VERSION 5.8 ;
BUSBITCHARS "[]" ;
DIVIDERCHAR "/" ;
UNITS
    DATABASE MICRONS 1000 ;
END UNITS

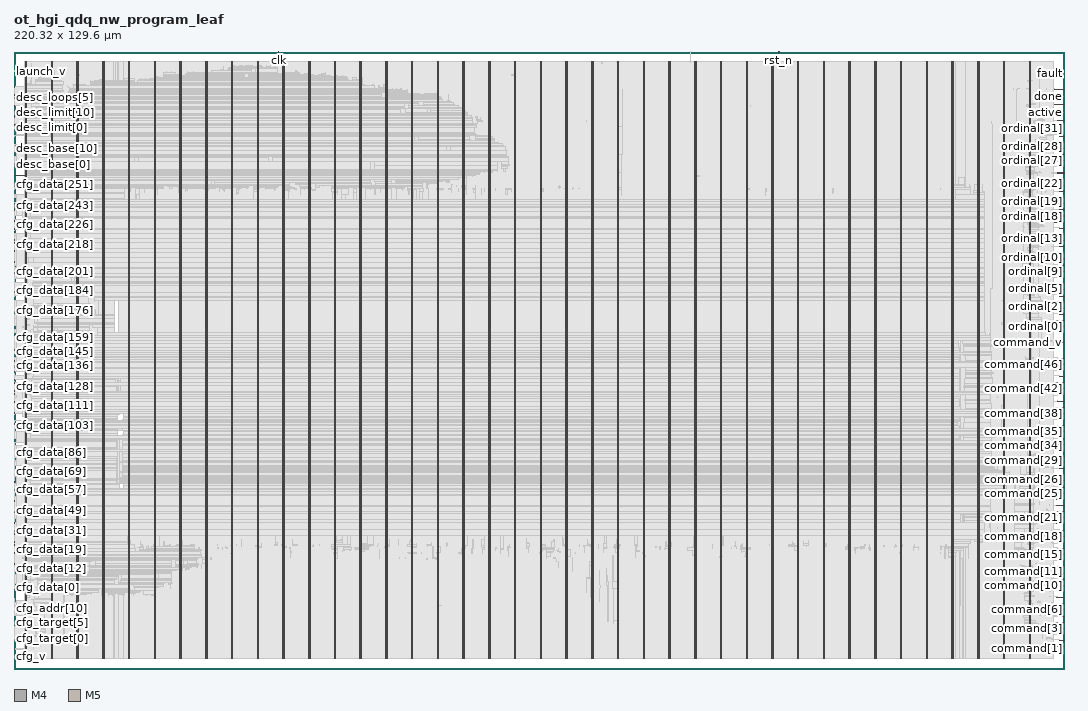
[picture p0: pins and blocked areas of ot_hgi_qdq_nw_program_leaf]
MACRO ot_hgi_qdq_nw_program_leaf
  FOREIGN ot_hgi_qdq_nw_program_leaf 0 0 ;
  CLASS BLOCK ;
  SIZE 220.32 BY 129.6 ;
  PIN active
    DIRECTION OUTPUT ;
    USE SIGNAL ;
    PORT
      LAYER M4 ;
        RECT  220.236 115.056 220.32 115.08 ;
    END
    PORT
      LAYER M4 ;
        RECT  218.869 115.056 220.284 115.08 ;
    END
  END active
  PIN cfg_addr[0]
    DIRECTION INPUT ;
    USE SIGNAL ;
    PORT
      LAYER M4 ;
        RECT  0 11.136 0.084 11.16 ;
    END
  END cfg_addr[0]
  PIN cfg_addr[10]
    DIRECTION INPUT ;
    USE SIGNAL ;
    PORT
      LAYER M4 ;
        RECT  0 14.4 0.084 14.424 ;
    END
  END cfg_addr[10]
  PIN cfg_addr[11]
    DIRECTION INPUT ;
    USE SIGNAL ;
    PORT
      LAYER M4 ;
        RECT  0 14.736 0.084 14.76 ;
    END
  END cfg_addr[11]
  PIN cfg_addr[1]
    DIRECTION INPUT ;
    USE SIGNAL ;
    PORT
      LAYER M4 ;
        RECT  0 11.472 0.084 11.496 ;
    END
  END cfg_addr[1]
  PIN cfg_addr[2]
    DIRECTION INPUT ;
    USE SIGNAL ;
    PORT
      LAYER M4 ;
        RECT  0 11.76 0.084 11.784 ;
    END
  END cfg_addr[2]
  PIN cfg_addr[3]
    DIRECTION INPUT ;
    USE SIGNAL ;
    PORT
      LAYER M4 ;
        RECT  0 12.096 0.084 12.12 ;
    END
  END cfg_addr[3]
  PIN cfg_addr[4]
    DIRECTION INPUT ;
    USE SIGNAL ;
    PORT
      LAYER M4 ;
        RECT  0 12.432 0.084 12.456 ;
    END
  END cfg_addr[4]
  PIN cfg_addr[5]
    DIRECTION INPUT ;
    USE SIGNAL ;
    PORT
      LAYER M4 ;
        RECT  0 12.768 0.084 12.792 ;
    END
  END cfg_addr[5]
  PIN cfg_addr[6]
    DIRECTION INPUT ;
    USE SIGNAL ;
    PORT
      LAYER M4 ;
        RECT  0 13.104 0.084 13.128 ;
    END
  END cfg_addr[6]
  PIN cfg_addr[7]
    DIRECTION INPUT ;
    USE SIGNAL ;
    PORT
      LAYER M4 ;
        RECT  0 13.44 0.084 13.464 ;
    END
  END cfg_addr[7]
  PIN cfg_addr[8]
    DIRECTION INPUT ;
    USE SIGNAL ;
    PORT
      LAYER M4 ;
        RECT  0 13.776 0.084 13.8 ;
    END
  END cfg_addr[8]
  PIN cfg_addr[9]
    DIRECTION INPUT ;
    USE SIGNAL ;
    PORT
      LAYER M4 ;
        RECT  0 14.112 0.084 14.136 ;
    END
  END cfg_addr[9]
  PIN cfg_data[0]
    DIRECTION INPUT ;
    USE SIGNAL ;
    PORT
      LAYER M4 ;
        RECT  0 17.088 0.084 17.112 ;
    END
  END cfg_data[0]
  PIN cfg_data[100]
    DIRECTION INPUT ;
    USE SIGNAL ;
    PORT
      LAYER M4 ;
        RECT  0 50.064 0.084 50.088 ;
    END
  END cfg_data[100]
  PIN cfg_data[101]
    DIRECTION INPUT ;
    USE SIGNAL ;
    PORT
      LAYER M4 ;
        RECT  0 50.4 0.084 50.424 ;
    END
  END cfg_data[101]
  PIN cfg_data[102]
    DIRECTION INPUT ;
    USE SIGNAL ;
    PORT
      LAYER M4 ;
        RECT  0 50.736 0.084 50.76 ;
    END
  END cfg_data[102]
  PIN cfg_data[103]
    DIRECTION INPUT ;
    USE SIGNAL ;
    PORT
      LAYER M4 ;
        RECT  0 51.072 0.084 51.096 ;
    END
  END cfg_data[103]
  PIN cfg_data[104]
    DIRECTION INPUT ;
    USE SIGNAL ;
    PORT
      LAYER M4 ;
        RECT  0 51.408 0.084 51.432 ;
    END
  END cfg_data[104]
  PIN cfg_data[105]
    DIRECTION INPUT ;
    USE SIGNAL ;
    PORT
      LAYER M4 ;
        RECT  0 51.744 0.084 51.768 ;
    END
  END cfg_data[105]
  PIN cfg_data[106]
    DIRECTION INPUT ;
    USE SIGNAL ;
    PORT
      LAYER M4 ;
        RECT  0 52.08 0.084 52.104 ;
    END
  END cfg_data[106]
  PIN cfg_data[107]
    DIRECTION INPUT ;
    USE SIGNAL ;
    PORT
      LAYER M4 ;
        RECT  0 52.416 0.084 52.44 ;
    END
  END cfg_data[107]
  PIN cfg_data[108]
    DIRECTION INPUT ;
    USE SIGNAL ;
    PORT
      LAYER M4 ;
        RECT  0 52.704 0.084 52.728 ;
    END
  END cfg_data[108]
  PIN cfg_data[109]
    DIRECTION INPUT ;
    USE SIGNAL ;
    PORT
      LAYER M4 ;
        RECT  0 53.04 0.084 53.064 ;
    END
  END cfg_data[109]
  PIN cfg_data[10]
    DIRECTION INPUT ;
    USE SIGNAL ;
    PORT
      LAYER M4 ;
        RECT  0 20.4 0.084 20.424 ;
    END
  END cfg_data[10]
  PIN cfg_data[110]
    DIRECTION INPUT ;
    USE SIGNAL ;
    PORT
      LAYER M4 ;
        RECT  0 53.376 0.084 53.4 ;
    END
  END cfg_data[110]
  PIN cfg_data[111]
    DIRECTION INPUT ;
    USE SIGNAL ;
    PORT
      LAYER M4 ;
        RECT  0 53.712 0.084 53.736 ;
    END
  END cfg_data[111]
  PIN cfg_data[112]
    DIRECTION INPUT ;
    USE SIGNAL ;
    PORT
      LAYER M4 ;
        RECT  0 54.048 0.084 54.072 ;
    END
  END cfg_data[112]
  PIN cfg_data[113]
    DIRECTION INPUT ;
    USE SIGNAL ;
    PORT
      LAYER M4 ;
        RECT  0 54.384 0.084 54.408 ;
    END
  END cfg_data[113]
  PIN cfg_data[114]
    DIRECTION INPUT ;
    USE SIGNAL ;
    PORT
      LAYER M4 ;
        RECT  0 54.72 0.084 54.744 ;
    END
  END cfg_data[114]
  PIN cfg_data[115]
    DIRECTION INPUT ;
    USE SIGNAL ;
    PORT
      LAYER M4 ;
        RECT  0 55.056 0.084 55.08 ;
    END
  END cfg_data[115]
  PIN cfg_data[116]
    DIRECTION INPUT ;
    USE SIGNAL ;
    PORT
      LAYER M4 ;
        RECT  0 55.344 0.084 55.368 ;
    END
  END cfg_data[116]
  PIN cfg_data[117]
    DIRECTION INPUT ;
    USE SIGNAL ;
    PORT
      LAYER M4 ;
        RECT  0 55.68 0.084 55.704 ;
    END
  END cfg_data[117]
  PIN cfg_data[118]
    DIRECTION INPUT ;
    USE SIGNAL ;
    PORT
      LAYER M4 ;
        RECT  0 56.016 0.084 56.04 ;
    END
  END cfg_data[118]
  PIN cfg_data[119]
    DIRECTION INPUT ;
    USE SIGNAL ;
    PORT
      LAYER M4 ;
        RECT  0 56.352 0.084 56.376 ;
    END
  END cfg_data[119]
  PIN cfg_data[11]
    DIRECTION INPUT ;
    USE SIGNAL ;
    PORT
      LAYER M4 ;
        RECT  0 20.736 0.084 20.76 ;
    END
  END cfg_data[11]
  PIN cfg_data[120]
    DIRECTION INPUT ;
    USE SIGNAL ;
    PORT
      LAYER M4 ;
        RECT  0 56.688 0.084 56.712 ;
    END
  END cfg_data[120]
  PIN cfg_data[121]
    DIRECTION INPUT ;
    USE SIGNAL ;
    PORT
      LAYER M4 ;
        RECT  0 57.024 0.084 57.048 ;
    END
  END cfg_data[121]
  PIN cfg_data[122]
    DIRECTION INPUT ;
    USE SIGNAL ;
    PORT
      LAYER M4 ;
        RECT  0 57.36 0.084 57.384 ;
    END
  END cfg_data[122]
  PIN cfg_data[123]
    DIRECTION INPUT ;
    USE SIGNAL ;
    PORT
      LAYER M4 ;
        RECT  0 57.696 0.084 57.72 ;
    END
  END cfg_data[123]
  PIN cfg_data[124]
    DIRECTION INPUT ;
    USE SIGNAL ;
    PORT
      LAYER M4 ;
        RECT  0 57.984 0.084 58.008 ;
    END
  END cfg_data[124]
  PIN cfg_data[125]
    DIRECTION INPUT ;
    USE SIGNAL ;
    PORT
      LAYER M4 ;
        RECT  0 58.32 0.084 58.344 ;
    END
  END cfg_data[125]
  PIN cfg_data[126]
    DIRECTION INPUT ;
    USE SIGNAL ;
    PORT
      LAYER M4 ;
        RECT  0 58.656 0.084 58.68 ;
    END
  END cfg_data[126]
  PIN cfg_data[127]
    DIRECTION INPUT ;
    USE SIGNAL ;
    PORT
      LAYER M4 ;
        RECT  0 58.992 0.084 59.016 ;
    END
  END cfg_data[127]
  PIN cfg_data[128]
    DIRECTION INPUT ;
    USE SIGNAL ;
    PORT
      LAYER M4 ;
        RECT  0 59.328 0.084 59.352 ;
    END
  END cfg_data[128]
  PIN cfg_data[129]
    DIRECTION INPUT ;
    USE SIGNAL ;
    PORT
      LAYER M4 ;
        RECT  0 59.664 0.084 59.688 ;
    END
  END cfg_data[129]
  PIN cfg_data[12]
    DIRECTION INPUT ;
    USE SIGNAL ;
    PORT
      LAYER M4 ;
        RECT  0 21.024 0.084 21.048 ;
    END
  END cfg_data[12]
  PIN cfg_data[130]
    DIRECTION INPUT ;
    USE SIGNAL ;
    PORT
      LAYER M4 ;
        RECT  0 60 0.084 60.024 ;
    END
  END cfg_data[130]
  PIN cfg_data[131]
    DIRECTION INPUT ;
    USE SIGNAL ;
    PORT
      LAYER M4 ;
        RECT  0 60.336 0.084 60.36 ;
    END
  END cfg_data[131]
  PIN cfg_data[132]
    DIRECTION INPUT ;
    USE SIGNAL ;
    PORT
      LAYER M4 ;
        RECT  0 60.624 0.084 60.648 ;
    END
  END cfg_data[132]
  PIN cfg_data[133]
    DIRECTION INPUT ;
    USE SIGNAL ;
    PORT
      LAYER M4 ;
        RECT  0 60.96 0.084 60.984 ;
    END
  END cfg_data[133]
  PIN cfg_data[134]
    DIRECTION INPUT ;
    USE SIGNAL ;
    PORT
      LAYER M4 ;
        RECT  0 61.296 0.084 61.32 ;
    END
  END cfg_data[134]
  PIN cfg_data[135]
    DIRECTION INPUT ;
    USE SIGNAL ;
    PORT
      LAYER M4 ;
        RECT  0 61.632 0.084 61.656 ;
    END
  END cfg_data[135]
  PIN cfg_data[136]
    DIRECTION INPUT ;
    USE SIGNAL ;
    PORT
      LAYER M4 ;
        RECT  0 61.968 0.084 61.992 ;
    END
  END cfg_data[136]
  PIN cfg_data[137]
    DIRECTION INPUT ;
    USE SIGNAL ;
    PORT
      LAYER M4 ;
        RECT  0 62.304 0.084 62.328 ;
    END
  END cfg_data[137]
  PIN cfg_data[138]
    DIRECTION INPUT ;
    USE SIGNAL ;
    PORT
      LAYER M4 ;
        RECT  0 62.64 0.084 62.664 ;
    END
  END cfg_data[138]
  PIN cfg_data[139]
    DIRECTION INPUT ;
    USE SIGNAL ;
    PORT
      LAYER M4 ;
        RECT  0 62.976 0.084 63 ;
    END
  END cfg_data[139]
  PIN cfg_data[13]
    DIRECTION INPUT ;
    USE SIGNAL ;
    PORT
      LAYER M4 ;
        RECT  0 21.36 0.084 21.384 ;
    END
  END cfg_data[13]
  PIN cfg_data[140]
    DIRECTION INPUT ;
    USE SIGNAL ;
    PORT
      LAYER M4 ;
        RECT  0 63.264 0.084 63.288 ;
    END
  END cfg_data[140]
  PIN cfg_data[141]
    DIRECTION INPUT ;
    USE SIGNAL ;
    PORT
      LAYER M4 ;
        RECT  0 63.6 0.084 63.624 ;
    END
  END cfg_data[141]
  PIN cfg_data[142]
    DIRECTION INPUT ;
    USE SIGNAL ;
    PORT
      LAYER M4 ;
        RECT  0 63.936 0.084 63.96 ;
    END
  END cfg_data[142]
  PIN cfg_data[143]
    DIRECTION INPUT ;
    USE SIGNAL ;
    PORT
      LAYER M4 ;
        RECT  0 64.272 0.084 64.296 ;
    END
  END cfg_data[143]
  PIN cfg_data[144]
    DIRECTION INPUT ;
    USE SIGNAL ;
    PORT
      LAYER M4 ;
        RECT  0 64.608 0.084 64.632 ;
    END
  END cfg_data[144]
  PIN cfg_data[145]
    DIRECTION INPUT ;
    USE SIGNAL ;
    PORT
      LAYER M4 ;
        RECT  0 64.944 0.084 64.968 ;
    END
  END cfg_data[145]
  PIN cfg_data[146]
    DIRECTION INPUT ;
    USE SIGNAL ;
    PORT
      LAYER M4 ;
        RECT  0 65.28 0.084 65.304 ;
    END
  END cfg_data[146]
  PIN cfg_data[147]
    DIRECTION INPUT ;
    USE SIGNAL ;
    PORT
      LAYER M4 ;
        RECT  0 65.616 0.084 65.64 ;
    END
  END cfg_data[147]
  PIN cfg_data[148]
    DIRECTION INPUT ;
    USE SIGNAL ;
    PORT
      LAYER M4 ;
        RECT  0 65.904 0.084 65.928 ;
    END
  END cfg_data[148]
  PIN cfg_data[149]
    DIRECTION INPUT ;
    USE SIGNAL ;
    PORT
      LAYER M4 ;
        RECT  0 66.24 0.084 66.264 ;
    END
  END cfg_data[149]
  PIN cfg_data[14]
    DIRECTION INPUT ;
    USE SIGNAL ;
    PORT
      LAYER M4 ;
        RECT  0 21.696 0.084 21.72 ;
    END
  END cfg_data[14]
  PIN cfg_data[150]
    DIRECTION INPUT ;
    USE SIGNAL ;
    PORT
      LAYER M4 ;
        RECT  0 66.576 0.084 66.6 ;
    END
  END cfg_data[150]
  PIN cfg_data[151]
    DIRECTION INPUT ;
    USE SIGNAL ;
    PORT
      LAYER M4 ;
        RECT  0 66.912 0.084 66.936 ;
    END
  END cfg_data[151]
  PIN cfg_data[152]
    DIRECTION INPUT ;
    USE SIGNAL ;
    PORT
      LAYER M4 ;
        RECT  0 67.248 0.084 67.272 ;
    END
  END cfg_data[152]
  PIN cfg_data[153]
    DIRECTION INPUT ;
    USE SIGNAL ;
    PORT
      LAYER M4 ;
        RECT  0 67.584 0.084 67.608 ;
    END
  END cfg_data[153]
  PIN cfg_data[154]
    DIRECTION INPUT ;
    USE SIGNAL ;
    PORT
      LAYER M4 ;
        RECT  0 67.92 0.084 67.944 ;
    END
  END cfg_data[154]
  PIN cfg_data[155]
    DIRECTION INPUT ;
    USE SIGNAL ;
    PORT
      LAYER M4 ;
        RECT  0 68.256 0.084 68.28 ;
    END
  END cfg_data[155]
  PIN cfg_data[156]
    DIRECTION INPUT ;
    USE SIGNAL ;
    PORT
      LAYER M4 ;
        RECT  0 68.544 0.084 68.568 ;
    END
  END cfg_data[156]
  PIN cfg_data[157]
    DIRECTION INPUT ;
    USE SIGNAL ;
    PORT
      LAYER M4 ;
        RECT  0 68.88 0.084 68.904 ;
    END
  END cfg_data[157]
  PIN cfg_data[158]
    DIRECTION INPUT ;
    USE SIGNAL ;
    PORT
      LAYER M4 ;
        RECT  0 69.216 0.084 69.24 ;
    END
  END cfg_data[158]
  PIN cfg_data[159]
    DIRECTION INPUT ;
    USE SIGNAL ;
    PORT
      LAYER M4 ;
        RECT  0 69.552 0.084 69.576 ;
    END
  END cfg_data[159]
  PIN cfg_data[15]
    DIRECTION INPUT ;
    USE SIGNAL ;
    PORT
      LAYER M4 ;
        RECT  0 22.032 0.084 22.056 ;
    END
  END cfg_data[15]
  PIN cfg_data[160]
    DIRECTION INPUT ;
    USE SIGNAL ;
    PORT
      LAYER M4 ;
        RECT  0 69.888 0.084 69.912 ;
    END
  END cfg_data[160]
  PIN cfg_data[161]
    DIRECTION INPUT ;
    USE SIGNAL ;
    PORT
      LAYER M4 ;
        RECT  0 70.224 0.084 70.248 ;
    END
  END cfg_data[161]
  PIN cfg_data[162]
    DIRECTION INPUT ;
    USE SIGNAL ;
    PORT
      LAYER M4 ;
        RECT  0 70.56 0.084 70.584 ;
    END
  END cfg_data[162]
  PIN cfg_data[163]
    DIRECTION INPUT ;
    USE SIGNAL ;
    PORT
      LAYER M4 ;
        RECT  0 70.896 0.084 70.92 ;
    END
  END cfg_data[163]
  PIN cfg_data[164]
    DIRECTION INPUT ;
    USE SIGNAL ;
    PORT
      LAYER M4 ;
        RECT  0 71.184 0.084 71.208 ;
    END
  END cfg_data[164]
  PIN cfg_data[165]
    DIRECTION INPUT ;
    USE SIGNAL ;
    PORT
      LAYER M4 ;
        RECT  0 71.52 0.084 71.544 ;
    END
  END cfg_data[165]
  PIN cfg_data[166]
    DIRECTION INPUT ;
    USE SIGNAL ;
    PORT
      LAYER M4 ;
        RECT  0 71.856 0.084 71.88 ;
    END
  END cfg_data[166]
  PIN cfg_data[167]
    DIRECTION INPUT ;
    USE SIGNAL ;
    PORT
      LAYER M4 ;
        RECT  0 72.192 0.084 72.216 ;
    END
  END cfg_data[167]
  PIN cfg_data[168]
    DIRECTION INPUT ;
    USE SIGNAL ;
    PORT
      LAYER M4 ;
        RECT  0 72.528 0.084 72.552 ;
    END
  END cfg_data[168]
  PIN cfg_data[169]
    DIRECTION INPUT ;
    USE SIGNAL ;
    PORT
      LAYER M4 ;
        RECT  0 72.864 0.084 72.888 ;
    END
  END cfg_data[169]
  PIN cfg_data[16]
    DIRECTION INPUT ;
    USE SIGNAL ;
    PORT
      LAYER M4 ;
        RECT  0 22.368 0.084 22.392 ;
    END
  END cfg_data[16]
  PIN cfg_data[170]
    DIRECTION INPUT ;
    USE SIGNAL ;
    PORT
      LAYER M4 ;
        RECT  0 73.2 0.084 73.224 ;
    END
  END cfg_data[170]
  PIN cfg_data[171]
    DIRECTION INPUT ;
    USE SIGNAL ;
    PORT
      LAYER M4 ;
        RECT  0 73.536 0.084 73.56 ;
    END
  END cfg_data[171]
  PIN cfg_data[172]
    DIRECTION INPUT ;
    USE SIGNAL ;
    PORT
      LAYER M4 ;
        RECT  0 73.824 0.084 73.848 ;
    END
  END cfg_data[172]
  PIN cfg_data[173]
    DIRECTION INPUT ;
    USE SIGNAL ;
    PORT
      LAYER M4 ;
        RECT  0 74.16 0.084 74.184 ;
    END
  END cfg_data[173]
  PIN cfg_data[174]
    DIRECTION INPUT ;
    USE SIGNAL ;
    PORT
      LAYER M4 ;
        RECT  0 74.496 0.084 74.52 ;
    END
  END cfg_data[174]
  PIN cfg_data[175]
    DIRECTION INPUT ;
    USE SIGNAL ;
    PORT
      LAYER M4 ;
        RECT  0 74.832 0.084 74.856 ;
    END
  END cfg_data[175]
  PIN cfg_data[176]
    DIRECTION INPUT ;
    USE SIGNAL ;
    PORT
      LAYER M4 ;
        RECT  0 75.168 0.084 75.192 ;
    END
  END cfg_data[176]
  PIN cfg_data[177]
    DIRECTION INPUT ;
    USE SIGNAL ;
    PORT
      LAYER M4 ;
        RECT  0 75.504 0.084 75.528 ;
    END
  END cfg_data[177]
  PIN cfg_data[178]
    DIRECTION INPUT ;
    USE SIGNAL ;
    PORT
      LAYER M4 ;
        RECT  0 75.84 0.084 75.864 ;
    END
  END cfg_data[178]
  PIN cfg_data[179]
    DIRECTION INPUT ;
    USE SIGNAL ;
    PORT
      LAYER M4 ;
        RECT  0 76.176 0.084 76.2 ;
    END
  END cfg_data[179]
  PIN cfg_data[17]
    DIRECTION INPUT ;
    USE SIGNAL ;
    PORT
      LAYER M4 ;
        RECT  0 22.704 0.084 22.728 ;
    END
  END cfg_data[17]
  PIN cfg_data[180]
    DIRECTION INPUT ;
    USE SIGNAL ;
    PORT
      LAYER M4 ;
        RECT  0 76.464 0.084 76.488 ;
    END
  END cfg_data[180]
  PIN cfg_data[181]
    DIRECTION INPUT ;
    USE SIGNAL ;
    PORT
      LAYER M4 ;
        RECT  0 76.8 0.084 76.824 ;
    END
  END cfg_data[181]
  PIN cfg_data[182]
    DIRECTION INPUT ;
    USE SIGNAL ;
    PORT
      LAYER M4 ;
        RECT  0 77.136 0.084 77.16 ;
    END
  END cfg_data[182]
  PIN cfg_data[183]
    DIRECTION INPUT ;
    USE SIGNAL ;
    PORT
      LAYER M4 ;
        RECT  0 77.472 0.084 77.496 ;
    END
  END cfg_data[183]
  PIN cfg_data[184]
    DIRECTION INPUT ;
    USE SIGNAL ;
    PORT
      LAYER M4 ;
        RECT  0 77.808 0.084 77.832 ;
    END
  END cfg_data[184]
  PIN cfg_data[185]
    DIRECTION INPUT ;
    USE SIGNAL ;
    PORT
      LAYER M4 ;
        RECT  0 78.144 0.084 78.168 ;
    END
  END cfg_data[185]
  PIN cfg_data[186]
    DIRECTION INPUT ;
    USE SIGNAL ;
    PORT
      LAYER M4 ;
        RECT  0 78.48 0.084 78.504 ;
    END
  END cfg_data[186]
  PIN cfg_data[187]
    DIRECTION INPUT ;
    USE SIGNAL ;
    PORT
      LAYER M4 ;
        RECT  0 78.816 0.084 78.84 ;
    END
  END cfg_data[187]
  PIN cfg_data[188]
    DIRECTION INPUT ;
    USE SIGNAL ;
    PORT
      LAYER M4 ;
        RECT  0 79.104 0.084 79.128 ;
    END
  END cfg_data[188]
  PIN cfg_data[189]
    DIRECTION INPUT ;
    USE SIGNAL ;
    PORT
      LAYER M4 ;
        RECT  0 79.44 0.084 79.464 ;
    END
  END cfg_data[189]
  PIN cfg_data[18]
    DIRECTION INPUT ;
    USE SIGNAL ;
    PORT
      LAYER M4 ;
        RECT  0 23.04 0.084 23.064 ;
    END
  END cfg_data[18]
  PIN cfg_data[190]
    DIRECTION INPUT ;
    USE SIGNAL ;
    PORT
      LAYER M4 ;
        RECT  0 79.776 0.084 79.8 ;
    END
  END cfg_data[190]
  PIN cfg_data[191]
    DIRECTION INPUT ;
    USE SIGNAL ;
    PORT
      LAYER M4 ;
        RECT  0 80.112 0.084 80.136 ;
    END
  END cfg_data[191]
  PIN cfg_data[192]
    DIRECTION INPUT ;
    USE SIGNAL ;
    PORT
      LAYER M4 ;
        RECT  0 80.448 0.084 80.472 ;
    END
  END cfg_data[192]
  PIN cfg_data[193]
    DIRECTION INPUT ;
    USE SIGNAL ;
    PORT
      LAYER M4 ;
        RECT  0 80.784 0.084 80.808 ;
    END
  END cfg_data[193]
  PIN cfg_data[194]
    DIRECTION INPUT ;
    USE SIGNAL ;
    PORT
      LAYER M4 ;
        RECT  0 81.12 0.084 81.144 ;
    END
  END cfg_data[194]
  PIN cfg_data[195]
    DIRECTION INPUT ;
    USE SIGNAL ;
    PORT
      LAYER M4 ;
        RECT  0 81.456 0.084 81.48 ;
    END
  END cfg_data[195]
  PIN cfg_data[196]
    DIRECTION INPUT ;
    USE SIGNAL ;
    PORT
      LAYER M4 ;
        RECT  0 81.744 0.084 81.768 ;
    END
  END cfg_data[196]
  PIN cfg_data[197]
    DIRECTION INPUT ;
    USE SIGNAL ;
    PORT
      LAYER M4 ;
        RECT  0 82.08 0.084 82.104 ;
    END
  END cfg_data[197]
  PIN cfg_data[198]
    DIRECTION INPUT ;
    USE SIGNAL ;
    PORT
      LAYER M4 ;
        RECT  0 82.416 0.084 82.44 ;
    END
  END cfg_data[198]
  PIN cfg_data[199]
    DIRECTION INPUT ;
    USE SIGNAL ;
    PORT
      LAYER M4 ;
        RECT  0 82.752 0.084 82.776 ;
    END
  END cfg_data[199]
  PIN cfg_data[19]
    DIRECTION INPUT ;
    USE SIGNAL ;
    PORT
      LAYER M4 ;
        RECT  0 23.376 0.084 23.4 ;
    END
  END cfg_data[19]
  PIN cfg_data[1]
    DIRECTION INPUT ;
    USE SIGNAL ;
    PORT
      LAYER M4 ;
        RECT  0 17.424 0.084 17.448 ;
    END
  END cfg_data[1]
  PIN cfg_data[200]
    DIRECTION INPUT ;
    USE SIGNAL ;
    PORT
      LAYER M4 ;
        RECT  0 83.088 0.084 83.112 ;
    END
  END cfg_data[200]
  PIN cfg_data[201]
    DIRECTION INPUT ;
    USE SIGNAL ;
    PORT
      LAYER M4 ;
        RECT  0 83.424 0.084 83.448 ;
    END
  END cfg_data[201]
  PIN cfg_data[202]
    DIRECTION INPUT ;
    USE SIGNAL ;
    PORT
      LAYER M4 ;
        RECT  0 83.76 0.084 83.784 ;
    END
  END cfg_data[202]
  PIN cfg_data[203]
    DIRECTION INPUT ;
    USE SIGNAL ;
    PORT
      LAYER M4 ;
        RECT  0 84.096 0.084 84.12 ;
    END
  END cfg_data[203]
  PIN cfg_data[204]
    DIRECTION INPUT ;
    USE SIGNAL ;
    PORT
      LAYER M4 ;
        RECT  0 84.384 0.084 84.408 ;
    END
  END cfg_data[204]
  PIN cfg_data[205]
    DIRECTION INPUT ;
    USE SIGNAL ;
    PORT
      LAYER M4 ;
        RECT  0 84.72 0.084 84.744 ;
    END
  END cfg_data[205]
  PIN cfg_data[206]
    DIRECTION INPUT ;
    USE SIGNAL ;
    PORT
      LAYER M4 ;
        RECT  0 85.056 0.084 85.08 ;
    END
  END cfg_data[206]
  PIN cfg_data[207]
    DIRECTION INPUT ;
    USE SIGNAL ;
    PORT
      LAYER M4 ;
        RECT  0 85.392 0.084 85.416 ;
    END
  END cfg_data[207]
  PIN cfg_data[208]
    DIRECTION INPUT ;
    USE SIGNAL ;
    PORT
      LAYER M4 ;
        RECT  0 85.728 0.084 85.752 ;
    END
  END cfg_data[208]
  PIN cfg_data[209]
    DIRECTION INPUT ;
    USE SIGNAL ;
    PORT
      LAYER M4 ;
        RECT  0 86.064 0.084 86.088 ;
    END
  END cfg_data[209]
  PIN cfg_data[20]
    DIRECTION INPUT ;
    USE SIGNAL ;
    PORT
      LAYER M4 ;
        RECT  0 23.664 0.084 23.688 ;
    END
  END cfg_data[20]
  PIN cfg_data[210]
    DIRECTION INPUT ;
    USE SIGNAL ;
    PORT
      LAYER M4 ;
        RECT  0 86.4 0.084 86.424 ;
    END
  END cfg_data[210]
  PIN cfg_data[211]
    DIRECTION INPUT ;
    USE SIGNAL ;
    PORT
      LAYER M4 ;
        RECT  0 86.736 0.084 86.76 ;
    END
  END cfg_data[211]
  PIN cfg_data[212]
    DIRECTION INPUT ;
    USE SIGNAL ;
    PORT
      LAYER M4 ;
        RECT  0 87.024 0.084 87.048 ;
    END
  END cfg_data[212]
  PIN cfg_data[213]
    DIRECTION INPUT ;
    USE SIGNAL ;
    PORT
      LAYER M4 ;
        RECT  0 87.36 0.084 87.384 ;
    END
  END cfg_data[213]
  PIN cfg_data[214]
    DIRECTION INPUT ;
    USE SIGNAL ;
    PORT
      LAYER M4 ;
        RECT  0 87.696 0.084 87.72 ;
    END
  END cfg_data[214]
  PIN cfg_data[215]
    DIRECTION INPUT ;
    USE SIGNAL ;
    PORT
      LAYER M4 ;
        RECT  0 88.032 0.084 88.056 ;
    END
  END cfg_data[215]
  PIN cfg_data[216]
    DIRECTION INPUT ;
    USE SIGNAL ;
    PORT
      LAYER M4 ;
        RECT  0 88.368 0.084 88.392 ;
    END
  END cfg_data[216]
  PIN cfg_data[217]
    DIRECTION INPUT ;
    USE SIGNAL ;
    PORT
      LAYER M4 ;
        RECT  0 88.704 0.084 88.728 ;
    END
  END cfg_data[217]
  PIN cfg_data[218]
    DIRECTION INPUT ;
    USE SIGNAL ;
    PORT
      LAYER M4 ;
        RECT  0 89.04 0.084 89.064 ;
    END
  END cfg_data[218]
  PIN cfg_data[219]
    DIRECTION INPUT ;
    USE SIGNAL ;
    PORT
      LAYER M4 ;
        RECT  0 89.376 0.084 89.4 ;
    END
  END cfg_data[219]
  PIN cfg_data[21]
    DIRECTION INPUT ;
    USE SIGNAL ;
    PORT
      LAYER M4 ;
        RECT  0 24 0.084 24.024 ;
    END
  END cfg_data[21]
  PIN cfg_data[220]
    DIRECTION INPUT ;
    USE SIGNAL ;
    PORT
      LAYER M4 ;
        RECT  0 89.664 0.084 89.688 ;
    END
  END cfg_data[220]
  PIN cfg_data[221]
    DIRECTION INPUT ;
    USE SIGNAL ;
    PORT
      LAYER M4 ;
        RECT  0 90 0.084 90.024 ;
    END
  END cfg_data[221]
  PIN cfg_data[222]
    DIRECTION INPUT ;
    USE SIGNAL ;
    PORT
      LAYER M4 ;
        RECT  0 90.336 0.084 90.36 ;
    END
  END cfg_data[222]
  PIN cfg_data[223]
    DIRECTION INPUT ;
    USE SIGNAL ;
    PORT
      LAYER M4 ;
        RECT  0 90.672 0.084 90.696 ;
    END
  END cfg_data[223]
  PIN cfg_data[224]
    DIRECTION INPUT ;
    USE SIGNAL ;
    PORT
      LAYER M4 ;
        RECT  0 91.008 0.084 91.032 ;
    END
  END cfg_data[224]
  PIN cfg_data[225]
    DIRECTION INPUT ;
    USE SIGNAL ;
    PORT
      LAYER M4 ;
        RECT  0 91.344 0.084 91.368 ;
    END
  END cfg_data[225]
  PIN cfg_data[226]
    DIRECTION INPUT ;
    USE SIGNAL ;
    PORT
      LAYER M4 ;
        RECT  0 91.68 0.084 91.704 ;
    END
  END cfg_data[226]
  PIN cfg_data[227]
    DIRECTION INPUT ;
    USE SIGNAL ;
    PORT
      LAYER M4 ;
        RECT  0 92.016 0.084 92.04 ;
    END
  END cfg_data[227]
  PIN cfg_data[228]
    DIRECTION INPUT ;
    USE SIGNAL ;
    PORT
      LAYER M4 ;
        RECT  0 92.304 0.084 92.328 ;
    END
  END cfg_data[228]
  PIN cfg_data[229]
    DIRECTION INPUT ;
    USE SIGNAL ;
    PORT
      LAYER M4 ;
        RECT  0 92.64 0.084 92.664 ;
    END
  END cfg_data[229]
  PIN cfg_data[22]
    DIRECTION INPUT ;
    USE SIGNAL ;
    PORT
      LAYER M4 ;
        RECT  0 24.336 0.084 24.36 ;
    END
  END cfg_data[22]
  PIN cfg_data[230]
    DIRECTION INPUT ;
    USE SIGNAL ;
    PORT
      LAYER M4 ;
        RECT  0 92.976 0.084 93 ;
    END
  END cfg_data[230]
  PIN cfg_data[231]
    DIRECTION INPUT ;
    USE SIGNAL ;
    PORT
      LAYER M4 ;
        RECT  0 93.312 0.084 93.336 ;
    END
  END cfg_data[231]
  PIN cfg_data[232]
    DIRECTION INPUT ;
    USE SIGNAL ;
    PORT
      LAYER M4 ;
        RECT  0 93.648 0.084 93.672 ;
    END
  END cfg_data[232]
  PIN cfg_data[233]
    DIRECTION INPUT ;
    USE SIGNAL ;
    PORT
      LAYER M4 ;
        RECT  0 93.984 0.084 94.008 ;
    END
  END cfg_data[233]
  PIN cfg_data[234]
    DIRECTION INPUT ;
    USE SIGNAL ;
    PORT
      LAYER M4 ;
        RECT  0 94.32 0.084 94.344 ;
    END
  END cfg_data[234]
  PIN cfg_data[235]
    DIRECTION INPUT ;
    USE SIGNAL ;
    PORT
      LAYER M4 ;
        RECT  0 94.656 0.084 94.68 ;
    END
  END cfg_data[235]
  PIN cfg_data[236]
    DIRECTION INPUT ;
    USE SIGNAL ;
    PORT
      LAYER M4 ;
        RECT  0 94.944 0.084 94.968 ;
    END
  END cfg_data[236]
  PIN cfg_data[237]
    DIRECTION INPUT ;
    USE SIGNAL ;
    PORT
      LAYER M4 ;
        RECT  0 95.28 0.084 95.304 ;
    END
  END cfg_data[237]
  PIN cfg_data[238]
    DIRECTION INPUT ;
    USE SIGNAL ;
    PORT
      LAYER M4 ;
        RECT  0 95.616 0.084 95.64 ;
    END
  END cfg_data[238]
  PIN cfg_data[239]
    DIRECTION INPUT ;
    USE SIGNAL ;
    PORT
      LAYER M4 ;
        RECT  0 95.952 0.084 95.976 ;
    END
  END cfg_data[239]
  PIN cfg_data[23]
    DIRECTION INPUT ;
    USE SIGNAL ;
    PORT
      LAYER M4 ;
        RECT  0 24.672 0.084 24.696 ;
    END
  END cfg_data[23]
  PIN cfg_data[240]
    DIRECTION INPUT ;
    USE SIGNAL ;
    PORT
      LAYER M4 ;
        RECT  0 96.288 0.084 96.312 ;
    END
  END cfg_data[240]
  PIN cfg_data[241]
    DIRECTION INPUT ;
    USE SIGNAL ;
    PORT
      LAYER M4 ;
        RECT  0 96.624 0.084 96.648 ;
    END
  END cfg_data[241]
  PIN cfg_data[242]
    DIRECTION INPUT ;
    USE SIGNAL ;
    PORT
      LAYER M4 ;
        RECT  0 96.96 0.084 96.984 ;
    END
  END cfg_data[242]
  PIN cfg_data[243]
    DIRECTION INPUT ;
    USE SIGNAL ;
    PORT
      LAYER M4 ;
        RECT  0 97.296 0.084 97.32 ;
    END
  END cfg_data[243]
  PIN cfg_data[244]
    DIRECTION INPUT ;
    USE SIGNAL ;
    PORT
      LAYER M4 ;
        RECT  0 97.584 0.084 97.608 ;
    END
  END cfg_data[244]
  PIN cfg_data[245]
    DIRECTION INPUT ;
    USE SIGNAL ;
    PORT
      LAYER M4 ;
        RECT  0 97.92 0.084 97.944 ;
    END
  END cfg_data[245]
  PIN cfg_data[246]
    DIRECTION INPUT ;
    USE SIGNAL ;
    PORT
      LAYER M4 ;
        RECT  0 98.256 0.084 98.28 ;
    END
  END cfg_data[246]
  PIN cfg_data[247]
    DIRECTION INPUT ;
    USE SIGNAL ;
    PORT
      LAYER M4 ;
        RECT  0 98.592 0.084 98.616 ;
    END
  END cfg_data[247]
  PIN cfg_data[248]
    DIRECTION INPUT ;
    USE SIGNAL ;
    PORT
      LAYER M4 ;
        RECT  0 98.928 0.084 98.952 ;
    END
  END cfg_data[248]
  PIN cfg_data[249]
    DIRECTION INPUT ;
    USE SIGNAL ;
    PORT
      LAYER M4 ;
        RECT  0 99.264 0.084 99.288 ;
    END
  END cfg_data[249]
  PIN cfg_data[24]
    DIRECTION INPUT ;
    USE SIGNAL ;
    PORT
      LAYER M4 ;
        RECT  0 25.008 0.084 25.032 ;
    END
  END cfg_data[24]
  PIN cfg_data[250]
    DIRECTION INPUT ;
    USE SIGNAL ;
    PORT
      LAYER M4 ;
        RECT  0 99.6 0.084 99.624 ;
    END
  END cfg_data[250]
  PIN cfg_data[251]
    DIRECTION INPUT ;
    USE SIGNAL ;
    PORT
      LAYER M4 ;
        RECT  0 99.936 0.084 99.96 ;
    END
  END cfg_data[251]
  PIN cfg_data[252]
    DIRECTION INPUT ;
    USE SIGNAL ;
    PORT
      LAYER M4 ;
        RECT  0 100.224 0.084 100.248 ;
    END
  END cfg_data[252]
  PIN cfg_data[253]
    DIRECTION INPUT ;
    USE SIGNAL ;
    PORT
      LAYER M4 ;
        RECT  0 100.56 0.084 100.584 ;
    END
  END cfg_data[253]
  PIN cfg_data[254]
    DIRECTION INPUT ;
    USE SIGNAL ;
    PORT
      LAYER M4 ;
        RECT  0 100.896 0.084 100.92 ;
    END
  END cfg_data[254]
  PIN cfg_data[255]
    DIRECTION INPUT ;
    USE SIGNAL ;
    PORT
      LAYER M4 ;
        RECT  0 101.232 0.084 101.256 ;
    END
  END cfg_data[255]
  PIN cfg_data[25]
    DIRECTION INPUT ;
    USE SIGNAL ;
    PORT
      LAYER M4 ;
        RECT  0 25.344 0.084 25.368 ;
    END
  END cfg_data[25]
  PIN cfg_data[26]
    DIRECTION INPUT ;
    USE SIGNAL ;
    PORT
      LAYER M4 ;
        RECT  0 25.68 0.084 25.704 ;
    END
  END cfg_data[26]
  PIN cfg_data[27]
    DIRECTION INPUT ;
    USE SIGNAL ;
    PORT
      LAYER M4 ;
        RECT  0 26.016 0.084 26.04 ;
    END
  END cfg_data[27]
  PIN cfg_data[28]
    DIRECTION INPUT ;
    USE SIGNAL ;
    PORT
      LAYER M4 ;
        RECT  0 26.304 0.084 26.328 ;
    END
  END cfg_data[28]
  PIN cfg_data[29]
    DIRECTION INPUT ;
    USE SIGNAL ;
    PORT
      LAYER M4 ;
        RECT  0 26.64 0.084 26.664 ;
    END
  END cfg_data[29]
  PIN cfg_data[2]
    DIRECTION INPUT ;
    USE SIGNAL ;
    PORT
      LAYER M4 ;
        RECT  0 17.76 0.084 17.784 ;
    END
  END cfg_data[2]
  PIN cfg_data[30]
    DIRECTION INPUT ;
    USE SIGNAL ;
    PORT
      LAYER M4 ;
        RECT  0 26.976 0.084 27 ;
    END
  END cfg_data[30]
  PIN cfg_data[31]
    DIRECTION INPUT ;
    USE SIGNAL ;
    PORT
      LAYER M4 ;
        RECT  0 27.312 0.084 27.336 ;
    END
  END cfg_data[31]
  PIN cfg_data[32]
    DIRECTION INPUT ;
    USE SIGNAL ;
    PORT
      LAYER M4 ;
        RECT  0 27.648 0.084 27.672 ;
    END
  END cfg_data[32]
  PIN cfg_data[33]
    DIRECTION INPUT ;
    USE SIGNAL ;
    PORT
      LAYER M4 ;
        RECT  0 27.984 0.084 28.008 ;
    END
  END cfg_data[33]
  PIN cfg_data[34]
    DIRECTION INPUT ;
    USE SIGNAL ;
    PORT
      LAYER M4 ;
        RECT  0 28.32 0.084 28.344 ;
    END
  END cfg_data[34]
  PIN cfg_data[35]
    DIRECTION INPUT ;
    USE SIGNAL ;
    PORT
      LAYER M4 ;
        RECT  0 28.656 0.084 28.68 ;
    END
  END cfg_data[35]
  PIN cfg_data[36]
    DIRECTION INPUT ;
    USE SIGNAL ;
    PORT
      LAYER M4 ;
        RECT  0 28.944 0.084 28.968 ;
    END
  END cfg_data[36]
  PIN cfg_data[37]
    DIRECTION INPUT ;
    USE SIGNAL ;
    PORT
      LAYER M4 ;
        RECT  0 29.28 0.084 29.304 ;
    END
  END cfg_data[37]
  PIN cfg_data[38]
    DIRECTION INPUT ;
    USE SIGNAL ;
    PORT
      LAYER M4 ;
        RECT  0 29.616 0.084 29.64 ;
    END
  END cfg_data[38]
  PIN cfg_data[39]
    DIRECTION INPUT ;
    USE SIGNAL ;
    PORT
      LAYER M4 ;
        RECT  0 29.952 0.084 29.976 ;
    END
  END cfg_data[39]
  PIN cfg_data[3]
    DIRECTION INPUT ;
    USE SIGNAL ;
    PORT
      LAYER M4 ;
        RECT  0 18.096 0.084 18.12 ;
    END
  END cfg_data[3]
  PIN cfg_data[40]
    DIRECTION INPUT ;
    USE SIGNAL ;
    PORT
      LAYER M4 ;
        RECT  0 30.288 0.084 30.312 ;
    END
  END cfg_data[40]
  PIN cfg_data[41]
    DIRECTION INPUT ;
    USE SIGNAL ;
    PORT
      LAYER M4 ;
        RECT  0 30.624 0.084 30.648 ;
    END
  END cfg_data[41]
  PIN cfg_data[42]
    DIRECTION INPUT ;
    USE SIGNAL ;
    PORT
      LAYER M4 ;
        RECT  0 30.96 0.084 30.984 ;
    END
  END cfg_data[42]
  PIN cfg_data[43]
    DIRECTION INPUT ;
    USE SIGNAL ;
    PORT
      LAYER M4 ;
        RECT  0 31.296 0.084 31.32 ;
    END
  END cfg_data[43]
  PIN cfg_data[44]
    DIRECTION INPUT ;
    USE SIGNAL ;
    PORT
      LAYER M4 ;
        RECT  0 31.584 0.084 31.608 ;
    END
  END cfg_data[44]
  PIN cfg_data[45]
    DIRECTION INPUT ;
    USE SIGNAL ;
    PORT
      LAYER M4 ;
        RECT  0 31.92 0.084 31.944 ;
    END
  END cfg_data[45]
  PIN cfg_data[46]
    DIRECTION INPUT ;
    USE SIGNAL ;
    PORT
      LAYER M4 ;
        RECT  0 32.256 0.084 32.28 ;
    END
  END cfg_data[46]
  PIN cfg_data[47]
    DIRECTION INPUT ;
    USE SIGNAL ;
    PORT
      LAYER M4 ;
        RECT  0 32.592 0.084 32.616 ;
    END
  END cfg_data[47]
  PIN cfg_data[48]
    DIRECTION INPUT ;
    USE SIGNAL ;
    PORT
      LAYER M4 ;
        RECT  0 32.928 0.084 32.952 ;
    END
  END cfg_data[48]
  PIN cfg_data[49]
    DIRECTION INPUT ;
    USE SIGNAL ;
    PORT
      LAYER M4 ;
        RECT  0 33.264 0.084 33.288 ;
    END
  END cfg_data[49]
  PIN cfg_data[4]
    DIRECTION INPUT ;
    USE SIGNAL ;
    PORT
      LAYER M4 ;
        RECT  0 18.384 0.084 18.408 ;
    END
  END cfg_data[4]
  PIN cfg_data[50]
    DIRECTION INPUT ;
    USE SIGNAL ;
    PORT
      LAYER M4 ;
        RECT  0 33.6 0.084 33.624 ;
    END
  END cfg_data[50]
  PIN cfg_data[51]
    DIRECTION INPUT ;
    USE SIGNAL ;
    PORT
      LAYER M4 ;
        RECT  0 33.936 0.084 33.96 ;
    END
  END cfg_data[51]
  PIN cfg_data[52]
    DIRECTION INPUT ;
    USE SIGNAL ;
    PORT
      LAYER M4 ;
        RECT  0 34.224 0.084 34.248 ;
    END
  END cfg_data[52]
  PIN cfg_data[53]
    DIRECTION INPUT ;
    USE SIGNAL ;
    PORT
      LAYER M4 ;
        RECT  0 34.56 0.084 34.584 ;
    END
  END cfg_data[53]
  PIN cfg_data[54]
    DIRECTION INPUT ;
    USE SIGNAL ;
    PORT
      LAYER M4 ;
        RECT  0 34.896 0.084 34.92 ;
    END
  END cfg_data[54]
  PIN cfg_data[55]
    DIRECTION INPUT ;
    USE SIGNAL ;
    PORT
      LAYER M4 ;
        RECT  0 35.232 0.084 35.256 ;
    END
  END cfg_data[55]
  PIN cfg_data[56]
    DIRECTION INPUT ;
    USE SIGNAL ;
    PORT
      LAYER M4 ;
        RECT  0 35.568 0.084 35.592 ;
    END
  END cfg_data[56]
  PIN cfg_data[57]
    DIRECTION INPUT ;
    USE SIGNAL ;
    PORT
      LAYER M4 ;
        RECT  0 35.904 0.084 35.928 ;
    END
  END cfg_data[57]
  PIN cfg_data[58]
    DIRECTION INPUT ;
    USE SIGNAL ;
    PORT
      LAYER M4 ;
        RECT  0 36.24 0.084 36.264 ;
    END
  END cfg_data[58]
  PIN cfg_data[59]
    DIRECTION INPUT ;
    USE SIGNAL ;
    PORT
      LAYER M4 ;
        RECT  0 36.576 0.084 36.6 ;
    END
  END cfg_data[59]
  PIN cfg_data[5]
    DIRECTION INPUT ;
    USE SIGNAL ;
    PORT
      LAYER M4 ;
        RECT  0 18.72 0.084 18.744 ;
    END
  END cfg_data[5]
  PIN cfg_data[60]
    DIRECTION INPUT ;
    USE SIGNAL ;
    PORT
      LAYER M4 ;
        RECT  0 36.864 0.084 36.888 ;
    END
  END cfg_data[60]
  PIN cfg_data[61]
    DIRECTION INPUT ;
    USE SIGNAL ;
    PORT
      LAYER M4 ;
        RECT  0 37.2 0.084 37.224 ;
    END
  END cfg_data[61]
  PIN cfg_data[62]
    DIRECTION INPUT ;
    USE SIGNAL ;
    PORT
      LAYER M4 ;
        RECT  0 37.536 0.084 37.56 ;
    END
  END cfg_data[62]
  PIN cfg_data[63]
    DIRECTION INPUT ;
    USE SIGNAL ;
    PORT
      LAYER M4 ;
        RECT  0 37.872 0.084 37.896 ;
    END
  END cfg_data[63]
  PIN cfg_data[64]
    DIRECTION INPUT ;
    USE SIGNAL ;
    PORT
      LAYER M4 ;
        RECT  0 38.208 0.084 38.232 ;
    END
  END cfg_data[64]
  PIN cfg_data[65]
    DIRECTION INPUT ;
    USE SIGNAL ;
    PORT
      LAYER M4 ;
        RECT  0 38.544 0.084 38.568 ;
    END
  END cfg_data[65]
  PIN cfg_data[66]
    DIRECTION INPUT ;
    USE SIGNAL ;
    PORT
      LAYER M4 ;
        RECT  0 38.88 0.084 38.904 ;
    END
  END cfg_data[66]
  PIN cfg_data[67]
    DIRECTION INPUT ;
    USE SIGNAL ;
    PORT
      LAYER M4 ;
        RECT  0 39.216 0.084 39.24 ;
    END
  END cfg_data[67]
  PIN cfg_data[68]
    DIRECTION INPUT ;
    USE SIGNAL ;
    PORT
      LAYER M4 ;
        RECT  0 39.504 0.084 39.528 ;
    END
  END cfg_data[68]
  PIN cfg_data[69]
    DIRECTION INPUT ;
    USE SIGNAL ;
    PORT
      LAYER M4 ;
        RECT  0 39.84 0.084 39.864 ;
    END
  END cfg_data[69]
  PIN cfg_data[6]
    DIRECTION INPUT ;
    USE SIGNAL ;
    PORT
      LAYER M4 ;
        RECT  0 19.056 0.084 19.08 ;
    END
  END cfg_data[6]
  PIN cfg_data[70]
    DIRECTION INPUT ;
    USE SIGNAL ;
    PORT
      LAYER M4 ;
        RECT  0 40.176 0.084 40.2 ;
    END
  END cfg_data[70]
  PIN cfg_data[71]
    DIRECTION INPUT ;
    USE SIGNAL ;
    PORT
      LAYER M4 ;
        RECT  0 40.512 0.084 40.536 ;
    END
  END cfg_data[71]
  PIN cfg_data[72]
    DIRECTION INPUT ;
    USE SIGNAL ;
    PORT
      LAYER M4 ;
        RECT  0 40.848 0.084 40.872 ;
    END
  END cfg_data[72]
  PIN cfg_data[73]
    DIRECTION INPUT ;
    USE SIGNAL ;
    PORT
      LAYER M4 ;
        RECT  0 41.184 0.084 41.208 ;
    END
  END cfg_data[73]
  PIN cfg_data[74]
    DIRECTION INPUT ;
    USE SIGNAL ;
    PORT
      LAYER M4 ;
        RECT  0 41.52 0.084 41.544 ;
    END
  END cfg_data[74]
  PIN cfg_data[75]
    DIRECTION INPUT ;
    USE SIGNAL ;
    PORT
      LAYER M4 ;
        RECT  0 41.856 0.084 41.88 ;
    END
  END cfg_data[75]
  PIN cfg_data[76]
    DIRECTION INPUT ;
    USE SIGNAL ;
    PORT
      LAYER M4 ;
        RECT  0 42.144 0.084 42.168 ;
    END
  END cfg_data[76]
  PIN cfg_data[77]
    DIRECTION INPUT ;
    USE SIGNAL ;
    PORT
      LAYER M4 ;
        RECT  0 42.48 0.084 42.504 ;
    END
  END cfg_data[77]
  PIN cfg_data[78]
    DIRECTION INPUT ;
    USE SIGNAL ;
    PORT
      LAYER M4 ;
        RECT  0 42.816 0.084 42.84 ;
    END
  END cfg_data[78]
  PIN cfg_data[79]
    DIRECTION INPUT ;
    USE SIGNAL ;
    PORT
      LAYER M4 ;
        RECT  0 43.152 0.084 43.176 ;
    END
  END cfg_data[79]
  PIN cfg_data[7]
    DIRECTION INPUT ;
    USE SIGNAL ;
    PORT
      LAYER M4 ;
        RECT  0 19.392 0.084 19.416 ;
    END
  END cfg_data[7]
  PIN cfg_data[80]
    DIRECTION INPUT ;
    USE SIGNAL ;
    PORT
      LAYER M4 ;
        RECT  0 43.488 0.084 43.512 ;
    END
  END cfg_data[80]
  PIN cfg_data[81]
    DIRECTION INPUT ;
    USE SIGNAL ;
    PORT
      LAYER M4 ;
        RECT  0 43.824 0.084 43.848 ;
    END
  END cfg_data[81]
  PIN cfg_data[82]
    DIRECTION INPUT ;
    USE SIGNAL ;
    PORT
      LAYER M4 ;
        RECT  0 44.16 0.084 44.184 ;
    END
  END cfg_data[82]
  PIN cfg_data[83]
    DIRECTION INPUT ;
    USE SIGNAL ;
    PORT
      LAYER M4 ;
        RECT  0 44.496 0.084 44.52 ;
    END
  END cfg_data[83]
  PIN cfg_data[84]
    DIRECTION INPUT ;
    USE SIGNAL ;
    PORT
      LAYER M4 ;
        RECT  0 44.784 0.084 44.808 ;
    END
  END cfg_data[84]
  PIN cfg_data[85]
    DIRECTION INPUT ;
    USE SIGNAL ;
    PORT
      LAYER M4 ;
        RECT  0 45.12 0.084 45.144 ;
    END
  END cfg_data[85]
  PIN cfg_data[86]
    DIRECTION INPUT ;
    USE SIGNAL ;
    PORT
      LAYER M4 ;
        RECT  0 45.456 0.084 45.48 ;
    END
  END cfg_data[86]
  PIN cfg_data[87]
    DIRECTION INPUT ;
    USE SIGNAL ;
    PORT
      LAYER M4 ;
        RECT  0 45.792 0.084 45.816 ;
    END
  END cfg_data[87]
  PIN cfg_data[88]
    DIRECTION INPUT ;
    USE SIGNAL ;
    PORT
      LAYER M4 ;
        RECT  0 46.128 0.084 46.152 ;
    END
  END cfg_data[88]
  PIN cfg_data[89]
    DIRECTION INPUT ;
    USE SIGNAL ;
    PORT
      LAYER M4 ;
        RECT  0 46.464 0.084 46.488 ;
    END
  END cfg_data[89]
  PIN cfg_data[8]
    DIRECTION INPUT ;
    USE SIGNAL ;
    PORT
      LAYER M4 ;
        RECT  0 19.728 0.084 19.752 ;
    END
  END cfg_data[8]
  PIN cfg_data[90]
    DIRECTION INPUT ;
    USE SIGNAL ;
    PORT
      LAYER M4 ;
        RECT  0 46.8 0.084 46.824 ;
    END
  END cfg_data[90]
  PIN cfg_data[91]
    DIRECTION INPUT ;
    USE SIGNAL ;
    PORT
      LAYER M4 ;
        RECT  0 47.136 0.084 47.16 ;
    END
  END cfg_data[91]
  PIN cfg_data[92]
    DIRECTION INPUT ;
    USE SIGNAL ;
    PORT
      LAYER M4 ;
        RECT  0 47.424 0.084 47.448 ;
    END
  END cfg_data[92]
  PIN cfg_data[93]
    DIRECTION INPUT ;
    USE SIGNAL ;
    PORT
      LAYER M4 ;
        RECT  0 47.76 0.084 47.784 ;
    END
  END cfg_data[93]
  PIN cfg_data[94]
    DIRECTION INPUT ;
    USE SIGNAL ;
    PORT
      LAYER M4 ;
        RECT  0 48.096 0.084 48.12 ;
    END
  END cfg_data[94]
  PIN cfg_data[95]
    DIRECTION INPUT ;
    USE SIGNAL ;
    PORT
      LAYER M4 ;
        RECT  0 48.432 0.084 48.456 ;
    END
  END cfg_data[95]
  PIN cfg_data[96]
    DIRECTION INPUT ;
    USE SIGNAL ;
    PORT
      LAYER M4 ;
        RECT  0 48.768 0.084 48.792 ;
    END
  END cfg_data[96]
  PIN cfg_data[97]
    DIRECTION INPUT ;
    USE SIGNAL ;
    PORT
      LAYER M4 ;
        RECT  0 49.104 0.084 49.128 ;
    END
  END cfg_data[97]
  PIN cfg_data[98]
    DIRECTION INPUT ;
    USE SIGNAL ;
    PORT
      LAYER M4 ;
        RECT  0 49.44 0.084 49.464 ;
    END
  END cfg_data[98]
  PIN cfg_data[99]
    DIRECTION INPUT ;
    USE SIGNAL ;
    PORT
      LAYER M4 ;
        RECT  0 49.776 0.084 49.8 ;
    END
  END cfg_data[99]
  PIN cfg_data[9]
    DIRECTION INPUT ;
    USE SIGNAL ;
    PORT
      LAYER M4 ;
        RECT  0 20.064 0.084 20.088 ;
    END
  END cfg_data[9]
  PIN cfg_target[0]
    DIRECTION INPUT ;
    USE SIGNAL ;
    PORT
      LAYER M4 ;
        RECT  0 6.48 0.084 6.504 ;
    END
  END cfg_target[0]
  PIN cfg_target[1]
    DIRECTION INPUT ;
    USE SIGNAL ;
    PORT
      LAYER M4 ;
        RECT  0 6.816 0.084 6.84 ;
    END
  END cfg_target[1]
  PIN cfg_target[2]
    DIRECTION INPUT ;
    USE SIGNAL ;
    PORT
      LAYER M4 ;
        RECT  0 7.152 0.084 7.176 ;
    END
  END cfg_target[2]
  PIN cfg_target[3]
    DIRECTION INPUT ;
    USE SIGNAL ;
    PORT
      LAYER M4 ;
        RECT  0 7.488 0.084 7.512 ;
    END
  END cfg_target[3]
  PIN cfg_target[4]
    DIRECTION INPUT ;
    USE SIGNAL ;
    PORT
      LAYER M4 ;
        RECT  0 7.824 0.084 7.848 ;
    END
  END cfg_target[4]
  PIN cfg_target[5]
    DIRECTION INPUT ;
    USE SIGNAL ;
    PORT
      LAYER M4 ;
        RECT  0 8.112 0.084 8.136 ;
    END
  END cfg_target[5]
  PIN cfg_target[6]
    DIRECTION INPUT ;
    USE SIGNAL ;
    PORT
      LAYER M4 ;
        RECT  0 8.448 0.084 8.472 ;
    END
  END cfg_target[6]
  PIN cfg_target[7]
    DIRECTION INPUT ;
    USE SIGNAL ;
    PORT
      LAYER M4 ;
        RECT  0 8.784 0.084 8.808 ;
    END
  END cfg_target[7]
  PIN cfg_v
    DIRECTION INPUT ;
    USE SIGNAL ;
    PORT
      LAYER M4 ;
        RECT  0 4.176 0.084 4.2 ;
    END
    PORT
      LAYER M4 ;
        RECT  0.06 4.176 0.137 4.2 ;
    END
  END cfg_v
  PIN clk
    DIRECTION INPUT ;
    USE SIGNAL ;
    PORT
      LAYER M5 ;
        RECT  55.488 129.516 55.512 129.6 ;
    END
    PORT
      LAYER M5 ;
        RECT  55.488 127.463 55.512 129.552 ;
    END
  END clk
  PIN command[0]
    DIRECTION OUTPUT ;
    USE SIGNAL ;
    PORT
      LAYER M4 ;
        RECT  220.236 4.656 220.32 4.68 ;
    END
    PORT
      LAYER M4 ;
        RECT  218.869 4.656 220.284 4.68 ;
    END
  END command[0]
  PIN command[10]
    DIRECTION OUTPUT ;
    USE SIGNAL ;
    PORT
      LAYER M4 ;
        RECT  220.236 17.52 220.32 17.544 ;
    END
    PORT
      LAYER M4 ;
        RECT  219.409 17.52 220.284 17.544 ;
    END
  END command[10]
  PIN command[11]
    DIRECTION OUTPUT ;
    USE SIGNAL ;
    PORT
      LAYER M4 ;
        RECT  220.236 18.816 220.32 18.84 ;
    END
    PORT
      LAYER M4 ;
        RECT  219.409 18.816 220.284 18.84 ;
    END
  END command[11]
  PIN command[12]
    DIRECTION OUTPUT ;
    USE SIGNAL ;
    PORT
      LAYER M4 ;
        RECT  220.236 20.112 220.32 20.136 ;
    END
    PORT
      LAYER M4 ;
        RECT  218.833 20.112 220.284 20.136 ;
    END
  END command[12]
  PIN command[13]
    DIRECTION OUTPUT ;
    USE SIGNAL ;
    PORT
      LAYER M4 ;
        RECT  220.236 21.408 220.32 21.432 ;
    END
    PORT
      LAYER M4 ;
        RECT  218.869 21.408 220.284 21.432 ;
    END
  END command[13]
  PIN command[14]
    DIRECTION OUTPUT ;
    USE SIGNAL ;
    PORT
      LAYER M4 ;
        RECT  220.236 22.704 220.32 22.728 ;
    END
    PORT
      LAYER M4 ;
        RECT  219.409 22.704 220.284 22.728 ;
    END
  END command[14]
  PIN command[15]
    DIRECTION OUTPUT ;
    USE SIGNAL ;
    PORT
      LAYER M4 ;
        RECT  220.236 23.952 220.32 23.976 ;
    END
    PORT
      LAYER M4 ;
        RECT  219.409 23.952 220.284 23.976 ;
    END
  END command[15]
  PIN command[16]
    DIRECTION OUTPUT ;
    USE SIGNAL ;
    PORT
      LAYER M4 ;
        RECT  220.236 25.248 220.32 25.272 ;
    END
    PORT
      LAYER M4 ;
        RECT  218.833 25.248 220.284 25.272 ;
    END
  END command[16]
  PIN command[17]
    DIRECTION OUTPUT ;
    USE SIGNAL ;
    PORT
      LAYER M4 ;
        RECT  220.236 26.544 220.32 26.568 ;
    END
    PORT
      LAYER M4 ;
        RECT  218.869 26.544 220.284 26.568 ;
    END
  END command[17]
  PIN command[18]
    DIRECTION OUTPUT ;
    USE SIGNAL ;
    PORT
      LAYER M4 ;
        RECT  220.236 27.84 220.32 27.864 ;
    END
    PORT
      LAYER M4 ;
        RECT  219.409 27.84 220.284 27.864 ;
    END
  END command[18]
  PIN command[19]
    DIRECTION OUTPUT ;
    USE SIGNAL ;
    PORT
      LAYER M4 ;
        RECT  220.236 29.136 220.32 29.16 ;
    END
    PORT
      LAYER M4 ;
        RECT  219.409 29.136 220.284 29.16 ;
    END
  END command[19]
  PIN command[1]
    DIRECTION OUTPUT ;
    USE SIGNAL ;
    PORT
      LAYER M4 ;
        RECT  220.236 5.904 220.32 5.928 ;
    END
    PORT
      LAYER M4 ;
        RECT  219.409 5.904 220.284 5.928 ;
    END
  END command[1]
  PIN command[20]
    DIRECTION OUTPUT ;
    USE SIGNAL ;
    PORT
      LAYER M4 ;
        RECT  220.236 30.432 220.32 30.456 ;
    END
    PORT
      LAYER M4 ;
        RECT  218.833 30.432 220.284 30.456 ;
    END
  END command[20]
  PIN command[21]
    DIRECTION OUTPUT ;
    USE SIGNAL ;
    PORT
      LAYER M4 ;
        RECT  220.236 31.728 220.32 31.752 ;
    END
    PORT
      LAYER M4 ;
        RECT  219.409 31.728 220.284 31.752 ;
    END
  END command[21]
  PIN command[22]
    DIRECTION OUTPUT ;
    USE SIGNAL ;
    PORT
      LAYER M4 ;
        RECT  220.236 33.024 220.32 33.048 ;
    END
    PORT
      LAYER M4 ;
        RECT  218.869 33.024 220.284 33.048 ;
    END
  END command[22]
  PIN command[23]
    DIRECTION OUTPUT ;
    USE SIGNAL ;
    PORT
      LAYER M4 ;
        RECT  220.236 34.272 220.32 34.296 ;
    END
    PORT
      LAYER M4 ;
        RECT  218.833 34.272 220.284 34.296 ;
    END
  END command[23]
  PIN command[24]
    DIRECTION OUTPUT ;
    USE SIGNAL ;
    PORT
      LAYER M4 ;
        RECT  220.236 35.568 220.32 35.592 ;
    END
    PORT
      LAYER M4 ;
        RECT  218.833 35.568 220.284 35.592 ;
    END
  END command[24]
  PIN command[25]
    DIRECTION OUTPUT ;
    USE SIGNAL ;
    PORT
      LAYER M4 ;
        RECT  220.236 36.864 220.32 36.888 ;
    END
    PORT
      LAYER M4 ;
        RECT  219.409 36.864 220.284 36.888 ;
    END
  END command[25]
  PIN command[26]
    DIRECTION OUTPUT ;
    USE SIGNAL ;
    PORT
      LAYER M4 ;
        RECT  220.236 38.16 220.32 38.184 ;
    END
    PORT
      LAYER M4 ;
        RECT  219.409 38.16 220.284 38.184 ;
    END
  END command[26]
  PIN command[27]
    DIRECTION OUTPUT ;
    USE SIGNAL ;
    PORT
      LAYER M4 ;
        RECT  220.236 39.456 220.32 39.48 ;
    END
    PORT
      LAYER M4 ;
        RECT  218.869 39.456 220.284 39.48 ;
    END
  END command[27]
  PIN command[28]
    DIRECTION OUTPUT ;
    USE SIGNAL ;
    PORT
      LAYER M4 ;
        RECT  220.236 40.752 220.32 40.776 ;
    END
    PORT
      LAYER M4 ;
        RECT  218.833 40.752 220.284 40.776 ;
    END
  END command[28]
  PIN command[29]
    DIRECTION OUTPUT ;
    USE SIGNAL ;
    PORT
      LAYER M4 ;
        RECT  220.236 42.048 220.32 42.072 ;
    END
    PORT
      LAYER M4 ;
        RECT  219.409 42.048 220.284 42.072 ;
    END
  END command[29]
  PIN command[2]
    DIRECTION OUTPUT ;
    USE SIGNAL ;
    PORT
      LAYER M4 ;
        RECT  220.236 7.2 220.32 7.224 ;
    END
    PORT
      LAYER M4 ;
        RECT  219.409 7.2 220.284 7.224 ;
    END
  END command[2]
  PIN command[30]
    DIRECTION OUTPUT ;
    USE SIGNAL ;
    PORT
      LAYER M4 ;
        RECT  220.236 43.296 220.32 43.32 ;
    END
    PORT
      LAYER M4 ;
        RECT  219.409 43.296 220.284 43.32 ;
    END
  END command[30]
  PIN command[31]
    DIRECTION OUTPUT ;
    USE SIGNAL ;
    PORT
      LAYER M4 ;
        RECT  220.236 44.592 220.32 44.616 ;
    END
    PORT
      LAYER M4 ;
        RECT  218.869 44.592 220.284 44.616 ;
    END
  END command[31]
  PIN command[32]
    DIRECTION OUTPUT ;
    USE SIGNAL ;
    PORT
      LAYER M4 ;
        RECT  220.236 45.888 220.32 45.912 ;
    END
    PORT
      LAYER M4 ;
        RECT  219.409 45.888 220.284 45.912 ;
    END
  END command[32]
  PIN command[33]
    DIRECTION OUTPUT ;
    USE SIGNAL ;
    PORT
      LAYER M4 ;
        RECT  220.236 47.184 220.32 47.208 ;
    END
    PORT
      LAYER M4 ;
        RECT  218.869 47.184 220.284 47.208 ;
    END
  END command[33]
  PIN command[34]
    DIRECTION OUTPUT ;
    USE SIGNAL ;
    PORT
      LAYER M4 ;
        RECT  220.236 48.48 220.32 48.504 ;
    END
    PORT
      LAYER M4 ;
        RECT  218.869 48.48 220.284 48.504 ;
    END
  END command[34]
  PIN command[35]
    DIRECTION OUTPUT ;
    USE SIGNAL ;
    PORT
      LAYER M4 ;
        RECT  220.236 49.776 220.32 49.8 ;
    END
    PORT
      LAYER M4 ;
        RECT  219.445 49.776 220.284 49.8 ;
    END
  END command[35]
  PIN command[36]
    DIRECTION OUTPUT ;
    USE SIGNAL ;
    PORT
      LAYER M4 ;
        RECT  220.236 51.072 220.32 51.096 ;
    END
    PORT
      LAYER M4 ;
        RECT  219.409 51.072 220.284 51.096 ;
    END
  END command[36]
  PIN command[37]
    DIRECTION OUTPUT ;
    USE SIGNAL ;
    PORT
      LAYER M4 ;
        RECT  220.236 52.32 220.32 52.344 ;
    END
    PORT
      LAYER M4 ;
        RECT  219.409 52.32 220.284 52.344 ;
    END
  END command[37]
  PIN command[38]
    DIRECTION OUTPUT ;
    USE SIGNAL ;
    PORT
      LAYER M4 ;
        RECT  220.236 53.616 220.32 53.64 ;
    END
    PORT
      LAYER M4 ;
        RECT  219.445 53.616 220.284 53.64 ;
    END
  END command[38]
  PIN command[39]
    DIRECTION OUTPUT ;
    USE SIGNAL ;
    PORT
      LAYER M4 ;
        RECT  220.236 54.912 220.32 54.936 ;
    END
    PORT
      LAYER M4 ;
        RECT  219.409 54.912 220.284 54.936 ;
    END
  END command[39]
  PIN command[3]
    DIRECTION OUTPUT ;
    USE SIGNAL ;
    PORT
      LAYER M4 ;
        RECT  220.236 8.496 220.32 8.52 ;
    END
    PORT
      LAYER M4 ;
        RECT  219.409 8.496 220.284 8.52 ;
    END
  END command[3]
  PIN command[40]
    DIRECTION OUTPUT ;
    USE SIGNAL ;
    PORT
      LAYER M4 ;
        RECT  220.236 56.208 220.32 56.232 ;
    END
    PORT
      LAYER M4 ;
        RECT  218.869 56.208 220.284 56.232 ;
    END
  END command[40]
  PIN command[41]
    DIRECTION OUTPUT ;
    USE SIGNAL ;
    PORT
      LAYER M4 ;
        RECT  220.236 57.504 220.32 57.528 ;
    END
    PORT
      LAYER M4 ;
        RECT  218.869 57.504 220.284 57.528 ;
    END
  END command[41]
  PIN command[42]
    DIRECTION OUTPUT ;
    USE SIGNAL ;
    PORT
      LAYER M4 ;
        RECT  220.236 58.8 220.32 58.824 ;
    END
    PORT
      LAYER M4 ;
        RECT  219.445 58.8 220.284 58.824 ;
    END
  END command[42]
  PIN command[43]
    DIRECTION OUTPUT ;
    USE SIGNAL ;
    PORT
      LAYER M4 ;
        RECT  220.236 60.096 220.32 60.12 ;
    END
    PORT
      LAYER M4 ;
        RECT  218.293 60.096 220.284 60.12 ;
    END
  END command[43]
  PIN command[44]
    DIRECTION OUTPUT ;
    USE SIGNAL ;
    PORT
      LAYER M4 ;
        RECT  220.236 61.344 220.32 61.368 ;
    END
    PORT
      LAYER M4 ;
        RECT  219.409 61.344 220.284 61.368 ;
    END
  END command[44]
  PIN command[45]
    DIRECTION OUTPUT ;
    USE SIGNAL ;
    PORT
      LAYER M4 ;
        RECT  220.236 62.64 220.32 62.664 ;
    END
    PORT
      LAYER M4 ;
        RECT  219.409 62.64 220.284 62.664 ;
    END
  END command[45]
  PIN command[46]
    DIRECTION OUTPUT ;
    USE SIGNAL ;
    PORT
      LAYER M4 ;
        RECT  220.236 63.936 220.32 63.96 ;
    END
    PORT
      LAYER M4 ;
        RECT  219.445 63.936 220.284 63.96 ;
    END
  END command[46]
  PIN command[47]
    DIRECTION OUTPUT ;
    USE SIGNAL ;
    PORT
      LAYER M4 ;
        RECT  220.236 65.232 220.32 65.256 ;
    END
    PORT
      LAYER M4 ;
        RECT  218.833 65.232 220.284 65.256 ;
    END
  END command[47]
  PIN command[4]
    DIRECTION OUTPUT ;
    USE SIGNAL ;
    PORT
      LAYER M4 ;
        RECT  220.236 9.792 220.32 9.816 ;
    END
    PORT
      LAYER M4 ;
        RECT  218.293 9.792 220.284 9.816 ;
    END
  END command[4]
  PIN command[5]
    DIRECTION OUTPUT ;
    USE SIGNAL ;
    PORT
      LAYER M4 ;
        RECT  220.236 11.088 220.32 11.112 ;
    END
    PORT
      LAYER M4 ;
        RECT  219.409 11.088 220.284 11.112 ;
    END
  END command[5]
  PIN command[6]
    DIRECTION OUTPUT ;
    USE SIGNAL ;
    PORT
      LAYER M4 ;
        RECT  220.236 12.384 220.32 12.408 ;
    END
    PORT
      LAYER M4 ;
        RECT  219.409 12.384 220.284 12.408 ;
    END
  END command[6]
  PIN command[7]
    DIRECTION OUTPUT ;
    USE SIGNAL ;
    PORT
      LAYER M4 ;
        RECT  220.236 13.68 220.32 13.704 ;
    END
    PORT
      LAYER M4 ;
        RECT  219.409 13.68 220.284 13.704 ;
    END
  END command[7]
  PIN command[8]
    DIRECTION OUTPUT ;
    USE SIGNAL ;
    PORT
      LAYER M4 ;
        RECT  220.236 14.928 220.32 14.952 ;
    END
    PORT
      LAYER M4 ;
        RECT  218.833 14.928 220.284 14.952 ;
    END
  END command[8]
  PIN command[9]
    DIRECTION OUTPUT ;
    USE SIGNAL ;
    PORT
      LAYER M4 ;
        RECT  220.236 16.224 220.32 16.248 ;
    END
    PORT
      LAYER M4 ;
        RECT  219.409 16.224 220.284 16.248 ;
    END
  END command[9]
  PIN command_v
    DIRECTION OUTPUT ;
    USE SIGNAL ;
    PORT
      LAYER M4 ;
        RECT  220.236 68.544 220.32 68.568 ;
    END
    PORT
      LAYER M4 ;
        RECT  219.409 68.544 220.284 68.568 ;
    END
  END command_v
  PIN configured
    DIRECTION OUTPUT ;
    USE SIGNAL ;
    PORT
      LAYER M4 ;
        RECT  220.236 121.632 220.32 121.656 ;
    END
    PORT
      LAYER M4 ;
        RECT  218.257 121.632 220.284 121.656 ;
    END
  END configured
  PIN desc_base[0]
    DIRECTION INPUT ;
    USE SIGNAL ;
    PORT
      LAYER M4 ;
        RECT  0 105.888 0.084 105.912 ;
    END
  END desc_base[0]
  PIN desc_base[10]
    DIRECTION INPUT ;
    USE SIGNAL ;
    PORT
      LAYER M4 ;
        RECT  0 109.2 0.084 109.224 ;
    END
  END desc_base[10]
  PIN desc_base[11]
    DIRECTION INPUT ;
    USE SIGNAL ;
    PORT
      LAYER M4 ;
        RECT  0 109.536 0.084 109.56 ;
    END
  END desc_base[11]
  PIN desc_base[1]
    DIRECTION INPUT ;
    USE SIGNAL ;
    PORT
      LAYER M4 ;
        RECT  0 106.224 0.084 106.248 ;
    END
  END desc_base[1]
  PIN desc_base[2]
    DIRECTION INPUT ;
    USE SIGNAL ;
    PORT
      LAYER M4 ;
        RECT  0 106.56 0.084 106.584 ;
    END
  END desc_base[2]
  PIN desc_base[3]
    DIRECTION INPUT ;
    USE SIGNAL ;
    PORT
      LAYER M4 ;
        RECT  0 106.896 0.084 106.92 ;
    END
  END desc_base[3]
  PIN desc_base[4]
    DIRECTION INPUT ;
    USE SIGNAL ;
    PORT
      LAYER M4 ;
        RECT  0 107.232 0.084 107.256 ;
    END
  END desc_base[4]
  PIN desc_base[5]
    DIRECTION INPUT ;
    USE SIGNAL ;
    PORT
      LAYER M4 ;
        RECT  0 107.52 0.084 107.544 ;
    END
  END desc_base[5]
  PIN desc_base[6]
    DIRECTION INPUT ;
    USE SIGNAL ;
    PORT
      LAYER M4 ;
        RECT  0 107.856 0.084 107.88 ;
    END
  END desc_base[6]
  PIN desc_base[7]
    DIRECTION INPUT ;
    USE SIGNAL ;
    PORT
      LAYER M4 ;
        RECT  0 108.192 0.084 108.216 ;
    END
  END desc_base[7]
  PIN desc_base[8]
    DIRECTION INPUT ;
    USE SIGNAL ;
    PORT
      LAYER M4 ;
        RECT  0 108.528 0.084 108.552 ;
    END
  END desc_base[8]
  PIN desc_base[9]
    DIRECTION INPUT ;
    USE SIGNAL ;
    PORT
      LAYER M4 ;
        RECT  0 108.864 0.084 108.888 ;
    END
  END desc_base[9]
  PIN desc_limit[0]
    DIRECTION INPUT ;
    USE SIGNAL ;
    PORT
      LAYER M4 ;
        RECT  0 111.84 0.084 111.864 ;
    END
  END desc_limit[0]
  PIN desc_limit[10]
    DIRECTION INPUT ;
    USE SIGNAL ;
    PORT
      LAYER M4 ;
        RECT  0 115.152 0.084 115.176 ;
    END
  END desc_limit[10]
  PIN desc_limit[11]
    DIRECTION INPUT ;
    USE SIGNAL ;
    PORT
      LAYER M4 ;
        RECT  0 115.488 0.084 115.512 ;
    END
  END desc_limit[11]
  PIN desc_limit[12]
    DIRECTION INPUT ;
    USE SIGNAL ;
    PORT
      LAYER M4 ;
        RECT  0 115.824 0.084 115.848 ;
    END
  END desc_limit[12]
  PIN desc_limit[1]
    DIRECTION INPUT ;
    USE SIGNAL ;
    PORT
      LAYER M4 ;
        RECT  0 112.176 0.084 112.2 ;
    END
  END desc_limit[1]
  PIN desc_limit[2]
    DIRECTION INPUT ;
    USE SIGNAL ;
    PORT
      LAYER M4 ;
        RECT  0 112.512 0.084 112.536 ;
    END
  END desc_limit[2]
  PIN desc_limit[3]
    DIRECTION INPUT ;
    USE SIGNAL ;
    PORT
      LAYER M4 ;
        RECT  0 112.848 0.084 112.872 ;
    END
  END desc_limit[3]
  PIN desc_limit[4]
    DIRECTION INPUT ;
    USE SIGNAL ;
    PORT
      LAYER M4 ;
        RECT  0 113.184 0.084 113.208 ;
    END
  END desc_limit[4]
  PIN desc_limit[5]
    DIRECTION INPUT ;
    USE SIGNAL ;
    PORT
      LAYER M4 ;
        RECT  0 113.52 0.084 113.544 ;
    END
  END desc_limit[5]
  PIN desc_limit[6]
    DIRECTION INPUT ;
    USE SIGNAL ;
    PORT
      LAYER M4 ;
        RECT  0 113.856 0.084 113.88 ;
    END
  END desc_limit[6]
  PIN desc_limit[7]
    DIRECTION INPUT ;
    USE SIGNAL ;
    PORT
      LAYER M4 ;
        RECT  0 114.144 0.084 114.168 ;
    END
  END desc_limit[7]
  PIN desc_limit[8]
    DIRECTION INPUT ;
    USE SIGNAL ;
    PORT
      LAYER M4 ;
        RECT  0 114.48 0.084 114.504 ;
    END
  END desc_limit[8]
  PIN desc_limit[9]
    DIRECTION INPUT ;
    USE SIGNAL ;
    PORT
      LAYER M4 ;
        RECT  0 114.816 0.084 114.84 ;
    END
  END desc_limit[9]
  PIN desc_loops[0]
    DIRECTION INPUT ;
    USE SIGNAL ;
    PORT
      LAYER M4 ;
        RECT  0 118.128 0.084 118.152 ;
    END
  END desc_loops[0]
  PIN desc_loops[10]
    DIRECTION INPUT ;
    USE SIGNAL ;
    PORT
      LAYER M4 ;
        RECT  0 121.44 0.084 121.464 ;
    END
  END desc_loops[10]
  PIN desc_loops[11]
    DIRECTION INPUT ;
    USE SIGNAL ;
    PORT
      LAYER M4 ;
        RECT  0 121.776 0.084 121.8 ;
    END
  END desc_loops[11]
  PIN desc_loops[12]
    DIRECTION INPUT ;
    USE SIGNAL ;
    PORT
      LAYER M4 ;
        RECT  0 122.112 0.084 122.136 ;
    END
  END desc_loops[12]
  PIN desc_loops[13]
    DIRECTION INPUT ;
    USE SIGNAL ;
    PORT
      LAYER M4 ;
        RECT  0 122.448 0.084 122.472 ;
    END
  END desc_loops[13]
  PIN desc_loops[14]
    DIRECTION INPUT ;
    USE SIGNAL ;
    PORT
      LAYER M4 ;
        RECT  0 122.784 0.084 122.808 ;
    END
  END desc_loops[14]
  PIN desc_loops[15]
    DIRECTION INPUT ;
    USE SIGNAL ;
    PORT
      LAYER M4 ;
        RECT  0 123.072 0.084 123.096 ;
    END
  END desc_loops[15]
  PIN desc_loops[1]
    DIRECTION INPUT ;
    USE SIGNAL ;
    PORT
      LAYER M4 ;
        RECT  0 118.464 0.084 118.488 ;
    END
  END desc_loops[1]
  PIN desc_loops[2]
    DIRECTION INPUT ;
    USE SIGNAL ;
    PORT
      LAYER M4 ;
        RECT  0 118.8 0.084 118.824 ;
    END
  END desc_loops[2]
  PIN desc_loops[3]
    DIRECTION INPUT ;
    USE SIGNAL ;
    PORT
      LAYER M4 ;
        RECT  0 119.136 0.084 119.16 ;
    END
  END desc_loops[3]
  PIN desc_loops[4]
    DIRECTION INPUT ;
    USE SIGNAL ;
    PORT
      LAYER M4 ;
        RECT  0 119.472 0.084 119.496 ;
    END
  END desc_loops[4]
  PIN desc_loops[5]
    DIRECTION INPUT ;
    USE SIGNAL ;
    PORT
      LAYER M4 ;
        RECT  0 119.808 0.084 119.832 ;
    END
  END desc_loops[5]
  PIN desc_loops[6]
    DIRECTION INPUT ;
    USE SIGNAL ;
    PORT
      LAYER M4 ;
        RECT  0 120.144 0.084 120.168 ;
    END
  END desc_loops[6]
  PIN desc_loops[7]
    DIRECTION INPUT ;
    USE SIGNAL ;
    PORT
      LAYER M4 ;
        RECT  0 120.432 0.084 120.456 ;
    END
  END desc_loops[7]
  PIN desc_loops[8]
    DIRECTION INPUT ;
    USE SIGNAL ;
    PORT
      LAYER M4 ;
        RECT  0 120.768 0.084 120.792 ;
    END
  END desc_loops[8]
  PIN desc_loops[9]
    DIRECTION INPUT ;
    USE SIGNAL ;
    PORT
      LAYER M4 ;
        RECT  0 121.104 0.084 121.128 ;
    END
  END desc_loops[9]
  PIN desc_v
    DIRECTION INPUT ;
    USE SIGNAL ;
    PORT
      LAYER M4 ;
        RECT  0 103.584 0.084 103.608 ;
    END
    PORT
      LAYER M4 ;
        RECT  0.06 103.584 2.408 103.608 ;
    END
  END desc_v
  PIN done
    DIRECTION OUTPUT ;
    USE SIGNAL ;
    PORT
      LAYER M4 ;
        RECT  220.236 118.368 220.32 118.392 ;
    END
    PORT
      LAYER M4 ;
        RECT  218.293 118.368 220.284 118.392 ;
    END
  END done
  PIN fault
    DIRECTION OUTPUT ;
    USE SIGNAL ;
    PORT
      LAYER M4 ;
        RECT  220.236 124.944 220.32 124.968 ;
    END
    PORT
      LAYER M4 ;
        RECT  219.409 124.944 220.284 124.968 ;
    END
  END fault
  PIN launch_v
    DIRECTION INPUT ;
    USE SIGNAL ;
    PORT
      LAYER M4 ;
        RECT  0 125.424 0.084 125.448 ;
    END
    PORT
      LAYER M4 ;
        RECT  0.06 125.424 0.137 125.448 ;
    END
  END launch_v
  PIN ordinal[0]
    DIRECTION OUTPUT ;
    USE SIGNAL ;
    PORT
      LAYER M4 ;
        RECT  220.236 71.808 220.32 71.832 ;
    END
    PORT
      LAYER M4 ;
        RECT  219.409 71.808 220.284 71.832 ;
    END
  END ordinal[0]
  PIN ordinal[10]
    DIRECTION OUTPUT ;
    USE SIGNAL ;
    PORT
      LAYER M4 ;
        RECT  220.236 84.72 220.32 84.744 ;
    END
    PORT
      LAYER M4 ;
        RECT  219.409 84.72 220.284 84.744 ;
    END
  END ordinal[10]
  PIN ordinal[11]
    DIRECTION OUTPUT ;
    USE SIGNAL ;
    PORT
      LAYER M4 ;
        RECT  220.236 86.016 220.32 86.04 ;
    END
    PORT
      LAYER M4 ;
        RECT  219.409 86.016 220.284 86.04 ;
    END
  END ordinal[11]
  PIN ordinal[12]
    DIRECTION OUTPUT ;
    USE SIGNAL ;
    PORT
      LAYER M4 ;
        RECT  220.236 87.264 220.32 87.288 ;
    END
    PORT
      LAYER M4 ;
        RECT  219.409 87.264 220.284 87.288 ;
    END
  END ordinal[12]
  PIN ordinal[13]
    DIRECTION OUTPUT ;
    USE SIGNAL ;
    PORT
      LAYER M4 ;
        RECT  220.236 88.56 220.32 88.584 ;
    END
    PORT
      LAYER M4 ;
        RECT  219.409 88.56 220.284 88.584 ;
    END
  END ordinal[13]
  PIN ordinal[14]
    DIRECTION OUTPUT ;
    USE SIGNAL ;
    PORT
      LAYER M4 ;
        RECT  220.236 89.856 220.32 89.88 ;
    END
    PORT
      LAYER M4 ;
        RECT  219.409 89.856 220.284 89.88 ;
    END
  END ordinal[14]
  PIN ordinal[15]
    DIRECTION OUTPUT ;
    USE SIGNAL ;
    PORT
      LAYER M4 ;
        RECT  220.236 91.152 220.32 91.176 ;
    END
    PORT
      LAYER M4 ;
        RECT  219.409 91.152 220.284 91.176 ;
    END
  END ordinal[15]
  PIN ordinal[16]
    DIRECTION OUTPUT ;
    USE SIGNAL ;
    PORT
      LAYER M4 ;
        RECT  220.236 92.448 220.32 92.472 ;
    END
    PORT
      LAYER M4 ;
        RECT  219.409 92.448 220.284 92.472 ;
    END
  END ordinal[16]
  PIN ordinal[17]
    DIRECTION OUTPUT ;
    USE SIGNAL ;
    PORT
      LAYER M4 ;
        RECT  220.236 93.744 220.32 93.768 ;
    END
    PORT
      LAYER M4 ;
        RECT  218.293 93.744 220.284 93.768 ;
    END
  END ordinal[17]
  PIN ordinal[18]
    DIRECTION OUTPUT ;
    USE SIGNAL ;
    PORT
      LAYER M4 ;
        RECT  220.236 95.04 220.32 95.064 ;
    END
    PORT
      LAYER M4 ;
        RECT  219.409 95.04 220.284 95.064 ;
    END
  END ordinal[18]
  PIN ordinal[19]
    DIRECTION OUTPUT ;
    USE SIGNAL ;
    PORT
      LAYER M4 ;
        RECT  220.236 96.336 220.32 96.36 ;
    END
    PORT
      LAYER M4 ;
        RECT  219.409 96.336 220.284 96.36 ;
    END
  END ordinal[19]
  PIN ordinal[1]
    DIRECTION OUTPUT ;
    USE SIGNAL ;
    PORT
      LAYER M4 ;
        RECT  220.236 73.104 220.32 73.128 ;
    END
    PORT
      LAYER M4 ;
        RECT  218.833 73.104 220.284 73.128 ;
    END
  END ordinal[1]
  PIN ordinal[20]
    DIRECTION OUTPUT ;
    USE SIGNAL ;
    PORT
      LAYER M4 ;
        RECT  220.236 97.584 220.32 97.608 ;
    END
    PORT
      LAYER M4 ;
        RECT  218.869 97.584 220.284 97.608 ;
    END
  END ordinal[20]
  PIN ordinal[21]
    DIRECTION OUTPUT ;
    USE SIGNAL ;
    PORT
      LAYER M4 ;
        RECT  220.236 98.88 220.32 98.904 ;
    END
    PORT
      LAYER M4 ;
        RECT  218.293 98.88 220.284 98.904 ;
    END
  END ordinal[21]
  PIN ordinal[22]
    DIRECTION OUTPUT ;
    USE SIGNAL ;
    PORT
      LAYER M4 ;
        RECT  220.236 100.176 220.32 100.2 ;
    END
    PORT
      LAYER M4 ;
        RECT  219.409 100.176 220.284 100.2 ;
    END
  END ordinal[22]
  PIN ordinal[23]
    DIRECTION OUTPUT ;
    USE SIGNAL ;
    PORT
      LAYER M4 ;
        RECT  220.236 101.472 220.32 101.496 ;
    END
    PORT
      LAYER M4 ;
        RECT  219.409 101.472 220.284 101.496 ;
    END
  END ordinal[23]
  PIN ordinal[24]
    DIRECTION OUTPUT ;
    USE SIGNAL ;
    PORT
      LAYER M4 ;
        RECT  220.236 102.768 220.32 102.792 ;
    END
    PORT
      LAYER M4 ;
        RECT  219.409 102.768 220.284 102.792 ;
    END
  END ordinal[24]
  PIN ordinal[25]
    DIRECTION OUTPUT ;
    USE SIGNAL ;
    PORT
      LAYER M4 ;
        RECT  220.236 104.064 220.32 104.088 ;
    END
    PORT
      LAYER M4 ;
        RECT  218.869 104.064 220.284 104.088 ;
    END
  END ordinal[25]
  PIN ordinal[26]
    DIRECTION OUTPUT ;
    USE SIGNAL ;
    PORT
      LAYER M4 ;
        RECT  220.236 105.36 220.32 105.384 ;
    END
    PORT
      LAYER M4 ;
        RECT  219.409 105.36 220.284 105.384 ;
    END
  END ordinal[26]
  PIN ordinal[27]
    DIRECTION OUTPUT ;
    USE SIGNAL ;
    PORT
      LAYER M4 ;
        RECT  220.236 106.608 220.32 106.632 ;
    END
    PORT
      LAYER M4 ;
        RECT  219.445 106.608 220.284 106.632 ;
    END
  END ordinal[27]
  PIN ordinal[28]
    DIRECTION OUTPUT ;
    USE SIGNAL ;
    PORT
      LAYER M4 ;
        RECT  220.236 107.904 220.32 107.928 ;
    END
    PORT
      LAYER M4 ;
        RECT  219.409 107.904 220.284 107.928 ;
    END
  END ordinal[28]
  PIN ordinal[29]
    DIRECTION OUTPUT ;
    USE SIGNAL ;
    PORT
      LAYER M4 ;
        RECT  220.236 109.2 220.32 109.224 ;
    END
    PORT
      LAYER M4 ;
        RECT  218.293 109.2 220.284 109.224 ;
    END
  END ordinal[29]
  PIN ordinal[2]
    DIRECTION OUTPUT ;
    USE SIGNAL ;
    PORT
      LAYER M4 ;
        RECT  220.236 74.4 220.32 74.424 ;
    END
    PORT
      LAYER M4 ;
        RECT  219.409 74.4 220.284 74.424 ;
    END
  END ordinal[2]
  PIN ordinal[30]
    DIRECTION OUTPUT ;
    USE SIGNAL ;
    PORT
      LAYER M4 ;
        RECT  220.236 110.496 220.32 110.52 ;
    END
    PORT
      LAYER M4 ;
        RECT  219.409 110.496 220.284 110.52 ;
    END
  END ordinal[30]
  PIN ordinal[31]
    DIRECTION OUTPUT ;
    USE SIGNAL ;
    PORT
      LAYER M4 ;
        RECT  220.236 111.792 220.32 111.816 ;
    END
    PORT
      LAYER M4 ;
        RECT  219.409 111.792 220.284 111.816 ;
    END
  END ordinal[31]
  PIN ordinal[3]
    DIRECTION OUTPUT ;
    USE SIGNAL ;
    PORT
      LAYER M4 ;
        RECT  220.236 75.696 220.32 75.72 ;
    END
    PORT
      LAYER M4 ;
        RECT  219.409 75.696 220.284 75.72 ;
    END
  END ordinal[3]
  PIN ordinal[4]
    DIRECTION OUTPUT ;
    USE SIGNAL ;
    PORT
      LAYER M4 ;
        RECT  220.236 76.992 220.32 77.016 ;
    END
    PORT
      LAYER M4 ;
        RECT  218.869 76.992 220.284 77.016 ;
    END
  END ordinal[4]
  PIN ordinal[5]
    DIRECTION OUTPUT ;
    USE SIGNAL ;
    PORT
      LAYER M4 ;
        RECT  220.236 78.24 220.32 78.264 ;
    END
    PORT
      LAYER M4 ;
        RECT  219.409 78.24 220.284 78.264 ;
    END
  END ordinal[5]
  PIN ordinal[6]
    DIRECTION OUTPUT ;
    USE SIGNAL ;
    PORT
      LAYER M4 ;
        RECT  220.236 79.536 220.32 79.56 ;
    END
    PORT
      LAYER M4 ;
        RECT  219.409 79.536 220.284 79.56 ;
    END
  END ordinal[6]
  PIN ordinal[7]
    DIRECTION OUTPUT ;
    USE SIGNAL ;
    PORT
      LAYER M4 ;
        RECT  220.236 80.832 220.32 80.856 ;
    END
    PORT
      LAYER M4 ;
        RECT  219.409 80.832 220.284 80.856 ;
    END
  END ordinal[7]
  PIN ordinal[8]
    DIRECTION OUTPUT ;
    USE SIGNAL ;
    PORT
      LAYER M4 ;
        RECT  220.236 82.128 220.32 82.152 ;
    END
    PORT
      LAYER M4 ;
        RECT  218.869 82.128 220.284 82.152 ;
    END
  END ordinal[8]
  PIN ordinal[9]
    DIRECTION OUTPUT ;
    USE SIGNAL ;
    PORT
      LAYER M4 ;
        RECT  220.236 83.424 220.32 83.448 ;
    END
    PORT
      LAYER M4 ;
        RECT  219.409 83.424 220.284 83.448 ;
    END
  END ordinal[9]
  PIN rst_n
    DIRECTION INPUT ;
    USE SIGNAL ;
    PORT
      LAYER M5 ;
        RECT  160.512 129.516 160.536 129.6 ;
    END
    PORT
      LAYER M5 ;
        RECT  160.416 129.445 160.536 129.552 ;
    END
  END rst_n
  PIN VDD
    DIRECTION INOUT ;
    USE POWER ;
    PORT
      LAYER M5 ;
        RECT  213.192 2.151 213.312 127.449 ;
        RECT  207.792 2.151 207.912 127.449 ;
        RECT  202.392 2.151 202.512 127.449 ;
        RECT  196.992 2.151 197.112 127.449 ;
        RECT  191.592 2.151 191.712 127.449 ;
        RECT  186.192 2.151 186.312 127.449 ;
        RECT  180.792 2.151 180.912 127.449 ;
        RECT  175.392 2.151 175.512 127.449 ;
        RECT  169.992 2.151 170.112 127.449 ;
        RECT  164.592 2.151 164.712 127.449 ;
        RECT  159.192 2.151 159.312 127.449 ;
        RECT  153.792 2.151 153.912 127.449 ;
        RECT  148.392 2.151 148.512 127.449 ;
        RECT  142.992 2.151 143.112 127.449 ;
        RECT  137.592 2.151 137.712 127.449 ;
        RECT  132.192 2.151 132.312 127.449 ;
        RECT  126.792 2.151 126.912 127.449 ;
        RECT  121.392 2.151 121.512 127.449 ;
        RECT  115.992 2.151 116.112 127.449 ;
        RECT  110.592 2.151 110.712 127.449 ;
        RECT  105.192 2.151 105.312 127.449 ;
        RECT  99.792 2.151 99.912 127.449 ;
        RECT  94.392 2.151 94.512 127.449 ;
        RECT  88.992 2.151 89.112 127.449 ;
        RECT  83.592 2.151 83.712 127.449 ;
        RECT  78.192 2.151 78.312 127.449 ;
        RECT  72.792 2.151 72.912 127.449 ;
        RECT  67.392 2.151 67.512 127.449 ;
        RECT  61.992 2.151 62.112 127.449 ;
        RECT  56.592 2.151 56.712 127.449 ;
        RECT  51.192 2.151 51.312 127.449 ;
        RECT  45.792 2.151 45.912 127.449 ;
        RECT  40.392 2.151 40.512 127.449 ;
        RECT  34.992 2.151 35.112 127.449 ;
        RECT  29.592 2.151 29.712 127.449 ;
        RECT  24.192 2.151 24.312 127.449 ;
        RECT  18.792 2.151 18.912 127.449 ;
        RECT  13.392 2.151 13.512 127.449 ;
        RECT  7.992 2.151 8.112 127.449 ;
        RECT  2.592 2.151 2.712 127.449 ;
    END
  END VDD
  PIN VSS
    DIRECTION INOUT ;
    USE GROUND ;
    PORT
      LAYER M5 ;
        RECT  213 2.137 213.12 127.463 ;
        RECT  207.6 2.137 207.72 127.463 ;
        RECT  202.2 2.137 202.32 127.463 ;
        RECT  196.8 2.137 196.92 127.463 ;
        RECT  191.4 2.137 191.52 127.463 ;
        RECT  186 2.137 186.12 127.463 ;
        RECT  180.6 2.137 180.72 127.463 ;
        RECT  175.2 2.137 175.32 127.463 ;
        RECT  169.8 2.137 169.92 127.463 ;
        RECT  164.4 2.137 164.52 127.463 ;
        RECT  159 2.137 159.12 127.463 ;
        RECT  153.6 2.137 153.72 127.463 ;
        RECT  148.2 2.137 148.32 127.463 ;
        RECT  142.8 2.137 142.92 127.463 ;
        RECT  137.4 2.137 137.52 127.463 ;
        RECT  132 2.137 132.12 127.463 ;
        RECT  126.6 2.137 126.72 127.463 ;
        RECT  121.2 2.137 121.32 127.463 ;
        RECT  115.8 2.137 115.92 127.463 ;
        RECT  110.4 2.137 110.52 127.463 ;
        RECT  105 2.137 105.12 127.463 ;
        RECT  99.6 2.137 99.72 127.463 ;
        RECT  94.2 2.137 94.32 127.463 ;
        RECT  88.8 2.137 88.92 127.463 ;
        RECT  83.4 2.137 83.52 127.463 ;
        RECT  78 2.137 78.12 127.463 ;
        RECT  72.6 2.137 72.72 127.463 ;
        RECT  67.2 2.137 67.32 127.463 ;
        RECT  61.8 2.137 61.92 127.463 ;
        RECT  56.4 2.137 56.52 127.463 ;
        RECT  51 2.137 51.12 127.463 ;
        RECT  45.6 2.137 45.72 127.463 ;
        RECT  40.2 2.137 40.32 127.463 ;
        RECT  34.8 2.137 34.92 127.463 ;
        RECT  29.4 2.137 29.52 127.463 ;
        RECT  24 2.137 24.12 127.463 ;
        RECT  18.6 2.137 18.72 127.463 ;
        RECT  13.2 2.137 13.32 127.463 ;
        RECT  7.8 2.137 7.92 127.463 ;
        RECT  2.4 2.137 2.52 127.463 ;
    END
  END VSS
  # OT_OBS_CLOSED layer=M5 d_um=1.536 added=412
  OBS
    LAYER RVTN ;
     RECT  2.16 2.16 218.16 2.295 ;
     RECT  2.16 2.565 218.16 2.835 ;
     RECT  2.16 3.105 218.16 3.375 ;
     RECT  2.16 3.645 218.16 3.915 ;
     RECT  2.16 4.185 218.16 4.455 ;
     RECT  2.16 4.725 218.16 4.995 ;
     RECT  2.16 5.265 218.16 5.535 ;
     RECT  2.16 5.805 218.16 6.075 ;
     RECT  2.16 6.345 218.16 6.615 ;
     RECT  2.16 6.885 218.16 7.155 ;
     RECT  2.16 7.425 218.16 7.695 ;
     RECT  2.16 7.965 218.16 8.235 ;
     RECT  2.16 8.505 218.16 8.775 ;
     RECT  2.16 9.045 218.16 9.315 ;
     RECT  2.16 9.585 218.16 9.855 ;
     RECT  2.16 10.125 218.16 10.395 ;
     RECT  2.16 10.665 218.16 10.935 ;
     RECT  2.16 11.205 218.16 11.475 ;
     RECT  2.16 11.745 218.16 12.015 ;
     RECT  2.16 12.285 218.16 12.555 ;
     RECT  2.16 12.825 218.16 13.095 ;
     RECT  2.16 13.365 218.16 13.635 ;
     RECT  2.16 13.905 218.16 14.175 ;
     RECT  2.16 14.445 218.16 14.715 ;
     RECT  2.16 14.985 218.16 15.255 ;
     RECT  2.16 15.525 218.16 15.795 ;
     RECT  2.16 16.065 218.16 16.335 ;
     RECT  2.16 16.605 218.16 16.875 ;
     RECT  2.16 17.145 218.16 17.415 ;
     RECT  2.16 17.685 218.16 17.955 ;
     RECT  2.16 18.225 218.16 18.495 ;
     RECT  2.16 18.765 218.16 19.035 ;
     RECT  2.16 19.305 218.16 19.575 ;
     RECT  2.16 19.845 218.16 20.115 ;
     RECT  2.16 20.385 218.16 20.655 ;
     RECT  2.16 20.925 218.16 21.195 ;
     RECT  2.16 21.465 218.16 21.735 ;
     RECT  2.16 22.005 218.16 22.275 ;
     RECT  2.16 22.545 218.16 22.815 ;
     RECT  2.16 23.085 218.16 23.355 ;
     RECT  2.16 23.625 218.16 23.895 ;
     RECT  2.16 24.165 218.16 24.435 ;
     RECT  2.16 24.705 218.16 24.975 ;
     RECT  2.16 25.245 218.16 25.515 ;
     RECT  2.16 25.785 218.16 25.92 ;
     RECT  2.16 25.92 20.844 26.055 ;
     RECT  199.692 25.92 218.16 26.055 ;
     RECT  2.16 26.325 20.844 26.595 ;
     RECT  199.692 26.325 218.16 26.595 ;
     RECT  2.16 26.865 20.844 27.135 ;
     RECT  199.692 26.865 218.16 27.135 ;
     RECT  2.16 27.405 20.844 27.675 ;
     RECT  199.692 27.405 218.16 27.675 ;
     RECT  2.16 27.945 20.844 28.215 ;
     RECT  199.692 27.945 218.16 28.215 ;
     RECT  2.16 28.485 20.844 28.755 ;
     RECT  199.692 28.485 218.16 28.755 ;
     RECT  2.16 29.025 20.844 29.295 ;
     RECT  199.692 29.025 218.16 29.295 ;
     RECT  2.16 29.565 20.844 29.835 ;
     RECT  199.692 29.565 218.16 29.835 ;
     RECT  2.16 30.105 20.844 30.375 ;
     RECT  199.692 30.105 218.16 30.375 ;
     RECT  2.16 30.645 20.844 30.915 ;
     RECT  199.692 30.645 218.16 30.915 ;
     RECT  2.16 31.185 20.844 31.455 ;
     RECT  199.692 31.185 218.16 31.455 ;
     RECT  2.16 31.725 20.844 31.995 ;
     RECT  199.692 31.725 218.16 31.995 ;
     RECT  2.16 32.265 20.844 32.535 ;
     RECT  199.692 32.265 218.16 32.535 ;
     RECT  2.16 32.805 20.844 33.075 ;
     RECT  199.692 32.805 218.16 33.075 ;
     RECT  2.16 33.345 20.844 33.615 ;
     RECT  199.692 33.345 218.16 33.615 ;
     RECT  2.16 33.885 20.844 34.155 ;
     RECT  199.692 33.885 218.16 34.155 ;
     RECT  2.16 34.425 20.844 34.695 ;
     RECT  199.692 34.425 218.16 34.695 ;
     RECT  2.16 34.965 20.844 35.235 ;
     RECT  199.692 34.965 218.16 35.235 ;
     RECT  2.16 35.505 20.844 35.775 ;
     RECT  199.692 35.505 218.16 35.775 ;
     RECT  2.16 36.045 20.844 36.315 ;
     RECT  199.692 36.045 218.16 36.315 ;
     RECT  2.16 36.585 20.844 36.855 ;
     RECT  199.692 36.585 218.16 36.855 ;
     RECT  2.16 37.125 20.844 37.395 ;
     RECT  199.692 37.125 218.16 37.395 ;
     RECT  2.16 37.665 20.844 37.935 ;
     RECT  199.692 37.665 218.16 37.935 ;
     RECT  2.16 38.205 20.844 38.475 ;
     RECT  199.692 38.205 218.16 38.475 ;
     RECT  2.16 38.745 20.844 39.015 ;
     RECT  199.692 38.745 218.16 39.015 ;
     RECT  2.16 39.285 20.844 39.555 ;
     RECT  199.692 39.285 218.16 39.555 ;
     RECT  2.16 39.825 20.844 40.095 ;
     RECT  199.692 39.825 218.16 40.095 ;
     RECT  2.16 40.365 20.844 40.635 ;
     RECT  199.692 40.365 218.16 40.635 ;
     RECT  2.16 40.905 20.844 41.175 ;
     RECT  199.692 40.905 218.16 41.175 ;
     RECT  2.16 41.445 20.844 41.715 ;
     RECT  199.692 41.445 218.16 41.715 ;
     RECT  2.16 41.985 20.844 42.255 ;
     RECT  199.692 41.985 218.16 42.255 ;
     RECT  2.16 42.525 20.844 42.795 ;
     RECT  199.692 42.525 218.16 42.795 ;
     RECT  2.16 43.065 20.844 43.335 ;
     RECT  199.692 43.065 218.16 43.335 ;
     RECT  2.16 43.605 20.844 43.875 ;
     RECT  199.692 43.605 218.16 43.875 ;
     RECT  2.16 44.145 20.844 44.415 ;
     RECT  199.692 44.145 218.16 44.415 ;
     RECT  2.16 44.685 20.844 44.955 ;
     RECT  199.692 44.685 218.16 44.955 ;
     RECT  2.16 45.225 20.844 45.495 ;
     RECT  199.692 45.225 218.16 45.495 ;
     RECT  2.16 45.765 20.844 46.035 ;
     RECT  199.692 45.765 218.16 46.035 ;
     RECT  2.16 46.305 20.844 46.575 ;
     RECT  199.692 46.305 218.16 46.575 ;
     RECT  2.16 46.845 20.844 47.115 ;
     RECT  199.692 46.845 218.16 47.115 ;
     RECT  2.16 47.385 20.844 47.655 ;
     RECT  199.692 47.385 218.16 47.655 ;
     RECT  2.16 47.925 20.844 48.195 ;
     RECT  199.692 47.925 218.16 48.195 ;
     RECT  2.16 48.465 20.844 48.735 ;
     RECT  199.692 48.465 218.16 48.735 ;
     RECT  2.16 49.005 20.844 49.275 ;
     RECT  199.692 49.005 218.16 49.275 ;
     RECT  2.16 49.545 20.844 49.815 ;
     RECT  199.692 49.545 218.16 49.815 ;
     RECT  2.16 50.085 20.844 50.355 ;
     RECT  199.692 50.085 218.16 50.355 ;
     RECT  2.16 50.625 20.844 50.895 ;
     RECT  199.692 50.625 218.16 50.895 ;
     RECT  2.16 51.165 20.844 51.435 ;
     RECT  199.692 51.165 218.16 51.435 ;
     RECT  2.16 51.705 20.844 51.975 ;
     RECT  199.692 51.705 218.16 51.975 ;
     RECT  2.16 52.245 20.844 52.515 ;
     RECT  199.692 52.245 218.16 52.515 ;
     RECT  2.16 52.785 20.844 53.055 ;
     RECT  199.692 52.785 218.16 53.055 ;
     RECT  2.16 53.325 20.844 53.595 ;
     RECT  199.692 53.325 218.16 53.595 ;
     RECT  2.16 53.865 20.844 54.135 ;
     RECT  199.692 53.865 218.16 54.135 ;
     RECT  2.16 54.405 20.844 54.675 ;
     RECT  199.692 54.405 218.16 54.675 ;
     RECT  2.16 54.945 20.844 55.215 ;
     RECT  199.692 54.945 218.16 55.215 ;
     RECT  2.16 55.485 20.844 55.755 ;
     RECT  199.692 55.485 218.16 55.755 ;
     RECT  2.16 56.025 20.844 56.295 ;
     RECT  199.692 56.025 218.16 56.295 ;
     RECT  2.16 56.565 20.844 56.835 ;
     RECT  199.692 56.565 218.16 56.835 ;
     RECT  2.16 57.105 20.844 57.375 ;
     RECT  199.692 57.105 218.16 57.375 ;
     RECT  2.16 57.645 20.844 57.915 ;
     RECT  199.692 57.645 218.16 57.915 ;
     RECT  2.16 58.185 20.844 58.455 ;
     RECT  199.692 58.185 218.16 58.455 ;
     RECT  2.16 58.725 20.844 58.995 ;
     RECT  199.692 58.725 218.16 58.995 ;
     RECT  2.16 59.265 20.844 59.535 ;
     RECT  199.692 59.265 218.16 59.535 ;
     RECT  2.16 59.805 20.844 60.075 ;
     RECT  199.692 59.805 218.16 60.075 ;
     RECT  2.16 60.345 20.844 60.615 ;
     RECT  199.692 60.345 218.16 60.615 ;
     RECT  2.16 60.885 20.844 61.155 ;
     RECT  199.692 60.885 218.16 61.155 ;
     RECT  2.16 61.425 20.844 61.695 ;
     RECT  199.692 61.425 218.16 61.695 ;
     RECT  2.16 61.965 20.844 62.235 ;
     RECT  199.692 61.965 218.16 62.235 ;
     RECT  2.16 62.505 20.844 62.775 ;
     RECT  199.692 62.505 218.16 62.775 ;
     RECT  2.16 63.045 20.844 63.315 ;
     RECT  199.692 63.045 218.16 63.315 ;
     RECT  2.16 63.585 20.844 63.855 ;
     RECT  199.692 63.585 218.16 63.855 ;
     RECT  2.16 64.125 20.844 64.395 ;
     RECT  199.692 64.125 218.16 64.395 ;
     RECT  2.16 64.665 20.844 64.935 ;
     RECT  199.692 64.665 218.16 64.935 ;
     RECT  2.16 65.205 20.844 65.475 ;
     RECT  199.692 65.205 218.16 65.475 ;
     RECT  2.16 65.745 20.844 66.015 ;
     RECT  199.692 65.745 218.16 66.015 ;
     RECT  2.16 66.285 20.844 66.555 ;
     RECT  199.692 66.285 218.16 66.555 ;
     RECT  2.16 66.825 20.844 67.095 ;
     RECT  199.692 66.825 218.16 67.095 ;
     RECT  2.16 67.365 20.844 67.635 ;
     RECT  199.692 67.365 218.16 67.635 ;
     RECT  2.16 67.905 20.844 68.175 ;
     RECT  199.692 67.905 218.16 68.175 ;
     RECT  2.16 68.445 20.844 68.715 ;
     RECT  199.692 68.445 218.16 68.715 ;
     RECT  2.16 68.985 20.844 69.255 ;
     RECT  199.692 68.985 218.16 69.255 ;
     RECT  2.16 69.525 20.844 69.795 ;
     RECT  199.692 69.525 218.16 69.795 ;
     RECT  2.16 70.065 20.844 70.335 ;
     RECT  199.692 70.065 218.16 70.335 ;
     RECT  2.16 70.605 20.844 70.875 ;
     RECT  199.692 70.605 218.16 70.875 ;
     RECT  2.16 71.145 20.844 71.415 ;
     RECT  199.692 71.145 218.16 71.415 ;
     RECT  2.16 71.685 20.844 71.955 ;
     RECT  199.692 71.685 218.16 71.955 ;
     RECT  2.16 72.225 20.844 72.495 ;
     RECT  199.692 72.225 218.16 72.495 ;
     RECT  2.16 72.765 20.844 73.035 ;
     RECT  199.692 72.765 218.16 73.035 ;
     RECT  2.16 73.305 20.844 73.575 ;
     RECT  199.692 73.305 218.16 73.575 ;
     RECT  2.16 73.845 20.844 74.115 ;
     RECT  199.692 73.845 218.16 74.115 ;
     RECT  2.16 74.385 20.844 74.655 ;
     RECT  199.692 74.385 218.16 74.655 ;
     RECT  2.16 74.925 20.844 75.195 ;
     RECT  199.692 74.925 218.16 75.195 ;
     RECT  2.16 75.465 20.844 75.735 ;
     RECT  199.692 75.465 218.16 75.735 ;
     RECT  2.16 76.005 20.844 76.275 ;
     RECT  199.692 76.005 218.16 76.275 ;
     RECT  2.16 76.545 20.844 76.815 ;
     RECT  199.692 76.545 218.16 76.815 ;
     RECT  2.16 77.085 20.844 77.355 ;
     RECT  199.692 77.085 218.16 77.355 ;
     RECT  2.16 77.625 20.844 77.895 ;
     RECT  199.692 77.625 218.16 77.895 ;
     RECT  2.16 78.165 20.844 78.435 ;
     RECT  199.692 78.165 218.16 78.435 ;
     RECT  2.16 78.705 20.844 78.975 ;
     RECT  199.692 78.705 218.16 78.975 ;
     RECT  2.16 79.245 20.844 79.515 ;
     RECT  199.692 79.245 218.16 79.515 ;
     RECT  2.16 79.785 20.844 80.055 ;
     RECT  199.692 79.785 218.16 80.055 ;
     RECT  2.16 80.325 20.844 80.595 ;
     RECT  199.692 80.325 218.16 80.595 ;
     RECT  2.16 80.865 20.844 81.135 ;
     RECT  199.692 80.865 218.16 81.135 ;
     RECT  2.16 81.405 20.844 81.675 ;
     RECT  199.692 81.405 218.16 81.675 ;
     RECT  2.16 81.945 20.844 82.215 ;
     RECT  199.692 81.945 218.16 82.215 ;
     RECT  2.16 82.485 20.844 82.755 ;
     RECT  199.692 82.485 218.16 82.755 ;
     RECT  2.16 83.025 20.844 83.295 ;
     RECT  199.692 83.025 218.16 83.295 ;
     RECT  2.16 83.565 20.844 83.835 ;
     RECT  199.692 83.565 218.16 83.835 ;
     RECT  2.16 84.105 20.844 84.375 ;
     RECT  199.692 84.105 218.16 84.375 ;
     RECT  2.16 84.645 20.844 84.915 ;
     RECT  199.692 84.645 218.16 84.915 ;
     RECT  2.16 85.185 20.844 85.455 ;
     RECT  199.692 85.185 218.16 85.455 ;
     RECT  2.16 85.725 20.844 85.995 ;
     RECT  199.692 85.725 218.16 85.995 ;
     RECT  2.16 86.265 20.844 86.535 ;
     RECT  199.692 86.265 218.16 86.535 ;
     RECT  2.16 86.805 20.844 87.075 ;
     RECT  199.692 86.805 218.16 87.075 ;
     RECT  2.16 87.345 20.844 87.615 ;
     RECT  199.692 87.345 218.16 87.615 ;
     RECT  2.16 87.885 20.844 88.155 ;
     RECT  199.692 87.885 218.16 88.155 ;
     RECT  2.16 88.425 20.844 88.695 ;
     RECT  199.692 88.425 218.16 88.695 ;
     RECT  2.16 88.965 20.844 89.235 ;
     RECT  199.692 88.965 218.16 89.235 ;
     RECT  2.16 89.505 20.844 89.775 ;
     RECT  199.692 89.505 218.16 89.775 ;
     RECT  2.16 90.045 20.844 90.315 ;
     RECT  199.692 90.045 218.16 90.315 ;
     RECT  2.16 90.585 20.844 90.855 ;
     RECT  199.692 90.585 218.16 90.855 ;
     RECT  2.16 91.125 20.844 91.395 ;
     RECT  199.692 91.125 218.16 91.395 ;
     RECT  2.16 91.665 20.844 91.935 ;
     RECT  199.692 91.665 218.16 91.935 ;
     RECT  2.16 92.205 20.844 92.475 ;
     RECT  199.692 92.205 218.16 92.475 ;
     RECT  2.16 92.745 20.844 93.015 ;
     RECT  199.692 92.745 218.16 93.015 ;
     RECT  2.16 93.285 20.844 93.555 ;
     RECT  199.692 93.285 218.16 93.555 ;
     RECT  2.16 93.825 20.844 94.095 ;
     RECT  199.692 93.825 218.16 94.095 ;
     RECT  2.16 94.365 20.844 94.635 ;
     RECT  199.692 94.365 218.16 94.635 ;
     RECT  2.16 94.905 20.844 95.175 ;
     RECT  199.692 94.905 218.16 95.175 ;
     RECT  2.16 95.445 20.844 95.715 ;
     RECT  199.692 95.445 218.16 95.715 ;
     RECT  2.16 95.985 20.844 96.255 ;
     RECT  199.692 95.985 218.16 96.255 ;
     RECT  2.16 96.525 20.844 96.795 ;
     RECT  199.692 96.525 218.16 96.795 ;
     RECT  2.16 97.065 20.844 97.335 ;
     RECT  199.692 97.065 218.16 97.335 ;
     RECT  2.16 97.605 20.844 97.875 ;
     RECT  199.692 97.605 218.16 97.875 ;
     RECT  2.16 98.145 20.844 98.415 ;
     RECT  199.692 98.145 218.16 98.415 ;
     RECT  2.16 98.685 20.844 98.955 ;
     RECT  199.692 98.685 218.16 98.955 ;
     RECT  2.16 99.225 20.844 99.495 ;
     RECT  199.692 99.225 218.16 99.495 ;
     RECT  2.16 99.765 20.844 100.035 ;
     RECT  199.692 99.765 218.16 100.035 ;
     RECT  2.16 100.305 20.844 100.575 ;
     RECT  199.692 100.305 218.16 100.575 ;
     RECT  2.16 100.845 218.16 101.115 ;
     RECT  2.16 101.385 218.16 101.655 ;
     RECT  2.16 101.925 218.16 102.195 ;
     RECT  2.16 102.465 218.16 102.735 ;
     RECT  2.16 103.005 218.16 103.275 ;
     RECT  2.16 103.545 218.16 103.815 ;
     RECT  2.16 104.085 218.16 104.355 ;
     RECT  2.16 104.625 218.16 104.895 ;
     RECT  2.16 105.165 218.16 105.435 ;
     RECT  2.16 105.705 218.16 105.975 ;
     RECT  2.16 106.245 218.16 106.515 ;
     RECT  2.16 106.785 218.16 107.055 ;
     RECT  2.16 107.325 218.16 107.595 ;
     RECT  2.16 107.865 218.16 108.135 ;
     RECT  2.16 108.405 218.16 108.675 ;
     RECT  2.16 108.945 218.16 109.215 ;
     RECT  2.16 109.485 218.16 109.755 ;
     RECT  2.16 110.025 218.16 110.295 ;
     RECT  2.16 110.565 218.16 110.835 ;
     RECT  2.16 111.105 218.16 111.375 ;
     RECT  2.16 111.645 218.16 111.915 ;
     RECT  2.16 112.185 218.16 112.455 ;
     RECT  2.16 112.725 218.16 112.995 ;
     RECT  2.16 113.265 218.16 113.535 ;
     RECT  2.16 113.805 218.16 114.075 ;
     RECT  2.16 114.345 218.16 114.615 ;
     RECT  2.16 114.885 218.16 115.155 ;
     RECT  2.16 115.425 218.16 115.695 ;
     RECT  2.16 115.965 218.16 116.235 ;
     RECT  2.16 116.505 218.16 116.775 ;
     RECT  2.16 117.045 218.16 117.315 ;
     RECT  2.16 117.585 218.16 117.855 ;
     RECT  2.16 118.125 218.16 118.395 ;
     RECT  2.16 118.665 218.16 118.935 ;
     RECT  2.16 119.205 218.16 119.475 ;
     RECT  2.16 119.745 218.16 120.015 ;
     RECT  2.16 120.285 218.16 120.555 ;
     RECT  2.16 120.825 218.16 121.095 ;
     RECT  2.16 121.365 218.16 121.635 ;
     RECT  2.16 121.905 218.16 122.175 ;
     RECT  2.16 122.445 218.16 122.715 ;
     RECT  2.16 122.985 218.16 123.255 ;
     RECT  2.16 123.525 218.16 123.795 ;
     RECT  2.16 124.065 218.16 124.335 ;
     RECT  2.16 124.605 218.16 124.875 ;
     RECT  2.16 125.145 218.16 125.415 ;
     RECT  2.16 125.685 218.16 125.955 ;
     RECT  2.16 126.225 218.16 126.495 ;
     RECT  2.16 126.765 218.16 127.035 ;
     RECT  2.16 127.305 218.16 127.44 ;
    LAYER RVTP ;
     RECT  2.16 2.295 218.16 2.565 ;
     RECT  2.16 2.835 218.16 3.105 ;
     RECT  2.16 3.375 218.16 3.645 ;
     RECT  2.16 3.915 218.16 4.185 ;
     RECT  2.16 4.455 218.16 4.725 ;
     RECT  2.16 4.995 218.16 5.265 ;
     RECT  2.16 5.535 218.16 5.805 ;
     RECT  2.16 6.075 218.16 6.345 ;
     RECT  2.16 6.615 218.16 6.885 ;
     RECT  2.16 7.155 218.16 7.425 ;
     RECT  2.16 7.695 218.16 7.965 ;
     RECT  2.16 8.235 218.16 8.505 ;
     RECT  2.16 8.775 218.16 9.045 ;
     RECT  2.16 9.315 218.16 9.585 ;
     RECT  2.16 9.855 218.16 10.125 ;
     RECT  2.16 10.395 218.16 10.665 ;
     RECT  2.16 10.935 218.16 11.205 ;
     RECT  2.16 11.475 218.16 11.745 ;
     RECT  2.16 12.015 218.16 12.285 ;
     RECT  2.16 12.555 218.16 12.825 ;
     RECT  2.16 13.095 218.16 13.365 ;
     RECT  2.16 13.635 218.16 13.905 ;
     RECT  2.16 14.175 218.16 14.445 ;
     RECT  2.16 14.715 218.16 14.985 ;
     RECT  2.16 15.255 218.16 15.525 ;
     RECT  2.16 15.795 218.16 16.065 ;
     RECT  2.16 16.335 218.16 16.605 ;
     RECT  2.16 16.875 218.16 17.145 ;
     RECT  2.16 17.415 218.16 17.685 ;
     RECT  2.16 17.955 218.16 18.225 ;
     RECT  2.16 18.495 218.16 18.765 ;
     RECT  2.16 19.035 218.16 19.305 ;
     RECT  2.16 19.575 218.16 19.845 ;
     RECT  2.16 20.115 218.16 20.385 ;
     RECT  2.16 20.655 218.16 20.925 ;
     RECT  2.16 21.195 218.16 21.465 ;
     RECT  2.16 21.735 218.16 22.005 ;
     RECT  2.16 22.275 218.16 22.545 ;
     RECT  2.16 22.815 218.16 23.085 ;
     RECT  2.16 23.355 218.16 23.625 ;
     RECT  2.16 23.895 218.16 24.165 ;
     RECT  2.16 24.435 218.16 24.705 ;
     RECT  2.16 24.975 218.16 25.245 ;
     RECT  2.16 25.515 218.16 25.785 ;
     RECT  2.16 26.055 20.844 26.325 ;
     RECT  199.692 26.055 218.16 26.325 ;
     RECT  2.16 26.595 20.844 26.865 ;
     RECT  199.692 26.595 218.16 26.865 ;
     RECT  2.16 27.135 20.844 27.405 ;
     RECT  199.692 27.135 218.16 27.405 ;
     RECT  2.16 27.675 20.844 27.945 ;
     RECT  199.692 27.675 218.16 27.945 ;
     RECT  2.16 28.215 20.844 28.485 ;
     RECT  199.692 28.215 218.16 28.485 ;
     RECT  2.16 28.755 20.844 29.025 ;
     RECT  199.692 28.755 218.16 29.025 ;
     RECT  2.16 29.295 20.844 29.565 ;
     RECT  199.692 29.295 218.16 29.565 ;
     RECT  2.16 29.835 20.844 30.105 ;
     RECT  199.692 29.835 218.16 30.105 ;
     RECT  2.16 30.375 20.844 30.645 ;
     RECT  199.692 30.375 218.16 30.645 ;
     RECT  2.16 30.915 20.844 31.185 ;
     RECT  199.692 30.915 218.16 31.185 ;
     RECT  2.16 31.455 20.844 31.725 ;
     RECT  199.692 31.455 218.16 31.725 ;
     RECT  2.16 31.995 20.844 32.265 ;
     RECT  199.692 31.995 218.16 32.265 ;
     RECT  2.16 32.535 20.844 32.805 ;
     RECT  199.692 32.535 218.16 32.805 ;
     RECT  2.16 33.075 20.844 33.345 ;
     RECT  199.692 33.075 218.16 33.345 ;
     RECT  2.16 33.615 20.844 33.885 ;
     RECT  199.692 33.615 218.16 33.885 ;
     RECT  2.16 34.155 20.844 34.425 ;
     RECT  199.692 34.155 218.16 34.425 ;
     RECT  2.16 34.695 20.844 34.965 ;
     RECT  199.692 34.695 218.16 34.965 ;
     RECT  2.16 35.235 20.844 35.505 ;
     RECT  199.692 35.235 218.16 35.505 ;
     RECT  2.16 35.775 20.844 36.045 ;
     RECT  199.692 35.775 218.16 36.045 ;
     RECT  2.16 36.315 20.844 36.585 ;
     RECT  199.692 36.315 218.16 36.585 ;
     RECT  2.16 36.855 20.844 37.125 ;
     RECT  199.692 36.855 218.16 37.125 ;
     RECT  2.16 37.395 20.844 37.665 ;
     RECT  199.692 37.395 218.16 37.665 ;
     RECT  2.16 37.935 20.844 38.205 ;
     RECT  199.692 37.935 218.16 38.205 ;
     RECT  2.16 38.475 20.844 38.745 ;
     RECT  199.692 38.475 218.16 38.745 ;
     RECT  2.16 39.015 20.844 39.285 ;
     RECT  199.692 39.015 218.16 39.285 ;
     RECT  2.16 39.555 20.844 39.825 ;
     RECT  199.692 39.555 218.16 39.825 ;
     RECT  2.16 40.095 20.844 40.365 ;
     RECT  199.692 40.095 218.16 40.365 ;
     RECT  2.16 40.635 20.844 40.905 ;
     RECT  199.692 40.635 218.16 40.905 ;
     RECT  2.16 41.175 20.844 41.445 ;
     RECT  199.692 41.175 218.16 41.445 ;
     RECT  2.16 41.715 20.844 41.985 ;
     RECT  199.692 41.715 218.16 41.985 ;
     RECT  2.16 42.255 20.844 42.525 ;
     RECT  199.692 42.255 218.16 42.525 ;
     RECT  2.16 42.795 20.844 43.065 ;
     RECT  199.692 42.795 218.16 43.065 ;
     RECT  2.16 43.335 20.844 43.605 ;
     RECT  199.692 43.335 218.16 43.605 ;
     RECT  2.16 43.875 20.844 44.145 ;
     RECT  199.692 43.875 218.16 44.145 ;
     RECT  2.16 44.415 20.844 44.685 ;
     RECT  199.692 44.415 218.16 44.685 ;
     RECT  2.16 44.955 20.844 45.225 ;
     RECT  199.692 44.955 218.16 45.225 ;
     RECT  2.16 45.495 20.844 45.765 ;
     RECT  199.692 45.495 218.16 45.765 ;
     RECT  2.16 46.035 20.844 46.305 ;
     RECT  199.692 46.035 218.16 46.305 ;
     RECT  2.16 46.575 20.844 46.845 ;
     RECT  199.692 46.575 218.16 46.845 ;
     RECT  2.16 47.115 20.844 47.385 ;
     RECT  199.692 47.115 218.16 47.385 ;
     RECT  2.16 47.655 20.844 47.925 ;
     RECT  199.692 47.655 218.16 47.925 ;
     RECT  2.16 48.195 20.844 48.465 ;
     RECT  199.692 48.195 218.16 48.465 ;
     RECT  2.16 48.735 20.844 49.005 ;
     RECT  199.692 48.735 218.16 49.005 ;
     RECT  2.16 49.275 20.844 49.545 ;
     RECT  199.692 49.275 218.16 49.545 ;
     RECT  2.16 49.815 20.844 50.085 ;
     RECT  199.692 49.815 218.16 50.085 ;
     RECT  2.16 50.355 20.844 50.625 ;
     RECT  199.692 50.355 218.16 50.625 ;
     RECT  2.16 50.895 20.844 51.165 ;
     RECT  199.692 50.895 218.16 51.165 ;
     RECT  2.16 51.435 20.844 51.705 ;
     RECT  199.692 51.435 218.16 51.705 ;
     RECT  2.16 51.975 20.844 52.245 ;
     RECT  199.692 51.975 218.16 52.245 ;
     RECT  2.16 52.515 20.844 52.785 ;
     RECT  199.692 52.515 218.16 52.785 ;
     RECT  2.16 53.055 20.844 53.325 ;
     RECT  199.692 53.055 218.16 53.325 ;
     RECT  2.16 53.595 20.844 53.865 ;
     RECT  199.692 53.595 218.16 53.865 ;
     RECT  2.16 54.135 20.844 54.405 ;
     RECT  199.692 54.135 218.16 54.405 ;
     RECT  2.16 54.675 20.844 54.945 ;
     RECT  199.692 54.675 218.16 54.945 ;
     RECT  2.16 55.215 20.844 55.485 ;
     RECT  199.692 55.215 218.16 55.485 ;
     RECT  2.16 55.755 20.844 56.025 ;
     RECT  199.692 55.755 218.16 56.025 ;
     RECT  2.16 56.295 20.844 56.565 ;
     RECT  199.692 56.295 218.16 56.565 ;
     RECT  2.16 56.835 20.844 57.105 ;
     RECT  199.692 56.835 218.16 57.105 ;
     RECT  2.16 57.375 20.844 57.645 ;
     RECT  199.692 57.375 218.16 57.645 ;
     RECT  2.16 57.915 20.844 58.185 ;
     RECT  199.692 57.915 218.16 58.185 ;
     RECT  2.16 58.455 20.844 58.725 ;
     RECT  199.692 58.455 218.16 58.725 ;
     RECT  2.16 58.995 20.844 59.265 ;
     RECT  199.692 58.995 218.16 59.265 ;
     RECT  2.16 59.535 20.844 59.805 ;
     RECT  199.692 59.535 218.16 59.805 ;
     RECT  2.16 60.075 20.844 60.345 ;
     RECT  199.692 60.075 218.16 60.345 ;
     RECT  2.16 60.615 20.844 60.885 ;
     RECT  199.692 60.615 218.16 60.885 ;
     RECT  2.16 61.155 20.844 61.425 ;
     RECT  199.692 61.155 218.16 61.425 ;
     RECT  2.16 61.695 20.844 61.965 ;
     RECT  199.692 61.695 218.16 61.965 ;
     RECT  2.16 62.235 20.844 62.505 ;
     RECT  199.692 62.235 218.16 62.505 ;
     RECT  2.16 62.775 20.844 63.045 ;
     RECT  199.692 62.775 218.16 63.045 ;
     RECT  2.16 63.315 20.844 63.585 ;
     RECT  199.692 63.315 218.16 63.585 ;
     RECT  2.16 63.855 20.844 64.125 ;
     RECT  199.692 63.855 218.16 64.125 ;
     RECT  2.16 64.395 20.844 64.665 ;
     RECT  199.692 64.395 218.16 64.665 ;
     RECT  2.16 64.935 20.844 65.205 ;
     RECT  199.692 64.935 218.16 65.205 ;
     RECT  2.16 65.475 20.844 65.745 ;
     RECT  199.692 65.475 218.16 65.745 ;
     RECT  2.16 66.015 20.844 66.285 ;
     RECT  199.692 66.015 218.16 66.285 ;
     RECT  2.16 66.555 20.844 66.825 ;
     RECT  199.692 66.555 218.16 66.825 ;
     RECT  2.16 67.095 20.844 67.365 ;
     RECT  199.692 67.095 218.16 67.365 ;
     RECT  2.16 67.635 20.844 67.905 ;
     RECT  199.692 67.635 218.16 67.905 ;
     RECT  2.16 68.175 20.844 68.445 ;
     RECT  199.692 68.175 218.16 68.445 ;
     RECT  2.16 68.715 20.844 68.985 ;
     RECT  199.692 68.715 218.16 68.985 ;
     RECT  2.16 69.255 20.844 69.525 ;
     RECT  199.692 69.255 218.16 69.525 ;
     RECT  2.16 69.795 20.844 70.065 ;
     RECT  199.692 69.795 218.16 70.065 ;
     RECT  2.16 70.335 20.844 70.605 ;
     RECT  199.692 70.335 218.16 70.605 ;
     RECT  2.16 70.875 20.844 71.145 ;
     RECT  199.692 70.875 218.16 71.145 ;
     RECT  2.16 71.415 20.844 71.685 ;
     RECT  199.692 71.415 218.16 71.685 ;
     RECT  2.16 71.955 20.844 72.225 ;
     RECT  199.692 71.955 218.16 72.225 ;
     RECT  2.16 72.495 20.844 72.765 ;
     RECT  199.692 72.495 218.16 72.765 ;
     RECT  2.16 73.035 20.844 73.305 ;
     RECT  199.692 73.035 218.16 73.305 ;
     RECT  2.16 73.575 20.844 73.845 ;
     RECT  199.692 73.575 218.16 73.845 ;
     RECT  2.16 74.115 20.844 74.385 ;
     RECT  199.692 74.115 218.16 74.385 ;
     RECT  2.16 74.655 20.844 74.925 ;
     RECT  199.692 74.655 218.16 74.925 ;
     RECT  2.16 75.195 20.844 75.465 ;
     RECT  199.692 75.195 218.16 75.465 ;
     RECT  2.16 75.735 20.844 76.005 ;
     RECT  199.692 75.735 218.16 76.005 ;
     RECT  2.16 76.275 20.844 76.545 ;
     RECT  199.692 76.275 218.16 76.545 ;
     RECT  2.16 76.815 20.844 77.085 ;
     RECT  199.692 76.815 218.16 77.085 ;
     RECT  2.16 77.355 20.844 77.625 ;
     RECT  199.692 77.355 218.16 77.625 ;
     RECT  2.16 77.895 20.844 78.165 ;
     RECT  199.692 77.895 218.16 78.165 ;
     RECT  2.16 78.435 20.844 78.705 ;
     RECT  199.692 78.435 218.16 78.705 ;
     RECT  2.16 78.975 20.844 79.245 ;
     RECT  199.692 78.975 218.16 79.245 ;
     RECT  2.16 79.515 20.844 79.785 ;
     RECT  199.692 79.515 218.16 79.785 ;
     RECT  2.16 80.055 20.844 80.325 ;
     RECT  199.692 80.055 218.16 80.325 ;
     RECT  2.16 80.595 20.844 80.865 ;
     RECT  199.692 80.595 218.16 80.865 ;
     RECT  2.16 81.135 20.844 81.405 ;
     RECT  199.692 81.135 218.16 81.405 ;
     RECT  2.16 81.675 20.844 81.945 ;
     RECT  199.692 81.675 218.16 81.945 ;
     RECT  2.16 82.215 20.844 82.485 ;
     RECT  199.692 82.215 218.16 82.485 ;
     RECT  2.16 82.755 20.844 83.025 ;
     RECT  199.692 82.755 218.16 83.025 ;
     RECT  2.16 83.295 20.844 83.565 ;
     RECT  199.692 83.295 218.16 83.565 ;
     RECT  2.16 83.835 20.844 84.105 ;
     RECT  199.692 83.835 218.16 84.105 ;
     RECT  2.16 84.375 20.844 84.645 ;
     RECT  199.692 84.375 218.16 84.645 ;
     RECT  2.16 84.915 20.844 85.185 ;
     RECT  199.692 84.915 218.16 85.185 ;
     RECT  2.16 85.455 20.844 85.725 ;
     RECT  199.692 85.455 218.16 85.725 ;
     RECT  2.16 85.995 20.844 86.265 ;
     RECT  199.692 85.995 218.16 86.265 ;
     RECT  2.16 86.535 20.844 86.805 ;
     RECT  199.692 86.535 218.16 86.805 ;
     RECT  2.16 87.075 20.844 87.345 ;
     RECT  199.692 87.075 218.16 87.345 ;
     RECT  2.16 87.615 20.844 87.885 ;
     RECT  199.692 87.615 218.16 87.885 ;
     RECT  2.16 88.155 20.844 88.425 ;
     RECT  199.692 88.155 218.16 88.425 ;
     RECT  2.16 88.695 20.844 88.965 ;
     RECT  199.692 88.695 218.16 88.965 ;
     RECT  2.16 89.235 20.844 89.505 ;
     RECT  199.692 89.235 218.16 89.505 ;
     RECT  2.16 89.775 20.844 90.045 ;
     RECT  199.692 89.775 218.16 90.045 ;
     RECT  2.16 90.315 20.844 90.585 ;
     RECT  199.692 90.315 218.16 90.585 ;
     RECT  2.16 90.855 20.844 91.125 ;
     RECT  199.692 90.855 218.16 91.125 ;
     RECT  2.16 91.395 20.844 91.665 ;
     RECT  199.692 91.395 218.16 91.665 ;
     RECT  2.16 91.935 20.844 92.205 ;
     RECT  199.692 91.935 218.16 92.205 ;
     RECT  2.16 92.475 20.844 92.745 ;
     RECT  199.692 92.475 218.16 92.745 ;
     RECT  2.16 93.015 20.844 93.285 ;
     RECT  199.692 93.015 218.16 93.285 ;
     RECT  2.16 93.555 20.844 93.825 ;
     RECT  199.692 93.555 218.16 93.825 ;
     RECT  2.16 94.095 20.844 94.365 ;
     RECT  199.692 94.095 218.16 94.365 ;
     RECT  2.16 94.635 20.844 94.905 ;
     RECT  199.692 94.635 218.16 94.905 ;
     RECT  2.16 95.175 20.844 95.445 ;
     RECT  199.692 95.175 218.16 95.445 ;
     RECT  2.16 95.715 20.844 95.985 ;
     RECT  199.692 95.715 218.16 95.985 ;
     RECT  2.16 96.255 20.844 96.525 ;
     RECT  199.692 96.255 218.16 96.525 ;
     RECT  2.16 96.795 20.844 97.065 ;
     RECT  199.692 96.795 218.16 97.065 ;
     RECT  2.16 97.335 20.844 97.605 ;
     RECT  199.692 97.335 218.16 97.605 ;
     RECT  2.16 97.875 20.844 98.145 ;
     RECT  199.692 97.875 218.16 98.145 ;
     RECT  2.16 98.415 20.844 98.685 ;
     RECT  199.692 98.415 218.16 98.685 ;
     RECT  2.16 98.955 20.844 99.225 ;
     RECT  199.692 98.955 218.16 99.225 ;
     RECT  2.16 99.495 20.844 99.765 ;
     RECT  199.692 99.495 218.16 99.765 ;
     RECT  2.16 100.035 20.844 100.305 ;
     RECT  199.692 100.035 218.16 100.305 ;
     RECT  2.16 100.575 20.844 100.71 ;
     RECT  199.692 100.575 218.16 100.71 ;
     RECT  2.16 100.71 218.16 100.845 ;
     RECT  2.16 101.115 218.16 101.385 ;
     RECT  2.16 101.655 218.16 101.925 ;
     RECT  2.16 102.195 218.16 102.465 ;
     RECT  2.16 102.735 218.16 103.005 ;
     RECT  2.16 103.275 218.16 103.545 ;
     RECT  2.16 103.815 218.16 104.085 ;
     RECT  2.16 104.355 218.16 104.625 ;
     RECT  2.16 104.895 218.16 105.165 ;
     RECT  2.16 105.435 218.16 105.705 ;
     RECT  2.16 105.975 218.16 106.245 ;
     RECT  2.16 106.515 218.16 106.785 ;
     RECT  2.16 107.055 218.16 107.325 ;
     RECT  2.16 107.595 218.16 107.865 ;
     RECT  2.16 108.135 218.16 108.405 ;
     RECT  2.16 108.675 218.16 108.945 ;
     RECT  2.16 109.215 218.16 109.485 ;
     RECT  2.16 109.755 218.16 110.025 ;
     RECT  2.16 110.295 218.16 110.565 ;
     RECT  2.16 110.835 218.16 111.105 ;
     RECT  2.16 111.375 218.16 111.645 ;
     RECT  2.16 111.915 218.16 112.185 ;
     RECT  2.16 112.455 218.16 112.725 ;
     RECT  2.16 112.995 218.16 113.265 ;
     RECT  2.16 113.535 218.16 113.805 ;
     RECT  2.16 114.075 218.16 114.345 ;
     RECT  2.16 114.615 218.16 114.885 ;
     RECT  2.16 115.155 218.16 115.425 ;
     RECT  2.16 115.695 218.16 115.965 ;
     RECT  2.16 116.235 218.16 116.505 ;
     RECT  2.16 116.775 218.16 117.045 ;
     RECT  2.16 117.315 218.16 117.585 ;
     RECT  2.16 117.855 218.16 118.125 ;
     RECT  2.16 118.395 218.16 118.665 ;
     RECT  2.16 118.935 218.16 119.205 ;
     RECT  2.16 119.475 218.16 119.745 ;
     RECT  2.16 120.015 218.16 120.285 ;
     RECT  2.16 120.555 218.16 120.825 ;
     RECT  2.16 121.095 218.16 121.365 ;
     RECT  2.16 121.635 218.16 121.905 ;
     RECT  2.16 122.175 218.16 122.445 ;
     RECT  2.16 122.715 218.16 122.985 ;
     RECT  2.16 123.255 218.16 123.525 ;
     RECT  2.16 123.795 218.16 124.065 ;
     RECT  2.16 124.335 218.16 124.605 ;
     RECT  2.16 124.875 218.16 125.145 ;
     RECT  2.16 125.415 218.16 125.685 ;
     RECT  2.16 125.955 218.16 126.225 ;
     RECT  2.16 126.495 218.16 126.765 ;
     RECT  2.16 127.035 218.16 127.305 ;
    LAYER M1 ;
     RECT  2.16 2.151 218.16 25.929 ;
     RECT  22.896 28.08 197.64 98.55 ;
     RECT  2.16 25.929 20.844 100.701 ;
     RECT  199.692 25.929 218.16 100.701 ;
     RECT  2.16 100.701 218.16 127.449 ;
    LAYER M2 ;
     RECT  0.103 11.142 0.139 11.16 ;
     RECT  0.103 11.952 0.139 12.51 ;
     RECT  0.103 29.502 0.139 30.6 ;
     RECT  0.103 114.552 0.139 115.92 ;
     RECT  0.103 118.134 0.139 119.16 ;
     RECT  0.103 120.222 0.139 122.13 ;
     RECT  0.139 11.142 0.535 12.51 ;
     RECT  0.103 13.41 0.535 13.86 ;
     RECT  0.103 17.892 0.535 19.8 ;
     RECT  0.139 29.502 0.535 30.672 ;
     RECT  0.103 31.662 0.535 36.27 ;
     RECT  0.103 37.332 0.535 38.97 ;
     RECT  0.103 40.302 0.535 41.778 ;
     RECT  0.103 42.732 0.535 43.56 ;
     RECT  0.103 44.352 0.535 46.836 ;
     RECT  0.103 47.592 0.535 47.61 ;
     RECT  0.103 48.402 0.535 49.806 ;
     RECT  0.103 62.442 0.535 63.144 ;
     RECT  0.103 64.062 0.535 65.268 ;
     RECT  0.103 66.258 0.535 66.276 ;
     RECT  0.103 67.032 0.535 69.75 ;
     RECT  0.103 70.542 0.535 71.208 ;
     RECT  0.103 72.162 0.535 74.34 ;
     RECT  0.103 75.132 0.535 77.31 ;
     RECT  0.103 81.882 0.535 83.79 ;
     RECT  0.103 84.654 0.535 88.38 ;
     RECT  0.103 89.172 0.535 91.35 ;
     RECT  0.103 95.112 0.535 96.318 ;
     RECT  0.103 97.92 0.535 97.938 ;
     RECT  0.103 98.892 0.535 99.45 ;
     RECT  0.103 106.218 0.535 107.55 ;
     RECT  0.103 108.612 0.535 109.17 ;
     RECT  0.103 111.852 0.535 111.87 ;
     RECT  0.103 113.472 0.535 113.49 ;
     RECT  0.535 17.424 1.723 20.07 ;
     RECT  0.103 53.532 1.723 60.03 ;
     RECT  0.103 92.142 1.723 94.32 ;
     RECT  0.535 95.112 1.723 96.822 ;
     RECT  0.103 4.194 2.16 4.212 ;
     RECT  0.103 6.552 2.16 9 ;
     RECT  0.535 11.142 2.16 14.4 ;
     RECT  1.723 17.082 2.16 20.07 ;
     RECT  0.103 20.862 2.16 28.71 ;
     RECT  0.535 29.502 2.16 41.778 ;
     RECT  0.535 42.732 2.16 46.836 ;
     RECT  0.535 47.592 2.16 49.806 ;
     RECT  0.103 50.562 2.16 51.426 ;
     RECT  0.103 52.182 2.16 52.2 ;
     RECT  1.723 52.992 2.16 60.03 ;
     RECT  0.103 60.822 2.16 61.65 ;
     RECT  0.535 62.442 2.16 66.276 ;
     RECT  0.535 67.032 2.16 77.31 ;
     RECT  0.103 78.372 2.16 81.09 ;
     RECT  0.535 81.882 2.16 91.35 ;
     RECT  1.723 92.142 2.16 96.858 ;
     RECT  0.535 97.65 2.16 99.522 ;
     RECT  0.103 100.782 2.16 101.07 ;
     RECT  0.535 105.714 2.16 109.17 ;
     RECT  0.103 109.962 2.16 109.98 ;
     RECT  0.535 111.852 2.16 112.248 ;
     RECT  0.535 113.04 2.16 113.49 ;
     RECT  0.139 114.39 2.16 115.92 ;
     RECT  0.139 118.134 2.16 122.13 ;
     RECT  0.103 125.622 2.16 125.64 ;
     RECT  2.16 2.151 20.844 127.449 ;
     RECT  20.844 31.77 20.867 34.344 ;
     RECT  20.844 92.646 20.867 95.904 ;
     RECT  20.844 85.428 20.903 86.454 ;
     RECT  20.867 92.826 20.939 95.904 ;
     RECT  20.844 2.151 21.083 30.906 ;
     RECT  20.939 93.33 21.119 95.904 ;
     RECT  20.844 96.696 21.299 127.449 ;
     RECT  20.844 79.326 21.371 79.344 ;
     RECT  20.844 70.578 21.407 70.596 ;
     RECT  20.844 77.4 21.407 78.228 ;
     RECT  21.407 77.868 21.443 78.228 ;
     RECT  20.844 83.196 21.479 83.394 ;
     RECT  20.844 80.64 21.515 81.234 ;
     RECT  21.119 93.33 21.551 95.508 ;
     RECT  20.867 31.77 21.623 34.146 ;
     RECT  21.299 97.614 21.623 127.449 ;
     RECT  21.083 30.006 21.659 30.906 ;
     RECT  21.623 31.77 21.659 31.788 ;
     RECT  20.844 35.55 21.659 68.814 ;
     RECT  20.844 84.348 21.659 84.366 ;
     RECT  21.659 50.058 21.695 52.848 ;
     RECT  20.844 89.856 21.803 90.072 ;
     RECT  21.623 97.848 21.911 127.449 ;
     RECT  21.083 2.151 21.919 28.944 ;
     RECT  21.659 30.888 21.947 30.906 ;
     RECT  21.659 53.766 21.947 66.24 ;
     RECT  21.443 78.21 21.983 78.228 ;
     RECT  21.623 32.616 21.991 34.146 ;
     RECT  21.479 83.196 22.019 83.214 ;
     RECT  20.844 88.236 22.091 88.254 ;
     RECT  21.299 96.696 22.099 96.714 ;
     RECT  21.991 32.616 22.135 34.794 ;
     RECT  21.659 35.55 22.135 49.032 ;
     RECT  22.135 32.616 22.163 49.032 ;
     RECT  20.903 85.428 22.163 85.986 ;
     RECT  21.919 2.151 22.896 29.052 ;
     RECT  22.711 30.69 22.896 30.708 ;
     RECT  22.163 32.616 22.896 37.764 ;
     RECT  22.163 38.952 22.896 49.032 ;
     RECT  21.695 50.058 22.896 52.164 ;
     RECT  21.947 53.766 22.896 60.57 ;
     RECT  21.947 61.398 22.896 66.24 ;
     RECT  21.659 67.176 22.896 68.814 ;
     RECT  21.515 81.216 22.896 81.234 ;
     RECT  22.163 85.428 22.896 85.446 ;
     RECT  20.844 89.01 22.896 89.028 ;
     RECT  21.803 90.054 22.896 90.072 ;
     RECT  20.844 91.746 22.896 91.764 ;
     RECT  21.551 93.636 22.896 95.508 ;
     RECT  22.099 96.606 22.896 96.714 ;
     RECT  21.911 98.046 22.896 127.449 ;
     RECT  22.896 2.151 197.64 127.449 ;
     RECT  197.64 35.046 197.807 68.364 ;
     RECT  197.64 75.366 198.383 75.528 ;
     RECT  197.64 2.151 198.391 29.286 ;
     RECT  197.64 33.66 198.391 33.714 ;
     RECT  198.391 33.66 198.427 34.074 ;
     RECT  197.807 35.046 198.427 38.574 ;
     RECT  198.427 33.66 198.607 38.574 ;
     RECT  197.807 39.636 198.607 68.364 ;
     RECT  198.607 39.636 198.643 68.976 ;
     RECT  198.787 94.608 198.823 94.626 ;
     RECT  197.64 95.49 198.823 96.624 ;
     RECT  198.391 2.151 198.931 29.556 ;
     RECT  197.64 30.42 198.931 32.364 ;
     RECT  197.64 71.352 199.219 71.37 ;
     RECT  198.715 72.936 199.255 72.954 ;
     RECT  198.679 73.818 199.255 73.836 ;
     RECT  198.931 2.151 199.291 32.364 ;
     RECT  198.751 77.436 199.291 77.454 ;
     RECT  198.607 33.516 199.615 38.574 ;
     RECT  198.643 39.636 199.615 69.354 ;
     RECT  199.291 2.151 199.651 32.724 ;
     RECT  199.615 33.516 199.651 69.354 ;
     RECT  199.651 2.151 199.692 69.354 ;
     RECT  199.219 70.956 199.692 71.37 ;
     RECT  199.255 72.936 199.692 73.836 ;
     RECT  198.383 75.51 199.692 75.528 ;
     RECT  199.291 76.896 199.692 77.454 ;
     RECT  197.64 79.416 199.692 79.434 ;
     RECT  199.327 83.502 199.692 83.52 ;
     RECT  197.64 89.748 199.692 89.766 ;
     RECT  198.823 94.608 199.692 96.624 ;
     RECT  197.64 97.776 199.692 127.449 ;
     RECT  199.692 2.151 218.16 127.449 ;
     RECT  218.16 121.806 218.291 121.824 ;
     RECT  218.16 9.756 218.327 9.774 ;
     RECT  218.16 60.084 218.327 60.102 ;
     RECT  218.16 93.726 218.327 93.744 ;
     RECT  218.16 98.856 218.327 98.874 ;
     RECT  218.16 109.188 218.327 109.206 ;
     RECT  218.16 118.368 218.327 118.386 ;
     RECT  218.16 15.156 218.867 15.174 ;
     RECT  218.16 20.286 218.867 20.304 ;
     RECT  218.16 25.416 218.867 25.434 ;
     RECT  218.16 30.546 218.867 30.564 ;
     RECT  218.16 34.326 218.867 34.344 ;
     RECT  218.16 35.676 218.867 35.694 ;
     RECT  218.16 40.806 218.867 40.824 ;
     RECT  218.16 65.376 218.867 65.394 ;
     RECT  218.16 73.206 218.867 73.224 ;
     RECT  218.16 4.626 218.903 4.644 ;
     RECT  218.16 21.402 218.903 21.42 ;
     RECT  218.16 26.406 218.903 26.424 ;
     RECT  218.16 33.012 218.903 33.03 ;
     RECT  218.16 39.456 218.903 39.474 ;
     RECT  218.16 44.586 218.903 44.604 ;
     RECT  218.16 47.16 218.903 47.178 ;
     RECT  218.16 48.438 218.903 48.456 ;
     RECT  218.16 56.106 218.903 56.124 ;
     RECT  218.16 57.42 218.903 57.438 ;
     RECT  218.16 76.986 218.903 77.004 ;
     RECT  218.16 82.116 218.903 82.134 ;
     RECT  218.16 97.578 218.903 97.596 ;
     RECT  218.16 104.058 218.903 104.076 ;
     RECT  218.16 115.056 218.903 115.074 ;
     RECT  218.16 6.246 219.443 6.264 ;
     RECT  218.16 7.326 219.443 7.344 ;
     RECT  218.16 8.676 219.443 8.694 ;
     RECT  218.16 11.106 219.443 11.124 ;
     RECT  218.16 12.456 219.443 12.474 ;
     RECT  218.16 13.806 219.443 13.824 ;
     RECT  218.16 16.506 219.443 16.524 ;
     RECT  218.16 17.586 219.443 17.604 ;
     RECT  218.16 18.936 219.443 18.954 ;
     RECT  218.16 22.716 219.443 22.734 ;
     RECT  218.16 24.066 219.443 24.084 ;
     RECT  218.16 27.882 219.443 27.9 ;
     RECT  218.16 29.196 219.443 29.214 ;
     RECT  218.16 32.166 219.443 32.184 ;
     RECT  218.16 37.026 219.443 37.044 ;
     RECT  218.16 38.178 219.443 38.196 ;
     RECT  218.16 42.156 219.443 42.174 ;
     RECT  218.16 43.308 219.443 43.326 ;
     RECT  218.16 46.242 219.443 46.26 ;
     RECT  218.16 51.102 219.443 51.12 ;
     RECT  218.16 52.326 219.443 52.344 ;
     RECT  218.16 54.918 219.443 54.936 ;
     RECT  218.16 61.596 219.443 61.614 ;
     RECT  218.16 62.676 219.443 62.694 ;
     RECT  218.16 68.886 219.443 68.904 ;
     RECT  218.16 71.856 219.443 71.874 ;
     RECT  218.16 74.556 219.443 74.574 ;
     RECT  218.16 75.708 219.443 75.726 ;
     RECT  218.16 78.606 219.443 78.624 ;
     RECT  218.16 79.686 219.443 79.704 ;
     RECT  218.16 80.838 219.443 80.856 ;
     RECT  218.16 83.466 219.443 83.484 ;
     RECT  218.16 84.816 219.443 84.834 ;
     RECT  218.16 86.166 219.443 86.184 ;
     RECT  218.16 87.282 219.443 87.3 ;
     RECT  218.16 88.596 219.443 88.614 ;
     RECT  218.16 89.946 219.443 89.964 ;
     RECT  218.16 91.296 219.443 91.314 ;
     RECT  218.16 92.646 219.443 92.664 ;
     RECT  218.16 95.076 219.443 95.094 ;
     RECT  218.16 96.426 219.443 96.444 ;
     RECT  218.16 100.206 219.443 100.224 ;
     RECT  218.16 101.826 219.443 101.844 ;
     RECT  218.16 102.906 219.443 102.924 ;
     RECT  218.16 105.372 219.443 105.39 ;
     RECT  218.16 108.036 219.443 108.054 ;
     RECT  218.16 110.502 219.443 110.52 ;
     RECT  218.16 112.086 219.443 112.104 ;
     RECT  218.16 125.046 219.443 125.064 ;
     RECT  218.16 49.482 219.479 49.5 ;
     RECT  218.16 53.496 219.479 53.514 ;
     RECT  218.16 58.662 219.479 58.68 ;
     RECT  218.16 63.756 219.479 63.774 ;
     RECT  218.16 106.416 219.479 106.434 ;
    LAYER M3 ;
     RECT  2.415 2.143 2.505 2.413 ;
     RECT  7.815 2.143 7.905 2.413 ;
     RECT  13.215 2.143 13.305 2.413 ;
     RECT  18.615 2.143 18.705 2.413 ;
     RECT  24.015 2.143 24.105 2.413 ;
     RECT  29.415 2.143 29.505 2.413 ;
     RECT  34.815 2.143 34.905 2.413 ;
     RECT  40.215 2.143 40.305 2.413 ;
     RECT  45.615 2.143 45.705 2.413 ;
     RECT  51.015 2.143 51.105 2.413 ;
     RECT  56.415 2.143 56.505 2.413 ;
     RECT  61.815 2.143 61.905 2.413 ;
     RECT  67.215 2.143 67.305 2.413 ;
     RECT  72.615 2.143 72.705 2.413 ;
     RECT  78.015 2.143 78.105 2.413 ;
     RECT  83.415 2.143 83.505 2.413 ;
     RECT  88.815 2.143 88.905 2.413 ;
     RECT  94.215 2.143 94.305 2.413 ;
     RECT  99.615 2.143 99.705 2.413 ;
     RECT  105.015 2.143 105.105 2.413 ;
     RECT  110.415 2.143 110.505 2.413 ;
     RECT  115.815 2.143 115.905 2.413 ;
     RECT  121.215 2.143 121.305 2.413 ;
     RECT  126.615 2.143 126.705 2.413 ;
     RECT  132.015 2.143 132.105 2.413 ;
     RECT  137.415 2.143 137.505 2.413 ;
     RECT  142.815 2.143 142.905 2.413 ;
     RECT  148.215 2.143 148.305 2.413 ;
     RECT  153.615 2.143 153.705 2.413 ;
     RECT  159.015 2.143 159.105 2.413 ;
     RECT  164.415 2.143 164.505 2.413 ;
     RECT  169.815 2.143 169.905 2.413 ;
     RECT  175.215 2.143 175.305 2.413 ;
     RECT  180.615 2.143 180.705 2.413 ;
     RECT  186.015 2.143 186.105 2.413 ;
     RECT  191.415 2.143 191.505 2.413 ;
     RECT  196.815 2.143 196.905 2.413 ;
     RECT  202.215 2.143 202.305 2.413 ;
     RECT  207.615 2.143 207.705 2.413 ;
     RECT  213.015 2.143 213.105 2.413 ;
     RECT  0.108 4.171 0.126 4.217 ;
     RECT  4.176 4.261 4.194 4.657 ;
     RECT  218.88 4.621 218.898 4.685 ;
     RECT  4.176 4.657 4.986 4.693 ;
     RECT  4.176 4.693 5.13 4.801 ;
     RECT  4.176 4.801 5.526 4.955 ;
     RECT  4.248 4.955 4.266 5.117 ;
     RECT  5.112 4.955 5.526 5.117 ;
     RECT  5.112 5.117 5.13 5.459 ;
     RECT  219.42 5.899 219.438 6.269 ;
     RECT  215.568 6.235 215.586 6.275 ;
     RECT  217.8 6.241 217.818 6.341 ;
     RECT  216.72 6.241 216.738 6.421 ;
     RECT  217.548 6.385 217.566 6.421 ;
     RECT  216.72 6.421 217.566 6.539 ;
     RECT  216.72 6.539 216.738 6.575 ;
     RECT  217.476 6.539 217.494 6.575 ;
     RECT  4.536 6.691 4.554 6.781 ;
     RECT  4.536 6.781 4.77 6.817 ;
     RECT  4.14 6.817 4.77 6.961 ;
     RECT  5.58 6.691 5.598 6.961 ;
     RECT  4.14 6.961 5.598 7.051 ;
     RECT  4.14 7.051 5.742 7.115 ;
     RECT  4.536 7.115 5.742 7.123 ;
     RECT  219.42 7.195 219.438 7.349 ;
     RECT  4.536 7.123 6.03 7.385 ;
     RECT  215.712 6.421 215.73 7.465 ;
     RECT  215.712 7.465 216.198 7.619 ;
     RECT  5.472 7.385 6.03 7.663 ;
     RECT  5.472 7.663 6.57 7.771 ;
     RECT  215.712 7.619 215.73 7.771 ;
     RECT  214.092 7.735 214.11 7.805 ;
     RECT  4.536 7.385 4.662 7.897 ;
     RECT  5.472 7.771 6.678 7.925 ;
     RECT  215.028 7.771 215.73 7.925 ;
     RECT  5.472 7.925 6.57 7.961 ;
     RECT  4.5 7.897 4.662 8.311 ;
     RECT  5.472 7.961 6.534 8.311 ;
     RECT  4.392 8.311 6.534 8.429 ;
     RECT  4.392 8.429 6.426 8.465 ;
     RECT  4.428 8.465 6.426 8.537 ;
     RECT  4.428 8.537 5.634 8.699 ;
     RECT  219.42 8.491 219.438 8.699 ;
     RECT  217.8 8.671 217.818 8.771 ;
     RECT  213.015 2.413 213.297 8.815 ;
     RECT  215.388 7.925 215.73 8.815 ;
     RECT  215.064 8.815 215.73 8.851 ;
     RECT  4.428 8.699 5.202 8.909 ;
     RECT  4.536 8.909 5.202 8.969 ;
     RECT  0.108 6.475 0.126 9.005 ;
     RECT  214.776 8.851 215.73 9.005 ;
     RECT  212.184 7.771 212.202 9.067 ;
     RECT  4.536 8.969 4.554 9.113 ;
     RECT  211.5 9.067 212.202 9.113 ;
     RECT  211.968 9.113 212.202 9.121 ;
     RECT  213.015 8.815 213.822 9.121 ;
     RECT  211.968 9.121 213.822 9.211 ;
     RECT  214.776 9.005 214.902 9.211 ;
     RECT  215.712 9.005 215.73 9.239 ;
     RECT  211.968 9.211 214.902 9.545 ;
     RECT  211.968 9.545 214.398 9.581 ;
     RECT  212.04 9.581 214.398 9.653 ;
     RECT  218.304 9.751 218.322 9.821 ;
     RECT  212.076 9.653 214.398 9.851 ;
     RECT  125.712 9.481 125.73 10.093 ;
     RECT  126.615 2.413 126.897 10.093 ;
     RECT  210.348 10.093 210.366 10.193 ;
     RECT  212.076 9.851 214.254 10.193 ;
     RECT  212.076 10.193 213.534 10.319 ;
     RECT  212.076 10.319 213.354 10.355 ;
     RECT  212.076 10.355 213.297 10.471 ;
     RECT  211.968 10.471 213.297 10.831 ;
     RECT  211.788 10.831 213.297 10.877 ;
     RECT  219.42 11.083 219.438 11.129 ;
     RECT  121.215 2.413 121.497 11.137 ;
     RECT  211.896 10.877 213.297 11.273 ;
     RECT  4.5 11.245 4.518 11.281 ;
     RECT  212.832 11.273 213.297 11.281 ;
     RECT  217.26 11.245 217.278 11.281 ;
     RECT  211.896 11.273 212.058 11.399 ;
     RECT  212.832 11.281 213.39 11.399 ;
     RECT  216.396 11.281 217.278 11.399 ;
     RECT  211.896 11.399 211.914 11.405 ;
     RECT  215.28 11.245 215.298 11.405 ;
     RECT  4.248 11.281 4.698 11.435 ;
     RECT  216.396 11.399 217.134 11.435 ;
     RECT  0.108 11.128 0.126 11.467 ;
     RECT  0.108 11.467 0.162 11.543 ;
     RECT  2.415 2.413 2.697 11.551 ;
     RECT  5.58 11.281 5.598 11.551 ;
     RECT  6.408 8.537 6.426 11.551 ;
     RECT  216.612 11.435 216.774 11.669 ;
     RECT  216.612 11.669 216.63 11.705 ;
     RECT  212.832 11.399 213.354 11.813 ;
     RECT  5.58 11.551 6.426 11.821 ;
     RECT  4.752 11.821 6.426 11.939 ;
     RECT  212.832 11.813 213.297 11.975 ;
     RECT  2.415 11.551 3.114 12.091 ;
     RECT  3.96 11.821 3.978 12.091 ;
     RECT  2.415 12.091 3.978 12.361 ;
     RECT  5.472 11.939 6.426 12.361 ;
     RECT  219.42 12.379 219.438 12.479 ;
     RECT  0.108 11.543 0.126 12.515 ;
     RECT  217.8 12.451 217.818 12.551 ;
     RECT  5.472 12.361 6.966 12.557 ;
     RECT  216.036 12.487 216.054 12.559 ;
     RECT  214.668 12.517 214.686 12.631 ;
     RECT  215.856 12.559 216.054 12.631 ;
     RECT  215.604 12.631 216.054 12.749 ;
     RECT  213.015 11.975 213.297 12.757 ;
     RECT  215.604 12.749 215.874 12.785 ;
     RECT  214.668 12.631 214.866 12.793 ;
     RECT  0.54 12.757 0.558 12.797 ;
     RECT  212.904 12.757 213.297 12.829 ;
     RECT  212.904 12.829 213.75 12.901 ;
     RECT  214.632 12.793 214.866 12.901 ;
     RECT  212.904 12.901 214.866 12.929 ;
     RECT  2.415 12.361 4.698 13.019 ;
     RECT  212.904 12.929 214.65 13.019 ;
     RECT  215.712 12.785 215.838 13.019 ;
     RECT  2.415 13.019 2.898 13.027 ;
     RECT  3.744 13.019 4.698 13.051 ;
     RECT  215.712 13.019 215.73 13.055 ;
     RECT  3.744 13.051 4.734 13.091 ;
     RECT  1.728 13.027 2.898 13.133 ;
     RECT  124.632 10.021 124.65 13.297 ;
     RECT  214.524 13.019 214.65 13.325 ;
     RECT  88.815 2.413 89.097 13.333 ;
     RECT  88.815 13.333 89.73 13.373 ;
     RECT  2.415 13.133 2.898 13.559 ;
     RECT  3.744 13.091 4.302 13.631 ;
     RECT  5.58 12.557 6.966 13.711 ;
     RECT  7.815 2.413 8.097 13.711 ;
     RECT  212.904 13.019 213.75 13.829 ;
     RECT  219.42 13.675 219.438 13.829 ;
     RECT  0.108 13.405 0.126 13.865 ;
     RECT  217.8 13.801 217.818 13.901 ;
     RECT  4.14 13.631 4.302 13.981 ;
     RECT  5.58 13.711 8.097 13.981 ;
     RECT  212.904 13.829 213.498 13.981 ;
     RECT  214.668 13.945 215.298 14.099 ;
     RECT  214.668 14.099 214.938 14.135 ;
     RECT  212.832 13.981 213.498 14.203 ;
     RECT  214.884 14.135 214.938 14.369 ;
     RECT  212.688 14.203 213.498 14.405 ;
     RECT  0.54 14.101 0.558 14.429 ;
     RECT  214.92 14.369 214.938 14.441 ;
     RECT  212.688 14.405 213.297 14.449 ;
     RECT  4.14 13.981 8.097 14.521 ;
     RECT  3.744 14.521 8.097 14.639 ;
     RECT  2.415 13.559 2.697 14.731 ;
     RECT  4.212 14.639 8.097 14.813 ;
     RECT  2.304 14.731 2.697 14.945 ;
     RECT  121.215 11.137 121.698 14.953 ;
     RECT  2.415 14.945 2.697 15.025 ;
     RECT  218.844 14.923 218.862 15.179 ;
     RECT  217.368 15.151 217.386 15.251 ;
     RECT  13.215 2.413 13.497 15.259 ;
     RECT  212.04 14.449 213.297 15.259 ;
     RECT  212.04 15.259 213.93 15.295 ;
     RECT  13.068 15.259 13.497 15.331 ;
     RECT  2.415 15.025 3.294 15.389 ;
     RECT  4.212 14.813 4.266 15.389 ;
     RECT  212.04 15.295 214.146 15.449 ;
     RECT  29.415 2.413 29.697 15.457 ;
     RECT  212.04 15.449 213.93 15.485 ;
     RECT  12.024 15.457 12.042 15.493 ;
     RECT  13.068 15.331 13.59 15.493 ;
     RECT  18.615 2.413 18.897 15.493 ;
     RECT  20.7 15.457 20.718 15.493 ;
     RECT  22.716 15.457 22.734 15.493 ;
     RECT  27.828 15.493 27.846 15.529 ;
     RECT  11.268 15.457 11.286 15.601 ;
     RECT  12.024 15.493 12.222 15.601 ;
     RECT  13.068 15.493 13.734 15.601 ;
     RECT  14.94 15.565 14.958 15.601 ;
     RECT  19.908 15.457 19.926 15.601 ;
     RECT  20.7 15.493 20.862 15.601 ;
     RECT  21.96 15.457 21.978 15.601 ;
     RECT  22.716 15.493 22.914 15.601 ;
     RECT  27.828 15.529 27.954 15.601 ;
     RECT  28.764 15.457 29.697 15.601 ;
     RECT  11.268 15.601 13.914 15.691 ;
     RECT  14.94 15.601 15.138 15.691 ;
     RECT  27.828 15.601 29.697 15.727 ;
     RECT  10.476 5.431 10.494 15.763 ;
     RECT  11.268 15.691 15.138 15.763 ;
     RECT  10.476 15.763 15.138 15.835 ;
     RECT  16.272 15.601 16.29 15.835 ;
     RECT  25.056 15.493 25.074 15.835 ;
     RECT  19.908 15.601 21.186 15.871 ;
     RECT  21.96 15.601 23.238 15.871 ;
     RECT  24.015 2.413 24.297 15.871 ;
     RECT  25.02 15.835 25.074 15.871 ;
     RECT  212.04 15.485 213.57 15.871 ;
     RECT  211.896 15.871 213.57 15.917 ;
     RECT  5.076 14.813 8.097 15.961 ;
     RECT  10.476 15.835 16.29 15.961 ;
     RECT  19.908 15.871 23.238 15.961 ;
     RECT  24.015 15.871 25.47 15.961 ;
     RECT  4.248 15.389 4.266 15.989 ;
     RECT  10.368 15.961 16.29 15.997 ;
     RECT  17.676 15.961 17.694 15.997 ;
     RECT  18.432 15.493 18.954 15.997 ;
     RECT  19.908 15.961 25.47 15.997 ;
     RECT  18.432 15.997 19.17 16.027 ;
     RECT  19.908 15.997 26.01 16.027 ;
     RECT  18.432 16.027 26.01 16.105 ;
     RECT  10.008 15.997 17.694 16.133 ;
     RECT  212.112 15.917 213.57 16.133 ;
     RECT  9.216 15.997 9.234 16.141 ;
     RECT  10.008 16.133 17.658 16.141 ;
     RECT  212.76 16.133 213.57 16.231 ;
     RECT  212.76 16.231 213.822 16.259 ;
     RECT  18.432 16.105 26.262 16.303 ;
     RECT  18.432 16.303 26.298 16.339 ;
     RECT  217.368 16.231 217.386 16.375 ;
     RECT  9.216 16.141 17.658 16.411 ;
     RECT  18.432 16.339 26.442 16.411 ;
     RECT  216 16.405 216.018 16.411 ;
     RECT  217.368 16.375 217.71 16.411 ;
     RECT  216 16.411 216.162 16.445 ;
     RECT  18.432 16.411 26.514 16.501 ;
     RECT  27.252 15.727 29.697 16.501 ;
     RECT  8.892 16.411 17.658 16.529 ;
     RECT  18.432 16.501 29.697 16.529 ;
     RECT  212.976 16.259 213.822 16.529 ;
     RECT  216.144 16.445 216.162 16.529 ;
     RECT  219.42 16.219 219.438 16.529 ;
     RECT  18.432 16.529 24.462 16.541 ;
     RECT  216.936 16.411 217.818 16.565 ;
     RECT  9.072 16.529 17.658 16.673 ;
     RECT  18.432 16.541 24.39 16.709 ;
     RECT  212.976 16.529 213.642 16.799 ;
     RECT  216.936 16.565 217.098 16.799 ;
     RECT  122.796 14.215 122.814 16.835 ;
     RECT  212.976 16.799 213.498 16.835 ;
     RECT  216.936 16.799 216.954 16.835 ;
     RECT  11.916 16.673 17.658 16.879 ;
     RECT  18.432 16.709 24.297 16.879 ;
     RECT  125.712 10.093 126.897 16.915 ;
     RECT  5.004 15.961 8.097 17.035 ;
     RECT  25.308 16.529 29.697 17.041 ;
     RECT  120.96 14.953 121.698 17.069 ;
     RECT  212.976 16.835 213.462 17.069 ;
     RECT  2.415 15.389 2.697 17.077 ;
     RECT  1.728 17.077 2.697 17.117 ;
     RECT  4.572 17.035 8.097 17.165 ;
     RECT  25.308 17.041 30.294 17.311 ;
     RECT  25.308 17.311 31.014 17.323 ;
     RECT  25.128 17.323 31.014 17.371 ;
     RECT  25.056 17.371 31.014 17.383 ;
     RECT  0.54 17.413 0.558 17.453 ;
     RECT  124.488 13.297 124.65 17.455 ;
     RECT  4.896 17.165 8.097 17.491 ;
     RECT  9.072 16.673 11.034 17.491 ;
     RECT  123.084 17.077 123.102 17.609 ;
     RECT  214.596 17.563 214.614 17.609 ;
     RECT  219.42 17.515 219.438 17.609 ;
     RECT  11.916 16.879 24.297 17.645 ;
     RECT  11.916 17.645 21.438 17.681 ;
     RECT  11.916 17.681 21.294 17.717 ;
     RECT  25.056 17.383 31.302 17.725 ;
     RECT  216.828 17.653 216.846 17.725 ;
     RECT  4.896 17.491 11.034 17.741 ;
     RECT  32.796 16.807 32.814 17.761 ;
     RECT  213.015 17.069 213.462 17.761 ;
     RECT  22.212 17.645 24.297 17.803 ;
     RECT  25.056 17.725 31.446 17.803 ;
     RECT  32.4 17.761 32.814 17.851 ;
     RECT  216.828 17.725 217.278 17.879 ;
     RECT  215.856 17.761 215.874 17.915 ;
     RECT  217.116 17.879 217.134 17.915 ;
     RECT  32.4 17.851 33.282 17.951 ;
     RECT  213.015 17.761 213.786 17.959 ;
     RECT  5.004 17.741 11.034 17.995 ;
     RECT  11.916 17.717 21.114 17.995 ;
     RECT  22.212 17.803 31.446 17.995 ;
     RECT  2.415 17.117 2.697 18.121 ;
     RECT  22.212 17.995 31.482 18.221 ;
     RECT  22.248 18.221 31.482 18.229 ;
     RECT  32.4 17.951 33.102 18.229 ;
     RECT  124.236 17.455 124.65 18.419 ;
     RECT  125.568 16.915 126.897 18.419 ;
     RECT  213.015 17.959 214.182 18.455 ;
     RECT  22.248 18.229 33.102 18.527 ;
     RECT  2.415 18.121 3.51 18.535 ;
     RECT  5.004 17.995 21.114 18.571 ;
     RECT  22.392 18.527 33.102 18.725 ;
     RECT  22.392 18.725 32.958 18.761 ;
     RECT  2.415 18.535 4.05 18.769 ;
     RECT  4.968 18.571 21.114 18.769 ;
     RECT  2.415 18.769 21.474 18.797 ;
     RECT  219.42 18.811 219.438 18.959 ;
     RECT  4.608 18.797 21.474 18.995 ;
     RECT  22.464 18.761 32.958 18.995 ;
     RECT  217.8 18.931 217.818 19.031 ;
     RECT  120.096 15.997 120.114 19.075 ;
     RECT  120.96 17.069 121.554 19.075 ;
     RECT  213.015 18.455 213.462 19.111 ;
     RECT  215.172 19.075 215.19 19.111 ;
     RECT  120.096 19.075 121.554 19.229 ;
     RECT  214.344 19.111 215.19 19.229 ;
     RECT  214.344 19.229 214.686 19.265 ;
     RECT  212.976 19.111 213.462 19.387 ;
     RECT  4.968 18.995 21.474 19.483 ;
     RECT  214.452 19.265 214.614 19.499 ;
     RECT  214.452 19.499 214.47 19.535 ;
     RECT  4.968 19.483 21.654 19.543 ;
     RECT  0.108 17.755 0.126 19.615 ;
     RECT  2.415 18.797 3.51 19.651 ;
     RECT  2.415 19.651 3.798 19.661 ;
     RECT  124.236 18.419 124.506 19.679 ;
     RECT  0.108 19.615 0.162 19.805 ;
     RECT  4.968 19.543 21.726 19.813 ;
     RECT  22.464 18.995 29.697 19.813 ;
     RECT  212.544 19.387 213.462 19.921 ;
     RECT  4.968 19.813 29.697 19.949 ;
     RECT  15.408 19.949 29.697 20.083 ;
     RECT  30.42 18.995 32.958 20.083 ;
     RECT  0.54 20.047 0.558 20.093 ;
     RECT  212.544 19.921 213.57 20.119 ;
     RECT  4.968 19.949 14.67 20.149 ;
     RECT  3.42 19.661 3.798 20.155 ;
     RECT  4.716 20.149 14.67 20.155 ;
     RECT  212.436 20.119 213.57 20.155 ;
     RECT  212.436 20.155 214.11 20.191 ;
     RECT  15.408 20.083 32.958 20.219 ;
     RECT  210.348 20.119 210.366 20.309 ;
     RECT  211.896 20.191 214.11 20.309 ;
     RECT  218.844 20.107 218.862 20.309 ;
     RECT  217.26 20.011 217.278 20.345 ;
     RECT  15.48 20.219 32.958 20.381 ;
     RECT  15.552 20.381 32.958 20.417 ;
     RECT  3.42 20.155 14.67 20.429 ;
     RECT  15.588 20.417 32.958 20.489 ;
     RECT  34.056 20.623 34.074 20.695 ;
     RECT  15.804 20.489 32.958 20.731 ;
     RECT  33.84 20.695 34.074 20.731 ;
     RECT  34.815 2.413 35.097 20.731 ;
     RECT  211.896 20.309 214.074 20.731 ;
     RECT  122.868 17.653 122.886 20.759 ;
     RECT  15.804 20.731 34.074 20.821 ;
     RECT  34.815 20.731 35.298 20.821 ;
     RECT  36.036 20.587 36.054 20.965 ;
     RECT  36.036 20.965 36.702 21.001 ;
     RECT  3.456 20.429 14.67 21.091 ;
     RECT  124.236 19.679 124.254 21.119 ;
     RECT  211.716 20.731 214.074 21.119 ;
     RECT  2.415 19.661 2.697 21.235 ;
     RECT  3.456 21.091 14.814 21.235 ;
     RECT  15.804 20.821 35.298 21.271 ;
     RECT  36.036 21.001 36.846 21.271 ;
     RECT  38.268 21.235 38.286 21.271 ;
     RECT  15.804 21.271 37.098 21.299 ;
     RECT  2.415 21.235 14.814 21.361 ;
     RECT  33.876 21.299 37.098 21.361 ;
     RECT  214.884 21.355 214.902 21.425 ;
     RECT  38.268 21.271 38.43 21.433 ;
     RECT  218.88 21.397 218.898 21.437 ;
     RECT  39.276 21.091 39.294 21.461 ;
     RECT  217.8 21.361 217.818 21.461 ;
     RECT  33.876 21.361 37.206 21.469 ;
     RECT  38.232 21.433 38.43 21.469 ;
     RECT  211.716 21.119 213.786 21.469 ;
     RECT  211.428 21.469 213.786 21.497 ;
     RECT  217.548 21.505 217.566 21.541 ;
     RECT  2.415 21.361 14.85 21.595 ;
     RECT  15.804 21.299 33.138 21.595 ;
     RECT  216.252 21.541 216.27 21.631 ;
     RECT  2.415 21.595 33.138 21.659 ;
     RECT  120.816 19.229 121.554 21.659 ;
     RECT  217.368 21.541 217.566 21.659 ;
     RECT  17.064 21.659 33.03 21.677 ;
     RECT  213.015 21.497 213.786 21.677 ;
     RECT  33.876 21.469 38.43 21.695 ;
     RECT  211.428 21.497 212.13 21.695 ;
     RECT  216.252 21.631 216.63 21.695 ;
     RECT  217.476 21.659 217.494 21.695 ;
     RECT  33.912 21.695 38.43 21.703 ;
     RECT  216.612 21.695 216.63 21.731 ;
     RECT  211.428 21.695 211.446 21.811 ;
     RECT  211.212 21.811 211.446 21.821 ;
     RECT  33.912 21.703 38.61 21.839 ;
     RECT  33.984 21.839 38.61 21.929 ;
     RECT  39.384 21.631 39.402 21.929 ;
     RECT  211.212 21.821 211.23 21.929 ;
     RECT  17.1 21.677 33.03 22.073 ;
     RECT  40.215 2.413 40.497 22.081 ;
     RECT  214.56 21.643 214.578 22.165 ;
     RECT  119.088 22.045 119.106 22.199 ;
     RECT  214.236 22.165 214.578 22.205 ;
     RECT  214.56 22.205 214.578 22.208 ;
     RECT  36.36 21.929 38.61 22.235 ;
     RECT  114.156 21.397 114.174 22.469 ;
     RECT  2.415 21.659 15.858 22.477 ;
     RECT  2.415 22.477 15.93 22.507 ;
     RECT  120.816 21.659 121.497 22.649 ;
     RECT  33.984 21.929 35.622 22.711 ;
     RECT  36.36 22.235 38.358 22.711 ;
     RECT  214.704 22.699 214.722 22.739 ;
     RECT  219.42 22.699 219.438 22.739 ;
     RECT  2.415 22.507 16.254 22.795 ;
     RECT  17.1 22.073 32.994 22.795 ;
     RECT  216.036 22.783 216.054 22.855 ;
     RECT  2.415 22.795 32.994 22.891 ;
     RECT  33.984 22.711 38.358 22.891 ;
     RECT  39.6 22.081 40.497 22.891 ;
     RECT  216.036 22.855 216.162 22.891 ;
     RECT  113.904 22.585 113.922 22.919 ;
     RECT  215.712 22.891 216.162 23.009 ;
     RECT  2.415 22.891 38.358 23.017 ;
     RECT  215.712 23.009 216.054 23.045 ;
     RECT  88.815 13.373 89.097 23.053 ;
     RECT  86.652 23.053 86.67 23.153 ;
     RECT  88.488 23.053 89.097 23.161 ;
     RECT  198.612 13.261 198.63 23.161 ;
     RECT  211.896 22.891 211.914 23.161 ;
     RECT  88.092 23.161 89.097 23.251 ;
     RECT  90.54 23.161 90.558 23.279 ;
     RECT  215.82 23.045 215.91 23.279 ;
     RECT  2.415 23.017 38.466 23.287 ;
     RECT  67.215 2.413 67.497 23.287 ;
     RECT  39.492 22.891 40.497 23.309 ;
     RECT  80.928 23.251 80.946 23.309 ;
     RECT  113.22 23.251 113.526 23.309 ;
     RECT  211.464 23.161 212.202 23.315 ;
     RECT  215.82 23.279 215.838 23.315 ;
     RECT  196.815 2.413 197.097 23.323 ;
     RECT  41.328 23.035 41.346 23.357 ;
     RECT  82.08 23.251 82.098 23.357 ;
     RECT  87.912 23.251 89.097 23.357 ;
     RECT  1.728 23.287 38.466 23.359 ;
     RECT  1.728 23.359 38.61 23.405 ;
     RECT  148.215 2.413 148.497 23.419 ;
     RECT  2.415 23.405 38.61 23.431 ;
     RECT  113.22 23.309 113.238 23.453 ;
     RECT  117.144 20.425 117.162 23.459 ;
     RECT  153.615 2.413 153.897 23.512 ;
     RECT  148.068 23.419 148.497 23.515 ;
     RECT  132.015 2.413 132.297 23.521 ;
     RECT  213.015 21.677 213.297 23.521 ;
     RECT  148.068 23.515 148.59 23.549 ;
     RECT  153.216 23.512 153.897 23.549 ;
     RECT  148.215 23.549 148.59 23.555 ;
     RECT  146.52 23.557 146.538 23.597 ;
     RECT  115.815 2.413 116.097 23.629 ;
     RECT  111.816 23.083 111.834 23.665 ;
     RECT  196.092 23.323 197.097 23.665 ;
     RECT  211.464 23.315 211.806 23.701 ;
     RECT  213.015 23.521 213.786 23.701 ;
     RECT  2.415 23.431 39.438 23.729 ;
     RECT  213.015 23.701 214.002 23.741 ;
     RECT  211.248 23.701 211.806 23.791 ;
     RECT  125.568 18.419 125.802 23.819 ;
     RECT  125.784 23.819 125.802 23.855 ;
     RECT  132.015 23.521 132.462 23.855 ;
     RECT  142.815 2.413 143.097 23.863 ;
     RECT  137.415 2.413 137.697 23.899 ;
     RECT  2.415 23.729 39.366 23.927 ;
     RECT  215.028 23.791 215.046 23.947 ;
     RECT  94.215 2.413 94.497 23.971 ;
     RECT  219.42 23.947 219.438 24.089 ;
     RECT  83.415 2.413 83.697 24.187 ;
     RECT  214.884 23.947 215.046 24.205 ;
     RECT  45.615 2.413 45.897 24.232 ;
     RECT  56.415 2.413 56.697 24.232 ;
     RECT  67.215 23.287 67.914 24.232 ;
     RECT  78.015 2.413 78.297 24.232 ;
     RECT  88.815 23.357 89.097 24.232 ;
     RECT  210.528 23.791 211.806 24.241 ;
     RECT  214.884 24.205 215.226 24.241 ;
     RECT  45.504 24.232 45.897 24.269 ;
     RECT  110.415 2.413 110.697 24.325 ;
     RECT  93.888 23.971 94.497 24.331 ;
     RECT  99.615 2.413 99.897 24.331 ;
     RECT  121.215 22.649 121.497 24.331 ;
     RECT  132.015 23.855 132.297 24.331 ;
     RECT  153.54 23.549 153.897 24.331 ;
     RECT  164.415 2.413 164.697 24.331 ;
     RECT  175.215 2.413 175.497 24.331 ;
     RECT  186.015 2.413 186.297 24.331 ;
     RECT  82.692 24.187 84.402 24.359 ;
     RECT  117.792 24.205 117.81 24.359 ;
     RECT  214.524 24.241 215.226 24.359 ;
     RECT  110.304 24.325 110.697 24.365 ;
     RECT  82.692 24.359 83.697 24.367 ;
     RECT  85.5 24.331 85.518 24.367 ;
     RECT  56.304 24.232 56.697 24.368 ;
     RECT  67.104 24.232 67.914 24.368 ;
     RECT  77.904 24.232 78.297 24.368 ;
     RECT  82.656 24.367 83.697 24.368 ;
     RECT  85.5 24.367 85.59 24.368 ;
     RECT  88.704 24.232 89.097 24.368 ;
     RECT  99.504 24.331 99.897 24.368 ;
     RECT  121.104 24.331 121.497 24.368 ;
     RECT  131.904 24.331 132.297 24.368 ;
     RECT  175.104 24.331 175.497 24.368 ;
     RECT  185.904 24.331 186.297 24.368 ;
     RECT  214.524 24.359 214.83 24.395 ;
     RECT  196.092 23.665 197.478 24.403 ;
     RECT  93.24 24.331 94.497 24.413 ;
     RECT  111.816 23.665 112.518 24.439 ;
     RECT  194.364 24.331 194.382 24.461 ;
     RECT  82.656 24.368 82.674 24.467 ;
     RECT  85.572 24.368 85.59 24.467 ;
     RECT  90.684 24.367 90.702 24.467 ;
     RECT  88.815 24.368 89.097 24.475 ;
     RECT  126.615 18.419 126.897 24.475 ;
     RECT  58.104 23.323 58.122 24.511 ;
     RECT  213.015 23.741 213.75 24.511 ;
     RECT  110.415 24.365 110.697 24.601 ;
     RECT  111.816 24.439 113.094 24.601 ;
     RECT  114.48 24.511 114.678 24.601 ;
     RECT  58.104 24.511 58.23 24.629 ;
     RECT  111.816 24.601 113.13 24.637 ;
     RECT  114.48 24.601 114.75 24.637 ;
     RECT  130.428 23.395 130.446 24.637 ;
     RECT  2.415 23.927 39.186 24.665 ;
     RECT  58.104 24.629 58.122 24.673 ;
     RECT  72.615 2.413 72.897 24.673 ;
     RECT  111.78 24.637 113.13 24.673 ;
     RECT  152.676 24.367 152.694 24.673 ;
     RECT  153.504 24.331 153.897 24.673 ;
     RECT  113.94 24.637 114.75 24.701 ;
     RECT  213.015 24.511 213.786 24.701 ;
     RECT  26.388 24.665 39.186 24.709 ;
     RECT  130.428 24.637 131.166 24.709 ;
     RECT  26.388 24.709 39.222 24.781 ;
     RECT  103.824 23.701 103.842 24.781 ;
     RECT  113.94 24.701 114.21 24.781 ;
     RECT  210.528 24.241 212.022 24.781 ;
     RECT  130.428 24.709 131.274 24.809 ;
     RECT  210.528 24.781 212.094 24.859 ;
     RECT  213.015 24.701 213.75 24.859 ;
     RECT  215.604 24.619 215.622 24.859 ;
     RECT  68.904 24.673 68.922 24.871 ;
     RECT  196.092 24.403 197.838 24.871 ;
     RECT  198.612 23.161 199.206 24.871 ;
     RECT  68.904 24.871 69.282 24.899 ;
     RECT  113.904 24.781 114.21 24.899 ;
     RECT  214.524 24.395 214.722 24.899 ;
     RECT  215.604 24.859 216.018 24.899 ;
     RECT  123.732 24.511 123.75 24.907 ;
     RECT  214.524 24.899 214.542 24.935 ;
     RECT  103.644 24.781 103.842 24.943 ;
     RECT  142.272 23.863 143.097 24.943 ;
     RECT  164.304 24.331 164.697 24.943 ;
     RECT  176.508 24.241 176.526 24.943 ;
     RECT  71.64 24.871 71.658 25.015 ;
     RECT  26.388 24.781 39.258 25.037 ;
     RECT  70.38 24.943 70.578 25.051 ;
     RECT  71.604 25.015 71.658 25.051 ;
     RECT  72.615 24.673 73.566 25.051 ;
     RECT  74.304 24.979 74.322 25.051 ;
     RECT  102.024 24.241 102.042 25.051 ;
     RECT  110.415 24.601 110.79 25.051 ;
     RECT  111.744 24.673 113.13 25.051 ;
     RECT  210.528 24.859 213.75 25.051 ;
     RECT  27.9 25.037 39.258 25.079 ;
     RECT  69.156 24.899 69.282 25.141 ;
     RECT  70.38 25.051 70.65 25.141 ;
     RECT  71.604 25.051 71.802 25.141 ;
     RECT  72.615 25.051 74.322 25.141 ;
     RECT  98.316 24.235 98.334 25.141 ;
     RECT  123.696 24.907 123.75 25.141 ;
     RECT  152.676 24.673 153.897 25.141 ;
     RECT  175.215 24.368 175.497 25.141 ;
     RECT  179.604 24.943 179.622 25.141 ;
     RECT  67.215 24.368 67.914 25.147 ;
     RECT  69.156 25.141 70.65 25.147 ;
     RECT  110.415 25.051 113.13 25.147 ;
     RECT  152.532 25.141 153.897 25.147 ;
     RECT  27.9 25.079 38.862 25.169 ;
     RECT  76.644 23.125 76.662 25.169 ;
     RECT  115.815 23.629 116.73 25.169 ;
     RECT  210.024 25.051 213.75 25.169 ;
     RECT  98.316 25.141 98.622 25.177 ;
     RECT  179.496 25.141 179.622 25.177 ;
     RECT  102.024 25.051 102.69 25.195 ;
     RECT  176.436 24.943 176.526 25.195 ;
     RECT  93.888 24.413 94.497 25.205 ;
     RECT  96.084 24.169 96.102 25.205 ;
     RECT  136.548 25.003 136.566 25.205 ;
     RECT  66.78 25.147 67.914 25.213 ;
     RECT  107.928 24.427 107.946 25.213 ;
     RECT  195.336 23.125 195.354 25.213 ;
     RECT  196.092 24.871 199.206 25.213 ;
     RECT  102.024 25.195 102.726 25.241 ;
     RECT  152.532 25.147 154.494 25.243 ;
     RECT  174.492 25.141 175.497 25.243 ;
     RECT  176.436 25.195 176.634 25.243 ;
     RECT  122.544 25.213 122.562 25.249 ;
     RECT  126.216 24.475 126.897 25.249 ;
     RECT  177.804 25.177 177.822 25.249 ;
     RECT  179.46 25.177 179.622 25.249 ;
     RECT  71.604 25.141 74.322 25.285 ;
     RECT  107.928 25.213 107.982 25.285 ;
     RECT  123.696 25.141 123.786 25.285 ;
     RECT  177.768 25.249 177.822 25.285 ;
     RECT  78.015 24.368 78.297 25.291 ;
     RECT  2.415 24.665 25.434 25.313 ;
     RECT  106.596 25.213 106.614 25.313 ;
     RECT  57.96 24.673 58.122 25.321 ;
     RECT  71.532 25.285 74.322 25.321 ;
     RECT  94.032 25.205 94.497 25.321 ;
     RECT  101.052 24.907 101.07 25.321 ;
     RECT  137.376 23.899 137.697 25.321 ;
     RECT  176.436 25.243 176.886 25.321 ;
     RECT  177.768 25.285 177.93 25.321 ;
     RECT  194.508 25.177 194.526 25.321 ;
     RECT  27.9 25.169 37.926 25.325 ;
     RECT  210.024 25.169 212.202 25.325 ;
     RECT  177.696 25.321 177.93 25.339 ;
     RECT  38.664 25.169 38.862 25.349 ;
     RECT  102.024 25.241 102.69 25.349 ;
     RECT  114.192 24.899 114.21 25.349 ;
     RECT  210.024 25.325 212.022 25.349 ;
     RECT  110.415 25.147 113.454 25.373 ;
     RECT  26.388 25.037 27.126 25.411 ;
     RECT  98.316 25.177 98.658 25.411 ;
     RECT  103.608 24.943 103.842 25.411 ;
     RECT  188.712 24.943 188.73 25.411 ;
     RECT  189.792 25.177 189.81 25.411 ;
     RECT  69.156 25.147 70.758 25.435 ;
     RECT  176.436 25.321 176.958 25.435 ;
     RECT  177.696 25.339 178.434 25.435 ;
     RECT  43.74 25.099 43.758 25.439 ;
     RECT  44.532 25.321 44.694 25.439 ;
     RECT  57.708 25.321 58.122 25.439 ;
     RECT  101.052 25.321 101.25 25.439 ;
     RECT  110.415 25.373 113.418 25.439 ;
     RECT  141.372 24.943 143.097 25.439 ;
     RECT  179.388 25.249 179.622 25.439 ;
     RECT  210.024 25.349 211.806 25.439 ;
     RECT  218.844 25.243 218.862 25.439 ;
     RECT  77.94 25.291 78.297 25.447 ;
     RECT  123.696 25.285 124.254 25.447 ;
     RECT  151.524 25.243 151.542 25.447 ;
     RECT  194.436 25.321 194.526 25.447 ;
     RECT  38.7 25.349 38.862 25.469 ;
     RECT  174.42 25.243 175.497 25.469 ;
     RECT  57.708 25.439 57.726 25.475 ;
     RECT  101.052 25.439 101.07 25.475 ;
     RECT  103.608 25.411 104.094 25.475 ;
     RECT  210.024 25.439 211.662 25.475 ;
     RECT  26.28 25.411 27.126 25.483 ;
     RECT  195.336 25.213 199.206 25.483 ;
     RECT  200.268 23.287 200.286 25.483 ;
     RECT  81.864 25.411 81.882 25.511 ;
     RECT  176.436 25.435 178.434 25.511 ;
     RECT  179.388 25.439 179.586 25.511 ;
     RECT  188.712 25.411 189.81 25.511 ;
     RECT  100.944 25.477 100.962 25.517 ;
     RECT  103.644 25.475 104.094 25.517 ;
     RECT  123.696 25.447 124.578 25.517 ;
     RECT  150.48 25.243 150.498 25.517 ;
     RECT  152.532 25.243 154.602 25.517 ;
     RECT  56.415 24.368 56.697 25.531 ;
     RECT  25.992 25.483 27.126 25.547 ;
     RECT  38.844 25.469 38.862 25.547 ;
     RECT  112.608 25.439 113.418 25.547 ;
     RECT  176.508 25.511 178.434 25.547 ;
     RECT  83.415 24.368 83.697 25.555 ;
     RECT  213.015 25.169 213.75 25.555 ;
     RECT  69.156 25.435 70.794 25.565 ;
     RECT  176.976 25.547 178.434 25.565 ;
     RECT  42.804 25.321 42.822 25.583 ;
     RECT  44.532 25.439 44.55 25.583 ;
     RECT  71.532 25.321 74.358 25.583 ;
     RECT  110.415 25.439 111.546 25.583 ;
     RECT  112.68 25.547 113.418 25.583 ;
     RECT  152.532 25.517 153.897 25.583 ;
     RECT  194.364 25.447 194.526 25.583 ;
     RECT  217.116 25.411 217.134 25.583 ;
     RECT  51.015 2.413 51.297 25.591 ;
     RECT  77.688 25.447 78.297 25.591 ;
     RECT  125.964 25.249 127.134 25.591 ;
     RECT  151.524 25.447 151.614 25.591 ;
     RECT  152.532 25.583 152.838 25.591 ;
     RECT  28.944 25.325 37.926 25.619 ;
     RECT  77.688 25.591 78.354 25.619 ;
     RECT  174.492 25.469 175.497 25.619 ;
     RECT  195.336 25.483 200.286 25.619 ;
     RECT  26.532 25.547 27.126 25.661 ;
     RECT  28.944 25.619 29.697 25.667 ;
     RECT  40.215 23.309 40.497 25.667 ;
     RECT  45.615 24.269 45.897 25.667 ;
     RECT  51.015 25.591 51.894 25.667 ;
     RECT  61.815 2.413 62.097 25.667 ;
     RECT  99.615 24.368 99.897 25.667 ;
     RECT  105.015 2.413 105.297 25.667 ;
     RECT  115.815 25.169 116.097 25.667 ;
     RECT  121.215 24.368 121.497 25.667 ;
     RECT  132.015 24.368 132.297 25.667 ;
     RECT  142.272 25.439 143.097 25.667 ;
     RECT  153.615 25.583 153.897 25.667 ;
     RECT  159.015 2.413 159.297 25.667 ;
     RECT  163.728 24.943 164.697 25.667 ;
     RECT  174.816 25.619 175.497 25.667 ;
     RECT  180.615 2.413 180.897 25.667 ;
     RECT  191.415 2.413 191.697 25.667 ;
     RECT  66.708 25.213 67.914 25.672 ;
     RECT  94.032 25.321 94.662 25.681 ;
     RECT  115.815 25.667 115.905 25.681 ;
     RECT  119.664 24.403 119.682 25.681 ;
     RECT  121.215 25.667 121.305 25.681 ;
     RECT  146.556 25.321 146.574 25.681 ;
     RECT  180.615 25.667 180.774 25.681 ;
     RECT  184.716 25.483 184.734 25.681 ;
     RECT  194.436 25.583 194.526 25.681 ;
     RECT  195.336 25.619 195.75 25.681 ;
     RECT  27.9 25.325 28.17 25.709 ;
     RECT  28.944 25.667 29.505 25.709 ;
     RECT  30.456 25.619 37.926 25.709 ;
     RECT  44.46 25.591 44.478 25.709 ;
     RECT  47.844 25.672 47.862 25.709 ;
     RECT  56.415 25.531 57.186 25.709 ;
     RECT  87.912 23.357 87.93 25.709 ;
     RECT  88.815 24.475 89.406 25.709 ;
     RECT  134.604 25.483 134.766 25.709 ;
     RECT  135.54 25.015 135.558 25.709 ;
     RECT  151.524 25.591 151.686 25.709 ;
     RECT  189.792 25.511 189.81 25.709 ;
     RECT  196.596 25.619 200.286 25.709 ;
     RECT  72.396 25.583 74.358 25.717 ;
     RECT  90.684 25.681 90.702 25.717 ;
     RECT  107.604 25.285 107.982 25.717 ;
     RECT  136.8 25.321 137.697 25.717 ;
     RECT  28.008 25.709 28.17 25.745 ;
     RECT  29.088 25.709 29.505 25.745 ;
     RECT  30.456 25.709 37.818 25.745 ;
     RECT  103.644 25.517 103.914 25.745 ;
     RECT  125.748 25.591 127.134 25.745 ;
     RECT  134.604 25.709 134.622 25.745 ;
     RECT  142.272 25.667 142.905 25.745 ;
     RECT  152.424 25.591 152.838 25.745 ;
     RECT  177.696 25.565 178.434 25.745 ;
     RECT  179.424 25.511 179.586 25.745 ;
     RECT  184.716 25.681 184.914 25.745 ;
     RECT  188.712 25.511 188.91 25.745 ;
     RECT  51.015 25.667 51.105 25.753 ;
     RECT  66.708 25.672 68.346 25.753 ;
     RECT  69.156 25.565 70.686 25.753 ;
     RECT  115.524 25.681 115.905 25.753 ;
     RECT  119.664 25.681 119.754 25.753 ;
     RECT  120.816 25.681 121.305 25.753 ;
     RECT  122.544 25.249 122.634 25.753 ;
     RECT  130.428 24.809 130.698 25.753 ;
     RECT  151.524 25.709 151.542 25.753 ;
     RECT  163.728 25.667 164.505 25.753 ;
     RECT  169.815 2.413 170.097 25.753 ;
     RECT  186.015 24.368 186.297 25.753 ;
     RECT  180.468 25.681 180.774 25.757 ;
     RECT  151.272 25.753 151.542 25.781 ;
     RECT  194.436 25.681 195.75 25.781 ;
     RECT  78.015 25.619 78.354 25.789 ;
     RECT  83.415 25.555 84.402 25.789 ;
     RECT  166.248 25.753 166.266 25.789 ;
     RECT  182.556 25.681 182.574 25.789 ;
     RECT  184.896 25.745 184.914 25.789 ;
     RECT  62.712 25.681 62.802 25.817 ;
     RECT  182.484 25.789 182.574 25.817 ;
     RECT  72.396 25.717 74.754 25.825 ;
     RECT  90.684 25.717 90.738 25.825 ;
     RECT  115.452 25.753 115.905 25.825 ;
     RECT  119.592 25.753 119.754 25.825 ;
     RECT  120.708 25.753 121.305 25.825 ;
     RECT  130.428 25.753 130.914 25.825 ;
     RECT  148.215 23.555 148.497 25.825 ;
     RECT  162.576 25.753 164.505 25.825 ;
     RECT  50.724 25.753 51.105 25.853 ;
     RECT  119.592 25.825 121.305 25.853 ;
     RECT  122.544 25.753 122.706 25.853 ;
     RECT  146.556 25.681 146.646 25.853 ;
     RECT  186.015 25.753 186.426 25.853 ;
     RECT  54.936 25.825 54.954 25.861 ;
     RECT  56.415 25.709 56.682 25.861 ;
     RECT  86.688 25.681 86.814 25.861 ;
     RECT  90.684 25.825 90.81 25.861 ;
     RECT  94.032 25.681 94.734 25.861 ;
     RECT  98.064 25.411 98.658 25.861 ;
     RECT  148.215 25.825 148.59 25.861 ;
     RECT  166.212 25.789 166.266 25.861 ;
     RECT  169.815 25.753 170.442 25.861 ;
     RECT  178.416 25.745 178.434 25.861 ;
     RECT  130.212 25.825 130.914 25.862 ;
     RECT  31.464 25.745 32.742 25.889 ;
     RECT  33.984 25.745 37.818 25.889 ;
     RECT  71.424 25.819 71.442 25.889 ;
     RECT  151.272 25.781 151.47 25.889 ;
     RECT  152.46 25.745 152.838 25.889 ;
     RECT  184.896 25.789 185.274 25.889 ;
     RECT  98.064 25.861 98.766 25.901 ;
     RECT  120.276 25.853 121.305 25.901 ;
     RECT  29.232 25.745 29.505 25.937 ;
     RECT  40.215 25.667 40.305 25.937 ;
     RECT  51.015 25.853 51.105 25.937 ;
     RECT  61.815 25.667 61.905 25.937 ;
     RECT  78.015 25.789 78.894 25.937 ;
     RECT  88.815 25.709 89.154 25.937 ;
     RECT  99.615 25.667 99.705 25.937 ;
     RECT  105.015 25.667 105.105 25.937 ;
     RECT  110.415 25.583 111.474 25.937 ;
     RECT  115.092 25.825 115.905 25.937 ;
     RECT  120.348 25.901 121.305 25.937 ;
     RECT  132.015 25.667 132.105 25.937 ;
     RECT  136.8 25.717 137.898 25.937 ;
     RECT  142.524 25.745 142.905 25.937 ;
     RECT  148.215 25.861 148.77 25.937 ;
     RECT  153.615 25.667 153.705 25.937 ;
     RECT  159.015 25.667 159.105 25.937 ;
     RECT  162.54 25.825 164.505 25.937 ;
     RECT  169.815 25.861 170.514 25.937 ;
     RECT  174.816 25.667 175.305 25.937 ;
     RECT  180.615 25.757 180.774 25.937 ;
     RECT  186.015 25.853 186.39 25.937 ;
     RECT  191.415 25.667 191.682 25.937 ;
     RECT  118.62 25.753 118.746 25.951 ;
     RECT  125.964 25.745 127.134 25.951 ;
     RECT  146.556 25.853 146.61 25.951 ;
     RECT  162.54 25.937 163.746 25.951 ;
     RECT  45.615 25.667 45.81 25.963 ;
     RECT  58.5 25.861 58.518 25.963 ;
     RECT  59.4 25.861 59.418 25.963 ;
     RECT  86.688 25.861 86.85 25.963 ;
     RECT  87.66 25.825 87.678 25.963 ;
     RECT  28.152 25.745 28.17 25.979 ;
     RECT  32.652 25.889 32.742 25.979 ;
     RECT  36.324 25.889 37.818 25.979 ;
     RECT  76.356 25.789 76.374 25.979 ;
     RECT  122.544 25.853 122.634 25.979 ;
     RECT  152.568 25.889 152.838 25.979 ;
     RECT  180.756 25.937 180.774 25.979 ;
     RECT  182.484 25.817 182.502 25.979 ;
     RECT  191.664 25.937 191.682 25.979 ;
     RECT  46.692 25.861 46.71 25.987 ;
     RECT  54.936 25.861 55.206 25.987 ;
     RECT  33.984 25.889 35.334 26.015 ;
     RECT  45.504 25.963 45.81 26.015 ;
     RECT  118.584 25.951 118.746 26.015 ;
     RECT  125.964 25.951 127.206 26.015 ;
     RECT  194.436 25.781 194.454 26.015 ;
     RECT  206.352 25.861 206.37 26.015 ;
     RECT  86.688 25.963 87.678 26.023 ;
     RECT  56.124 25.861 56.682 26.045 ;
     RECT  78.66 25.937 78.894 26.045 ;
     RECT  2.415 25.313 25.182 26.051 ;
     RECT  26.532 25.661 26.874 26.051 ;
     RECT  32.724 25.979 32.742 26.051 ;
     RECT  34.056 26.015 35.262 26.051 ;
     RECT  46.692 25.987 46.782 26.051 ;
     RECT  66.708 25.753 70.686 26.051 ;
     RECT  72.396 25.825 75.366 26.051 ;
     RECT  90.684 25.861 91.062 26.051 ;
     RECT  103.896 25.745 103.914 26.051 ;
     RECT  126 26.015 127.206 26.051 ;
     RECT  137.7 25.937 137.898 26.051 ;
     RECT  146.484 25.951 146.61 26.051 ;
     RECT  151.308 25.889 151.47 26.051 ;
     RECT  178.416 25.861 178.614 26.051 ;
     RECT  184.896 25.889 184.914 26.051 ;
     RECT  186.156 25.937 186.39 26.051 ;
     RECT  188.892 25.745 188.91 26.051 ;
     RECT  86.652 26.023 87.678 26.06 ;
     RECT  64.008 25.861 64.098 26.087 ;
     RECT  118.584 26.015 118.638 26.087 ;
     RECT  122.544 25.979 122.562 26.087 ;
     RECT  126 26.051 126.774 26.087 ;
     RECT  158.472 25.951 158.49 26.087 ;
     RECT  162.468 25.951 163.746 26.087 ;
     RECT  174.816 25.937 174.978 26.087 ;
     RECT  29.232 25.937 29.25 26.093 ;
     RECT  58.5 25.963 59.418 26.093 ;
     RECT  62.892 25.861 62.91 26.093 ;
     RECT  70.02 26.051 70.686 26.093 ;
     RECT  86.652 26.06 86.922 26.093 ;
     RECT  213.015 25.555 213.858 26.095 ;
     RECT  31.464 25.889 31.554 26.123 ;
     RECT  37.008 25.979 37.818 26.123 ;
     RECT  42.768 25.987 42.786 26.123 ;
     RECT  46.764 26.051 46.782 26.123 ;
     RECT  54.72 25.987 55.206 26.123 ;
     RECT  56.664 26.045 56.682 26.123 ;
     RECT  78.732 26.045 78.894 26.123 ;
     RECT  82.656 25.789 84.402 26.123 ;
     RECT  110.592 25.937 111.474 26.123 ;
     RECT  118.62 26.087 118.638 26.123 ;
     RECT  120.348 25.937 120.87 26.123 ;
     RECT  126.468 26.087 126.774 26.123 ;
     RECT  130.212 25.862 130.878 26.123 ;
     RECT  150.552 26.023 150.57 26.123 ;
     RECT  152.64 25.979 152.838 26.123 ;
     RECT  162.576 26.087 163.746 26.123 ;
     RECT  195.444 25.781 195.75 26.123 ;
     RECT  37.008 26.123 37.026 26.141 ;
     RECT  86.724 26.093 86.922 26.141 ;
     RECT  37.8 26.123 37.818 26.159 ;
     RECT  64.008 26.087 64.026 26.159 ;
     RECT  66.708 26.051 68.994 26.159 ;
     RECT  72.396 26.051 74.466 26.159 ;
     RECT  78.768 26.123 78.894 26.159 ;
     RECT  82.656 26.123 83.574 26.159 ;
     RECT  86.724 26.141 86.85 26.159 ;
     RECT  90.72 26.051 91.062 26.159 ;
     RECT  110.592 26.123 110.682 26.159 ;
     RECT  115.092 25.937 115.722 26.159 ;
     RECT  146.52 26.051 146.61 26.159 ;
     RECT  152.712 26.123 152.838 26.159 ;
     RECT  2.415 26.051 24.534 26.189 ;
     RECT  110.592 26.159 110.61 26.189 ;
     RECT  111.456 26.123 111.474 26.189 ;
     RECT  26.532 26.051 26.838 26.204 ;
     RECT  34.74 26.051 35.262 26.204 ;
     RECT  59.4 26.093 59.418 26.204 ;
     RECT  174.816 26.087 174.834 26.204 ;
     RECT  178.416 26.051 178.434 26.204 ;
     RECT  179.568 25.745 179.586 26.204 ;
     RECT  195.732 26.123 195.75 26.204 ;
     RECT  76.392 26.095 76.41 26.249 ;
     RECT  90.792 26.159 91.062 26.285 ;
     RECT  170.208 25.937 170.514 26.285 ;
     RECT  107.604 25.717 108.198 26.321 ;
     RECT  165.636 25.861 166.626 26.321 ;
     RECT  72.396 26.159 74.25 26.357 ;
     RECT  123.696 25.517 124.326 26.357 ;
     RECT  151.38 26.051 151.47 26.357 ;
     RECT  163.26 26.123 163.746 26.357 ;
     RECT  84.384 26.123 84.402 26.393 ;
     RECT  120.348 26.123 120.618 26.393 ;
     RECT  152.784 26.159 152.802 26.393 ;
     RECT  196.668 25.709 200.286 26.401 ;
     RECT  212.616 26.095 213.858 26.401 ;
     RECT  51.876 25.667 51.894 26.429 ;
     RECT  170.208 26.285 170.226 26.429 ;
     RECT  216.144 26.401 216.162 26.443 ;
     RECT  212.58 26.401 214.038 26.491 ;
     RECT  217.944 26.365 217.962 26.491 ;
     RECT  90.792 26.285 90.81 26.519 ;
     RECT  216 26.443 216.162 26.519 ;
     RECT  217.764 26.491 217.962 26.519 ;
     RECT  54.936 26.123 55.206 26.525 ;
     RECT  210.024 25.475 211.446 26.539 ;
     RECT  87.66 26.06 87.678 26.555 ;
     RECT  89.136 25.937 89.154 26.573 ;
     RECT  107.604 26.321 107.874 26.573 ;
     RECT  218.88 26.401 218.898 26.573 ;
     RECT  202.215 2.413 202.497 26.587 ;
     RECT  202.215 26.587 203.202 26.599 ;
     RECT  67.464 26.159 68.994 26.621 ;
     RECT  137.88 26.051 137.898 26.627 ;
     RECT  2.415 26.189 23.742 26.635 ;
     RECT  31.464 26.123 31.482 26.663 ;
     RECT  112.824 25.583 113.418 26.663 ;
     RECT  136.8 25.937 136.818 26.663 ;
     RECT  151.452 26.357 151.47 26.669 ;
     RECT  217.764 26.519 217.89 26.671 ;
     RECT  82.98 26.159 83.574 26.699 ;
     RECT  163.26 26.357 163.278 26.699 ;
     RECT  26.532 26.204 26.55 26.744 ;
     RECT  186.156 26.051 186.174 26.744 ;
     RECT  165.636 26.321 165.654 26.789 ;
     RECT  217.116 26.671 217.89 26.789 ;
     RECT  142.524 25.937 142.542 26.797 ;
     RECT  2.304 26.635 23.742 26.825 ;
     RECT  142.524 26.797 142.614 26.825 ;
     RECT  196.668 26.401 200.79 26.825 ;
     RECT  217.116 26.789 217.782 26.825 ;
     RECT  202.215 26.599 203.274 26.833 ;
     RECT  67.716 26.621 68.994 26.897 ;
     RECT  24.516 26.189 24.534 26.933 ;
     RECT  35.244 26.204 35.262 26.969 ;
     RECT  148.572 25.937 148.77 27.053 ;
     RECT  166.608 26.321 166.626 27.059 ;
     RECT  217.26 26.825 217.494 27.059 ;
     RECT  68.508 26.897 68.994 27.095 ;
     RECT  212.58 26.491 214.722 27.095 ;
     RECT  217.26 27.059 217.278 27.095 ;
     RECT  78.768 26.159 78.786 27.101 ;
     RECT  98.064 25.901 98.694 27.101 ;
     RECT  196.776 26.825 200.79 27.103 ;
     RECT  201.528 26.833 203.274 27.103 ;
     RECT  83.232 26.699 83.574 27.131 ;
     RECT  120.348 26.393 120.366 27.149 ;
     RECT  126.468 26.123 126.486 27.149 ;
     RECT  58.5 26.093 58.518 27.167 ;
     RECT  83.232 27.131 83.25 27.167 ;
     RECT  47.7 25.753 47.718 27.197 ;
     RECT  80.604 25.861 80.622 27.203 ;
     RECT  96.3 25.321 96.318 27.203 ;
     RECT  113.148 26.663 113.418 27.239 ;
     RECT  107.604 26.573 107.622 27.284 ;
     RECT  115.092 26.159 115.362 27.284 ;
     RECT  215.1 27.211 215.118 27.869 ;
     RECT  219.42 27.835 219.438 27.905 ;
     RECT  196.776 27.103 203.274 27.913 ;
     RECT  216.036 27.841 216.054 27.913 ;
     RECT  214.956 27.877 214.974 27.917 ;
     RECT  210.024 26.539 211.806 27.931 ;
     RECT  212.58 27.095 214.218 27.931 ;
     RECT  2.415 26.825 23.742 27.941 ;
     RECT  217.8 27.841 217.818 27.941 ;
     RECT  216.036 27.913 216.702 27.985 ;
     RECT  3.42 27.941 23.742 28.08 ;
     RECT  30.456 25.745 30.582 28.08 ;
     RECT  54.936 26.525 54.954 28.08 ;
     RECT  67.716 26.897 67.734 28.08 ;
     RECT  68.976 27.095 68.994 28.08 ;
     RECT  70.056 26.093 70.686 28.08 ;
     RECT  72.864 26.357 74.25 28.08 ;
     RECT  75.348 26.051 75.366 28.08 ;
     RECT  94.032 25.861 95.166 28.08 ;
     RECT  98.676 27.101 98.694 28.08 ;
     RECT  102.024 25.349 102.618 28.08 ;
     RECT  115.092 27.284 115.11 28.08 ;
     RECT  123.948 26.357 124.326 28.08 ;
     RECT  130.212 26.123 130.806 28.08 ;
     RECT  142.596 26.825 142.614 28.08 ;
     RECT  148.752 27.053 148.77 28.08 ;
     RECT  196.776 27.913 203.706 28.08 ;
     RECT  216.036 27.985 216.882 28.139 ;
     RECT  210.024 27.931 214.218 28.175 ;
     RECT  216.036 28.139 216.702 28.175 ;
     RECT  213.015 28.175 214.218 28.219 ;
     RECT  216.144 28.175 216.306 28.409 ;
     RECT  216.144 28.409 216.162 28.445 ;
     RECT  213.015 28.219 214.506 28.715 ;
     RECT  2.415 27.941 2.697 28.939 ;
     RECT  213.015 28.715 213.894 28.949 ;
     RECT  214.668 28.921 214.974 29.065 ;
     RECT  214.668 29.065 215.082 29.219 ;
     RECT  219.42 29.131 219.438 29.219 ;
     RECT  214.668 29.219 214.974 29.255 ;
     RECT  217.764 28.921 217.782 29.255 ;
     RECT  2.304 28.939 2.697 29.365 ;
     RECT  3.42 28.08 203.706 29.365 ;
     RECT  210.024 28.175 212.094 29.419 ;
     RECT  213.015 28.949 213.822 29.419 ;
     RECT  214.812 29.255 214.902 29.489 ;
     RECT  214.812 29.489 214.83 29.525 ;
     RECT  206.352 29.467 206.37 29.597 ;
     RECT  204.876 27.481 204.894 29.605 ;
     RECT  210.024 29.419 213.822 30.271 ;
     RECT  210.024 30.271 213.93 30.415 ;
     RECT  210.024 30.415 214.326 30.451 ;
     RECT  218.844 30.427 218.862 30.569 ;
     RECT  0.108 20.731 0.126 30.604 ;
     RECT  0.108 30.604 0.162 30.605 ;
     RECT  210.024 30.451 214.506 30.605 ;
     RECT  0.144 30.605 0.162 30.677 ;
     RECT  2.304 29.365 203.706 30.749 ;
     RECT  2.304 30.749 198.666 30.839 ;
     RECT  0.54 30.955 0.558 31.217 ;
     RECT  199.512 30.749 203.706 31.261 ;
     RECT  204.588 29.605 204.894 31.261 ;
     RECT  2.304 30.839 198.63 31.415 ;
     RECT  199.512 31.261 204.894 31.801 ;
     RECT  214.92 31.339 214.938 31.801 ;
     RECT  199.512 31.801 205.398 31.919 ;
     RECT  210.024 30.605 213.894 31.919 ;
     RECT  214.92 31.801 215.082 31.919 ;
     RECT  217.332 31.891 217.35 31.999 ;
     RECT  199.512 31.919 205.362 32.011 ;
     RECT  216.072 31.891 216.09 32.071 ;
     RECT  217.332 31.999 217.53 32.071 ;
     RECT  216.072 32.071 217.818 32.189 ;
     RECT  219.42 31.723 219.438 32.189 ;
     RECT  216.072 32.189 216.09 32.225 ;
     RECT  217.332 32.189 217.818 32.225 ;
     RECT  199.476 32.011 205.362 32.459 ;
     RECT  199.476 32.459 205.254 32.495 ;
     RECT  2.415 31.415 198.63 32.701 ;
     RECT  199.476 32.495 205.074 32.701 ;
     RECT  213.015 31.919 213.894 32.701 ;
     RECT  213.015 32.701 213.966 32.881 ;
     RECT  2.415 32.701 205.074 32.957 ;
     RECT  210.024 31.919 212.13 32.971 ;
     RECT  212.868 32.881 213.966 32.971 ;
     RECT  210.024 32.971 213.966 32.999 ;
     RECT  215.712 32.971 215.73 33.035 ;
     RECT  218.88 33.007 218.898 33.053 ;
     RECT  210.024 32.999 213.894 33.107 ;
     RECT  216.828 33.079 216.846 33.115 ;
     RECT  216.828 33.115 217.17 33.151 ;
     RECT  216.648 33.151 217.17 33.269 ;
     RECT  216.648 33.269 216.846 33.305 ;
     RECT  216.684 33.305 216.81 33.539 ;
     RECT  216.684 33.539 216.702 33.575 ;
     RECT  2.415 32.957 204.894 34.159 ;
     RECT  210.024 33.107 213.822 34.231 ;
     RECT  2.268 34.159 205.002 34.253 ;
     RECT  218.844 34.267 218.862 34.349 ;
     RECT  208.692 34.321 208.71 34.397 ;
     RECT  210.024 34.231 214.002 34.501 ;
     RECT  217.224 34.357 217.242 34.529 ;
     RECT  210.024 34.501 214.182 34.619 ;
     RECT  210.024 34.619 214.11 34.655 ;
     RECT  207.615 2.413 207.897 35.563 ;
     RECT  207.504 35.563 207.897 35.609 ;
     RECT  210.024 34.655 213.822 35.671 ;
     RECT  215.172 34.429 215.19 35.671 ;
     RECT  218.844 35.563 218.862 35.699 ;
     RECT  210.024 35.671 215.19 35.771 ;
     RECT  210.024 35.771 214.362 35.969 ;
     RECT  210.024 35.969 214.146 36.005 ;
     RECT  0.108 31.579 0.126 36.275 ;
     RECT  2.415 34.253 205.002 36.355 ;
     RECT  2.415 36.355 205.074 36.391 ;
     RECT  2.415 36.391 205.218 36.481 ;
     RECT  0.54 36.571 0.558 36.653 ;
     RECT  2.415 36.481 205.362 36.661 ;
     RECT  215.172 35.771 215.19 36.661 ;
     RECT  215.172 36.661 215.55 36.779 ;
     RECT  210.024 36.005 214.11 36.815 ;
     RECT  215.172 36.779 215.406 36.815 ;
     RECT  217.152 36.895 217.17 36.931 ;
     RECT  216.468 36.931 217.818 37.049 ;
     RECT  219.42 36.859 219.438 37.049 ;
     RECT  207.615 35.609 207.897 37.057 ;
     RECT  216.468 37.049 216.954 37.085 ;
     RECT  217.8 37.049 217.818 37.085 ;
     RECT  216.504 37.085 216.702 37.319 ;
     RECT  2.415 36.661 206.226 37.327 ;
     RECT  206.964 37.057 207.897 37.327 ;
     RECT  216.504 37.319 216.522 37.355 ;
     RECT  210.024 36.815 214.038 37.579 ;
     RECT  209.916 37.579 214.038 37.589 ;
     RECT  2.415 37.327 207.897 37.597 ;
     RECT  209.916 37.589 210.042 37.625 ;
     RECT  210.888 37.589 214.038 37.895 ;
     RECT  2.415 37.597 208.278 37.901 ;
     RECT  214.02 37.895 214.038 38.011 ;
     RECT  215.172 36.815 215.19 38.011 ;
     RECT  216.144 37.975 216.342 38.011 ;
     RECT  214.02 38.011 216.342 38.129 ;
     RECT  214.02 38.129 215.586 38.165 ;
     RECT  216.324 38.129 216.342 38.165 ;
     RECT  215.1 38.165 215.19 38.201 ;
     RECT  219.42 38.155 219.438 38.201 ;
     RECT  210.888 37.895 213.297 38.237 ;
     RECT  22.896 37.901 208.278 38.551 ;
     RECT  2.415 37.901 22.158 38.621 ;
     RECT  210.024 37.625 210.042 38.749 ;
     RECT  3.42 38.621 22.158 38.947 ;
     RECT  22.896 38.551 208.35 38.947 ;
     RECT  3.42 38.947 208.35 38.957 ;
     RECT  0.108 37.195 0.126 38.975 ;
     RECT  22.248 38.957 208.35 39.181 ;
     RECT  211.176 38.237 213.297 39.181 ;
     RECT  214.02 38.165 214.038 39.181 ;
     RECT  209.736 38.749 210.042 39.209 ;
     RECT  2.415 38.621 2.697 39.211 ;
     RECT  22.248 39.181 208.674 39.361 ;
     RECT  209.736 39.209 209.79 39.361 ;
     RECT  211.176 39.181 214.038 39.451 ;
     RECT  215.172 38.201 215.19 39.451 ;
     RECT  22.248 39.361 208.818 39.479 ;
     RECT  218.88 39.445 218.898 39.485 ;
     RECT  22.248 39.479 208.674 39.515 ;
     RECT  211.176 39.451 214.146 39.515 ;
     RECT  214.02 39.515 214.146 39.551 ;
     RECT  215.172 39.451 215.262 39.551 ;
     RECT  0.54 39.499 0.558 39.587 ;
     RECT  215.172 39.551 215.19 39.595 ;
     RECT  2.304 39.211 2.697 39.631 ;
     RECT  3.42 38.957 21.51 39.631 ;
     RECT  215.064 39.595 215.19 39.631 ;
     RECT  209.592 39.361 209.79 39.749 ;
     RECT  209.592 39.749 209.61 39.785 ;
     RECT  214.884 39.631 215.19 39.785 ;
     RECT  2.304 39.631 21.51 39.787 ;
     RECT  22.248 39.515 208.278 39.787 ;
     RECT  2.304 39.787 208.278 39.917 ;
     RECT  3.42 39.917 208.278 40.019 ;
     RECT  2.304 39.917 2.697 40.055 ;
     RECT  22.32 40.019 208.278 40.109 ;
     RECT  22.716 40.109 208.278 40.297 ;
     RECT  22.716 40.297 208.674 40.675 ;
     RECT  211.176 39.515 213.297 40.675 ;
     RECT  214.02 39.551 214.038 40.675 ;
     RECT  211.176 40.675 214.038 40.739 ;
     RECT  218.844 40.747 218.862 40.829 ;
     RECT  217.152 40.801 217.17 40.901 ;
     RECT  22.716 40.675 208.854 41.135 ;
     RECT  212.364 40.739 214.038 41.135 ;
     RECT  22.716 41.135 208.098 41.143 ;
     RECT  0.108 40.171 0.126 41.179 ;
     RECT  22.248 41.143 208.098 41.357 ;
     RECT  208.836 41.135 208.854 41.369 ;
     RECT  0.108 41.179 0.558 41.477 ;
     RECT  2.415 40.055 2.697 41.611 ;
     RECT  3.42 40.019 21.51 41.611 ;
     RECT  215.172 39.785 215.19 41.611 ;
     RECT  22.68 41.357 208.098 41.639 ;
     RECT  22.68 41.639 208.062 41.675 ;
     RECT  22.68 41.675 206.514 41.819 ;
     RECT  207.36 41.675 208.062 41.909 ;
     RECT  215.136 41.611 215.19 41.909 ;
     RECT  207.504 41.909 207.954 42.017 ;
     RECT  214.02 41.135 214.038 42.089 ;
     RECT  22.68 41.819 205.65 42.125 ;
     RECT  2.415 41.611 21.51 42.139 ;
     RECT  22.752 42.125 205.65 42.179 ;
     RECT  219.42 42.043 219.438 42.179 ;
     RECT  2.304 42.139 21.51 42.215 ;
     RECT  216.252 42.061 216.27 42.215 ;
     RECT  207.615 42.017 207.954 42.251 ;
     RECT  217.8 42.151 217.818 42.251 ;
     RECT  217.044 42.295 217.062 42.331 ;
     RECT  22.752 42.179 205.614 42.449 ;
     RECT  206.388 41.819 206.406 42.449 ;
     RECT  216.396 42.331 217.062 42.449 ;
     RECT  22.752 42.449 205.47 42.485 ;
     RECT  216.396 42.449 216.954 42.485 ;
     RECT  22.752 42.485 204.966 42.629 ;
     RECT  215.172 41.909 215.19 42.763 ;
     RECT  2.415 42.215 21.51 42.955 ;
     RECT  2.415 42.955 21.69 43.061 ;
     RECT  212.364 41.135 213.297 43.169 ;
     RECT  214.704 42.763 215.19 43.259 ;
     RECT  219.42 43.291 219.438 43.331 ;
     RECT  22.788 42.629 204.966 43.411 ;
     RECT  215.172 43.259 215.19 43.411 ;
     RECT  216.36 43.375 216.378 43.411 ;
     RECT  22.248 43.411 204.966 43.469 ;
     RECT  215.172 43.411 216.378 43.529 ;
     RECT  215.172 43.529 216.234 43.565 ;
     RECT  0.108 41.477 0.126 43.681 ;
     RECT  215.172 43.565 216.09 43.799 ;
     RECT  2.415 43.061 21.51 43.835 ;
     RECT  22.752 43.469 204.966 43.835 ;
     RECT  215.172 43.799 215.91 43.835 ;
     RECT  0.108 43.681 0.558 43.853 ;
     RECT  3.528 43.835 21.51 44.221 ;
     RECT  22.788 43.835 204.966 44.419 ;
     RECT  2.415 43.835 2.754 44.587 ;
     RECT  3.528 44.221 21.69 44.587 ;
     RECT  218.88 44.581 218.898 44.621 ;
     RECT  215.172 43.835 215.19 44.725 ;
     RECT  211.176 40.739 211.194 44.753 ;
     RECT  212.616 43.169 213.297 44.761 ;
     RECT  214.992 44.725 215.19 44.761 ;
     RECT  212.616 44.761 215.19 44.915 ;
     RECT  214.128 44.915 214.362 45.149 ;
     RECT  214.128 45.149 214.146 45.185 ;
     RECT  22.788 44.419 205.074 45.259 ;
     RECT  2.415 44.587 21.69 45.547 ;
     RECT  22.752 45.259 205.074 45.547 ;
     RECT  2.415 45.547 205.074 46.123 ;
     RECT  2.304 46.123 205.074 46.157 ;
     RECT  2.304 46.157 21.654 46.229 ;
     RECT  219.42 45.883 219.438 46.265 ;
     RECT  2.304 46.229 21.51 46.373 ;
     RECT  22.788 46.157 205.074 46.987 ;
     RECT  22.752 46.987 205.074 47.083 ;
     RECT  212.616 44.915 213.297 47.083 ;
     RECT  22.716 47.083 205.074 47.119 ;
     RECT  22.68 47.119 205.074 47.213 ;
     RECT  218.88 47.155 218.898 47.213 ;
     RECT  0.108 43.853 0.126 47.615 ;
     RECT  2.415 46.373 21.51 47.731 ;
     RECT  2.415 47.731 21.69 47.755 ;
     RECT  212.616 47.083 213.786 47.849 ;
     RECT  212.616 47.849 213.57 47.885 ;
     RECT  22.752 47.213 205.074 47.981 ;
     RECT  2.304 47.755 21.69 48.001 ;
     RECT  2.304 48.001 21.726 48.127 ;
     RECT  22.752 47.981 198.45 48.127 ;
     RECT  2.304 48.127 198.45 48.155 ;
     RECT  0.54 48.091 0.558 48.227 ;
     RECT  2.415 48.155 198.45 48.461 ;
     RECT  218.88 48.433 218.898 48.509 ;
     RECT  199.188 47.981 205.074 48.541 ;
     RECT  199.188 48.541 205.758 48.659 ;
     RECT  3.528 48.461 198.45 48.901 ;
     RECT  199.188 48.659 205.686 48.901 ;
     RECT  3.528 48.901 205.686 48.929 ;
     RECT  3.528 48.929 205.614 48.941 ;
     RECT  22.788 48.941 205.614 48.965 ;
     RECT  22.788 48.965 204.966 49.133 ;
     RECT  2.415 48.461 2.697 49.351 ;
     RECT  3.528 48.941 21.654 49.351 ;
     RECT  219.456 49.477 219.474 49.805 ;
     RECT  22.896 49.133 204.966 49.855 ;
     RECT  22.896 49.855 205.002 49.963 ;
     RECT  207.615 42.251 207.897 49.981 ;
     RECT  2.415 49.351 21.654 50.045 ;
     RECT  2.415 50.045 2.697 50.059 ;
     RECT  22.788 49.963 205.002 50.059 ;
     RECT  2.304 50.059 2.697 50.315 ;
     RECT  3.528 50.045 21.654 50.351 ;
     RECT  3.6 50.351 21.654 50.431 ;
     RECT  22.752 50.059 205.002 50.431 ;
     RECT  3.6 50.431 205.002 50.504 ;
     RECT  3.6 50.504 198.45 50.999 ;
     RECT  219.42 51.067 219.438 51.125 ;
     RECT  2.415 50.315 2.697 51.241 ;
     RECT  3.6 50.999 198.054 51.241 ;
     RECT  2.415 51.241 198.054 51.637 ;
     RECT  2.304 51.637 198.054 51.677 ;
     RECT  199.188 50.504 205.002 51.701 ;
     RECT  2.415 51.677 198.054 51.979 ;
     RECT  2.415 51.979 198.378 52.169 ;
     RECT  22.752 52.169 198.378 52.177 ;
     RECT  0.108 48.397 0.126 52.205 ;
     RECT  22.752 52.177 198.45 52.301 ;
     RECT  219.42 52.312 219.438 52.349 ;
     RECT  2.415 52.169 21.726 52.411 ;
     RECT  2.304 52.411 21.726 52.589 ;
     RECT  22.896 52.301 198.45 52.681 ;
     RECT  199.476 51.701 205.002 52.861 ;
     RECT  2.304 52.589 21.69 52.987 ;
     RECT  22.896 52.681 198.522 52.987 ;
     RECT  199.332 52.861 205.002 52.987 ;
     RECT  1.728 52.987 21.69 53.069 ;
     RECT  206.352 53.179 206.37 53.249 ;
     RECT  206.028 53.32 206.046 53.357 ;
     RECT  2.415 53.069 21.69 53.419 ;
     RECT  219.456 53.491 219.474 53.645 ;
     RECT  2.415 53.419 22.158 53.707 ;
     RECT  22.896 52.987 205.002 53.707 ;
     RECT  2.415 53.707 205.002 54.043 ;
     RECT  2.304 54.043 205.002 54.365 ;
     RECT  2.415 54.365 205.002 54.413 ;
     RECT  199.584 54.413 205.002 54.509 ;
     RECT  199.692 54.509 205.002 54.715 ;
     RECT  219.42 54.904 219.438 54.941 ;
     RECT  2.415 54.413 198.522 55.049 ;
     RECT  2.415 55.049 198.486 55.139 ;
     RECT  207.18 49.981 207.897 55.247 ;
     RECT  199.692 54.715 205.074 55.679 ;
     RECT  2.415 55.139 2.697 56.101 ;
     RECT  3.6 55.139 198.486 56.101 ;
     RECT  2.415 56.101 198.486 56.141 ;
     RECT  218.88 56.101 218.898 56.237 ;
     RECT  199.692 55.679 205.002 56.299 ;
     RECT  199.656 56.299 205.002 56.335 ;
     RECT  2.415 56.141 2.862 56.347 ;
     RECT  2.412 56.347 2.862 56.489 ;
     RECT  2.412 56.489 2.697 56.525 ;
     RECT  199.476 56.335 205.002 56.525 ;
     RECT  3.6 56.141 198.486 56.731 ;
     RECT  0.108 53.371 0.126 57.019 ;
     RECT  206.316 57.019 206.334 57.149 ;
     RECT  3.6 56.731 198.522 57.181 ;
     RECT  3.42 57.181 198.522 57.271 ;
     RECT  0.108 57.019 0.558 57.443 ;
     RECT  218.88 57.415 218.898 57.533 ;
     RECT  3.42 57.271 198.558 57.541 ;
     RECT  199.656 56.525 205.002 57.541 ;
     RECT  2.415 56.525 2.697 57.595 ;
     RECT  3.42 57.541 205.002 57.595 ;
     RECT  2.415 57.595 205.002 57.991 ;
     RECT  2.415 57.991 205.074 58.109 ;
     RECT  2.415 58.109 205.038 58.253 ;
     RECT  212.616 47.885 213.297 58.729 ;
     RECT  212.616 58.729 213.462 58.757 ;
     RECT  219.456 58.657 219.474 58.829 ;
     RECT  199.476 58.253 205.038 59.035 ;
     RECT  2.415 58.253 21.474 59.197 ;
     RECT  1.728 59.197 21.474 59.261 ;
     RECT  199.296 59.035 205.038 59.309 ;
     RECT  1.728 59.261 2.697 59.357 ;
     RECT  3.6 59.261 21.474 59.539 ;
     RECT  22.248 58.253 198.45 59.539 ;
     RECT  199.404 59.309 205.038 59.575 ;
     RECT  199.404 59.575 205.326 59.981 ;
     RECT  3.6 59.539 198.45 60.077 ;
     RECT  3.6 60.077 21.438 60.107 ;
     RECT  218.304 60.079 218.322 60.125 ;
     RECT  2.415 59.357 2.697 60.331 ;
     RECT  2.304 60.331 2.697 60.655 ;
     RECT  3.6 60.107 21.402 60.655 ;
     RECT  2.304 60.655 21.402 60.889 ;
     RECT  22.248 60.077 198.45 60.889 ;
     RECT  2.304 60.889 198.45 60.989 ;
     RECT  199.476 59.981 205.326 61.037 ;
     RECT  199.728 61.037 205.326 61.079 ;
     RECT  2.304 60.989 2.697 61.115 ;
     RECT  3.78 60.989 198.45 61.277 ;
     RECT  219.42 61.339 219.438 61.619 ;
     RECT  2.415 61.115 2.697 61.735 ;
     RECT  199.728 61.079 205.038 61.861 ;
     RECT  199.728 61.861 205.182 61.933 ;
     RECT  2.415 61.735 3.294 61.963 ;
     RECT  2.304 61.963 3.294 62.005 ;
     RECT  4.14 61.277 198.45 62.005 ;
     RECT  199.728 61.933 205.47 62.159 ;
     RECT  199.728 62.159 205.362 62.195 ;
     RECT  219.42 62.635 219.438 62.699 ;
     RECT  199.728 62.195 205.038 62.707 ;
     RECT  2.304 62.005 198.45 63.011 ;
     RECT  0.108 57.443 0.126 63.149 ;
     RECT  3.42 63.011 198.45 63.239 ;
     RECT  2.304 63.011 2.697 63.247 ;
     RECT  3.96 63.239 198.45 63.247 ;
     RECT  199.584 62.707 205.038 63.247 ;
     RECT  1.728 63.247 2.697 63.293 ;
     RECT  0.54 63.589 0.558 63.629 ;
     RECT  219.456 63.751 219.474 63.965 ;
     RECT  2.415 63.293 2.697 64.327 ;
     RECT  3.96 63.247 205.038 64.327 ;
     RECT  2.415 64.327 205.038 64.493 ;
     RECT  199.656 64.493 205.038 64.733 ;
     RECT  2.415 64.493 198.45 64.859 ;
     RECT  213.015 58.757 213.462 64.987 ;
     RECT  212.292 64.987 213.462 65.129 ;
     RECT  212.976 65.129 213.462 65.245 ;
     RECT  0.108 63.931 0.126 65.309 ;
     RECT  3.492 64.859 198.45 65.353 ;
     RECT  212.976 65.245 213.822 65.399 ;
     RECT  218.844 65.227 218.862 65.399 ;
     RECT  212.976 65.399 213.57 65.435 ;
     RECT  217.152 65.101 217.17 65.435 ;
     RECT  2.415 64.859 2.697 65.515 ;
     RECT  212.148 65.245 212.166 65.549 ;
     RECT  3.492 65.353 198.486 65.552 ;
     RECT  1.728 65.515 2.697 65.645 ;
     RECT  199.728 64.733 205.038 65.713 ;
     RECT  0.54 65.785 0.558 65.933 ;
     RECT  3.96 65.552 198.486 65.939 ;
     RECT  3.996 65.939 198.486 65.983 ;
     RECT  199.224 65.713 205.038 65.983 ;
     RECT  3.996 65.983 205.038 66.434 ;
     RECT  2.415 65.645 2.697 66.571 ;
     RECT  199.188 66.434 205.038 66.659 ;
     RECT  3.996 66.434 198.45 66.749 ;
     RECT  2.415 66.571 2.79 66.785 ;
     RECT  4.104 66.749 198.45 67.397 ;
     RECT  199.188 66.659 204.966 67.711 ;
     RECT  199.188 67.711 205.218 67.771 ;
     RECT  199.188 67.771 205.254 67.829 ;
     RECT  199.188 67.829 205.218 68.135 ;
     RECT  4.104 67.397 198.126 68.251 ;
     RECT  3.492 68.251 198.126 68.369 ;
     RECT  199.188 68.135 204.966 68.377 ;
     RECT  216.216 68.719 216.234 68.755 ;
     RECT  215.172 44.915 215.19 68.791 ;
     RECT  216.216 68.755 216.378 68.791 ;
     RECT  217.584 68.755 217.602 68.791 ;
     RECT  198.936 68.377 204.966 68.875 ;
     RECT  219.42 68.539 219.438 68.909 ;
     RECT  198.936 68.875 205.254 68.915 ;
     RECT  215.172 68.791 217.818 68.945 ;
     RECT  4.14 68.369 198.126 68.953 ;
     RECT  198.936 68.915 204.966 68.953 ;
     RECT  215.172 68.945 216.234 68.953 ;
     RECT  206.784 68.917 206.802 68.957 ;
     RECT  214.884 68.953 216.234 68.981 ;
     RECT  4.14 68.953 204.966 69.533 ;
     RECT  2.415 66.785 2.697 69.691 ;
     RECT  0.108 66.235 0.126 69.755 ;
     RECT  2.415 69.691 3.294 69.871 ;
     RECT  4.14 69.533 5.67 69.871 ;
     RECT  6.408 69.533 204.966 69.899 ;
     RECT  6.408 69.899 203.85 70.025 ;
     RECT  2.415 69.871 5.67 70.033 ;
     RECT  0.54 69.883 0.558 70.097 ;
     RECT  1.728 70.033 5.67 70.253 ;
     RECT  2.415 70.253 5.67 70.259 ;
     RECT  204.624 69.899 204.966 70.259 ;
     RECT  204.66 70.259 204.966 70.295 ;
     RECT  17.496 70.025 203.778 70.601 ;
     RECT  206.352 70.507 206.37 70.637 ;
     RECT  21.924 70.601 203.778 70.673 ;
     RECT  4.176 70.259 5.67 70.681 ;
     RECT  6.408 70.025 16.074 70.681 ;
     RECT  4.176 70.681 16.074 70.771 ;
     RECT  4.176 70.771 16.218 70.799 ;
     RECT  5.004 70.799 16.218 70.871 ;
     RECT  5.004 70.871 15.966 70.979 ;
     RECT  2.415 70.259 3.366 71.021 ;
     RECT  4.176 70.799 4.194 71.185 ;
     RECT  0.108 70.537 0.126 71.213 ;
     RECT  3.6 71.185 4.194 71.261 ;
     RECT  2.415 71.021 2.697 71.617 ;
     RECT  17.496 70.601 21.078 71.617 ;
     RECT  16.848 71.617 21.078 71.725 ;
     RECT  0.54 71.515 0.558 71.753 ;
     RECT  4.176 71.261 4.194 71.761 ;
     RECT  5.004 70.979 8.442 71.761 ;
     RECT  9.18 70.979 15.75 71.761 ;
     RECT  4.176 71.761 15.75 71.837 ;
     RECT  219.42 71.803 219.438 71.879 ;
     RECT  1.728 71.617 2.697 71.885 ;
     RECT  214.884 68.981 215.55 72.031 ;
     RECT  216.612 71.995 216.63 72.031 ;
     RECT  2.415 71.885 2.697 72.139 ;
     RECT  4.176 71.837 4.194 72.149 ;
     RECT  214.884 72.031 216.63 72.149 ;
     RECT  214.884 72.149 216.234 72.157 ;
     RECT  2.415 72.139 3.294 72.185 ;
     RECT  214.74 72.157 216.234 72.185 ;
     RECT  213.015 65.435 213.462 72.229 ;
     RECT  5.004 71.837 15.75 72.265 ;
     RECT  16.524 71.725 21.078 72.265 ;
     RECT  213.015 72.229 213.93 72.301 ;
     RECT  214.74 72.185 215.55 72.301 ;
     RECT  207.615 55.247 207.897 72.379 ;
     RECT  5.004 72.265 21.078 72.571 ;
     RECT  207.288 72.379 207.897 72.689 ;
     RECT  4.392 72.571 21.078 72.725 ;
     RECT  208.836 72.841 208.854 72.893 ;
     RECT  218.844 73.099 218.862 73.229 ;
     RECT  217.44 72.841 217.458 73.265 ;
     RECT  213.015 72.301 215.55 73.273 ;
     RECT  212.976 73.273 215.55 73.309 ;
     RECT  2.415 72.185 2.697 73.435 ;
     RECT  4.212 72.955 4.23 73.471 ;
     RECT  5.004 72.725 21.078 73.471 ;
     RECT  0.108 72.157 0.126 73.531 ;
     RECT  2.415 73.435 3.294 73.565 ;
     RECT  3.42 73.651 3.438 73.769 ;
     RECT  212.4 73.309 215.55 73.805 ;
     RECT  4.212 73.471 21.078 74.191 ;
     RECT  3.96 74.191 21.078 74.309 ;
     RECT  0.108 73.531 0.558 74.345 ;
     RECT  3.96 74.309 17.01 74.417 ;
     RECT  2.415 73.565 2.697 74.461 ;
     RECT  3.96 74.417 16.146 74.489 ;
     RECT  0.54 74.345 0.558 74.525 ;
     RECT  3.96 74.489 4.23 74.579 ;
     RECT  219.42 74.395 219.438 74.579 ;
     RECT  217.26 74.551 217.278 74.587 ;
     RECT  2.415 74.461 3.186 74.615 ;
     RECT  2.415 74.615 2.697 74.623 ;
     RECT  217.26 74.587 217.35 74.651 ;
     RECT  3.96 74.579 3.978 74.687 ;
     RECT  212.4 73.805 214.902 74.695 ;
     RECT  217.332 74.651 217.35 74.849 ;
     RECT  1.728 74.623 2.697 74.861 ;
     RECT  211.752 74.695 214.902 75.005 ;
     RECT  211.932 75.005 214.902 75.091 ;
     RECT  211.932 75.091 214.938 75.155 ;
     RECT  211.932 75.155 211.95 75.227 ;
     RECT  213.015 75.155 214.938 75.235 ;
     RECT  5.004 74.489 16.146 75.397 ;
     RECT  16.992 74.417 17.01 75.397 ;
     RECT  213.015 75.235 215.55 75.469 ;
     RECT  216.396 75.001 216.414 75.469 ;
     RECT  5.004 75.397 17.01 75.497 ;
     RECT  5.004 75.497 16.434 75.541 ;
     RECT  213.015 75.469 216.414 75.631 ;
     RECT  219.42 75.691 219.438 75.731 ;
     RECT  4.536 75.541 16.434 75.767 ;
     RECT  213.015 75.631 217.134 75.775 ;
     RECT  213.015 75.775 217.242 75.821 ;
     RECT  213.015 75.821 215.226 75.929 ;
     RECT  216.36 75.821 217.242 75.929 ;
     RECT  4.536 75.767 15.966 75.931 ;
     RECT  216.828 75.929 217.134 75.965 ;
     RECT  4.176 75.931 15.966 76.009 ;
     RECT  216.972 75.965 217.098 76.199 ;
     RECT  216.972 76.199 216.99 76.235 ;
     RECT  3.996 76.009 15.966 76.309 ;
     RECT  3.6 76.309 15.966 76.349 ;
     RECT  3.996 76.349 15.966 76.649 ;
     RECT  3.996 76.649 15.93 76.739 ;
     RECT  3.996 76.739 15.858 76.775 ;
     RECT  218.88 76.981 218.898 77.021 ;
     RECT  213.015 75.929 214.902 77.161 ;
     RECT  216.504 77.125 216.522 77.161 ;
     RECT  207.615 72.689 207.897 77.251 ;
     RECT  208.728 77.227 208.746 77.279 ;
     RECT  213.015 77.161 216.522 77.279 ;
     RECT  16.848 77.161 16.866 77.287 ;
     RECT  17.748 74.309 21.078 77.287 ;
     RECT  207.18 77.251 207.897 77.309 ;
     RECT  0.108 75.127 0.126 77.315 ;
     RECT  213.015 77.279 215.982 77.315 ;
     RECT  16.848 77.287 21.078 77.395 ;
     RECT  21.924 70.673 203.742 77.395 ;
     RECT  2.415 74.861 2.697 77.467 ;
     RECT  16.848 77.395 203.742 77.899 ;
     RECT  213.015 77.315 215.334 77.963 ;
     RECT  3.996 76.775 15.714 78.061 ;
     RECT  16.524 77.899 203.742 78.061 ;
     RECT  214.992 77.963 215.334 78.089 ;
     RECT  2.304 77.467 2.697 78.125 ;
     RECT  213.015 77.963 214.218 78.367 ;
     RECT  211.752 77.161 211.77 78.511 ;
     RECT  217.692 78.475 217.71 78.511 ;
     RECT  217.692 78.511 217.854 78.629 ;
     RECT  219.42 78.235 219.438 78.629 ;
     RECT  217.836 78.629 217.854 78.665 ;
     RECT  211.752 78.511 211.95 78.668 ;
     RECT  212.688 78.367 214.218 78.668 ;
     RECT  211.752 78.668 214.218 78.781 ;
     RECT  214.992 78.089 215.01 78.781 ;
     RECT  3.996 78.061 203.742 78.989 ;
     RECT  217.044 78.781 217.062 79.169 ;
     RECT  211.752 78.781 215.01 79.213 ;
     RECT  215.856 79.141 215.874 79.213 ;
     RECT  3.996 78.989 15.894 79.411 ;
     RECT  211.752 79.213 215.874 79.591 ;
     RECT  216.612 79.555 216.846 79.591 ;
     RECT  211.752 79.591 216.846 79.709 ;
     RECT  219.42 79.531 219.438 79.709 ;
     RECT  211.752 79.709 215.982 79.745 ;
     RECT  216.828 79.709 216.846 79.745 ;
     RECT  204.948 70.295 204.966 79.753 ;
     RECT  204.948 79.753 205.29 79.781 ;
     RECT  3.816 79.411 15.894 79.819 ;
     RECT  3.456 79.819 15.894 79.861 ;
     RECT  211.752 79.745 215.406 80.087 ;
     RECT  212.904 80.087 215.406 80.123 ;
     RECT  3.456 79.861 16.11 80.189 ;
     RECT  211.752 80.087 212.13 80.189 ;
     RECT  3.924 80.189 16.11 80.401 ;
     RECT  16.848 78.989 203.742 80.401 ;
     RECT  213.015 80.123 215.406 80.669 ;
     RECT  214.992 80.669 215.406 80.671 ;
     RECT  217.116 80.635 217.134 80.671 ;
     RECT  213.015 80.669 214.038 80.699 ;
     RECT  214.992 80.671 217.314 80.699 ;
     RECT  2.415 78.125 2.697 80.779 ;
     RECT  3.924 80.401 203.742 80.825 ;
     RECT  215.748 80.699 217.314 80.825 ;
     RECT  219.42 80.824 219.438 80.861 ;
     RECT  2.415 80.779 2.754 81.019 ;
     RECT  3.96 80.825 203.742 81.053 ;
     RECT  216.144 80.825 216.342 81.059 ;
     RECT  216.144 81.059 216.162 81.095 ;
     RECT  4.068 81.053 203.742 81.329 ;
     RECT  2.415 81.019 2.79 81.409 ;
     RECT  2.376 81.409 2.79 81.481 ;
     RECT  2.376 81.481 2.862 81.607 ;
     RECT  2.304 81.607 2.862 81.635 ;
     RECT  2.304 81.635 2.697 81.779 ;
     RECT  218.88 82.111 218.898 82.157 ;
     RECT  217.8 82.111 217.818 82.211 ;
     RECT  4.068 81.329 11.97 82.219 ;
     RECT  12.708 81.329 203.742 82.219 ;
     RECT  4.068 82.219 203.742 82.255 ;
     RECT  214.992 80.699 215.01 82.255 ;
     RECT  213.015 80.699 213.966 82.267 ;
     RECT  214.74 82.255 215.01 82.267 ;
     RECT  4.032 82.255 203.742 82.283 ;
     RECT  213.015 82.267 215.01 82.291 ;
     RECT  216.252 82.255 216.27 82.291 ;
     RECT  213.015 82.291 216.27 82.409 ;
     RECT  213.015 82.409 215.658 82.445 ;
     RECT  213.015 82.445 215.334 82.823 ;
     RECT  2.415 81.779 2.697 82.831 ;
     RECT  213.015 82.823 214.074 82.877 ;
     RECT  2.415 82.831 3.078 82.949 ;
     RECT  214.992 82.823 215.334 83.021 ;
     RECT  4.032 82.283 13.497 83.065 ;
     RECT  14.22 82.283 203.742 83.065 ;
     RECT  2.415 82.949 2.697 83.083 ;
     RECT  2.304 83.083 2.697 83.255 ;
     RECT  219.42 83.419 219.438 83.489 ;
     RECT  214.992 83.021 215.262 83.561 ;
     RECT  211.752 80.189 211.77 83.707 ;
     RECT  211.716 83.707 211.77 83.755 ;
     RECT  214.992 83.561 215.19 83.759 ;
     RECT  211.644 83.755 211.77 83.803 ;
     RECT  213.015 82.877 213.966 83.803 ;
     RECT  211.644 83.803 213.966 83.851 ;
     RECT  211.284 83.851 213.966 83.875 ;
     RECT  211.284 83.875 214.074 83.911 ;
     RECT  214.992 83.759 215.01 83.911 ;
     RECT  4.032 83.065 203.742 83.995 ;
     RECT  211.284 83.911 215.01 84.029 ;
     RECT  214.776 84.029 215.01 84.065 ;
     RECT  0.108 78.139 0.126 84.091 ;
     RECT  2.415 83.255 2.697 84.145 ;
     RECT  0.108 84.091 0.558 84.173 ;
     RECT  2.415 84.145 2.754 84.271 ;
     RECT  3.564 83.995 203.742 84.271 ;
     RECT  211.284 84.029 213.966 84.299 ;
     RECT  214.992 84.065 215.01 84.811 ;
     RECT  219.42 84.715 219.438 84.839 ;
     RECT  214.992 84.811 215.334 84.991 ;
     RECT  216.72 84.955 216.738 84.991 ;
     RECT  214.992 84.991 215.55 85.109 ;
     RECT  216.504 84.991 216.738 85.109 ;
     RECT  214.992 85.109 215.334 85.145 ;
     RECT  216.504 85.109 216.522 85.145 ;
     RECT  211.716 84.299 213.966 85.181 ;
     RECT  2.415 84.271 203.742 85.379 ;
     RECT  211.752 85.181 211.878 85.379 ;
     RECT  212.688 85.181 213.966 85.379 ;
     RECT  213.015 85.379 213.966 85.459 ;
     RECT  214.992 85.145 215.01 85.459 ;
     RECT  216.432 85.801 216.45 85.999 ;
     RECT  213.015 85.459 215.01 86.011 ;
     RECT  215.784 85.999 216.45 86.011 ;
     RECT  213.015 86.011 216.45 86.161 ;
     RECT  219.42 86.011 219.438 86.189 ;
     RECT  217.8 86.161 217.818 86.261 ;
     RECT  213.015 86.161 216.738 86.305 ;
     RECT  2.415 85.379 3.078 86.341 ;
     RECT  4.032 85.379 203.742 86.341 ;
     RECT  213.015 86.305 216.81 86.459 ;
     RECT  213.015 86.459 216.738 86.495 ;
     RECT  216.504 86.495 216.666 86.729 ;
     RECT  216.504 86.729 216.522 86.765 ;
     RECT  0.108 84.173 0.126 87.019 ;
     RECT  0.108 87.019 0.162 87.107 ;
     RECT  213.015 86.495 215.334 87.269 ;
     RECT  214.848 87.269 215.334 87.305 ;
     RECT  219.42 87.259 219.438 87.305 ;
     RECT  217.8 87.241 217.818 87.341 ;
     RECT  213.015 87.269 214.038 87.389 ;
     RECT  214.92 87.305 215.334 87.421 ;
     RECT  216.252 87.385 216.27 87.421 ;
     RECT  2.415 86.341 203.742 87.485 ;
     RECT  213.015 87.389 213.894 87.539 ;
     RECT  214.92 87.421 216.27 87.539 ;
     RECT  214.92 87.539 215.334 87.575 ;
     RECT  216.108 87.539 216.126 87.575 ;
     RECT  2.415 87.485 2.754 87.691 ;
     RECT  213.015 87.539 213.75 87.787 ;
     RECT  2.412 87.691 2.754 87.845 ;
     RECT  2.415 87.845 2.754 88.231 ;
     RECT  3.492 87.485 203.742 88.231 ;
     RECT  2.415 88.231 203.742 88.301 ;
     RECT  212.652 87.787 213.75 88.355 ;
     RECT  213.015 88.355 213.75 88.501 ;
     RECT  214.92 87.575 214.938 88.501 ;
     RECT  219.42 88.555 219.438 88.619 ;
     RECT  217.8 88.591 217.818 88.691 ;
     RECT  0.108 87.107 0.126 88.693 ;
     RECT  0.108 88.693 0.558 88.733 ;
     RECT  213.015 88.501 214.938 88.735 ;
     RECT  213.015 88.735 215.622 88.889 ;
     RECT  213.015 88.889 215.046 88.925 ;
     RECT  2.415 88.301 2.898 89.401 ;
     RECT  3.672 88.301 203.742 89.401 ;
     RECT  213.015 88.925 214.938 89.453 ;
     RECT  211.752 85.379 211.77 89.779 ;
     RECT  213.015 89.453 213.822 89.779 ;
     RECT  214.92 89.453 214.938 89.779 ;
     RECT  214.92 89.779 215.334 89.851 ;
     RECT  214.92 89.851 215.55 89.879 ;
     RECT  219.42 89.851 219.438 89.969 ;
     RECT  214.992 89.879 215.55 90.005 ;
     RECT  2.415 89.401 203.742 90.275 ;
     RECT  211.752 89.779 213.822 90.391 ;
     RECT  211.752 90.391 213.966 90.581 ;
     RECT  211.752 90.581 211.842 90.605 ;
     RECT  214.992 90.005 215.298 90.625 ;
     RECT  214.884 90.625 215.298 90.653 ;
     RECT  0.108 88.733 0.126 90.895 ;
     RECT  213.015 90.581 213.966 91.003 ;
     RECT  214.884 90.653 215.226 91.003 ;
     RECT  0.108 90.895 0.558 91.037 ;
     RECT  217.188 91.021 217.206 91.165 ;
     RECT  216.612 91.165 217.206 91.201 ;
     RECT  215.964 91.201 217.206 91.319 ;
     RECT  219.42 91.147 219.438 91.319 ;
     RECT  215.964 91.319 215.982 91.355 ;
     RECT  216.72 91.319 217.206 91.355 ;
     RECT  2.415 90.275 2.697 91.435 ;
     RECT  3.456 90.275 203.742 91.435 ;
     RECT  213.015 91.003 215.226 91.471 ;
     RECT  213.015 91.471 215.55 91.733 ;
     RECT  213.015 91.733 215.046 92.281 ;
     RECT  2.415 91.435 203.742 92.299 ;
     RECT  2.304 92.299 203.742 92.507 ;
     RECT  212.832 92.281 215.046 92.551 ;
     RECT  211.752 90.605 211.77 92.635 ;
     RECT  219.42 92.443 219.438 92.669 ;
     RECT  211.752 92.635 212.022 92.675 ;
     RECT  211.752 92.675 211.77 92.776 ;
     RECT  216.072 92.749 216.09 92.785 ;
     RECT  211.644 92.776 211.77 92.813 ;
     RECT  212.832 92.551 215.262 92.821 ;
     RECT  216.072 92.785 216.306 92.821 ;
     RECT  212.832 92.821 216.306 92.939 ;
     RECT  212.832 92.939 216.09 92.975 ;
     RECT  212.832 92.975 215.73 93.209 ;
     RECT  212.832 93.209 215.55 93.211 ;
     RECT  212.688 93.211 215.55 93.245 ;
     RECT  212.688 93.245 214.902 93.479 ;
     RECT  211.752 92.813 211.77 93.691 ;
     RECT  212.688 93.479 214.614 93.691 ;
     RECT  218.304 93.721 218.322 93.773 ;
     RECT  211.752 93.691 214.614 94.411 ;
     RECT  211.752 94.411 215.118 94.531 ;
     RECT  211.752 94.531 215.442 94.559 ;
     RECT  215.424 94.559 215.442 94.589 ;
     RECT  211.752 94.559 214.218 94.595 ;
     RECT  2.415 92.507 203.742 94.603 ;
     RECT  1.728 94.603 203.742 94.685 ;
     RECT  211.752 94.595 213.858 94.829 ;
     RECT  2.415 94.685 203.742 94.865 ;
     RECT  216.828 94.945 216.846 94.981 ;
     RECT  216.828 94.981 217.062 95.099 ;
     RECT  219.42 95.035 219.438 95.099 ;
     RECT  217.044 95.099 217.062 95.135 ;
     RECT  211.752 94.829 213.822 95.405 ;
     RECT  212.94 95.405 213.822 95.441 ;
     RECT  211.752 95.405 211.986 95.501 ;
     RECT  213.015 95.441 213.822 95.755 ;
     RECT  213.015 95.755 214.434 95.791 ;
     RECT  2.415 94.865 2.697 95.899 ;
     RECT  3.456 94.865 203.742 95.899 ;
     RECT  213.015 95.791 214.83 95.989 ;
     RECT  213.015 95.989 215.334 96.025 ;
     RECT  0.108 91.037 0.126 96.323 ;
     RECT  213.015 96.025 215.694 96.421 ;
     RECT  212.976 96.421 215.694 96.449 ;
     RECT  219.42 96.331 219.438 96.449 ;
     RECT  217.8 96.421 217.818 96.521 ;
     RECT  215.316 96.449 215.694 96.529 ;
     RECT  212.976 96.449 214.578 96.601 ;
     RECT  212.688 96.601 214.578 96.629 ;
     RECT  217.332 96.565 217.35 96.719 ;
     RECT  0.54 96.619 0.558 96.827 ;
     RECT  2.415 95.899 203.742 96.835 ;
     RECT  212.688 96.629 214.038 96.845 ;
     RECT  1.728 96.835 203.742 96.989 ;
     RECT  213.015 96.845 214.038 97.411 ;
     RECT  215.316 96.529 216.09 97.411 ;
     RECT  2.304 96.989 203.742 97.565 ;
     RECT  213.015 97.411 216.09 97.565 ;
     RECT  218.88 97.573 218.898 97.613 ;
     RECT  215.316 97.565 216.09 97.645 ;
     RECT  213.015 97.565 214.578 97.799 ;
     RECT  215.316 97.645 216.198 97.799 ;
     RECT  215.316 97.799 215.874 97.835 ;
     RECT  0.54 97.579 0.558 97.915 ;
     RECT  213.015 97.799 214.542 97.943 ;
     RECT  0.108 97.915 0.558 97.952 ;
     RECT  2.415 97.565 203.742 98.069 ;
     RECT  0.54 97.952 0.558 98.483 ;
     RECT  213.015 97.943 214.182 98.491 ;
     RECT  3.456 98.069 203.742 98.55 ;
     RECT  2.415 98.069 2.697 98.587 ;
     RECT  211.752 95.501 211.77 98.617 ;
     RECT  213.012 98.491 214.182 98.617 ;
     RECT  215.388 97.835 215.406 98.617 ;
     RECT  2.412 98.587 2.697 98.645 ;
     RECT  215.388 98.617 215.622 98.645 ;
     RECT  2.415 98.645 2.697 98.827 ;
     RECT  3.456 98.55 23.238 98.827 ;
     RECT  218.304 98.851 218.322 98.909 ;
     RECT  211.752 98.617 214.182 98.957 ;
     RECT  212.616 98.957 214.182 98.995 ;
     RECT  212.616 98.995 214.434 99.149 ;
     RECT  212.616 99.149 214.29 99.185 ;
     RECT  0.108 98.887 0.126 99.259 ;
     RECT  69.516 98.55 69.534 99.463 ;
     RECT  68.652 98.55 68.67 99.499 ;
     RECT  69.516 99.463 70.182 99.499 ;
     RECT  0.108 99.259 0.558 99.527 ;
     RECT  212.832 99.185 213.786 99.563 ;
     RECT  103.176 99.499 103.194 99.571 ;
     RECT  197.64 98.55 203.742 99.599 ;
     RECT  25.452 98.55 25.614 99.616 ;
     RECT  26.352 98.55 26.37 99.616 ;
     RECT  0.108 99.527 0.126 99.629 ;
     RECT  2.415 98.827 23.238 99.733 ;
     RECT  46.656 99.499 46.674 99.841 ;
     RECT  96.912 98.55 96.93 99.931 ;
     RECT  211.752 98.957 211.77 99.931 ;
     RECT  2.268 99.733 23.238 99.965 ;
     RECT  171.684 99.733 171.702 99.967 ;
     RECT  71.244 98.55 71.802 100.003 ;
     RECT  79.2 98.55 79.218 100.003 ;
     RECT  201.348 99.599 203.742 100.031 ;
     RECT  66.888 98.55 66.906 100.039 ;
     RECT  67.86 99.643 67.878 100.039 ;
     RECT  211.752 99.931 212.058 100.039 ;
     RECT  212.832 99.563 213.75 100.039 ;
     RECT  46.656 99.841 47.034 100.075 ;
     RECT  211.752 100.039 213.75 100.075 ;
     RECT  203.22 100.031 203.742 100.103 ;
     RECT  216.468 100.075 216.486 100.111 ;
     RECT  211.608 100.075 213.75 100.112 ;
     RECT  50.184 98.55 50.202 100.156 ;
     RECT  51.156 99.733 51.174 100.156 ;
     RECT  85.176 98.55 85.626 100.156 ;
     RECT  66.888 100.039 67.878 100.201 ;
     RECT  216.468 100.111 216.594 100.229 ;
     RECT  219.42 100.171 219.438 100.229 ;
     RECT  57.6 98.55 57.618 100.237 ;
     RECT  115.704 99.979 115.722 100.237 ;
     RECT  214.776 99.931 214.794 100.265 ;
     RECT  216.576 100.229 216.594 100.265 ;
     RECT  111.096 100.201 111.114 100.267 ;
     RECT  157.608 99.403 157.626 100.273 ;
     RECT  201.348 100.031 202.497 100.301 ;
     RECT  212.04 100.112 213.75 100.315 ;
     RECT  36.036 100.273 36.054 100.345 ;
     RECT  57.6 100.237 57.87 100.381 ;
     RECT  82.872 99.547 82.89 100.381 ;
     RECT  40.572 100.156 40.59 100.426 ;
     RECT  44.136 100.273 44.154 100.471 ;
     RECT  63.252 100.345 63.27 100.471 ;
     RECT  80.316 98.55 80.334 100.507 ;
     RECT  212.04 100.315 213.822 100.507 ;
     RECT  96.444 99.931 96.93 100.535 ;
     RECT  54.72 100.471 54.738 100.543 ;
     RECT  62.568 100.471 63.27 100.543 ;
     RECT  94.896 99.661 94.914 100.543 ;
     RECT  99.972 100.201 99.99 100.543 ;
     RECT  103.176 99.571 103.446 100.555 ;
     RECT  104.292 100.156 104.31 100.555 ;
     RECT  62.496 100.543 63.27 100.571 ;
     RECT  94.752 100.543 94.914 100.579 ;
     RECT  212.04 100.507 213.93 100.579 ;
     RECT  153.972 99.661 153.99 100.603 ;
     RECT  27.288 99.931 27.306 100.615 ;
     RECT  40.572 100.426 40.842 100.615 ;
     RECT  43.884 100.471 44.154 100.615 ;
     RECT  46.656 100.075 47.07 100.615 ;
     RECT  89.712 100.507 89.73 100.615 ;
     RECT  91.764 100.075 91.782 100.615 ;
     RECT  62.496 100.571 62.514 100.643 ;
     RECT  212.04 100.579 214.326 100.643 ;
     RECT  58.932 100.615 58.95 100.651 ;
     RECT  75.744 99.595 75.762 100.651 ;
     RECT  24.516 100.201 24.534 100.693 ;
     RECT  30.132 99.571 30.15 100.693 ;
     RECT  34.488 99.967 34.506 100.693 ;
     RECT  45.54 99.697 45.558 100.693 ;
     RECT  50.184 100.156 51.174 100.693 ;
     RECT  56.952 100.381 57.87 100.693 ;
     RECT  72.612 99.535 72.63 100.693 ;
     RECT  78.012 100.027 78.03 100.693 ;
     RECT  82.62 100.381 82.89 100.693 ;
     RECT  83.808 98.55 84.366 100.693 ;
     RECT  88.596 100.579 88.614 100.693 ;
     RECT  89.712 100.615 90.126 100.693 ;
     RECT  110.844 100.267 111.114 100.693 ;
     RECT  115.704 100.237 115.974 100.693 ;
     RECT  127.368 99.451 127.386 100.693 ;
     RECT  153.972 100.603 154.314 100.693 ;
     RECT  197.64 99.599 200.61 100.693 ;
     RECT  2.304 99.965 23.238 100.741 ;
     RECT  24.207 100.693 24.534 100.741 ;
     RECT  34.488 100.693 35.097 100.741 ;
     RECT  36.036 100.345 36.306 100.741 ;
     RECT  45.54 100.693 45.897 100.741 ;
     RECT  56.607 100.693 57.87 100.741 ;
     RECT  71.244 100.003 71.874 100.741 ;
     RECT  74.736 100.651 74.754 100.741 ;
     RECT  115.704 100.693 116.097 100.741 ;
     RECT  25.452 99.616 26.37 100.747 ;
     RECT  27.288 100.615 27.342 100.747 ;
     RECT  28.188 100.741 28.206 100.747 ;
     RECT  60.912 100.615 60.93 100.747 ;
     RECT  61.956 100.651 62.478 100.747 ;
     RECT  72.612 100.693 72.897 100.747 ;
     RECT  74.556 100.741 74.754 100.747 ;
     RECT  58.932 100.651 59.274 100.769 ;
     RECT  85.176 100.156 85.914 100.769 ;
     RECT  87.012 98.55 87.03 100.769 ;
     RECT  88.596 100.693 90.126 100.769 ;
     RECT  91.224 100.615 91.782 100.769 ;
     RECT  93.168 100.273 93.186 100.769 ;
     RECT  98.028 99.535 98.046 100.769 ;
     RECT  98.784 100.111 98.802 100.769 ;
     RECT  99.756 100.543 99.99 100.769 ;
     RECT  101.088 100.507 101.106 100.769 ;
     RECT  103.176 100.555 104.31 100.769 ;
     RECT  110.607 100.693 111.114 100.769 ;
     RECT  117.252 100.555 117.27 100.769 ;
     RECT  153.807 100.693 154.314 100.769 ;
     RECT  157.608 100.273 157.878 100.769 ;
     RECT  171.684 99.967 171.954 100.769 ;
     RECT  212.04 100.643 212.274 100.769 ;
     RECT  37.98 100.747 37.998 100.777 ;
     RECT  54.72 100.543 54.81 100.777 ;
     RECT  58.932 100.769 58.95 100.777 ;
     RECT  74.484 100.747 74.754 100.777 ;
     RECT  75.672 100.651 75.762 100.777 ;
     RECT  80.172 100.507 80.334 100.777 ;
     RECT  194.364 100.603 194.382 100.781 ;
     RECT  43.02 100.111 43.038 100.795 ;
     RECT  43.812 100.615 44.154 100.795 ;
     RECT  46.656 100.615 47.322 100.795 ;
     RECT  94.284 100.579 94.914 100.795 ;
     RECT  103.176 100.769 103.194 100.805 ;
     RECT  110.607 100.769 110.862 100.805 ;
     RECT  157.608 100.769 157.626 100.805 ;
     RECT  171.684 100.769 171.702 100.805 ;
     RECT  2.304 100.741 24.534 100.813 ;
     RECT  37.98 100.777 38.718 100.813 ;
     RECT  53.568 100.741 53.586 100.813 ;
     RECT  74.484 100.777 75.762 100.813 ;
     RECT  76.86 100.039 76.878 100.813 ;
     RECT  80.172 100.777 80.73 100.813 ;
     RECT  81.504 100.426 81.522 100.813 ;
     RECT  115.704 100.741 116.154 100.829 ;
     RECT  25.452 100.747 27.342 100.84 ;
     RECT  28.152 100.747 28.206 100.84 ;
     RECT  96.444 100.535 96.894 100.84 ;
     RECT  115.704 100.829 116.097 100.84 ;
     RECT  94.284 100.795 95.022 100.841 ;
     RECT  212.256 100.769 212.274 100.841 ;
     RECT  37.98 100.813 38.862 100.843 ;
     RECT  56.556 100.741 57.87 100.843 ;
     RECT  73.728 98.55 73.746 100.843 ;
     RECT  74.484 100.813 76.878 100.843 ;
     RECT  29.607 100.693 30.15 100.849 ;
     RECT  30.888 100.741 31.338 100.849 ;
     RECT  78.012 100.693 78.297 100.849 ;
     RECT  96.192 100.84 96.894 100.877 ;
     RECT  115.524 100.84 116.097 100.877 ;
     RECT  118.548 100.747 118.566 100.877 ;
     RECT  37.872 100.843 38.862 100.885 ;
     RECT  39.996 100.615 40.842 100.885 ;
     RECT  41.652 100.849 41.994 100.885 ;
     RECT  43.02 100.795 44.154 100.885 ;
     RECT  45.36 100.741 45.897 100.885 ;
     RECT  50.184 100.693 51.297 100.885 ;
     RECT  52.776 100.651 52.794 100.885 ;
     RECT  53.568 100.813 53.658 100.885 ;
     RECT  54.72 100.777 54.846 100.885 ;
     RECT  60.012 99.463 60.03 100.885 ;
     RECT  60.912 100.747 62.478 100.885 ;
     RECT  66.564 100.201 67.878 100.885 ;
     RECT  68.652 99.499 70.182 100.885 ;
     RECT  73.728 100.843 76.878 100.885 ;
     RECT  77.652 100.849 78.297 100.885 ;
     RECT  80.172 100.813 81.522 100.885 ;
     RECT  82.62 100.693 84.366 100.885 ;
     RECT  85.176 100.769 85.662 100.885 ;
     RECT  29.607 100.849 31.338 100.891 ;
     RECT  37.692 100.885 42.102 100.891 ;
     RECT  48.852 100.885 48.87 100.891 ;
     RECT  73.728 100.885 78.297 100.891 ;
     RECT  79.128 100.003 79.218 100.891 ;
     RECT  80.1 100.885 81.522 100.891 ;
     RECT  25.452 100.84 28.206 100.921 ;
     RECT  29.268 100.891 31.338 100.921 ;
     RECT  33.084 100.891 33.102 100.921 ;
     RECT  34.488 100.741 36.306 100.921 ;
     RECT  37.224 100.891 42.21 100.921 ;
     RECT  52.776 100.885 54.918 100.921 ;
     RECT  56.556 100.843 57.978 100.921 ;
     RECT  58.788 100.777 58.95 100.921 ;
     RECT  56.556 100.921 58.95 100.963 ;
     RECT  94.284 100.841 94.914 100.963 ;
     RECT  99.756 100.769 99.897 100.963 ;
     RECT  105.207 100.693 105.297 100.963 ;
     RECT  110.607 100.805 110.754 100.963 ;
     RECT  121.407 100.693 121.497 100.963 ;
     RECT  126.807 100.693 127.386 100.963 ;
     RECT  132.207 100.693 132.297 100.963 ;
     RECT  137.607 100.693 137.697 100.963 ;
     RECT  143.007 100.693 143.097 100.963 ;
     RECT  148.407 100.693 148.497 100.963 ;
     RECT  153.807 100.769 153.897 100.963 ;
     RECT  159.207 100.693 159.297 100.963 ;
     RECT  164.607 100.693 164.697 100.963 ;
     RECT  170.007 100.693 170.097 100.963 ;
     RECT  175.407 100.693 175.497 100.963 ;
     RECT  180.807 100.693 180.897 100.963 ;
     RECT  186.207 100.693 186.297 100.963 ;
     RECT  191.607 100.693 191.697 100.963 ;
     RECT  197.007 100.693 200.61 100.963 ;
     RECT  50.184 100.885 51.534 101.011 ;
     RECT  52.776 100.921 54.954 101.011 ;
     RECT  66.564 100.885 70.182 101.011 ;
     RECT  71.172 100.741 71.874 101.011 ;
     RECT  72.612 100.747 72.99 101.011 ;
     RECT  73.728 100.891 79.218 101.011 ;
     RECT  80.1 100.891 81.846 101.011 ;
     RECT  91.764 100.769 91.782 101.011 ;
     RECT  114.408 100.741 114.426 101.011 ;
     RECT  2.304 100.813 24.678 101.035 ;
     RECT  25.452 100.921 31.338 101.035 ;
     RECT  48.852 100.891 48.978 101.035 ;
     RECT  63.252 100.571 63.27 101.035 ;
     RECT  60.012 100.885 62.478 101.039 ;
     RECT  117.396 100.891 117.414 101.039 ;
     RECT  34.488 100.921 42.21 101.047 ;
     RECT  46.656 100.795 47.79 101.047 ;
     RECT  48.852 101.035 49.122 101.047 ;
     RECT  114.408 101.011 114.606 101.069 ;
     RECT  0.108 100.555 0.126 101.075 ;
     RECT  56.415 100.963 58.95 101.075 ;
     RECT  196.815 100.963 200.61 101.075 ;
     RECT  113.472 101.011 113.49 101.117 ;
     RECT  34.272 101.047 42.21 101.119 ;
     RECT  43.02 100.885 45.897 101.119 ;
     RECT  46.656 101.047 49.122 101.119 ;
     RECT  66.564 101.011 71.874 101.119 ;
     RECT  72.612 101.011 81.846 101.119 ;
     RECT  94.215 100.963 94.914 101.119 ;
     RECT  34.272 101.119 45.897 101.131 ;
     RECT  46.62 101.119 49.23 101.131 ;
     RECT  63.252 101.035 63.99 101.131 ;
     RECT  114.408 101.069 114.57 101.131 ;
     RECT  91.764 101.011 91.854 101.147 ;
     RECT  32.724 100.921 33.174 101.155 ;
     RECT  50.184 101.011 55.278 101.155 ;
     RECT  60.012 101.039 62.226 101.155 ;
     RECT  66.564 101.119 81.846 101.155 ;
     RECT  82.62 100.885 85.662 101.155 ;
     RECT  213.015 100.643 214.326 101.155 ;
     RECT  200.484 101.075 200.61 101.183 ;
     RECT  2.304 101.035 31.338 101.191 ;
     RECT  32.148 101.155 33.174 101.191 ;
     RECT  34.272 101.131 49.23 101.191 ;
     RECT  213.015 101.155 214.578 101.191 ;
     RECT  215.604 98.645 215.622 101.191 ;
     RECT  96.768 100.877 96.894 101.219 ;
     RECT  56.415 101.075 58.23 101.309 ;
     RECT  93.888 101.119 94.914 101.309 ;
     RECT  110.415 100.963 110.754 101.309 ;
     RECT  114.228 101.131 114.57 101.309 ;
     RECT  56.415 101.309 57.834 101.317 ;
     RECT  56.34 101.317 57.834 101.323 ;
     RECT  114.228 101.309 114.498 101.345 ;
     RECT  2.304 101.191 31.41 101.353 ;
     RECT  32.148 101.191 49.23 101.353 ;
     RECT  64.98 101.323 64.998 101.353 ;
     RECT  96.876 101.219 96.894 101.357 ;
     RECT  114.48 101.345 114.498 101.357 ;
     RECT  196.815 101.075 199.386 101.381 ;
     RECT  92.916 101.281 92.934 101.417 ;
     RECT  93.996 101.309 94.914 101.417 ;
     RECT  2.304 101.353 49.23 101.425 ;
     RECT  50.184 101.155 55.458 101.425 ;
     RECT  63.252 101.131 64.098 101.425 ;
     RECT  64.98 101.353 65.646 101.425 ;
     RECT  66.564 101.155 85.662 101.425 ;
     RECT  213.015 101.191 216.342 101.425 ;
     RECT  63.252 101.425 85.662 101.453 ;
     RECT  2.304 101.425 55.458 101.461 ;
     RECT  56.268 101.323 57.834 101.461 ;
     RECT  200.484 101.183 200.502 101.579 ;
     RECT  86.508 100.885 86.814 101.587 ;
     RECT  91.836 101.147 91.854 101.587 ;
     RECT  2.304 101.461 57.834 101.615 ;
     RECT  88.815 100.769 89.097 101.623 ;
     RECT  59.976 101.155 62.226 101.659 ;
     RECT  2.376 101.615 57.834 101.687 ;
     RECT  91.836 101.587 91.998 101.687 ;
     RECT  203.22 100.103 203.238 101.687 ;
     RECT  59.94 101.659 62.226 101.695 ;
     RECT  201.528 100.301 202.497 101.723 ;
     RECT  213.015 101.425 216.486 101.723 ;
     RECT  59.004 101.695 59.022 101.731 ;
     RECT  59.832 101.695 62.226 101.731 ;
     RECT  217.692 101.695 217.71 101.731 ;
     RECT  196.815 101.381 199.35 101.741 ;
     RECT  91.836 101.687 91.926 101.759 ;
     RECT  213.015 101.723 215.982 101.759 ;
     RECT  75.816 101.453 85.662 101.821 ;
     RECT  75.816 101.821 85.734 101.849 ;
     RECT  216.936 101.731 217.962 101.849 ;
     RECT  219.42 101.467 219.438 101.849 ;
     RECT  86.508 101.587 87.066 101.857 ;
     RECT  88.815 101.623 89.154 101.857 ;
     RECT  63.252 101.453 74.97 101.885 ;
     RECT  216.936 101.849 217.206 101.885 ;
     RECT  217.944 101.849 217.962 101.885 ;
     RECT  59.004 101.731 62.226 101.893 ;
     RECT  63.252 101.885 74.898 101.893 ;
     RECT  86.508 101.857 87.642 101.893 ;
     RECT  88.452 101.857 89.154 101.893 ;
     RECT  215.604 101.759 215.982 101.921 ;
     RECT  59.004 101.893 74.898 102.029 ;
     RECT  59.004 102.029 74.862 102.091 ;
     RECT  80.064 101.849 85.734 102.091 ;
     RECT  86.508 101.893 89.154 102.091 ;
     RECT  91.368 102.091 91.386 102.127 ;
     RECT  42.156 101.687 57.834 102.139 ;
     RECT  58.788 102.091 74.862 102.139 ;
     RECT  75.816 101.849 79.254 102.271 ;
     RECT  80.064 102.091 89.154 102.271 ;
     RECT  90.648 102.127 91.386 102.271 ;
     RECT  80.064 102.271 89.838 102.397 ;
     RECT  90.576 102.271 91.386 102.397 ;
     RECT  2.376 101.687 41.382 102.469 ;
     RECT  42.156 102.139 74.862 102.469 ;
     RECT  213.015 101.759 214.578 102.505 ;
     RECT  75.744 102.271 79.254 102.667 ;
     RECT  80.064 102.397 91.386 102.667 ;
     RECT  75.744 102.667 91.386 102.703 ;
     RECT  92.124 102.631 92.178 102.703 ;
     RECT  75.744 102.703 92.178 102.715 ;
     RECT  93.168 102.619 93.186 102.715 ;
     RECT  213.015 102.505 214.794 102.803 ;
     RECT  2.376 102.469 74.862 102.811 ;
     RECT  75.744 102.715 93.186 102.811 ;
     RECT  214.776 102.803 214.794 102.811 ;
     RECT  215.712 102.775 215.73 102.811 ;
     RECT  219.42 102.763 219.438 102.929 ;
     RECT  214.776 102.811 215.91 102.965 ;
     RECT  198.252 101.741 199.35 103.073 ;
     RECT  198.828 103.073 199.35 103.109 ;
     RECT  2.376 102.811 93.186 103.207 ;
     RECT  94.215 101.417 94.914 103.207 ;
     RECT  199.332 103.109 199.35 103.229 ;
     RECT  142.815 100.963 143.097 103.441 ;
     RECT  2.376 103.207 94.914 103.477 ;
     RECT  96.156 103.351 96.174 103.477 ;
     RECT  142.815 103.441 143.766 103.517 ;
     RECT  2.376 103.477 96.498 103.579 ;
     RECT  2.268 103.579 96.498 103.621 ;
     RECT  2.268 103.621 96.894 103.711 ;
     RECT  213.015 102.803 213.93 103.723 ;
     RECT  2.268 103.711 97.002 103.783 ;
     RECT  2.268 103.783 97.578 103.883 ;
     RECT  212.4 103.723 213.93 103.981 ;
     RECT  214.776 102.965 214.794 103.981 ;
     RECT  217.8 103.981 217.818 104.081 ;
     RECT  218.88 104.053 218.898 104.093 ;
     RECT  212.4 103.981 214.794 104.125 ;
     RECT  2.415 103.883 97.578 104.161 ;
     RECT  126.615 100.963 127.386 104.161 ;
     RECT  99.615 100.963 99.897 104.251 ;
     RECT  212.4 104.125 215.514 104.279 ;
     RECT  212.4 104.279 214.362 104.315 ;
     RECT  215.1 104.279 215.118 104.315 ;
     RECT  98.676 104.125 98.694 104.347 ;
     RECT  98.676 104.347 98.838 104.395 ;
     RECT  99.615 104.251 100.494 104.395 ;
     RECT  102.78 104.359 102.798 104.395 ;
     RECT  101.88 104.389 101.898 104.429 ;
     RECT  2.415 104.161 97.938 104.431 ;
     RECT  98.676 104.395 100.494 104.431 ;
     RECT  102.744 104.395 102.798 104.431 ;
     RECT  212.4 104.315 214.074 104.539 ;
     RECT  212.184 104.539 214.074 104.585 ;
     RECT  2.415 104.431 100.494 104.593 ;
     RECT  2.415 104.593 100.674 104.701 ;
     RECT  101.484 104.431 101.502 104.701 ;
     RECT  2.415 104.701 101.502 104.819 ;
     RECT  2.415 104.819 101.466 104.864 ;
     RECT  102.744 104.431 103.158 104.971 ;
     RECT  102.744 104.971 103.59 105.097 ;
     RECT  212.292 104.585 214.074 105.331 ;
     RECT  219.42 105.355 219.438 105.395 ;
     RECT  212.148 105.331 214.074 105.451 ;
     RECT  102.312 105.097 103.59 105.475 ;
     RECT  102.204 105.475 103.59 105.533 ;
     RECT  75.636 104.864 101.466 105.595 ;
     RECT  212.148 105.451 214.686 105.595 ;
     RECT  216.216 105.475 216.234 105.629 ;
     RECT  75.564 105.595 101.466 105.665 ;
     RECT  212.004 105.595 214.686 105.665 ;
     RECT  102.312 105.533 103.59 105.709 ;
     RECT  212.94 105.665 214.686 105.809 ;
     RECT  213.015 105.809 214.686 105.871 ;
     RECT  215.604 105.781 215.622 105.871 ;
     RECT  102.312 105.709 103.878 105.899 ;
     RECT  0.54 105.709 0.558 105.917 ;
     RECT  212.004 105.665 212.022 105.917 ;
     RECT  213.015 105.871 215.622 105.917 ;
     RECT  215.1 105.917 215.622 106.205 ;
     RECT  2.415 104.864 74.826 106.447 ;
     RECT  75.636 105.665 101.466 106.447 ;
     RECT  2.415 106.447 101.502 106.507 ;
     RECT  102.312 105.899 103.698 106.507 ;
     RECT  2.415 106.507 103.698 106.541 ;
     RECT  26.172 106.541 103.698 106.589 ;
     RECT  215.604 106.205 215.622 106.603 ;
     RECT  219.456 106.411 219.474 106.637 ;
     RECT  215.604 106.603 215.658 106.681 ;
     RECT  217.944 106.555 217.962 106.709 ;
     RECT  215.604 106.681 215.838 106.753 ;
     RECT  215.604 106.753 215.874 106.861 ;
     RECT  216.612 106.717 216.63 106.861 ;
     RECT  217.872 106.825 217.89 106.861 ;
     RECT  215.604 106.861 217.89 106.979 ;
     RECT  216.612 106.979 216.954 107.015 ;
     RECT  217.728 106.979 217.746 107.015 ;
     RECT  215.604 106.979 215.874 107.083 ;
     RECT  215.28 107.083 215.874 107.087 ;
     RECT  213.015 105.917 214.29 107.095 ;
     RECT  215.28 107.087 215.838 107.123 ;
     RECT  216.612 107.015 216.63 107.123 ;
     RECT  213.015 107.095 214.362 107.131 ;
     RECT  2.415 106.541 25.362 107.275 ;
     RECT  2.415 107.275 25.398 107.293 ;
     RECT  26.172 106.589 53.334 107.293 ;
     RECT  54.18 106.589 103.698 107.401 ;
     RECT  54.18 107.401 103.806 107.519 ;
     RECT  0.108 106.213 0.126 107.555 ;
     RECT  2.415 107.293 53.334 107.563 ;
     RECT  54.18 107.519 103.374 107.563 ;
     RECT  213.015 107.131 214.398 107.635 ;
     RECT  2.415 107.563 103.374 107.789 ;
     RECT  213.015 107.635 214.794 107.833 ;
     RECT  0.54 107.851 0.558 107.933 ;
     RECT  2.415 107.789 103.266 107.941 ;
     RECT  126.615 104.161 127.422 107.941 ;
     RECT  212.94 107.833 214.794 108.031 ;
     RECT  215.604 107.123 215.838 108.031 ;
     RECT  2.376 107.941 103.266 108.059 ;
     RECT  219.42 107.899 219.438 108.059 ;
     RECT  212.94 108.031 215.838 108.329 ;
     RECT  215.316 108.329 215.838 108.635 ;
     RECT  2.415 108.059 103.266 108.715 ;
     RECT  212.94 108.329 214.29 108.859 ;
     RECT  2.415 108.715 103.446 108.869 ;
     RECT  216.612 108.841 216.63 109.175 ;
     RECT  218.304 109.183 218.322 109.229 ;
     RECT  212.58 108.859 214.29 109.255 ;
     RECT  2.415 108.869 90.702 109.675 ;
     RECT  91.548 108.869 103.158 109.675 ;
     RECT  2.415 109.675 103.158 109.679 ;
     RECT  2.415 109.679 102.798 109.823 ;
     RECT  2.415 109.823 102.726 109.949 ;
     RECT  0.108 108.523 0.126 109.985 ;
     RECT  212.472 109.255 214.29 110.011 ;
     RECT  2.415 109.949 102.546 110.219 ;
     RECT  212.148 110.011 214.29 110.299 ;
     RECT  2.415 110.219 102.366 110.333 ;
     RECT  102.348 110.333 102.366 110.363 ;
     RECT  2.415 110.333 101.574 110.381 ;
     RECT  2.415 110.381 101.322 110.489 ;
     RECT  212.148 110.299 214.326 110.489 ;
     RECT  212.148 110.489 212.166 110.525 ;
     RECT  212.94 110.489 214.326 110.525 ;
     RECT  219.42 110.488 219.438 110.525 ;
     RECT  212.94 110.525 213.297 110.561 ;
     RECT  218.088 110.461 218.106 110.561 ;
     RECT  214.308 110.525 214.326 110.641 ;
     RECT  215.82 108.635 215.838 110.641 ;
     RECT  217.44 110.605 217.458 110.641 ;
     RECT  214.308 110.641 215.838 110.731 ;
     RECT  217.116 110.641 217.458 110.759 ;
     RECT  2.415 110.489 100.854 110.795 ;
     RECT  217.116 110.759 217.206 110.795 ;
     RECT  2.415 110.795 100.746 110.861 ;
     RECT  2.415 110.861 95.85 110.903 ;
     RECT  84.924 110.903 95.85 110.912 ;
     RECT  84.924 110.912 95.778 111.029 ;
     RECT  214.308 110.731 216.306 111.065 ;
     RECT  96.804 110.861 100.746 111.101 ;
     RECT  215.244 111.065 216.306 111.109 ;
     RECT  215.244 111.109 216.558 111.137 ;
     RECT  96.84 111.101 100.746 111.299 ;
     RECT  215.28 111.137 216.558 111.443 ;
     RECT  96.84 111.299 100.35 111.629 ;
     RECT  2.415 110.903 84.114 111.649 ;
     RECT  84.924 111.029 95.598 111.649 ;
     RECT  96.84 111.629 99.897 111.839 ;
     RECT  2.415 111.649 95.598 111.847 ;
     RECT  0.108 111.835 0.126 111.875 ;
     RECT  96.84 111.839 98.802 111.875 ;
     RECT  98.244 111.875 98.694 111.911 ;
     RECT  98.388 111.911 98.694 111.947 ;
     RECT  98.388 111.947 98.622 111.983 ;
     RECT  215.424 111.443 216.558 111.983 ;
     RECT  2.415 111.847 95.634 111.991 ;
     RECT  96.84 111.875 97.074 111.991 ;
     RECT  217.692 111.955 217.71 111.991 ;
     RECT  215.424 111.983 216.018 112.019 ;
     RECT  2.415 111.991 97.074 112.109 ;
     RECT  215.82 112.019 216.018 112.109 ;
     RECT  219.42 111.787 219.438 112.109 ;
     RECT  216.936 111.991 217.854 112.145 ;
     RECT  2.415 112.109 96.75 112.379 ;
     RECT  2.415 112.379 96.642 112.411 ;
     RECT  2.34 112.411 96.642 112.507 ;
     RECT  0.54 112.171 0.558 113.063 ;
     RECT  2.304 112.507 96.642 113.611 ;
     RECT  126.615 107.941 127.638 113.729 ;
     RECT  2.304 113.611 97.002 113.999 ;
     RECT  2.304 113.999 8.694 114.035 ;
     RECT  205.272 79.781 205.29 114.269 ;
     RECT  9.432 113.999 97.002 114.305 ;
     RECT  2.415 114.035 8.694 114.365 ;
     RECT  0.108 113.467 0.126 114.385 ;
     RECT  9.504 114.305 97.002 114.421 ;
     RECT  9.504 114.421 97.29 114.449 ;
     RECT  0.108 114.385 0.162 114.509 ;
     RECT  214.2 113.701 214.218 114.571 ;
     RECT  205.02 114.385 205.038 114.881 ;
     RECT  97.164 114.449 97.29 114.925 ;
     RECT  97.164 114.925 97.902 114.961 ;
     RECT  215.82 112.109 215.838 115.051 ;
     RECT  97.164 114.961 98.298 115.079 ;
     RECT  218.88 115.045 218.898 115.085 ;
     RECT  2.415 114.365 8.658 115.087 ;
     RECT  215.82 115.051 216.054 115.087 ;
     RECT  1.728 115.087 8.658 115.147 ;
     RECT  9.504 114.449 96.21 115.147 ;
     RECT  214.02 114.571 214.218 115.147 ;
     RECT  214.02 115.147 214.758 115.151 ;
     RECT  214.74 115.151 214.758 115.159 ;
     RECT  215.604 115.087 216.054 115.159 ;
     RECT  1.728 115.147 96.21 115.181 ;
     RECT  120.024 114.925 120.042 115.187 ;
     RECT  97.164 115.079 97.974 115.195 ;
     RECT  214.74 115.159 216.054 115.195 ;
     RECT  97.02 115.195 97.974 115.223 ;
     RECT  214.74 115.195 216.162 115.223 ;
     RECT  214.992 115.223 216.162 115.349 ;
     RECT  214.992 115.349 216.054 115.385 ;
     RECT  214.992 115.385 215.838 115.457 ;
     RECT  2.415 115.181 96.21 115.529 ;
     RECT  2.415 115.529 8.658 115.655 ;
     RECT  9.504 115.529 96.21 115.655 ;
     RECT  97.02 115.223 97.182 115.663 ;
     RECT  97.956 115.223 97.974 115.727 ;
     RECT  3.528 115.655 8.658 115.889 ;
     RECT  96.732 115.663 97.182 115.889 ;
     RECT  0.108 114.509 0.126 115.925 ;
     RECT  3.708 115.889 8.658 115.925 ;
     RECT  96.732 115.889 96.858 115.925 ;
     RECT  96.84 115.925 96.858 115.961 ;
     RECT  9.504 115.655 95.994 116.159 ;
     RECT  9.504 116.159 95.49 116.231 ;
     RECT  4.68 115.925 8.658 116.237 ;
     RECT  3.708 115.925 3.834 116.267 ;
     RECT  4.824 116.237 8.658 116.311 ;
     RECT  9.504 116.231 95.202 116.311 ;
     RECT  4.824 116.311 95.202 116.429 ;
     RECT  4.86 116.429 95.202 116.465 ;
     RECT  12.132 116.465 95.202 116.501 ;
     RECT  82.08 116.501 95.202 116.699 ;
     RECT  82.224 116.699 95.166 116.735 ;
     RECT  82.224 116.735 94.806 116.807 ;
     RECT  87.444 116.807 94.806 117.239 ;
     RECT  4.86 116.465 11.358 117.391 ;
     RECT  12.132 116.501 81.198 117.391 ;
     RECT  153.615 100.963 153.897 117.499 ;
     RECT  4.86 117.391 81.198 117.517 ;
     RECT  82.224 116.807 86.67 117.517 ;
     RECT  4.86 117.517 86.67 117.625 ;
     RECT  4.536 117.625 86.67 117.653 ;
     RECT  82.656 117.653 86.67 117.661 ;
     RECT  87.444 117.239 94.497 117.661 ;
     RECT  82.656 117.661 94.497 117.689 ;
     RECT  82.728 117.689 94.497 117.779 ;
     RECT  153.615 117.499 153.918 117.779 ;
     RECT  4.536 117.653 81.918 117.815 ;
     RECT  82.8 117.779 94.497 117.923 ;
     RECT  213.015 110.561 213.297 117.979 ;
     RECT  3.708 116.267 3.726 118.129 ;
     RECT  4.536 117.815 81.882 118.129 ;
     RECT  212.4 117.979 213.297 118.201 ;
     RECT  82.8 117.923 93.222 118.319 ;
     RECT  154.62 117.931 154.638 118.319 ;
     RECT  212.4 118.201 213.354 118.391 ;
     RECT  218.304 118.357 218.322 118.397 ;
     RECT  213.015 118.391 213.354 118.399 ;
     RECT  85.824 118.319 92.502 118.427 ;
     RECT  213.015 118.399 213.894 118.435 ;
     RECT  2.415 115.655 2.697 118.555 ;
     RECT  3.708 118.129 81.882 118.555 ;
     RECT  213.015 118.435 214.398 118.589 ;
     RECT  2.415 118.555 81.882 118.597 ;
     RECT  213.015 118.589 214.218 118.625 ;
     RECT  2.415 118.597 82.026 118.699 ;
     RECT  2.415 118.699 82.062 118.741 ;
     RECT  82.8 118.319 84.906 118.741 ;
     RECT  85.824 118.427 92.214 118.859 ;
     RECT  2.415 118.741 84.906 118.895 ;
     RECT  3.636 118.895 84.906 119.101 ;
     RECT  85.824 118.859 91.782 119.101 ;
     RECT  3.636 119.101 91.782 119.129 ;
     RECT  0.108 118.12 0.126 119.165 ;
     RECT  90.972 119.129 91.458 119.237 ;
     RECT  91.116 119.237 91.422 119.273 ;
     RECT  3.636 119.129 89.982 119.399 ;
     RECT  0.144 119.467 0.162 119.543 ;
     RECT  3.636 119.399 89.694 119.641 ;
     RECT  2.415 118.895 2.697 119.677 ;
     RECT  1.728 119.677 2.697 119.837 ;
     RECT  3.42 119.641 89.694 119.849 ;
     RECT  77.94 119.849 89.694 119.975 ;
     RECT  2.415 119.837 2.697 120.055 ;
     RECT  3.42 119.849 77.166 120.055 ;
     RECT  77.94 119.975 89.55 120.209 ;
     RECT  77.94 120.209 89.154 120.245 ;
     RECT  2.415 120.055 77.166 120.515 ;
     RECT  91.116 119.273 91.134 120.551 ;
     RECT  77.94 120.245 89.097 120.623 ;
     RECT  86.112 120.623 89.097 120.659 ;
     RECT  77.94 120.623 85.122 120.749 ;
     RECT  86.508 120.659 89.097 120.749 ;
     RECT  10.836 120.515 77.166 120.785 ;
     RECT  84.744 120.749 85.122 120.785 ;
     RECT  86.544 120.749 89.097 120.785 ;
     RECT  84.816 120.785 85.122 120.797 ;
     RECT  88.524 120.785 89.097 120.797 ;
     RECT  77.94 120.749 83.754 120.821 ;
     RECT  84.924 120.797 85.014 120.821 ;
     RECT  87.012 120.785 87.75 120.821 ;
     RECT  77.94 120.821 83.697 120.845 ;
     RECT  11.412 120.785 77.166 120.901 ;
     RECT  77.94 120.845 82.638 120.901 ;
     RECT  83.376 120.845 83.697 121.127 ;
     RECT  11.412 120.901 82.638 121.199 ;
     RECT  2.415 120.515 9.738 121.261 ;
     RECT  11.664 121.199 82.638 121.289 ;
     RECT  2.415 121.261 10.314 121.325 ;
     RECT  11.664 121.289 81.774 121.361 ;
     RECT  11.664 121.361 81.27 121.559 ;
     RECT  82.62 121.289 82.638 121.559 ;
     RECT  127.62 113.729 127.638 121.559 ;
     RECT  11.664 121.559 78.678 121.595 ;
     RECT  79.416 121.559 80.226 121.667 ;
     RECT  210.312 114.853 210.33 121.667 ;
     RECT  213.015 118.625 213.297 121.675 ;
     RECT  79.416 121.667 79.434 121.703 ;
     RECT  80.208 121.667 80.226 121.703 ;
     RECT  210.6 121.675 210.618 121.711 ;
     RECT  212.94 121.675 213.297 121.711 ;
     RECT  209.772 121.675 209.79 121.712 ;
     RECT  11.664 121.595 78.297 121.739 ;
     RECT  2.415 121.325 10.278 121.829 ;
     RECT  76.428 121.739 78.297 121.829 ;
     RECT  81.144 121.559 81.27 121.829 ;
     RECT  210.6 121.711 211.05 121.829 ;
     RECT  212.364 121.711 213.297 121.829 ;
     RECT  218.268 121.627 218.286 121.829 ;
     RECT  2.415 121.829 10.134 121.865 ;
     RECT  81.144 121.829 81.162 121.865 ;
     RECT  211.032 121.829 211.05 121.865 ;
     RECT  212.436 121.829 213.297 121.865 ;
     RECT  216.72 121.567 216.738 121.865 ;
     RECT  11.664 121.739 11.682 121.945 ;
     RECT  11.412 121.945 11.682 121.997 ;
     RECT  11.412 121.997 11.43 122.099 ;
     RECT  76.536 121.829 78.297 122.099 ;
     RECT  0.108 120.139 0.126 122.144 ;
     RECT  76.536 122.099 76.662 122.369 ;
     RECT  77.544 122.099 78.297 122.369 ;
     RECT  11.304 122.215 11.322 122.429 ;
     RECT  12.528 121.739 75.69 122.429 ;
     RECT  75.276 122.429 75.33 122.441 ;
     RECT  76.644 122.369 76.662 122.441 ;
     RECT  2.415 121.865 10.098 122.443 ;
     RECT  12.528 122.429 74.178 122.477 ;
     RECT  12.528 122.477 15.03 122.549 ;
     RECT  75.312 122.441 75.33 122.549 ;
     RECT  77.58 122.369 78.297 122.549 ;
     RECT  12.528 122.549 14.454 122.587 ;
     RECT  2.34 122.443 10.098 122.639 ;
     RECT  12.276 122.587 14.454 122.639 ;
     RECT  4.572 122.639 10.098 122.647 ;
     RECT  12.6 122.639 14.13 122.669 ;
     RECT  13.215 122.669 14.13 122.675 ;
     RECT  16.056 122.477 73.602 122.675 ;
     RECT  2.34 122.639 3.726 122.779 ;
     RECT  16.056 122.675 73.206 122.909 ;
     RECT  2.304 122.779 3.726 122.945 ;
     RECT  16.092 122.909 73.206 122.981 ;
     RECT  2.304 122.945 2.697 123.067 ;
     RECT  213.015 121.865 213.297 123.211 ;
     RECT  2.268 123.067 2.697 123.215 ;
     RECT  4.572 122.647 10.458 123.215 ;
     RECT  16.092 122.981 25.182 123.323 ;
     RECT  212.688 123.211 213.297 123.403 ;
     RECT  3.528 122.945 3.726 123.449 ;
     RECT  16.992 123.323 25.182 123.449 ;
     RECT  25.992 122.981 73.206 123.449 ;
     RECT  212.688 123.403 213.786 123.449 ;
     RECT  2.304 123.215 2.697 123.485 ;
     RECT  4.572 123.215 9.882 123.485 ;
     RECT  16.092 123.323 16.11 123.485 ;
     RECT  20.088 123.449 21.114 123.485 ;
     RECT  21.852 123.449 25.182 123.485 ;
     RECT  25.992 123.449 70.146 123.485 ;
     RECT  70.92 123.449 73.206 123.485 ;
     RECT  16.992 123.449 19.134 123.491 ;
     RECT  20.376 123.485 21.114 123.491 ;
     RECT  17.28 123.491 19.134 123.521 ;
     RECT  20.376 123.491 21.042 123.521 ;
     RECT  71.028 123.485 73.206 123.521 ;
     RECT  21.024 123.521 21.042 123.533 ;
     RECT  21.852 123.485 22.05 123.533 ;
     RECT  22.788 123.485 25.182 123.533 ;
     RECT  4.608 123.485 9.882 123.557 ;
     RECT  4.608 123.557 9.342 123.593 ;
     RECT  5.112 123.593 9.342 123.629 ;
     RECT  17.964 123.521 18.897 123.629 ;
     RECT  26.064 123.485 70.146 123.629 ;
     RECT  71.028 123.521 73.026 123.629 ;
     RECT  26.496 123.629 70.038 123.719 ;
     RECT  21.852 123.533 21.87 123.755 ;
     RECT  26.676 123.719 70.038 123.755 ;
     RECT  27.612 123.755 70.038 123.791 ;
     RECT  23.22 123.533 25.182 123.827 ;
     RECT  26.676 123.755 26.694 123.827 ;
     RECT  5.112 123.629 9.162 123.989 ;
     RECT  23.328 123.827 24.498 123.989 ;
     RECT  27.612 123.791 27.63 123.989 ;
     RECT  28.404 123.791 70.038 123.989 ;
     RECT  29.376 123.989 70.038 124.025 ;
     RECT  71.064 123.629 71.802 124.025 ;
     RECT  29.415 124.025 70.038 124.061 ;
     RECT  72.615 123.629 73.026 124.097 ;
     RECT  5.112 123.989 5.706 124.157 ;
     RECT  5.688 124.157 5.706 124.169 ;
     RECT  49.248 124.061 70.038 124.169 ;
     RECT  71.784 124.025 71.802 124.169 ;
     RECT  31.284 124.061 48.33 124.259 ;
     RECT  49.248 124.169 69.75 124.259 ;
     RECT  29.415 124.061 30.294 124.295 ;
     RECT  49.248 124.259 69.282 124.403 ;
     RECT  215.136 115.457 215.154 124.501 ;
     RECT  31.356 124.259 48.33 124.529 ;
     RECT  49.248 124.403 66.402 124.529 ;
     RECT  69.012 124.403 69.03 124.529 ;
     RECT  6.444 123.989 8.55 124.565 ;
     RECT  49.248 124.529 63.018 124.601 ;
     RECT  63.9 124.529 65.538 124.601 ;
     RECT  66.384 124.529 66.402 124.601 ;
     RECT  67.215 124.403 67.95 124.601 ;
     RECT  13.215 122.675 13.626 124.603 ;
     RECT  105.015 100.963 105.297 124.603 ;
     RECT  63.9 124.601 65.466 124.673 ;
     RECT  104.472 124.603 105.297 124.673 ;
     RECT  13.215 124.603 13.734 124.709 ;
     RECT  49.248 124.601 62.946 124.709 ;
     RECT  6.444 124.565 6.534 124.771 ;
     RECT  6.372 124.771 6.534 124.799 ;
     RECT  7.308 124.565 8.55 124.799 ;
     RECT  35.928 124.529 48.33 124.799 ;
     RECT  49.248 124.709 62.802 124.799 ;
     RECT  64.044 124.673 65.466 124.799 ;
     RECT  6.372 124.799 6.462 124.829 ;
     RECT  31.356 124.529 35.097 124.835 ;
     RECT  60.984 124.799 62.802 124.835 ;
     RECT  64.44 124.799 65.466 124.877 ;
     RECT  215.136 124.501 215.73 124.879 ;
     RECT  215.136 124.879 216.126 124.88 ;
     RECT  36.036 124.799 48.33 124.907 ;
     RECT  60.984 124.835 62.097 124.907 ;
     RECT  64.44 124.877 65.322 124.907 ;
     RECT  216.108 124.88 216.126 124.915 ;
     RECT  49.248 124.799 59.85 124.943 ;
     RECT  64.44 124.907 64.458 124.943 ;
     RECT  216.108 124.915 216.414 124.951 ;
     RECT  217.692 124.915 217.71 124.951 ;
     RECT  61.128 124.907 62.097 124.979 ;
     RECT  36.36 124.907 48.33 125.041 ;
     RECT  49.248 124.943 55.314 125.041 ;
     RECT  31.356 124.835 33.822 125.069 ;
     RECT  36.36 125.041 55.314 125.069 ;
     RECT  56.415 124.943 59.85 125.069 ;
     RECT  65.304 124.907 65.322 125.069 ;
     RECT  215.136 124.88 215.154 125.069 ;
     RECT  216.108 124.951 217.818 125.069 ;
     RECT  219.42 124.939 219.438 125.069 ;
     RECT  56.415 125.069 57.042 125.075 ;
     RECT  31.896 125.069 33.354 125.105 ;
     RECT  37.548 125.069 38.97 125.105 ;
     RECT  41.544 125.069 55.314 125.105 ;
     RECT  57.816 125.069 57.834 125.105 ;
     RECT  58.644 125.069 59.526 125.105 ;
     RECT  216.936 125.069 217.818 125.105 ;
     RECT  31.14 125.077 31.158 125.117 ;
     RECT  32.076 125.105 33.138 125.117 ;
     RECT  37.656 125.105 38.682 125.117 ;
     RECT  39.744 125.069 40.698 125.117 ;
     RECT  36.36 125.069 36.702 125.128 ;
     RECT  33.084 125.117 33.138 125.141 ;
     RECT  38.664 125.117 38.682 125.249 ;
     RECT  40.215 125.117 40.698 125.249 ;
     RECT  58.644 125.105 59.49 125.249 ;
     RECT  32.076 125.117 32.094 125.339 ;
     RECT  33.084 125.141 33.102 125.339 ;
     RECT  36.36 125.128 36.378 125.339 ;
     RECT  37.656 125.117 37.674 125.339 ;
     RECT  59.148 125.249 59.49 125.339 ;
     RECT  217.08 125.105 217.278 125.339 ;
     RECT  217.08 125.339 217.098 125.375 ;
     RECT  6.444 124.829 6.462 125.519 ;
     RECT  7.452 124.799 8.55 125.563 ;
     RECT  6.912 125.563 8.55 125.609 ;
     RECT  59.148 125.339 59.31 125.609 ;
     RECT  0.108 125.419 0.126 125.645 ;
     RECT  41.544 125.105 49.914 125.645 ;
     RECT  59.148 125.609 59.166 125.645 ;
     RECT  41.544 125.645 42.066 125.651 ;
     RECT  7.452 125.609 8.55 125.681 ;
     RECT  42.048 125.651 42.066 125.681 ;
     RECT  42.876 125.645 49.914 125.681 ;
     RECT  43.272 125.681 43.938 125.879 ;
     RECT  44.856 125.681 49.914 125.879 ;
     RECT  44.964 125.879 49.914 125.947 ;
     RECT  50.652 125.105 55.314 125.947 ;
     RECT  44.964 125.947 55.314 126.149 ;
     RECT  44.964 126.149 54.81 126.185 ;
     RECT  43.92 125.879 43.938 126.419 ;
     RECT  45.615 126.185 52.11 126.419 ;
     RECT  54.576 126.185 54.81 126.419 ;
     RECT  47.232 126.419 47.898 126.455 ;
     RECT  48.672 126.419 51.858 126.455 ;
     RECT  52.884 126.185 53.766 126.455 ;
     RECT  54.792 126.419 54.81 126.455 ;
     RECT  45.615 126.419 46.35 126.527 ;
     RECT  47.412 126.455 47.898 126.527 ;
     RECT  48.672 126.455 50.058 126.527 ;
     RECT  52.884 126.455 52.902 126.527 ;
     RECT  53.748 126.455 53.766 126.527 ;
     RECT  48.672 126.527 49.518 126.557 ;
     RECT  51.015 126.455 51.858 126.563 ;
     RECT  47.88 126.527 47.898 126.605 ;
     RECT  48.672 126.557 49.194 126.605 ;
     RECT  48.672 126.605 48.69 126.689 ;
     RECT  3.708 123.449 3.726 127.139 ;
     RECT  2.415 123.485 2.697 127.187 ;
     RECT  7.815 125.681 8.097 127.187 ;
     RECT  13.215 124.709 13.497 127.187 ;
     RECT  18.615 123.629 18.897 127.187 ;
     RECT  24.015 123.989 24.297 127.187 ;
     RECT  29.415 124.295 29.697 127.187 ;
     RECT  34.815 124.835 35.097 127.187 ;
     RECT  40.215 125.249 40.497 127.187 ;
     RECT  45.615 126.527 45.897 127.187 ;
     RECT  51.015 126.563 51.297 127.187 ;
     RECT  56.415 125.075 56.697 127.187 ;
     RECT  61.815 124.979 62.097 127.187 ;
     RECT  67.215 124.601 67.497 127.187 ;
     RECT  72.615 124.097 72.897 127.187 ;
     RECT  78.015 122.549 78.297 127.187 ;
     RECT  83.415 121.127 83.697 127.187 ;
     RECT  88.815 120.797 89.097 127.187 ;
     RECT  94.215 117.923 94.497 127.187 ;
     RECT  99.615 111.839 99.897 127.187 ;
     RECT  105.015 124.673 105.297 127.187 ;
     RECT  110.415 101.309 110.697 127.187 ;
     RECT  115.815 100.877 116.097 127.187 ;
     RECT  121.215 100.963 121.497 127.187 ;
     RECT  126.615 113.729 126.897 127.187 ;
     RECT  132.015 100.963 132.297 127.187 ;
     RECT  137.415 100.963 137.697 127.187 ;
     RECT  142.815 103.517 143.097 127.187 ;
     RECT  148.215 100.963 148.497 127.187 ;
     RECT  153.615 117.779 153.897 127.187 ;
     RECT  159.015 100.963 159.297 127.187 ;
     RECT  164.415 100.963 164.697 127.187 ;
     RECT  169.815 100.963 170.097 127.187 ;
     RECT  175.215 100.963 175.497 127.187 ;
     RECT  180.615 100.963 180.897 127.187 ;
     RECT  186.015 100.963 186.297 127.187 ;
     RECT  191.415 100.963 191.697 127.187 ;
     RECT  196.815 101.741 197.097 127.187 ;
     RECT  202.215 101.723 202.497 127.187 ;
     RECT  207.615 77.309 207.897 127.187 ;
     RECT  213.015 123.449 213.297 127.187 ;
     RECT  126.615 127.187 126.705 127.201 ;
     RECT  123.372 127.111 123.39 127.229 ;
     RECT  126.504 127.201 126.705 127.301 ;
     RECT  2.415 127.187 2.505 127.457 ;
     RECT  7.815 127.187 7.905 127.457 ;
     RECT  13.215 127.187 13.305 127.457 ;
     RECT  18.615 127.187 18.705 127.457 ;
     RECT  24.015 127.187 24.105 127.457 ;
     RECT  29.415 127.187 29.505 127.457 ;
     RECT  34.815 127.187 34.905 127.457 ;
     RECT  40.215 127.187 40.305 127.457 ;
     RECT  45.615 127.187 45.705 127.457 ;
     RECT  51.015 127.187 51.105 127.457 ;
     RECT  56.415 127.187 56.505 127.457 ;
     RECT  61.815 127.187 61.905 127.457 ;
     RECT  67.215 127.187 67.305 127.457 ;
     RECT  72.615 127.187 72.705 127.457 ;
     RECT  78.015 127.187 78.105 127.457 ;
     RECT  83.415 127.187 83.505 127.457 ;
     RECT  88.815 127.187 88.905 127.457 ;
     RECT  94.215 127.187 94.305 127.457 ;
     RECT  99.615 127.187 99.705 127.457 ;
     RECT  105.015 127.187 105.105 127.457 ;
     RECT  110.415 127.187 110.505 127.457 ;
     RECT  115.815 127.187 115.905 127.457 ;
     RECT  121.215 127.187 121.305 127.457 ;
     RECT  126.615 127.301 126.705 127.457 ;
     RECT  132.015 127.187 132.105 127.457 ;
     RECT  137.415 127.187 137.505 127.457 ;
     RECT  142.815 127.187 142.905 127.457 ;
     RECT  148.215 127.187 148.305 127.457 ;
     RECT  153.615 127.187 153.705 127.457 ;
     RECT  159.015 127.187 159.105 127.457 ;
     RECT  164.415 127.187 164.505 127.457 ;
     RECT  169.815 127.187 169.905 127.457 ;
     RECT  175.215 127.187 175.305 127.457 ;
     RECT  180.615 127.187 180.705 127.457 ;
     RECT  186.015 127.187 186.105 127.457 ;
     RECT  191.415 127.187 191.505 127.457 ;
     RECT  196.815 127.187 196.905 127.457 ;
     RECT  202.215 127.187 202.305 127.457 ;
     RECT  207.615 127.187 207.705 127.457 ;
     RECT  213.015 127.187 213.105 127.457 ;
     RECT  141.876 127.345 141.894 129.581 ;
    LAYER M4 ;
     RECT  0.084 6.48 0.137 6.504 ;
     RECT  0.06 6.504 0.137 6.816 ;
     RECT  0.084 6.816 0.137 6.84 ;
     RECT  0.06 6.84 0.137 7.152 ;
     RECT  0.084 7.152 0.137 7.176 ;
     RECT  0.06 7.176 0.137 7.488 ;
     RECT  0.084 7.488 0.137 7.512 ;
     RECT  0.06 7.512 0.137 7.824 ;
     RECT  0.084 7.824 0.137 7.848 ;
     RECT  0.06 7.848 0.137 8.112 ;
     RECT  0.084 8.112 0.137 8.136 ;
     RECT  0.06 8.136 0.137 8.448 ;
     RECT  0.084 8.448 0.137 8.472 ;
     RECT  0.06 8.472 0.137 8.784 ;
     RECT  0.084 8.784 0.137 8.808 ;
     RECT  0.084 11.136 0.137 11.16 ;
     RECT  0.06 11.16 0.137 11.472 ;
     RECT  0.084 11.472 0.137 11.496 ;
     RECT  0.06 11.496 0.137 11.76 ;
     RECT  0.084 11.76 0.137 11.784 ;
     RECT  0.06 11.784 0.137 12.096 ;
     RECT  0.084 12.096 0.137 12.12 ;
     RECT  0.06 12.12 0.137 12.432 ;
     RECT  0.084 12.432 0.137 12.456 ;
     RECT  0.06 12.456 0.137 12.768 ;
     RECT  0.084 12.768 0.137 12.792 ;
     RECT  0.06 12.792 0.137 13.104 ;
     RECT  0.084 13.104 0.137 13.128 ;
     RECT  0.06 13.128 0.137 13.44 ;
     RECT  0.084 13.44 0.137 13.464 ;
     RECT  0.06 13.464 0.137 13.776 ;
     RECT  0.084 13.776 0.137 13.8 ;
     RECT  0.06 13.8 0.137 14.112 ;
     RECT  0.084 14.112 0.137 14.136 ;
     RECT  0.06 14.136 0.137 14.4 ;
     RECT  0.084 14.4 0.137 14.424 ;
     RECT  0.06 14.424 0.137 14.736 ;
     RECT  0.084 14.736 0.137 14.76 ;
     RECT  0.084 17.088 0.137 17.112 ;
     RECT  0.06 17.112 0.137 17.424 ;
     RECT  0.084 17.424 0.137 17.448 ;
     RECT  0.06 17.448 0.137 17.76 ;
     RECT  0.084 17.76 0.137 17.784 ;
     RECT  0.06 17.784 0.137 18.096 ;
     RECT  0.084 18.096 0.137 18.12 ;
     RECT  0.06 18.12 0.137 18.384 ;
     RECT  0.084 18.384 0.137 18.408 ;
     RECT  0.06 18.408 0.137 18.72 ;
     RECT  0.084 18.72 0.137 18.744 ;
     RECT  0.06 18.744 0.137 19.056 ;
     RECT  0.084 19.056 0.137 19.08 ;
     RECT  0.06 19.08 0.137 19.392 ;
     RECT  0.084 19.392 0.137 19.416 ;
     RECT  0.06 19.416 0.137 19.728 ;
     RECT  0.084 19.728 0.137 19.752 ;
     RECT  0.06 19.752 0.137 20.064 ;
     RECT  0.084 20.064 0.137 20.088 ;
     RECT  0.06 20.088 0.137 20.4 ;
     RECT  0.084 20.4 0.137 20.424 ;
     RECT  0.06 20.424 0.137 20.736 ;
     RECT  0.084 20.736 0.137 20.76 ;
     RECT  0.06 20.76 0.137 21.024 ;
     RECT  0.084 21.024 0.137 21.048 ;
     RECT  0.06 21.048 0.137 21.36 ;
     RECT  0.084 21.36 0.137 21.384 ;
     RECT  0.06 21.384 0.137 21.696 ;
     RECT  0.084 21.696 0.137 21.72 ;
     RECT  0.06 21.72 0.137 22.032 ;
     RECT  0.084 22.032 0.137 22.056 ;
     RECT  0.06 22.056 0.137 22.368 ;
     RECT  0.084 22.368 0.137 22.392 ;
     RECT  0.06 22.392 0.137 22.704 ;
     RECT  0.084 22.704 0.137 22.728 ;
     RECT  0.06 22.728 0.137 23.04 ;
     RECT  0.084 23.04 0.137 23.064 ;
     RECT  0.06 23.064 0.137 23.376 ;
     RECT  0.084 23.376 0.137 23.4 ;
     RECT  0.06 23.4 0.137 23.664 ;
     RECT  0.084 23.664 0.137 23.688 ;
     RECT  0.06 23.688 0.137 24 ;
     RECT  0.084 24 0.137 24.024 ;
     RECT  0.06 24.024 0.137 24.336 ;
     RECT  0.084 24.336 0.137 24.36 ;
     RECT  0.06 24.36 0.137 24.672 ;
     RECT  0.084 24.672 0.137 24.696 ;
     RECT  0.06 24.696 0.137 25.008 ;
     RECT  0.084 25.008 0.137 25.032 ;
     RECT  0.06 25.032 0.137 25.344 ;
     RECT  0.084 25.344 0.137 25.368 ;
     RECT  0.06 25.368 0.137 25.68 ;
     RECT  0.084 25.68 0.137 25.704 ;
     RECT  0.06 25.704 0.137 26.016 ;
     RECT  0.084 26.016 0.137 26.04 ;
     RECT  0.06 26.04 0.137 26.304 ;
     RECT  0.084 26.304 0.137 26.328 ;
     RECT  0.06 26.328 0.137 26.64 ;
     RECT  0.084 26.64 0.137 26.664 ;
     RECT  0.06 26.664 0.137 26.976 ;
     RECT  0.084 26.976 0.137 27 ;
     RECT  0.06 27 0.137 27.312 ;
     RECT  0.084 27.312 0.137 27.336 ;
     RECT  0.06 27.336 0.137 27.648 ;
     RECT  0.084 27.648 0.137 27.672 ;
     RECT  0.06 27.672 0.137 27.984 ;
     RECT  0.084 27.984 0.137 28.008 ;
     RECT  0.06 28.008 0.137 28.32 ;
     RECT  0.084 28.32 0.137 28.344 ;
     RECT  0.06 28.344 0.137 28.656 ;
     RECT  0.084 28.656 0.137 28.68 ;
     RECT  0.06 28.68 0.137 28.944 ;
     RECT  0.084 28.944 0.137 28.968 ;
     RECT  0.06 28.968 0.137 29.28 ;
     RECT  0.084 29.28 0.137 29.304 ;
     RECT  0.06 29.304 0.137 29.616 ;
     RECT  0.084 29.616 0.137 29.64 ;
     RECT  0.06 29.64 0.137 29.952 ;
     RECT  0.084 29.952 0.137 29.976 ;
     RECT  0.06 29.976 0.137 30.288 ;
     RECT  0.084 30.288 0.137 30.312 ;
     RECT  0.06 30.312 0.137 30.624 ;
     RECT  0.084 30.624 0.137 30.648 ;
     RECT  0.06 30.648 0.137 30.96 ;
     RECT  0.084 30.96 0.137 30.984 ;
     RECT  0.06 30.984 0.137 31.296 ;
     RECT  0.084 31.296 0.137 31.32 ;
     RECT  0.06 31.32 0.137 31.584 ;
     RECT  0.084 31.584 0.137 31.608 ;
     RECT  0.06 31.608 0.137 31.92 ;
     RECT  0.084 31.92 0.137 31.944 ;
     RECT  0.06 31.944 0.137 32.256 ;
     RECT  0.084 32.256 0.137 32.28 ;
     RECT  0.06 32.28 0.137 32.592 ;
     RECT  0.084 32.592 0.137 32.616 ;
     RECT  0.06 32.616 0.137 32.928 ;
     RECT  0.084 32.928 0.137 32.952 ;
     RECT  0.06 32.952 0.137 33.264 ;
     RECT  0.084 33.264 0.137 33.288 ;
     RECT  0.06 33.288 0.137 33.6 ;
     RECT  0.084 33.6 0.137 33.624 ;
     RECT  0.06 33.624 0.137 33.936 ;
     RECT  0.084 33.936 0.137 33.96 ;
     RECT  0.06 33.96 0.137 34.224 ;
     RECT  0.084 34.224 0.137 34.248 ;
     RECT  0.06 34.248 0.137 34.56 ;
     RECT  0.084 34.56 0.137 34.584 ;
     RECT  0.06 34.584 0.137 34.896 ;
     RECT  0.084 34.896 0.137 34.92 ;
     RECT  0.06 34.92 0.137 35.232 ;
     RECT  0.084 35.232 0.137 35.256 ;
     RECT  0.06 35.256 0.137 35.568 ;
     RECT  0.084 35.568 0.137 35.592 ;
     RECT  0.06 35.592 0.137 35.904 ;
     RECT  0.084 35.904 0.137 35.928 ;
     RECT  0.06 35.928 0.137 36.24 ;
     RECT  0.084 36.24 0.137 36.264 ;
     RECT  0.06 36.264 0.137 36.576 ;
     RECT  0.084 36.576 0.137 36.6 ;
     RECT  0.06 36.6 0.137 36.864 ;
     RECT  0.084 36.864 0.137 36.888 ;
     RECT  0.06 36.888 0.137 37.2 ;
     RECT  0.084 37.2 0.137 37.224 ;
     RECT  0.06 37.224 0.137 37.536 ;
     RECT  0.084 37.536 0.137 37.56 ;
     RECT  0.06 37.56 0.137 37.872 ;
     RECT  0.084 37.872 0.137 37.896 ;
     RECT  0.06 37.896 0.137 38.208 ;
     RECT  0.084 38.208 0.137 38.232 ;
     RECT  0.06 38.232 0.137 38.544 ;
     RECT  0.084 38.544 0.137 38.568 ;
     RECT  0.06 38.568 0.137 38.88 ;
     RECT  0.084 38.88 0.137 38.904 ;
     RECT  0.06 38.904 0.137 39.216 ;
     RECT  0.084 39.216 0.137 39.24 ;
     RECT  0.06 39.24 0.137 39.504 ;
     RECT  0.084 39.504 0.137 39.528 ;
     RECT  0.06 39.528 0.137 39.84 ;
     RECT  0.084 39.84 0.137 39.864 ;
     RECT  0.06 39.864 0.137 40.176 ;
     RECT  0.084 40.176 0.137 40.2 ;
     RECT  0.06 40.2 0.137 40.512 ;
     RECT  0.084 40.512 0.137 40.536 ;
     RECT  0.06 40.536 0.137 40.848 ;
     RECT  0.084 40.848 0.137 40.872 ;
     RECT  0.06 40.872 0.137 41.184 ;
     RECT  0.084 41.184 0.137 41.208 ;
     RECT  0.06 41.208 0.137 41.52 ;
     RECT  0.084 41.52 0.137 41.544 ;
     RECT  0.06 41.544 0.137 41.856 ;
     RECT  0.084 41.856 0.137 41.88 ;
     RECT  0.06 41.88 0.137 42.144 ;
     RECT  0.084 42.144 0.137 42.168 ;
     RECT  0.06 42.168 0.137 42.48 ;
     RECT  0.084 42.48 0.137 42.504 ;
     RECT  0.06 42.504 0.137 42.816 ;
     RECT  0.084 42.816 0.137 42.84 ;
     RECT  0.06 42.84 0.137 43.152 ;
     RECT  0.084 43.152 0.137 43.176 ;
     RECT  0.06 43.176 0.137 43.488 ;
     RECT  0.084 43.488 0.137 43.512 ;
     RECT  0.06 43.512 0.137 43.824 ;
     RECT  0.084 43.824 0.137 43.848 ;
     RECT  0.06 43.848 0.137 44.16 ;
     RECT  0.084 44.16 0.137 44.184 ;
     RECT  0.06 44.184 0.137 44.496 ;
     RECT  0.084 44.496 0.137 44.52 ;
     RECT  0.06 44.52 0.137 44.784 ;
     RECT  0.084 44.784 0.137 44.808 ;
     RECT  0.06 44.808 0.137 45.12 ;
     RECT  0.084 45.12 0.137 45.144 ;
     RECT  0.06 45.144 0.137 45.456 ;
     RECT  0.084 45.456 0.137 45.48 ;
     RECT  0.06 45.48 0.137 45.792 ;
     RECT  0.084 45.792 0.137 45.816 ;
     RECT  0.06 45.816 0.137 46.128 ;
     RECT  0.084 46.128 0.137 46.152 ;
     RECT  0.06 46.152 0.137 46.464 ;
     RECT  0.084 46.464 0.137 46.488 ;
     RECT  0.06 46.488 0.137 46.8 ;
     RECT  0.084 46.8 0.137 46.824 ;
     RECT  0.06 46.824 0.137 47.136 ;
     RECT  0.084 47.136 0.137 47.16 ;
     RECT  0.06 47.16 0.137 47.424 ;
     RECT  0.084 47.424 0.137 47.448 ;
     RECT  0.06 47.448 0.137 47.76 ;
     RECT  0.084 47.76 0.137 47.784 ;
     RECT  0.06 47.784 0.137 48.096 ;
     RECT  0.084 48.096 0.137 48.12 ;
     RECT  0.06 48.12 0.137 48.432 ;
     RECT  0.084 48.432 0.137 48.456 ;
     RECT  0.06 48.456 0.137 48.768 ;
     RECT  0.084 48.768 0.137 48.792 ;
     RECT  0.06 48.792 0.137 49.104 ;
     RECT  0.084 49.104 0.137 49.128 ;
     RECT  0.06 49.128 0.137 49.44 ;
     RECT  0.084 49.44 0.137 49.464 ;
     RECT  0.06 49.464 0.137 49.776 ;
     RECT  0.084 49.776 0.137 49.8 ;
     RECT  0.06 49.8 0.137 50.064 ;
     RECT  0.084 50.064 0.137 50.088 ;
     RECT  0.06 50.088 0.137 50.4 ;
     RECT  0.084 50.4 0.137 50.424 ;
     RECT  0.06 50.424 0.137 50.736 ;
     RECT  0.084 50.736 0.137 50.76 ;
     RECT  0.06 50.76 0.137 51.072 ;
     RECT  0.084 51.072 0.137 51.096 ;
     RECT  0.06 51.096 0.137 51.408 ;
     RECT  0.084 51.408 0.137 51.432 ;
     RECT  0.06 51.432 0.137 51.744 ;
     RECT  0.084 51.744 0.137 51.768 ;
     RECT  0.06 51.768 0.137 52.08 ;
     RECT  0.084 52.08 0.137 52.104 ;
     RECT  0.06 52.104 0.137 52.416 ;
     RECT  0.084 52.416 0.137 52.44 ;
     RECT  0.06 52.44 0.137 52.704 ;
     RECT  0.084 52.704 0.137 52.728 ;
     RECT  0.06 52.728 0.137 53.04 ;
     RECT  0.084 53.04 0.137 53.064 ;
     RECT  0.06 53.064 0.137 53.376 ;
     RECT  0.084 53.376 0.137 53.4 ;
     RECT  0.06 53.4 0.137 53.712 ;
     RECT  0.084 53.712 0.137 53.736 ;
     RECT  0.06 53.736 0.137 54.048 ;
     RECT  0.084 54.048 0.137 54.072 ;
     RECT  0.06 54.072 0.137 54.384 ;
     RECT  0.084 54.384 0.137 54.408 ;
     RECT  0.06 54.408 0.137 54.72 ;
     RECT  0.084 54.72 0.137 54.744 ;
     RECT  0.06 54.744 0.137 55.056 ;
     RECT  0.084 55.056 0.137 55.08 ;
     RECT  0.06 55.08 0.137 55.344 ;
     RECT  0.084 55.344 0.137 55.368 ;
     RECT  0.06 55.368 0.137 55.68 ;
     RECT  0.084 55.68 0.137 55.704 ;
     RECT  0.06 55.704 0.137 56.016 ;
     RECT  0.084 56.016 0.137 56.04 ;
     RECT  0.06 56.04 0.137 56.352 ;
     RECT  0.084 56.352 0.137 56.376 ;
     RECT  0.06 56.376 0.137 56.688 ;
     RECT  0.084 56.688 0.137 56.712 ;
     RECT  0.06 56.712 0.137 57.024 ;
     RECT  0.084 57.024 0.137 57.048 ;
     RECT  0.06 57.048 0.137 57.36 ;
     RECT  0.084 57.36 0.137 57.384 ;
     RECT  0.06 57.384 0.137 57.696 ;
     RECT  0.084 57.696 0.137 57.72 ;
     RECT  0.06 57.72 0.137 57.984 ;
     RECT  0.084 57.984 0.137 58.008 ;
     RECT  0.06 58.008 0.137 58.32 ;
     RECT  0.084 58.32 0.137 58.344 ;
     RECT  0.06 58.344 0.137 58.656 ;
     RECT  0.084 58.656 0.137 58.68 ;
     RECT  0.06 58.68 0.137 58.992 ;
     RECT  0.084 58.992 0.137 59.016 ;
     RECT  0.06 59.016 0.137 59.328 ;
     RECT  0.084 59.328 0.137 59.352 ;
     RECT  0.06 59.352 0.137 59.664 ;
     RECT  0.084 59.664 0.137 59.688 ;
     RECT  0.06 59.688 0.137 60 ;
     RECT  0.084 60 0.137 60.024 ;
     RECT  0.06 60.024 0.137 60.336 ;
     RECT  0.084 60.336 0.137 60.36 ;
     RECT  0.06 60.36 0.137 60.624 ;
     RECT  0.084 60.624 0.137 60.648 ;
     RECT  0.06 60.648 0.137 60.96 ;
     RECT  0.084 60.96 0.137 60.984 ;
     RECT  0.06 60.984 0.137 61.296 ;
     RECT  0.084 61.296 0.137 61.32 ;
     RECT  0.06 61.32 0.137 61.632 ;
     RECT  0.084 61.632 0.137 61.656 ;
     RECT  0.06 61.656 0.137 61.968 ;
     RECT  0.084 61.968 0.137 61.992 ;
     RECT  0.06 61.992 0.137 62.304 ;
     RECT  0.084 62.304 0.137 62.328 ;
     RECT  0.06 62.328 0.137 62.64 ;
     RECT  0.084 62.64 0.137 62.664 ;
     RECT  0.06 62.664 0.137 62.976 ;
     RECT  0.084 62.976 0.137 63 ;
     RECT  0.06 63 0.137 63.264 ;
     RECT  0.084 63.264 0.137 63.288 ;
     RECT  0.06 63.288 0.137 63.6 ;
     RECT  0.084 63.6 0.137 63.624 ;
     RECT  0.06 63.624 0.137 63.936 ;
     RECT  0.084 63.936 0.137 63.96 ;
     RECT  0.06 63.96 0.137 64.272 ;
     RECT  0.084 64.272 0.137 64.296 ;
     RECT  0.06 64.296 0.137 64.608 ;
     RECT  0.084 64.608 0.137 64.632 ;
     RECT  0.06 64.632 0.137 64.944 ;
     RECT  0.084 64.944 0.137 64.968 ;
     RECT  0.06 64.968 0.137 65.28 ;
     RECT  0.084 65.28 0.137 65.304 ;
     RECT  0.06 65.304 0.137 65.616 ;
     RECT  0.084 65.616 0.137 65.64 ;
     RECT  0.06 65.64 0.137 65.904 ;
     RECT  0.084 65.904 0.137 65.928 ;
     RECT  0.06 65.928 0.137 66.24 ;
     RECT  0.084 66.24 0.137 66.264 ;
     RECT  0.06 66.264 0.137 66.576 ;
     RECT  0.084 66.576 0.137 66.6 ;
     RECT  0.06 66.6 0.137 66.912 ;
     RECT  0.084 66.912 0.137 66.936 ;
     RECT  0.06 66.936 0.137 67.248 ;
     RECT  0.084 67.248 0.137 67.272 ;
     RECT  0.06 67.272 0.137 67.584 ;
     RECT  0.084 67.584 0.137 67.608 ;
     RECT  0.06 67.608 0.137 67.92 ;
     RECT  0.084 67.92 0.137 67.944 ;
     RECT  0.06 67.944 0.137 68.256 ;
     RECT  0.084 68.256 0.137 68.28 ;
     RECT  0.06 68.28 0.137 68.544 ;
     RECT  0.084 68.544 0.137 68.568 ;
     RECT  0.06 68.568 0.137 68.88 ;
     RECT  0.084 68.88 0.137 68.904 ;
     RECT  0.06 68.904 0.137 69.216 ;
     RECT  0.084 69.216 0.137 69.24 ;
     RECT  0.06 69.24 0.137 69.552 ;
     RECT  0.084 69.552 0.137 69.576 ;
     RECT  0.06 69.576 0.137 69.888 ;
     RECT  0.084 69.888 0.137 69.912 ;
     RECT  0.06 69.912 0.137 70.224 ;
     RECT  0.084 70.224 0.137 70.248 ;
     RECT  0.06 70.248 0.137 70.56 ;
     RECT  0.084 70.56 0.137 70.584 ;
     RECT  0.06 70.584 0.137 70.896 ;
     RECT  0.084 70.896 0.137 70.92 ;
     RECT  0.06 70.92 0.137 71.184 ;
     RECT  0.084 71.184 0.137 71.208 ;
     RECT  0.06 71.208 0.137 71.52 ;
     RECT  0.084 71.52 0.137 71.544 ;
     RECT  0.06 71.544 0.137 71.856 ;
     RECT  0.084 71.856 0.137 71.88 ;
     RECT  0.06 71.88 0.137 72.192 ;
     RECT  0.084 72.192 0.137 72.216 ;
     RECT  0.06 72.216 0.137 72.528 ;
     RECT  0.084 72.528 0.137 72.552 ;
     RECT  0.06 72.552 0.137 72.864 ;
     RECT  0.084 72.864 0.137 72.888 ;
     RECT  0.06 72.888 0.137 73.2 ;
     RECT  0.084 73.2 0.137 73.224 ;
     RECT  0.06 73.224 0.137 73.536 ;
     RECT  0.084 73.536 0.137 73.56 ;
     RECT  0.06 73.56 0.137 73.824 ;
     RECT  0.084 73.824 0.137 73.848 ;
     RECT  0.06 73.848 0.137 74.16 ;
     RECT  0.084 74.16 0.137 74.184 ;
     RECT  0.06 74.184 0.137 74.496 ;
     RECT  0.084 74.496 0.137 74.52 ;
     RECT  0.06 74.52 0.137 74.832 ;
     RECT  0.084 74.832 0.137 74.856 ;
     RECT  0.06 74.856 0.137 75.168 ;
     RECT  0.084 75.168 0.137 75.192 ;
     RECT  0.06 75.192 0.137 75.504 ;
     RECT  0.084 75.504 0.137 75.528 ;
     RECT  0.06 75.528 0.137 75.84 ;
     RECT  0.084 75.84 0.137 75.864 ;
     RECT  0.06 75.864 0.137 76.176 ;
     RECT  0.084 76.176 0.137 76.2 ;
     RECT  0.06 76.2 0.137 76.464 ;
     RECT  0.084 76.464 0.137 76.488 ;
     RECT  0.06 76.488 0.137 76.8 ;
     RECT  0.084 76.8 0.137 76.824 ;
     RECT  0.06 76.824 0.137 77.136 ;
     RECT  0.084 77.136 0.137 77.16 ;
     RECT  0.06 77.16 0.137 77.472 ;
     RECT  0.084 77.472 0.137 77.496 ;
     RECT  0.06 77.496 0.137 77.808 ;
     RECT  0.084 77.808 0.137 77.832 ;
     RECT  0.06 77.832 0.137 78.144 ;
     RECT  0.084 78.144 0.137 78.168 ;
     RECT  0.06 78.168 0.137 78.48 ;
     RECT  0.084 78.48 0.137 78.504 ;
     RECT  0.06 78.504 0.137 78.816 ;
     RECT  0.084 78.816 0.137 78.84 ;
     RECT  0.06 78.84 0.137 79.104 ;
     RECT  0.084 79.104 0.137 79.128 ;
     RECT  0.06 79.128 0.137 79.44 ;
     RECT  0.084 79.44 0.137 79.464 ;
     RECT  0.06 79.464 0.137 79.776 ;
     RECT  0.084 79.776 0.137 79.8 ;
     RECT  0.06 79.8 0.137 80.112 ;
     RECT  0.084 80.112 0.137 80.136 ;
     RECT  0.06 80.136 0.137 80.448 ;
     RECT  0.084 80.448 0.137 80.472 ;
     RECT  0.06 80.472 0.137 80.784 ;
     RECT  0.084 80.784 0.137 80.808 ;
     RECT  0.06 80.808 0.137 81.12 ;
     RECT  0.084 81.12 0.137 81.144 ;
     RECT  0.06 81.144 0.137 81.456 ;
     RECT  0.084 81.456 0.137 81.48 ;
     RECT  0.06 81.48 0.137 81.744 ;
     RECT  0.084 81.744 0.137 81.768 ;
     RECT  0.06 81.768 0.137 82.08 ;
     RECT  0.084 82.08 0.137 82.104 ;
     RECT  0.06 82.104 0.137 82.416 ;
     RECT  0.084 82.416 0.137 82.44 ;
     RECT  0.06 82.44 0.137 82.752 ;
     RECT  0.084 82.752 0.137 82.776 ;
     RECT  0.06 82.776 0.137 83.088 ;
     RECT  0.084 83.088 0.137 83.112 ;
     RECT  0.06 83.112 0.137 83.424 ;
     RECT  0.084 83.424 0.137 83.448 ;
     RECT  0.06 83.448 0.137 83.76 ;
     RECT  0.084 83.76 0.137 83.784 ;
     RECT  0.06 83.784 0.137 84.096 ;
     RECT  0.084 84.096 0.137 84.12 ;
     RECT  0.06 84.12 0.137 84.384 ;
     RECT  0.084 84.384 0.137 84.408 ;
     RECT  0.06 84.408 0.137 84.72 ;
     RECT  0.084 84.72 0.137 84.744 ;
     RECT  0.06 84.744 0.137 85.056 ;
     RECT  0.084 85.056 0.137 85.08 ;
     RECT  0.06 85.08 0.137 85.392 ;
     RECT  0.084 85.392 0.137 85.416 ;
     RECT  0.06 85.416 0.137 85.728 ;
     RECT  0.084 85.728 0.137 85.752 ;
     RECT  0.06 85.752 0.137 86.064 ;
     RECT  0.084 86.064 0.137 86.088 ;
     RECT  0.06 86.088 0.137 86.4 ;
     RECT  0.084 86.4 0.137 86.424 ;
     RECT  0.06 86.424 0.137 86.736 ;
     RECT  0.084 86.736 0.137 86.76 ;
     RECT  0.06 86.76 0.137 87.024 ;
     RECT  0.084 87.024 0.137 87.048 ;
     RECT  0.06 87.048 0.137 87.36 ;
     RECT  0.084 87.36 0.137 87.384 ;
     RECT  0.06 87.384 0.137 87.696 ;
     RECT  0.084 87.696 0.137 87.72 ;
     RECT  0.06 87.72 0.137 88.032 ;
     RECT  0.084 88.032 0.137 88.056 ;
     RECT  0.06 88.056 0.137 88.368 ;
     RECT  0.084 88.368 0.137 88.392 ;
     RECT  0.06 88.392 0.137 88.704 ;
     RECT  0.084 88.704 0.137 88.728 ;
     RECT  0.06 88.728 0.137 89.04 ;
     RECT  0.084 89.04 0.137 89.064 ;
     RECT  0.06 89.064 0.137 89.376 ;
     RECT  0.084 89.376 0.137 89.4 ;
     RECT  0.06 89.4 0.137 89.664 ;
     RECT  0.084 89.664 0.137 89.688 ;
     RECT  0.06 89.688 0.137 90 ;
     RECT  0.084 90 0.137 90.024 ;
     RECT  0.06 90.024 0.137 90.336 ;
     RECT  0.084 90.336 0.137 90.36 ;
     RECT  0.06 90.36 0.137 90.672 ;
     RECT  0.084 90.672 0.137 90.696 ;
     RECT  0.06 90.696 0.137 91.008 ;
     RECT  0.084 91.008 0.137 91.032 ;
     RECT  0.06 91.032 0.137 91.344 ;
     RECT  0.084 91.344 0.137 91.368 ;
     RECT  0.06 91.368 0.137 91.68 ;
     RECT  0.084 91.68 0.137 91.704 ;
     RECT  0.06 91.704 0.137 92.016 ;
     RECT  0.084 92.016 0.137 92.04 ;
     RECT  0.06 92.04 0.137 92.304 ;
     RECT  0.084 92.304 0.137 92.328 ;
     RECT  0.06 92.328 0.137 92.64 ;
     RECT  0.084 92.64 0.137 92.664 ;
     RECT  0.06 92.664 0.137 92.976 ;
     RECT  0.084 92.976 0.137 93 ;
     RECT  0.06 93 0.137 93.312 ;
     RECT  0.084 93.312 0.137 93.336 ;
     RECT  0.06 93.336 0.137 93.648 ;
     RECT  0.084 93.648 0.137 93.672 ;
     RECT  0.06 93.672 0.137 93.984 ;
     RECT  0.084 93.984 0.137 94.008 ;
     RECT  0.06 94.008 0.137 94.32 ;
     RECT  0.084 94.32 0.137 94.344 ;
     RECT  0.06 94.344 0.137 94.656 ;
     RECT  0.084 94.656 0.137 94.68 ;
     RECT  0.06 94.68 0.137 94.944 ;
     RECT  0.084 94.944 0.137 94.968 ;
     RECT  0.06 94.968 0.137 95.28 ;
     RECT  0.084 95.28 0.137 95.304 ;
     RECT  0.06 95.304 0.137 95.616 ;
     RECT  0.084 95.616 0.137 95.64 ;
     RECT  0.06 95.64 0.137 95.952 ;
     RECT  0.084 95.952 0.137 95.976 ;
     RECT  0.06 95.976 0.137 96.288 ;
     RECT  0.084 96.288 0.137 96.312 ;
     RECT  0.06 96.312 0.137 96.624 ;
     RECT  0.084 96.624 0.137 96.648 ;
     RECT  0.06 96.648 0.137 96.96 ;
     RECT  0.084 96.96 0.137 96.984 ;
     RECT  0.06 96.984 0.137 97.296 ;
     RECT  0.084 97.296 0.137 97.32 ;
     RECT  0.06 97.32 0.137 97.584 ;
     RECT  0.084 97.584 0.137 97.608 ;
     RECT  0.06 97.608 0.137 97.92 ;
     RECT  0.084 97.92 0.137 97.944 ;
     RECT  0.06 97.944 0.137 98.256 ;
     RECT  0.084 98.256 0.137 98.28 ;
     RECT  0.06 98.28 0.137 98.592 ;
     RECT  0.084 98.592 0.137 98.616 ;
     RECT  0.06 98.616 0.137 98.928 ;
     RECT  0.084 98.928 0.137 98.952 ;
     RECT  0.06 98.952 0.137 99.264 ;
     RECT  0.084 99.264 0.137 99.288 ;
     RECT  0.06 99.288 0.137 99.6 ;
     RECT  0.084 99.6 0.137 99.624 ;
     RECT  0.06 99.624 0.137 99.936 ;
     RECT  0.084 99.936 0.137 99.96 ;
     RECT  0.06 99.96 0.137 100.224 ;
     RECT  0.084 100.224 0.137 100.248 ;
     RECT  0.06 100.248 0.137 100.56 ;
     RECT  0.084 100.56 0.137 100.584 ;
     RECT  0.06 100.584 0.137 100.896 ;
     RECT  0.084 100.896 0.137 100.92 ;
     RECT  0.06 100.92 0.137 101.232 ;
     RECT  0.084 101.232 0.137 101.256 ;
     RECT  0.084 105.888 0.137 105.912 ;
     RECT  0.06 105.912 0.137 106.224 ;
     RECT  0.084 106.224 0.137 106.248 ;
     RECT  0.06 106.248 0.137 106.56 ;
     RECT  0.084 106.56 0.137 106.584 ;
     RECT  0.06 106.584 0.137 106.896 ;
     RECT  0.084 106.896 0.137 106.92 ;
     RECT  0.06 106.92 0.137 107.232 ;
     RECT  0.084 107.232 0.137 107.256 ;
     RECT  0.06 107.256 0.137 107.52 ;
     RECT  0.084 107.52 0.137 107.544 ;
     RECT  0.06 107.544 0.137 107.856 ;
     RECT  0.084 107.856 0.137 107.88 ;
     RECT  0.06 107.88 0.137 108.192 ;
     RECT  0.084 108.192 0.137 108.216 ;
     RECT  0.06 108.216 0.137 108.528 ;
     RECT  0.084 108.528 0.137 108.552 ;
     RECT  0.06 108.552 0.137 108.864 ;
     RECT  0.084 108.864 0.137 108.888 ;
     RECT  0.06 108.888 0.137 109.2 ;
     RECT  0.084 109.2 0.137 109.224 ;
     RECT  0.06 109.224 0.137 109.536 ;
     RECT  0.084 109.536 0.137 109.56 ;
     RECT  0.084 111.84 0.137 111.864 ;
     RECT  0.06 111.864 0.137 112.176 ;
     RECT  0.084 112.176 0.137 112.2 ;
     RECT  0.06 112.2 0.137 112.512 ;
     RECT  0.084 112.512 0.137 112.536 ;
     RECT  0.06 112.536 0.137 112.848 ;
     RECT  0.084 112.848 0.137 112.872 ;
     RECT  0.06 112.872 0.137 113.184 ;
     RECT  0.084 113.184 0.137 113.208 ;
     RECT  0.06 113.208 0.137 113.52 ;
     RECT  0.084 113.52 0.137 113.544 ;
     RECT  0.06 113.544 0.137 113.856 ;
     RECT  0.084 113.856 0.137 113.88 ;
     RECT  0.06 113.88 0.137 114.144 ;
     RECT  0.084 114.144 0.137 114.168 ;
     RECT  0.06 114.168 0.137 114.48 ;
     RECT  0.084 114.48 0.137 114.504 ;
     RECT  0.06 114.504 0.137 114.816 ;
     RECT  0.084 114.816 0.137 114.84 ;
     RECT  0.06 114.84 0.137 115.152 ;
     RECT  0.084 115.152 0.137 115.176 ;
     RECT  0.06 115.176 0.137 115.488 ;
     RECT  0.084 115.488 0.137 115.512 ;
     RECT  0.06 115.512 0.137 115.824 ;
     RECT  0.084 115.824 0.137 115.848 ;
     RECT  0.084 118.128 0.137 118.152 ;
     RECT  0.06 118.152 0.137 118.464 ;
     RECT  0.084 118.464 0.137 118.488 ;
     RECT  0.06 118.488 0.137 118.8 ;
     RECT  0.084 118.8 0.137 118.824 ;
     RECT  0.06 118.824 0.137 119.136 ;
     RECT  0.084 119.136 0.137 119.16 ;
     RECT  0.06 119.16 0.137 119.472 ;
     RECT  0.084 119.472 0.137 119.496 ;
     RECT  0.06 119.496 0.137 119.808 ;
     RECT  0.084 119.808 0.137 119.832 ;
     RECT  0.06 119.832 0.137 120.144 ;
     RECT  0.084 120.144 0.137 120.168 ;
     RECT  0.06 120.168 0.137 120.432 ;
     RECT  0.084 120.432 0.137 120.456 ;
     RECT  0.06 120.456 0.137 120.768 ;
     RECT  0.084 120.768 0.137 120.792 ;
     RECT  0.06 120.792 0.137 121.104 ;
     RECT  0.084 121.104 0.137 121.128 ;
     RECT  0.06 121.128 0.137 121.44 ;
     RECT  0.084 121.44 0.137 121.464 ;
     RECT  0.06 121.464 0.137 121.776 ;
     RECT  0.084 121.776 0.137 121.8 ;
     RECT  0.06 121.8 0.137 122.112 ;
     RECT  0.084 122.112 0.137 122.136 ;
     RECT  0.06 122.136 0.137 122.448 ;
     RECT  0.084 122.448 0.137 122.472 ;
     RECT  0.06 122.472 0.137 122.784 ;
     RECT  0.084 122.784 0.137 122.808 ;
     RECT  0.06 122.808 0.137 123.072 ;
     RECT  0.084 123.072 0.137 123.096 ;
     RECT  0.137 11.472 0.173 11.496 ;
     RECT  0.137 19.728 0.173 20.424 ;
     RECT  0.137 30.624 0.173 31.32 ;
     RECT  0.137 87.024 0.173 87.72 ;
     RECT  0.137 112.176 0.173 115.176 ;
     RECT  0.137 119.472 0.173 119.832 ;
     RECT  0.137 12.768 0.569 13.128 ;
     RECT  0.137 14.112 0.569 14.76 ;
     RECT  0.137 17.088 0.569 17.448 ;
     RECT  0.173 20.064 0.569 20.424 ;
     RECT  0.173 30.96 0.569 31.32 ;
     RECT  0.137 36.576 0.569 36.888 ;
     RECT  0.137 41.184 0.569 42.168 ;
     RECT  0.137 43.824 0.569 43.848 ;
     RECT  0.137 47.136 0.569 48.12 ;
     RECT  0.137 56.352 0.569 57.048 ;
     RECT  0.137 61.968 0.569 63.624 ;
     RECT  0.137 69.888 0.569 70.248 ;
     RECT  0.137 71.52 0.569 71.88 ;
     RECT  0.137 73.536 0.569 74.856 ;
     RECT  0.137 84.096 0.569 84.12 ;
     RECT  0.137 88.704 0.569 88.728 ;
     RECT  0.137 91.008 0.569 92.328 ;
     RECT  0.137 96.624 0.569 100.248 ;
     RECT  0.137 105.888 0.569 105.912 ;
     RECT  0.137 107.856 0.569 108.216 ;
     RECT  0.173 112.176 0.569 113.88 ;
     RECT  0.137 51.744 2.293 53.064 ;
     RECT  0.569 112.512 2.329 113.88 ;
     RECT  0.137 101.232 2.401 101.256 ;
     RECT  0.569 13.104 2.408 13.128 ;
     RECT  0.569 14.736 2.408 14.76 ;
     RECT  0.569 17.088 2.408 17.112 ;
     RECT  0.569 20.4 2.408 20.424 ;
     RECT  0.137 23.376 2.408 23.4 ;
     RECT  0.137 26.016 2.408 26.664 ;
     RECT  0.137 28.944 2.408 29.64 ;
     RECT  0.569 31.296 2.408 31.32 ;
     RECT  0.137 34.224 2.408 34.248 ;
     RECT  0.569 36.864 2.408 36.888 ;
     RECT  0.137 39.216 2.408 39.864 ;
     RECT  0.569 42.144 2.408 42.168 ;
     RECT  0.137 46.128 2.408 46.152 ;
     RECT  0.569 47.136 2.408 47.784 ;
     RECT  0.137 50.064 2.408 50.088 ;
     RECT  2.293 51.648 2.408 53.064 ;
     RECT  0.137 54.048 2.408 54.072 ;
     RECT  0.569 56.352 2.408 56.376 ;
     RECT  0.137 59.328 2.408 59.352 ;
     RECT  0.137 60.336 2.408 60.984 ;
     RECT  0.569 61.968 2.408 63.288 ;
     RECT  0.137 65.616 2.408 66.6 ;
     RECT  0.569 70.224 2.408 70.248 ;
     RECT  0.569 71.856 2.408 71.88 ;
     RECT  0.569 74.832 2.408 74.856 ;
     RECT  0.137 76.8 2.408 77.832 ;
     RECT  0.137 80.784 2.408 81.48 ;
     RECT  0.137 83.088 2.408 83.112 ;
     RECT  0.173 87.696 2.408 87.72 ;
     RECT  0.569 91.68 2.408 92.328 ;
     RECT  0.137 94.656 2.408 94.68 ;
     RECT  0.569 96.96 2.408 97.32 ;
     RECT  0.569 98.592 2.408 98.616 ;
     RECT  0.569 99.936 2.408 100.248 ;
     RECT  2.401 101.232 2.408 101.928 ;
     RECT  0.569 108.192 2.408 108.216 ;
     RECT  2.329 112.416 2.408 113.88 ;
     RECT  0.173 115.152 2.408 115.176 ;
     RECT  0.137 118.464 2.408 118.488 ;
     RECT  0.173 119.808 2.408 119.832 ;
     RECT  0.137 122.448 2.408 123.096 ;
     RECT  2.408 2.148 2.512 127.452 ;
     RECT  2.512 2.418 2.704 127.182 ;
     RECT  2.704 66.576 2.801 66.6 ;
     RECT  2.704 34.512 2.819 38.712 ;
     RECT  2.704 94.56 2.819 113.592 ;
     RECT  2.704 25.056 2.837 26.232 ;
     RECT  2.704 27.312 2.845 33.384 ;
     RECT  2.819 94.56 2.845 104.904 ;
     RECT  2.845 94.56 2.873 104.376 ;
     RECT  2.704 39.888 2.915 39.912 ;
     RECT  2.704 82.848 2.963 82.872 ;
     RECT  2.873 94.56 3.107 104.04 ;
     RECT  2.704 51.312 3.125 53.784 ;
     RECT  2.704 44.448 3.189 47.352 ;
     RECT  2.704 21.984 3.203 23.736 ;
     RECT  3.125 51.6 3.203 53.784 ;
     RECT  2.704 114.672 3.203 115.176 ;
     RECT  2.704 86.208 3.299 93.192 ;
     RECT  2.704 12.528 3.305 12.552 ;
     RECT  2.704 64.368 3.305 64.392 ;
     RECT  3.203 115.152 3.305 115.176 ;
     RECT  2.845 28.464 3.313 33.384 ;
     RECT  2.704 18.144 3.34 18.168 ;
     RECT  2.704 19.632 3.34 20.424 ;
     RECT  2.704 69.696 3.34 69.72 ;
     RECT  2.704 70.704 3.34 72.168 ;
     RECT  3.107 101.712 3.34 104.04 ;
     RECT  2.819 110.304 3.34 113.592 ;
     RECT  3.34 101.904 3.341 104.04 ;
     RECT  2.837 25.056 3.347 25.896 ;
     RECT  2.704 41.616 3.347 42.984 ;
     RECT  2.704 62.112 3.347 63 ;
     RECT  3.299 89.904 3.347 93.192 ;
     RECT  2.819 105.888 3.347 109.128 ;
     RECT  3.347 62.112 3.349 62.136 ;
     RECT  2.704 73.44 3.349 73.56 ;
     RECT  3.34 70.704 3.377 71.256 ;
     RECT  3.347 25.872 3.395 25.896 ;
     RECT  2.704 56.112 3.395 56.136 ;
     RECT  3.377 70.992 3.395 71.256 ;
     RECT  3.34 110.304 3.395 112.872 ;
     RECT  3.395 111.744 3.413 112.872 ;
     RECT  2.704 84 3.436 85.128 ;
     RECT  3.34 20.4 3.484 20.424 ;
     RECT  2.704 79.824 3.491 81.048 ;
     RECT  3.491 79.824 3.539 79.848 ;
     RECT  2.704 65.52 3.565 65.544 ;
     RECT  3.395 110.304 3.565 110.568 ;
     RECT  3.413 111.744 3.565 112.248 ;
     RECT  3.565 110.304 3.587 110.328 ;
     RECT  2.704 76.32 3.635 76.344 ;
     RECT  2.704 118.56 3.665 119.16 ;
     RECT  2.704 60.96 3.74 60.984 ;
     RECT  2.819 34.56 3.773 38.712 ;
     RECT  3.773 38.016 3.779 38.712 ;
     RECT  3.74 60.96 3.827 61.56 ;
     RECT  3.395 71.232 3.827 71.256 ;
     RECT  3.189 47.04 3.841 47.352 ;
     RECT  2.845 27.312 3.877 27.336 ;
     RECT  3.773 34.56 3.877 37.032 ;
     RECT  3.347 105.888 3.877 108.84 ;
     RECT  3.877 27.216 3.913 27.336 ;
     RECT  3.107 94.56 3.923 100.728 ;
     RECT  3.299 86.208 3.925 88.92 ;
     RECT  3.779 38.112 3.949 38.712 ;
     RECT  3.347 92.976 3.973 93.192 ;
     RECT  3.923 94.56 3.973 97.944 ;
     RECT  3.877 105.648 3.973 108.84 ;
     RECT  3.189 44.448 3.985 45.912 ;
     RECT  3.347 41.616 4.021 42.696 ;
     RECT  3.841 47.04 4.021 47.4 ;
     RECT  2.704 48.432 4.021 49.704 ;
     RECT  3.949 38.112 4.057 38.808 ;
     RECT  3.985 44.4 4.057 45.912 ;
     RECT  2.704 120.24 4.057 120.264 ;
     RECT  4.021 18.768 4.105 18.792 ;
     RECT  4.021 41.328 4.124 42.696 ;
     RECT  3.913 25.968 4.129 27.336 ;
     RECT  3.313 28.464 4.129 32.232 ;
     RECT  3.913 60.384 4.163 60.408 ;
     RECT  4.057 38.112 4.165 39.336 ;
     RECT  4.124 41.232 4.165 42.696 ;
     RECT  2.704 57.6 4.165 58.488 ;
     RECT  3.973 105.504 4.165 108.84 ;
     RECT  4.076 79.632 4.172 79.656 ;
     RECT  4.057 44.208 4.201 45.912 ;
     RECT  3.697 54.624 4.201 54.648 ;
     RECT  3.973 75.936 4.205 75.96 ;
     RECT  4.201 44.064 4.213 45.912 ;
     RECT  4.021 47.04 4.213 49.704 ;
     RECT  3.203 51.648 4.213 53.304 ;
     RECT  4.201 54.576 4.213 54.648 ;
     RECT  3.925 82.704 4.237 82.728 ;
     RECT  2.704 15.36 4.241 15.384 ;
     RECT  4.165 65.808 4.252 65.832 ;
     RECT  4.172 66.912 4.259 66.936 ;
     RECT  3.925 85.872 4.261 88.92 ;
     RECT  3.347 89.904 4.261 91.896 ;
     RECT  3.203 22.752 4.268 23.736 ;
     RECT  4.213 50.832 4.273 54.648 ;
     RECT  4.237 82.032 4.273 82.728 ;
     RECT  3.436 84 4.273 84.648 ;
     RECT  4.127 13.824 4.307 13.848 ;
     RECT  3.805 55.776 4.307 55.896 ;
     RECT  4.201 72.96 4.307 72.984 ;
     RECT  3.805 115.2 4.307 115.896 ;
     RECT  3.665 118.56 4.307 118.584 ;
     RECT  4.213 44.064 4.309 49.704 ;
     RECT  4.273 50.688 4.309 54.648 ;
     RECT  4.237 5.088 4.321 5.112 ;
     RECT  4.129 25.968 4.345 32.232 ;
     RECT  3.827 61.536 4.355 61.56 ;
     RECT  4.237 63.216 4.355 63.24 ;
     RECT  4.237 77.52 4.355 78.072 ;
     RECT  3.341 101.904 4.357 103.896 ;
     RECT  4.165 105.072 4.357 108.84 ;
     RECT  4.268 22.752 4.381 24.312 ;
     RECT  4.237 64.416 4.403 64.44 ;
     RECT  4.381 22.752 4.405 24.984 ;
     RECT  4.309 44.064 4.405 54.648 ;
     RECT  4.307 55.776 4.405 55.8 ;
     RECT  3.565 112.224 4.405 112.248 ;
     RECT  4.261 85.872 4.412 91.896 ;
     RECT  4.405 22.704 4.417 24.984 ;
     RECT  4.345 25.968 4.417 32.472 ;
     RECT  4.165 38.112 4.417 42.696 ;
     RECT  4.405 44.064 4.417 55.8 ;
     RECT  4.165 68.976 4.453 69.528 ;
     RECT  4.357 101.904 4.453 108.84 ;
     RECT  4.057 119.616 4.453 120.264 ;
     RECT  2.704 121.344 4.453 122.616 ;
     RECT  4.453 68.976 4.457 70.104 ;
     RECT  4.412 8.88 4.46 8.904 ;
     RECT  4.417 38.112 4.492 55.8 ;
     RECT  3.973 92.976 4.492 97.944 ;
     RECT  4.46 7.92 4.499 8.904 ;
     RECT  4.412 76.944 4.499 77.304 ;
     RECT  4.492 40.272 4.501 55.8 ;
     RECT  3.491 80.88 4.501 81.048 ;
     RECT  4.492 92.976 4.501 97.608 ;
     RECT  4.417 114.528 4.501 114.552 ;
     RECT  4.165 57.216 4.525 58.488 ;
     RECT  4.501 80.688 4.525 81.048 ;
     RECT  4.273 82.032 4.525 84.648 ;
     RECT  4.412 85.632 4.525 91.896 ;
     RECT  4.405 11.28 4.529 11.304 ;
     RECT  4.417 22.704 4.529 32.472 ;
     RECT  4.501 40.272 4.529 54.648 ;
     RECT  4.457 69.648 4.537 70.104 ;
     RECT  4.529 40.944 4.547 54.648 ;
     RECT  4.525 80.688 4.549 91.896 ;
     RECT  4.501 92.976 4.549 96.552 ;
     RECT  4.453 119.616 4.549 122.616 ;
     RECT  4.529 22.752 4.561 32.472 ;
     RECT  3.877 33.792 4.561 37.032 ;
     RECT  4.525 57.216 4.561 58.872 ;
     RECT  3.923 99.024 4.561 100.728 ;
     RECT  4.453 101.904 4.561 109.896 ;
     RECT  4.561 99.024 4.565 109.896 ;
     RECT  4.501 62.352 4.588 62.376 ;
     RECT  4.501 68.592 4.588 68.616 ;
     RECT  4.537 69.648 4.588 69.672 ;
     RECT  4.549 80.688 4.588 96.552 ;
     RECT  4.565 109.872 4.588 109.896 ;
     RECT  4.499 7.92 4.604 8.376 ;
     RECT  4.237 20.832 4.633 21.096 ;
     RECT  4.405 112.224 4.633 112.344 ;
     RECT  4.597 117.984 4.633 118.008 ;
     RECT  4.549 119.616 4.637 123.096 ;
     RECT  4.561 22.752 4.643 37.032 ;
     RECT  4.307 115.68 4.669 115.896 ;
     RECT  4.604 7.776 4.691 8.376 ;
     RECT  4.561 17.04 4.691 17.16 ;
     RECT  4.604 65.856 4.691 65.88 ;
     RECT  4.604 68.256 4.691 68.28 ;
     RECT  4.633 20.832 4.7 21.72 ;
     RECT  4.172 74.544 4.7 74.568 ;
     RECT  4.172 79.056 4.7 79.656 ;
     RECT  4.405 12.528 4.705 12.552 ;
     RECT  4.547 41.328 4.709 54.648 ;
     RECT  4.633 117.744 4.709 118.008 ;
     RECT  4.669 115.68 4.739 116.232 ;
     RECT  4.705 12.528 4.741 13.08 ;
     RECT  4.637 119.616 4.741 122.52 ;
     RECT  4.7 20.16 4.745 21.72 ;
     RECT  4.588 80.88 4.745 96.552 ;
     RECT  4.705 14.112 4.777 14.232 ;
     RECT  4.633 112.224 4.777 113.016 ;
     RECT  4.501 114.24 4.777 114.552 ;
     RECT  4.643 24.96 4.781 27.912 ;
     RECT  4.691 8.352 4.787 8.376 ;
     RECT  4.745 20.16 4.787 21.672 ;
     RECT  4.7 64.368 4.787 64.392 ;
     RECT  4.7 74.304 4.787 74.568 ;
     RECT  4.741 6.816 4.825 6.84 ;
     RECT  4.741 11.856 4.835 13.08 ;
     RECT  4.781 25.104 4.835 27.912 ;
     RECT  4.745 90.24 4.835 96.552 ;
     RECT  4.691 17.088 4.837 17.16 ;
     RECT  4.777 14.112 4.883 14.808 ;
     RECT  4.837 17.088 4.885 17.64 ;
     RECT  4.844 71.808 4.931 71.832 ;
     RECT  4.835 90.24 4.931 95.976 ;
     RECT  4.565 99.024 4.957 108.888 ;
     RECT  4.709 48.096 4.961 54.648 ;
     RECT  4.885 17.088 4.969 17.736 ;
     RECT  4.739 116.208 4.993 116.232 ;
     RECT  4.709 117.744 4.993 117.768 ;
     RECT  4.709 41.328 4.997 46.92 ;
     RECT  4.94 63.696 5.027 63.72 ;
     RECT  4.844 67.44 5.027 67.464 ;
     RECT  4.787 21.12 5.123 21.672 ;
     RECT  4.561 57.168 5.173 58.872 ;
     RECT  4.957 98.592 5.184 108.888 ;
     RECT  5.173 57.168 5.209 59.112 ;
     RECT  5.123 21.12 5.249 21.432 ;
     RECT  4.835 25.104 5.249 27.816 ;
     RECT  5.184 108.528 5.249 108.888 ;
     RECT  5.249 21.408 5.267 21.432 ;
     RECT  5.249 25.104 5.267 25.656 ;
     RECT  5.029 72.912 5.269 72.936 ;
     RECT  4.492 38.112 5.276 38.952 ;
     RECT  4.501 55.776 5.276 55.8 ;
     RECT  5.209 57.168 5.276 59.304 ;
     RECT  4.499 76.944 5.317 77.016 ;
     RECT  4.7 78.336 5.353 79.656 ;
     RECT  4.643 29.28 5.365 37.032 ;
     RECT  5.276 38.064 5.365 38.952 ;
     RECT  5.125 74.688 5.42 74.712 ;
     RECT  5.353 78.336 5.461 79.848 ;
     RECT  4.643 22.752 5.533 23.928 ;
     RECT  5.365 29.28 5.557 38.952 ;
     RECT  5.461 78.24 5.569 79.848 ;
     RECT  4.745 80.88 5.569 89.16 ;
     RECT  5.497 5.088 5.581 5.112 ;
     RECT  4.969 17.088 5.603 17.64 ;
     RECT  5.132 19.68 5.605 19.704 ;
     RECT  5.276 55.776 5.605 59.304 ;
     RECT  5.605 19.392 5.612 19.704 ;
     RECT  5.557 29.28 5.612 39.384 ;
     RECT  5.533 22.656 5.645 23.928 ;
     RECT  5.612 19.248 5.699 19.704 ;
     RECT  5.42 74.688 5.701 75 ;
     RECT  4.961 48.432 5.713 54.648 ;
     RECT  5.605 55.68 5.713 59.304 ;
     RECT  4.501 97.536 5.721 97.608 ;
     RECT  4.993 116.208 5.741 117.768 ;
     RECT  5.699 19.392 5.747 19.704 ;
     RECT  5.569 78.24 5.749 89.16 ;
     RECT  4.931 90.24 5.749 91.944 ;
     RECT  4.997 41.52 5.785 46.92 ;
     RECT  5.317 62.112 5.785 62.136 ;
     RECT  5.741 116.208 5.785 118.008 ;
     RECT  4.741 119.088 5.785 122.52 ;
     RECT  4.777 111.792 5.789 114.552 ;
     RECT  5.785 116.208 5.789 122.52 ;
     RECT  5.605 64.944 5.795 64.968 ;
     RECT  5.708 67.152 5.795 67.176 ;
     RECT  5.645 23.28 5.821 23.928 ;
     RECT  5.785 62.112 5.821 62.376 ;
     RECT  5.804 65.328 5.891 65.352 ;
     RECT  5.249 26.64 5.893 27.816 ;
     RECT  5.612 28.8 5.893 39.384 ;
     RECT  4.931 92.928 5.893 95.976 ;
     RECT  5.721 96.96 5.893 97.608 ;
     RECT  5.789 116.208 5.897 119.688 ;
     RECT  5.821 23.28 5.905 24.504 ;
     RECT  5.893 26.64 5.929 40.248 ;
     RECT  5.897 116.544 5.939 119.688 ;
     RECT  5.857 7.392 5.941 7.416 ;
     RECT  5.893 92.928 5.941 97.608 ;
     RECT  5.184 98.592 5.941 107.4 ;
     RECT  5.785 41.52 5.965 47.256 ;
     RECT  5.749 78.24 5.965 91.944 ;
     RECT  5.941 92.928 5.965 107.4 ;
     RECT  4.835 12.528 5.969 12.552 ;
     RECT  5.939 116.544 5.969 118.632 ;
     RECT  5.929 26.64 5.98 40.44 ;
     RECT  5.713 48.432 5.987 59.304 ;
     RECT  5.821 61.536 5.987 62.376 ;
     RECT  5.98 40.416 5.989 40.44 ;
     RECT  5.965 41.52 5.989 47.352 ;
     RECT  5.605 69.216 5.989 69.24 ;
     RECT  5.269 72.912 5.996 73.56 ;
     RECT  5.101 124.128 6.001 124.152 ;
     RECT  5.965 78.24 6.005 107.4 ;
     RECT  5.939 119.616 6.005 119.688 ;
     RECT  5.989 40.416 6.013 47.352 ;
     RECT  6.013 40.896 6.035 47.352 ;
     RECT  5.317 76.56 6.037 77.016 ;
     RECT  6.005 78.24 6.037 88.968 ;
     RECT  5.603 17.616 6.073 17.64 ;
     RECT  5.989 69.216 6.073 69.336 ;
     RECT  5.969 116.544 6.077 118.584 ;
     RECT  5.996 8.496 6.083 8.52 ;
     RECT  5.905 23.28 6.083 24.312 ;
     RECT  5.98 26.64 6.083 39.432 ;
     RECT  5.996 66.672 6.083 66.696 ;
     RECT  5.996 72.624 6.083 73.56 ;
     RECT  6.001 123.696 6.085 124.152 ;
     RECT  6.073 68.976 6.109 69.336 ;
     RECT  6.083 73.392 6.131 73.56 ;
     RECT  5.701 74.688 6.14 75.288 ;
     RECT  5.267 25.632 6.157 25.656 ;
     RECT  4.883 14.112 6.179 14.568 ;
     RECT  5.987 48.672 6.217 59.304 ;
     RECT  5.987 62.352 6.217 62.376 ;
     RECT  6.14 74.592 6.227 75.288 ;
     RECT  6.037 76.56 6.227 88.968 ;
     RECT  6.227 76.56 6.253 76.968 ;
     RECT  6.181 66.096 6.265 66.12 ;
     RECT  6.109 68.976 6.275 69.528 ;
     RECT  6.035 43.152 6.289 47.352 ;
     RECT  5.101 110.592 6.293 110.616 ;
     RECT  6.077 116.544 6.329 116.712 ;
     RECT  6.227 75.264 6.337 75.288 ;
     RECT  6.085 124.128 6.361 124.152 ;
     RECT  6.005 90 6.517 107.4 ;
     RECT  6.505 21.072 6.589 21.096 ;
     RECT  6.517 97.536 6.613 107.4 ;
     RECT  5.249 108.576 6.613 108.888 ;
     RECT  6.275 68.976 6.659 69.384 ;
     RECT  6.476 73.92 6.659 74.088 ;
     RECT  6.613 97.536 6.659 108.888 ;
     RECT  6.217 62.352 6.685 62.424 ;
     RECT  5.789 120.672 6.685 122.52 ;
     RECT  6.659 97.536 6.707 107.016 ;
     RECT  6.659 68.976 6.709 69.24 ;
     RECT  6.659 108.096 6.725 108.888 ;
     RECT  5.789 111.792 6.757 112.296 ;
     RECT  5.789 113.28 6.757 114.552 ;
     RECT  6.083 26.64 6.764 27.528 ;
     RECT  6.253 76.464 6.793 76.968 ;
     RECT  6.709 68.256 6.796 69.24 ;
     RECT  6.757 111.792 6.812 114.552 ;
     RECT  6.661 14.784 6.833 14.808 ;
     RECT  6.361 124.128 6.833 124.824 ;
     RECT  6.833 124.224 6.853 124.824 ;
     RECT  6.812 111.408 6.86 114.552 ;
     RECT  6.073 17.616 6.997 17.928 ;
     RECT  6.965 71.28 7.004 71.304 ;
     RECT  6.217 48.672 7.009 59.688 ;
     RECT  6.685 62.352 7.009 62.712 ;
     RECT  6.083 28.944 7.045 39.432 ;
     RECT  6.035 40.896 7.045 41.976 ;
     RECT  5.965 19.968 7.093 19.992 ;
     RECT  7.045 28.944 7.093 41.976 ;
     RECT  6.289 43.152 7.093 47.592 ;
     RECT  7.009 48.672 7.093 60.6 ;
     RECT  7.009 61.968 7.117 62.712 ;
     RECT  6.077 117.744 7.117 118.584 ;
     RECT  6.005 119.664 7.117 119.688 ;
     RECT  7.093 43.152 7.153 60.6 ;
     RECT  7.093 28.848 7.225 41.976 ;
     RECT  7.153 42.96 7.225 60.6 ;
     RECT  6.793 75.648 7.244 76.968 ;
     RECT  6.227 77.952 7.244 88.968 ;
     RECT  7.004 71.28 7.285 71.832 ;
     RECT  7.225 28.848 7.292 60.6 ;
     RECT  6.725 108.816 7.297 108.888 ;
     RECT  7.081 109.968 7.297 109.992 ;
     RECT  6.997 17.52 7.333 17.928 ;
     RECT  7.285 70.656 7.333 71.832 ;
     RECT  6.764 26.16 7.369 27.528 ;
     RECT  7.297 108.816 7.436 109.992 ;
     RECT  6.86 111.408 7.436 114.6 ;
     RECT  7.333 70.224 7.441 71.832 ;
     RECT  7.244 75.648 7.477 88.968 ;
     RECT  6.517 90 7.477 96.312 ;
     RECT  6.329 116.544 7.477 116.568 ;
     RECT  7.117 117.744 7.477 119.688 ;
     RECT  7.369 26.16 7.513 27.672 ;
     RECT  7.292 28.848 7.513 60.984 ;
     RECT  7.117 61.968 7.573 62.856 ;
     RECT  7.1 64.224 7.573 64.248 ;
     RECT  6.659 74.064 7.669 74.088 ;
     RECT  7.477 75.648 7.669 96.312 ;
     RECT  6.613 13.632 7.808 13.656 ;
     RECT  7.333 17.52 7.808 18.264 ;
     RECT  7.093 19.968 7.808 20.76 ;
     RECT  7.189 22.128 7.808 22.152 ;
     RECT  6.083 23.28 7.808 23.928 ;
     RECT  7.513 26.16 7.808 60.984 ;
     RECT  7.573 61.968 7.808 64.248 ;
     RECT  6.796 68.928 7.808 69.24 ;
     RECT  7.441 70.224 7.808 72.888 ;
     RECT  7.669 74.064 7.808 96.312 ;
     RECT  6.707 97.536 7.808 106.584 ;
     RECT  7.436 108.816 7.808 114.6 ;
     RECT  7.477 116.544 7.808 119.688 ;
     RECT  6.685 120.672 7.808 122.856 ;
     RECT  6.853 124.224 7.808 125.592 ;
     RECT  7.808 2.148 7.912 127.452 ;
     RECT  7.912 2.418 8.104 127.182 ;
     RECT  8.104 22.32 8.201 60.6 ;
     RECT  8.104 116.208 8.201 116.568 ;
     RECT  8.104 66.048 8.243 67.704 ;
     RECT  8.201 116.208 8.243 116.472 ;
     RECT  8.104 77.904 8.317 110.52 ;
     RECT  8.243 116.208 8.381 116.28 ;
     RECT  8.104 71.28 8.387 74.088 ;
     RECT  8.104 19.92 8.425 19.944 ;
     RECT  8.104 76.8 8.453 76.824 ;
     RECT  8.381 116.208 8.453 116.232 ;
     RECT  8.243 66.816 8.483 67.704 ;
     RECT  8.387 71.28 8.483 72.84 ;
     RECT  8.104 69.216 8.531 69.528 ;
     RECT  8.483 71.28 8.531 71.304 ;
     RECT  8.104 21.12 8.579 21.144 ;
     RECT  8.104 61.968 8.597 64.392 ;
     RECT  8.201 22.32 8.669 25.56 ;
     RECT  8.201 26.64 8.675 60.6 ;
     RECT  8.387 74.064 8.675 74.088 ;
     RECT  8.104 111.84 8.675 115.176 ;
     RECT  8.675 112.32 8.705 115.176 ;
     RECT  8.104 117.984 8.723 118.008 ;
     RECT  8.669 22.32 8.885 23.784 ;
     RECT  8.705 115.152 9.059 115.176 ;
     RECT  8.104 18.144 9.101 18.264 ;
     RECT  8.885 22.704 9.101 23.784 ;
     RECT  8.104 120.864 9.107 122.136 ;
     RECT  9.101 22.8 9.137 23.688 ;
     RECT  8.483 72.336 9.245 72.84 ;
     RECT  8.317 77.904 9.245 108.168 ;
     RECT  8.104 119.52 9.281 119.544 ;
     RECT  9.205 16.512 9.289 16.536 ;
     RECT  9.245 108.048 9.308 108.168 ;
     RECT  8.317 109.2 9.308 110.52 ;
     RECT  9.245 77.904 9.317 106.68 ;
     RECT  9.317 77.904 9.349 105.48 ;
     RECT  8.669 25.104 9.445 25.56 ;
     RECT  9.133 74.64 9.457 74.664 ;
     RECT  9.359 75.888 9.457 75.912 ;
     RECT  8.705 112.32 9.461 114.024 ;
     RECT  9.349 77.136 9.491 105.48 ;
     RECT  9.457 74.64 9.539 75.912 ;
     RECT  9.565 65.184 9.596 65.208 ;
     RECT  8.597 61.968 9.637 63.816 ;
     RECT  9.596 65.136 9.637 65.208 ;
     RECT  9.596 17.616 9.683 17.64 ;
     RECT  9.637 61.968 9.817 65.208 ;
     RECT  8.483 66.816 9.817 67.56 ;
     RECT  9.491 77.136 9.923 105.192 ;
     RECT  9.445 25.104 9.925 26.136 ;
     RECT  9.709 116.976 9.965 117 ;
     RECT  9.925 24.72 9.997 26.136 ;
     RECT  8.675 27.168 9.997 60.6 ;
     RECT  9.817 61.968 10.001 67.56 ;
     RECT  9.997 24.72 10.028 60.6 ;
     RECT  10.001 61.968 10.028 66.984 ;
     RECT  9.452 72.048 10.033 72.072 ;
     RECT  9.107 121.392 10.033 122.136 ;
     RECT  10.033 71.952 10.117 72.072 ;
     RECT  9.349 18.72 10.141 18.744 ;
     RECT  10.028 24.72 10.163 66.984 ;
     RECT  10.141 18.72 10.177 19.416 ;
     RECT  10.177 18.72 10.213 19.608 ;
     RECT  10.033 121.392 10.213 122.568 ;
     RECT  9.923 77.136 10.22 81.864 ;
     RECT  10.165 116.16 10.253 116.184 ;
     RECT  9.539 74.64 10.261 75.24 ;
     RECT  10.213 121.392 10.261 122.664 ;
     RECT  10.163 24.72 10.289 49.608 ;
     RECT  10.261 74.064 10.307 75.24 ;
     RECT  9.137 22.944 10.321 23.688 ;
     RECT  10.289 24.72 10.321 30.408 ;
     RECT  8.531 69.216 10.321 69.24 ;
     RECT  10.033 70.416 10.321 70.44 ;
     RECT  10.261 121.296 10.348 122.664 ;
     RECT  10.249 72.384 10.355 72.408 ;
     RECT  10.307 74.064 10.405 74.664 ;
     RECT  10.405 73.488 10.433 74.664 ;
     RECT  10.213 18.672 10.453 19.608 ;
     RECT  10.22 76.416 10.501 81.864 ;
     RECT  10.501 76.32 10.505 81.864 ;
     RECT  10.321 69.216 10.537 70.44 ;
     RECT  9.317 106.512 10.537 106.68 ;
     RECT  10.537 106.512 10.573 106.824 ;
     RECT  9.308 108.048 10.573 110.52 ;
     RECT  10.348 122.112 10.595 122.664 ;
     RECT  10.289 31.488 10.613 49.608 ;
     RECT  10.573 106.512 10.645 110.52 ;
     RECT  10.321 22.944 10.649 30.408 ;
     RECT  9.461 112.32 10.717 113.304 ;
     RECT  9.601 21.696 10.753 21.72 ;
     RECT  10.649 22.944 10.753 30.264 ;
     RECT  10.717 112.32 10.753 114.024 ;
     RECT  10.163 50.592 10.757 66.984 ;
     RECT  10.613 31.68 10.793 49.608 ;
     RECT  10.433 74.544 10.801 74.664 ;
     RECT  10.453 18.672 10.825 20.328 ;
     RECT  9.923 83.04 10.861 105.192 ;
     RECT  10.645 106.512 10.861 110.856 ;
     RECT  9.745 120.24 10.865 120.264 ;
     RECT  10.753 21.696 10.897 30.264 ;
     RECT  10.897 21.6 10.901 30.264 ;
     RECT  10.861 83.04 10.901 110.856 ;
     RECT  10.753 111.888 10.933 114.024 ;
     RECT  10.901 26.064 10.937 30.264 ;
     RECT  10.937 26.064 10.973 27.912 ;
     RECT  10.937 28.944 10.973 30.264 ;
     RECT  10.505 76.32 11.029 76.392 ;
     RECT  9.493 118.464 11.041 119.208 ;
     RECT  11.041 118.272 11.045 119.208 ;
     RECT  10.801 74.544 11.075 74.568 ;
     RECT  11.029 75.936 11.116 76.392 ;
     RECT  10.537 69.216 11.117 70.68 ;
     RECT  11.116 76.368 11.125 76.392 ;
     RECT  10.793 31.776 11.149 49.608 ;
     RECT  10.757 50.592 11.149 65.208 ;
     RECT  11.117 69.216 11.153 70.056 ;
     RECT  10.901 86.4 11.173 110.856 ;
     RECT  10.933 111.888 11.173 114.648 ;
     RECT  10.213 16.08 11.221 16.104 ;
     RECT  11.045 118.272 11.249 119.16 ;
     RECT  11.221 16.08 11.257 16.44 ;
     RECT  11.173 86.4 11.261 114.648 ;
     RECT  11.18 72.288 11.267 72.312 ;
     RECT  11.249 117.408 11.333 119.16 ;
     RECT  11.257 15.936 11.341 16.44 ;
     RECT  10.433 73.488 11.365 73.512 ;
     RECT  11.153 69.216 11.411 69.432 ;
     RECT  10.505 77.472 11.441 81.864 ;
     RECT  11.261 86.4 11.441 110.856 ;
     RECT  11.149 31.776 11.459 65.208 ;
     RECT  11.441 80.736 11.509 81.864 ;
     RECT  10.901 83.04 11.509 85.368 ;
     RECT  11.261 111.888 11.513 114.648 ;
     RECT  10.825 17.952 11.585 20.328 ;
     RECT  10.595 122.4 11.605 122.664 ;
     RECT  11.513 112.608 11.617 114.648 ;
     RECT  11.459 31.776 11.644 64.2 ;
     RECT  11.365 72.576 11.651 73.512 ;
     RECT  11.651 72.912 11.653 73.512 ;
     RECT  11.605 121.968 11.693 122.664 ;
     RECT  11.644 31.776 11.699 63.816 ;
     RECT  11.653 72.912 11.747 74.328 ;
     RECT  10.901 21.6 11.833 25.032 ;
     RECT  11.585 20.304 11.869 20.328 ;
     RECT  11.833 21.504 11.869 25.032 ;
     RECT  11.459 65.184 11.891 65.208 ;
     RECT  10.757 66.528 11.941 66.984 ;
     RECT  10.465 68.064 11.941 68.232 ;
     RECT  11.617 71.376 11.945 71.4 ;
     RECT  11.509 80.736 11.977 85.368 ;
     RECT  11.441 86.4 11.977 103.848 ;
     RECT  10.973 28.944 11.989 28.968 ;
     RECT  11.699 31.776 11.989 63.576 ;
     RECT  11.747 74.112 12.044 74.328 ;
     RECT  11.989 31.344 12.097 63.576 ;
     RECT  12.044 74.112 12.179 74.664 ;
     RECT  10.973 26.112 12.197 27.912 ;
     RECT  11.869 20.304 12.229 25.032 ;
     RECT  12.197 26.112 12.229 26.136 ;
     RECT  12.197 27.12 12.229 27.912 ;
     RECT  11.989 28.944 12.229 29.064 ;
     RECT  10.973 30.24 12.265 30.264 ;
     RECT  12.097 31.344 12.265 31.752 ;
     RECT  12.121 76.368 12.265 76.392 ;
     RECT  11.441 77.472 12.265 79.704 ;
     RECT  12.265 30.24 12.301 31.752 ;
     RECT  11.441 105.072 12.337 110.856 ;
     RECT  12.265 76.368 12.373 79.704 ;
     RECT  11.333 118.272 12.373 119.16 ;
     RECT  11.941 66.528 12.409 68.232 ;
     RECT  11.411 69.216 12.409 69.24 ;
     RECT  12.373 76.224 12.409 79.704 ;
     RECT  11.977 80.736 12.409 103.848 ;
     RECT  12.229 27.12 12.445 29.064 ;
     RECT  12.301 30.048 12.445 31.752 ;
     RECT  11.617 112.608 12.445 115.176 ;
     RECT  12.049 116.256 12.445 116.28 ;
     RECT  12.409 66.528 12.469 69.24 ;
     RECT  12.373 118.272 12.553 119.784 ;
     RECT  12.337 105.072 12.613 111.624 ;
     RECT  12.445 112.608 12.613 116.28 ;
     RECT  12.409 76.224 12.697 103.848 ;
     RECT  12.613 105.072 12.697 116.28 ;
     RECT  12.097 32.736 12.769 63.576 ;
     RECT  12.661 64.656 12.769 64.68 ;
     RECT  11.341 16.08 12.805 16.44 ;
     RECT  11.747 72.912 12.853 72.984 ;
     RECT  12.697 76.224 12.853 116.28 ;
     RECT  12.769 32.736 12.877 64.68 ;
     RECT  12.589 121.104 12.949 121.128 ;
     RECT  11.693 122.4 12.949 122.664 ;
     RECT  11.585 17.952 13.093 19.32 ;
     RECT  12.229 20.304 13.093 26.136 ;
     RECT  12.553 118.128 13.093 119.784 ;
     RECT  12.805 15.984 13.129 16.44 ;
     RECT  12.949 121.104 13.129 122.664 ;
     RECT  13.129 120.816 13.201 122.664 ;
     RECT  13.129 15.984 13.208 16.584 ;
     RECT  13.093 17.952 13.208 26.136 ;
     RECT  12.445 27.12 13.208 31.752 ;
     RECT  12.877 32.736 13.208 64.968 ;
     RECT  12.469 66.096 13.208 69.24 ;
     RECT  12.428 70.368 13.208 70.392 ;
     RECT  12.853 72.912 13.208 73.512 ;
     RECT  12.853 74.976 13.208 75 ;
     RECT  12.853 76.176 13.208 116.28 ;
     RECT  13.093 117.408 13.208 119.784 ;
     RECT  13.201 120.768 13.208 122.664 ;
     RECT  13.208 2.148 13.312 127.452 ;
     RECT  13.312 2.418 13.504 127.182 ;
     RECT  13.504 115.728 13.619 116.472 ;
     RECT  13.504 73.968 13.667 74.52 ;
     RECT  13.504 77.904 13.667 114.696 ;
     RECT  13.504 17.952 13.673 19.32 ;
     RECT  13.619 115.728 13.673 116.28 ;
     RECT  13.504 118.128 13.673 119.016 ;
     RECT  13.504 120.768 13.853 122.664 ;
     RECT  13.504 72.384 13.859 72.984 ;
     RECT  13.504 21.072 13.861 31.8 ;
     RECT  13.673 118.128 13.955 118.584 ;
     RECT  13.667 77.904 14.033 110.904 ;
     RECT  13.667 111.888 14.069 114.696 ;
     RECT  13.667 73.968 14.099 73.992 ;
     RECT  13.853 121.104 14.141 122.664 ;
     RECT  14.033 77.904 14.147 97.608 ;
     RECT  13.673 18.144 14.177 19.32 ;
     RECT  13.673 115.728 14.365 115.752 ;
     RECT  13.504 33.216 14.387 71.304 ;
     RECT  13.861 21.264 14.393 31.8 ;
     RECT  14.141 121.104 14.465 122.568 ;
     RECT  14.387 33.936 14.537 71.304 ;
     RECT  13.504 15.984 14.605 16.584 ;
     RECT  14.537 33.936 14.609 70.872 ;
     RECT  14.609 70.272 14.645 70.776 ;
     RECT  13.859 72.672 14.645 72.984 ;
     RECT  14.033 98.64 14.749 110.904 ;
     RECT  14.069 111.888 14.749 112.776 ;
     RECT  14.393 21.648 14.785 31.8 ;
     RECT  14.773 19.92 14.861 19.944 ;
     RECT  14.785 21.648 14.861 32.04 ;
     RECT  13.504 76.896 14.876 76.92 ;
     RECT  14.177 18.144 14.897 18.84 ;
     RECT  14.897 18.144 14.933 18.744 ;
     RECT  14.876 76.656 14.963 76.92 ;
     RECT  13.955 118.128 14.965 118.152 ;
     RECT  14.861 25.008 15.001 32.04 ;
     RECT  14.465 121.104 15.001 122.424 ;
     RECT  14.933 18.432 15.005 18.744 ;
     RECT  14.929 116.208 15.013 116.328 ;
     RECT  14.749 98.64 15.077 112.776 ;
     RECT  14.605 15.984 15.109 16.68 ;
     RECT  14.876 75.024 15.109 75.048 ;
     RECT  15.001 25.008 15.116 32.232 ;
     RECT  14.645 70.272 15.157 70.68 ;
     RECT  15.001 120.864 15.181 122.424 ;
     RECT  14.963 76.896 15.185 76.92 ;
     RECT  15.116 25.008 15.203 32.376 ;
     RECT  15.109 75.024 15.299 75.576 ;
     RECT  14.609 33.936 15.329 69.24 ;
     RECT  14.965 117.408 15.361 118.152 ;
     RECT  15.329 33.936 15.433 41.64 ;
     RECT  14.069 113.808 15.433 114.696 ;
     RECT  15.005 18.432 15.437 18.456 ;
     RECT  14.147 77.904 15.469 97.56 ;
     RECT  15.077 98.64 15.469 106.776 ;
     RECT  15.433 113.808 15.469 115.224 ;
     RECT  15.013 116.208 15.469 116.232 ;
     RECT  15.452 74.592 15.493 74.616 ;
     RECT  14.861 21.648 15.5 23.688 ;
     RECT  15.493 74.112 15.539 74.616 ;
     RECT  15.433 33.456 15.587 41.64 ;
     RECT  15.539 74.112 15.683 74.136 ;
     RECT  15.181 120.192 15.689 122.424 ;
     RECT  15.077 107.808 15.865 112.776 ;
     RECT  15.469 113.808 15.865 116.232 ;
     RECT  15.973 20.592 16.009 20.616 ;
     RECT  15.5 21.6 16.009 23.688 ;
     RECT  15.469 77.904 16.045 106.776 ;
     RECT  15.865 107.808 16.045 116.232 ;
     RECT  15.329 42.624 16.069 69.24 ;
     RECT  16.045 77.904 16.157 116.232 ;
     RECT  15.203 25.008 16.225 32.232 ;
     RECT  16.009 20.592 16.261 23.688 ;
     RECT  16.225 25.008 16.261 32.376 ;
     RECT  16.261 20.592 16.265 32.376 ;
     RECT  16.069 42.624 16.365 69.768 ;
     RECT  15.109 15.984 16.405 16.776 ;
     RECT  15.361 117.408 16.405 118.92 ;
     RECT  16.157 77.904 16.445 115.656 ;
     RECT  15.689 120.624 16.547 122.424 ;
     RECT  16.365 42.624 16.549 69.24 ;
     RECT  15.587 33.456 16.748 41.592 ;
     RECT  16.549 42.576 16.748 69.24 ;
     RECT  16.748 33.456 16.801 69.24 ;
     RECT  16.405 117.408 16.837 118.968 ;
     RECT  16.405 15.984 16.841 17.16 ;
     RECT  16.117 19.008 16.945 19.032 ;
     RECT  16.837 117.408 16.973 119.544 ;
     RECT  16.945 19.008 17.053 19.224 ;
     RECT  16.265 20.592 17.053 21.672 ;
     RECT  16.547 121.632 17.053 122.424 ;
     RECT  16.981 123.456 17.053 123.48 ;
     RECT  16.801 33.36 17.165 69.24 ;
     RECT  16.445 92.448 17.197 115.656 ;
     RECT  16.973 116.88 17.197 119.544 ;
     RECT  16.265 22.8 17.221 32.376 ;
     RECT  17.165 33.36 17.221 65.544 ;
     RECT  17.053 19.008 17.372 21.672 ;
     RECT  17.221 22.8 17.372 65.544 ;
     RECT  16.841 15.984 17.453 16.92 ;
     RECT  17.372 19.008 17.459 65.544 ;
     RECT  17.459 19.008 17.585 21.576 ;
     RECT  17.453 15.984 17.597 16.632 ;
     RECT  16.445 77.904 17.653 91.176 ;
     RECT  17.653 77.904 17.66 91.464 ;
     RECT  17.66 77.712 17.701 91.464 ;
     RECT  17.197 92.448 17.773 119.544 ;
     RECT  16.547 120.624 17.773 120.648 ;
     RECT  17.773 92.448 17.893 120.648 ;
     RECT  17.053 121.632 17.893 123.48 ;
     RECT  17.165 66.816 18.133 69.24 ;
     RECT  17.701 77.52 18.284 91.464 ;
     RECT  17.893 92.448 18.284 123.48 ;
     RECT  17.597 15.984 18.608 16.056 ;
     RECT  17.585 18.192 18.608 21.576 ;
     RECT  17.459 22.8 18.608 65.544 ;
     RECT  18.133 66.72 18.608 69.24 ;
     RECT  14.645 72.672 18.608 72.696 ;
     RECT  17.881 76.224 18.608 76.248 ;
     RECT  18.284 77.52 18.608 123.48 ;
     RECT  13.504 124.608 18.608 124.632 ;
     RECT  18.608 2.148 18.712 127.452 ;
     RECT  18.712 2.418 18.904 127.182 ;
     RECT  18.904 117.504 19.001 120.072 ;
     RECT  18.904 75.216 19.045 79.8 ;
     RECT  18.904 81.216 19.091 92.664 ;
     RECT  19.091 81.216 19.139 86.856 ;
     RECT  18.904 93.792 19.187 94.92 ;
     RECT  19.091 87.84 19.283 92.664 ;
     RECT  19.139 81.216 19.379 83.592 ;
     RECT  18.904 36.672 19.42 70.728 ;
     RECT  19.283 90.144 19.433 92.664 ;
     RECT  19.187 94.32 19.469 94.92 ;
     RECT  19.433 90.144 19.505 91.656 ;
     RECT  18.904 121.344 19.505 122.52 ;
     RECT  19.283 88.224 19.613 88.68 ;
     RECT  18.904 95.904 19.613 116.472 ;
     RECT  19.613 96.192 19.619 96.936 ;
     RECT  19.379 81.216 19.667 82.008 ;
     RECT  18.904 18.24 19.685 35.304 ;
     RECT  19.505 90.144 19.721 90.36 ;
     RECT  19.505 91.632 19.757 91.656 ;
     RECT  19.433 92.64 19.757 92.664 ;
     RECT  19.685 18.48 19.811 35.304 ;
     RECT  19.42 37.152 19.811 70.728 ;
     RECT  19.667 81.216 19.811 81.528 ;
     RECT  19.045 75.216 19.873 79.56 ;
     RECT  18.904 16.032 19.897 16.2 ;
     RECT  19.811 70.704 19.909 70.728 ;
     RECT  19.619 96.816 19.973 96.936 ;
     RECT  19.897 15.936 19.981 16.2 ;
     RECT  19.981 16.08 20.005 16.2 ;
     RECT  19.811 32.496 20.005 35.304 ;
     RECT  19.613 98.304 20.005 116.472 ;
     RECT  19.001 117.504 20.005 118.968 ;
     RECT  19.505 121.392 20.077 122.52 ;
     RECT  20.005 16.08 20.113 17.064 ;
     RECT  20.077 121.392 20.117 123.48 ;
     RECT  20.005 98.304 20.189 118.968 ;
     RECT  19.811 37.152 20.225 69.24 ;
     RECT  20.113 16.08 20.293 17.16 ;
     RECT  20.189 117.504 20.329 118.968 ;
     RECT  19.001 119.952 20.329 120.072 ;
     RECT  19.811 81.216 20.348 81.24 ;
     RECT  19.811 18.48 20.405 31.368 ;
     RECT  20.348 80.832 20.435 81.24 ;
     RECT  20.005 32.496 20.449 35.784 ;
     RECT  20.449 32.832 20.473 35.784 ;
     RECT  20.225 38.064 20.621 69.24 ;
     RECT  19.973 96.912 20.653 96.936 ;
     RECT  20.189 98.304 20.653 116.52 ;
     RECT  20.617 92.928 20.729 92.952 ;
     RECT  20.329 117.504 20.797 120.072 ;
     RECT  20.725 91.728 20.809 91.752 ;
     RECT  19.873 75.264 20.819 79.56 ;
     RECT  20.117 121.392 20.837 121.992 ;
     RECT  20.819 75.264 20.867 76.248 ;
     RECT  20.819 77.904 20.867 79.56 ;
     RECT  18.904 71.856 20.915 72.696 ;
     RECT  19.139 84.624 21.011 86.856 ;
     RECT  20.117 123.456 21.013 123.48 ;
     RECT  20.837 121.392 21.017 121.896 ;
     RECT  20.797 117.504 21.049 120.312 ;
     RECT  21.017 121.392 21.049 121.752 ;
     RECT  20.405 20.304 21.121 31.368 ;
     RECT  20.405 18.48 21.155 19.272 ;
     RECT  21.011 84.624 21.299 86.232 ;
     RECT  20.621 38.064 21.337 39.624 ;
     RECT  20.867 75.264 21.395 75.288 ;
     RECT  20.867 77.904 21.395 78.504 ;
     RECT  19.379 83.04 21.443 83.592 ;
     RECT  21.049 117.504 21.449 121.752 ;
     RECT  21.121 20.304 21.481 31.656 ;
     RECT  20.621 40.656 21.539 69.24 ;
     RECT  21.443 83.568 21.587 83.592 ;
     RECT  20.293 16.08 21.589 17.496 ;
     RECT  20.653 96.912 21.589 116.52 ;
     RECT  21.449 117.504 21.589 120.648 ;
     RECT  21.337 37.968 21.625 39.624 ;
     RECT  21.481 19.488 21.676 31.656 ;
     RECT  21.676 20.064 21.697 31.656 ;
     RECT  20.473 32.832 21.697 36.072 ;
     RECT  21.589 96.912 21.701 120.648 ;
     RECT  21.589 15.936 21.845 17.496 ;
     RECT  21.701 96.912 21.845 113.88 ;
     RECT  21.845 15.936 21.881 17.208 ;
     RECT  21.013 123.456 21.913 123.528 ;
     RECT  20.915 71.856 21.923 71.88 ;
     RECT  21.395 77.904 21.923 77.928 ;
     RECT  21.881 15.936 21.989 17.16 ;
     RECT  21.913 123.216 22.021 123.528 ;
     RECT  21.625 37.776 22.093 39.624 ;
     RECT  21.155 18.48 22.201 18.504 ;
     RECT  22.093 37.68 22.201 39.624 ;
     RECT  21.539 40.656 22.201 68.616 ;
     RECT  21.449 121.728 22.237 121.752 ;
     RECT  22.021 122.736 22.237 123.528 ;
     RECT  21.701 114.864 22.349 120.408 ;
     RECT  22.201 18.192 22.381 18.504 ;
     RECT  22.237 121.728 22.421 123.528 ;
     RECT  21.989 16.08 22.457 17.16 ;
     RECT  21.697 20.064 22.597 36.072 ;
     RECT  22.421 121.728 22.741 121.752 ;
     RECT  22.349 114.864 22.813 117.528 ;
     RECT  22.597 20.064 22.896 36.168 ;
     RECT  22.201 37.68 22.896 68.616 ;
     RECT  22.381 18.192 22.921 18.696 ;
     RECT  22.457 16.08 22.961 16.584 ;
     RECT  22.896 20.064 22.968 68.616 ;
     RECT  20.867 79.536 22.968 79.56 ;
     RECT  20.435 81.216 22.968 81.24 ;
     RECT  21.299 84.624 22.968 85.272 ;
     RECT  19.613 88.224 22.968 88.632 ;
     RECT  19.721 90.144 22.968 90.168 ;
     RECT  19.469 94.896 22.968 94.92 ;
     RECT  21.845 97.488 22.968 113.832 ;
     RECT  22.921 18.192 23.029 18.792 ;
     RECT  22.968 20.064 23.029 113.832 ;
     RECT  22.813 114.816 23.029 117.528 ;
     RECT  23.029 20.064 23.317 117.528 ;
     RECT  22.349 118.56 23.317 120.408 ;
     RECT  22.421 122.736 23.317 123.528 ;
     RECT  18.904 124.608 23.317 124.632 ;
     RECT  23.317 20.064 23.353 120.408 ;
     RECT  22.741 121.536 23.353 121.752 ;
     RECT  23.353 20.064 23.564 121.752 ;
     RECT  22.961 16.08 23.605 16.104 ;
     RECT  20.821 13.344 24.008 13.368 ;
     RECT  23.605 15.84 24.008 16.104 ;
     RECT  23.029 17.76 24.008 18.792 ;
     RECT  23.564 19.776 24.008 121.752 ;
     RECT  23.317 122.736 24.008 124.632 ;
     RECT  24.008 2.148 24.112 127.452 ;
     RECT  24.112 2.418 24.304 127.182 ;
     RECT  24.304 15.984 24.473 19.032 ;
     RECT  24.304 20.352 24.515 124.632 ;
     RECT  24.473 16.08 24.563 19.032 ;
     RECT  24.563 16.08 24.617 16.248 ;
     RECT  24.515 20.352 24.761 123.288 ;
     RECT  24.761 20.352 25.013 120.504 ;
     RECT  24.761 121.536 25.373 123.288 ;
     RECT  24.563 17.328 25.765 19.032 ;
     RECT  25.013 20.352 25.765 120.072 ;
     RECT  24.617 16.08 26.021 16.104 ;
     RECT  25.373 122.544 26.089 123.288 ;
     RECT  25.765 17.328 26.149 120.072 ;
     RECT  26.149 17.088 26.269 120.072 ;
     RECT  25.373 121.536 26.269 121.56 ;
     RECT  26.269 17.088 26.273 121.56 ;
     RECT  26.273 17.088 26.345 20.376 ;
     RECT  26.273 21.36 26.485 121.56 ;
     RECT  26.089 122.544 26.485 123.528 ;
     RECT  26.485 21.36 26.531 123.528 ;
     RECT  26.531 123.168 26.633 123.528 ;
     RECT  26.345 17.136 26.957 20.376 ;
     RECT  26.531 21.36 26.993 121.992 ;
     RECT  26.957 17.136 27.029 20.184 ;
     RECT  27.029 17.136 27.173 19.608 ;
     RECT  26.993 21.984 27.637 121.992 ;
     RECT  26.633 123.504 27.637 123.528 ;
     RECT  27.637 21.984 27.817 123.528 ;
     RECT  24.515 124.608 27.817 124.632 ;
     RECT  27.173 17.136 27.929 18.504 ;
     RECT  27.493 15.936 27.965 15.96 ;
     RECT  27.173 19.488 28.067 19.608 ;
     RECT  27.817 21.984 28.285 124.632 ;
     RECT  27.929 17.136 28.429 17.448 ;
     RECT  28.285 21.36 29.185 124.632 ;
     RECT  24.304 13.344 29.408 13.368 ;
     RECT  28.429 16.512 29.408 17.448 ;
     RECT  27.929 18.48 29.408 18.504 ;
     RECT  28.067 19.584 29.408 19.608 ;
     RECT  29.185 20.928 29.408 124.632 ;
     RECT  29.408 2.148 29.512 127.452 ;
     RECT  29.512 2.418 29.704 127.182 ;
     RECT  29.704 121.872 29.873 123.24 ;
     RECT  29.704 20.496 29.945 120.84 ;
     RECT  29.873 121.872 30.089 122.952 ;
     RECT  29.945 20.496 30.125 120.792 ;
     RECT  29.704 17.136 30.131 17.64 ;
     RECT  30.131 17.616 30.341 17.64 ;
     RECT  30.125 20.496 30.709 120.6 ;
     RECT  30.709 19.632 30.755 120.6 ;
     RECT  30.755 19.632 30.845 19.656 ;
     RECT  30.755 20.928 30.917 120.6 ;
     RECT  30.917 21.12 31.061 120.6 ;
     RECT  29.704 124.608 31.129 124.632 ;
     RECT  31.061 21.552 31.309 120.6 ;
     RECT  30.089 121.872 31.309 122.712 ;
     RECT  31.309 21.552 31.313 122.712 ;
     RECT  31.313 121.104 31.345 122.712 ;
     RECT  31.129 124.608 31.345 125.112 ;
     RECT  31.313 21.552 31.493 119.976 ;
     RECT  31.493 21.552 31.907 21.672 ;
     RECT  31.345 121.104 31.964 123.336 ;
     RECT  31.345 124.32 31.964 125.112 ;
     RECT  31.964 121.104 32.051 125.112 ;
     RECT  31.907 21.648 32.069 21.672 ;
     RECT  32.051 121.104 32.147 122.712 ;
     RECT  32.147 121.104 32.177 122.52 ;
     RECT  31.453 18.192 32.389 18.216 ;
     RECT  32.389 18.192 32.435 18.984 ;
     RECT  31.957 19.968 32.435 19.992 ;
     RECT  32.435 18.576 32.476 18.984 ;
     RECT  32.051 124.368 32.573 125.112 ;
     RECT  31.493 22.752 32.785 119.976 ;
     RECT  32.177 121.104 32.785 121.992 ;
     RECT  32.476 18.576 32.915 18.6 ;
     RECT  32.869 21.36 33.005 21.384 ;
     RECT  32.785 22.752 33.637 121.992 ;
     RECT  32.573 124.368 33.689 124.824 ;
     RECT  33.637 22.464 34.117 121.992 ;
     RECT  33.689 124.368 34.189 124.632 ;
     RECT  34.117 21.984 34.441 121.992 ;
     RECT  34.441 21.984 34.729 122.232 ;
     RECT  29.704 13.344 34.808 13.368 ;
     RECT  34.261 20.976 34.808 21 ;
     RECT  34.729 21.984 34.808 122.712 ;
     RECT  34.189 124.272 34.808 124.632 ;
     RECT  34.808 2.148 34.912 127.452 ;
     RECT  34.912 2.418 35.104 127.182 ;
     RECT  35.104 20.976 35.165 124.632 ;
     RECT  35.165 21.696 36.353 124.632 ;
     RECT  36.353 21.696 36.493 122.376 ;
     RECT  36.353 123.456 36.673 124.632 ;
     RECT  36.493 21.264 37.043 122.376 ;
     RECT  37.043 21.264 37.217 21.72 ;
     RECT  37.043 22.752 37.217 122.376 ;
     RECT  37.217 22.752 37.793 121.416 ;
     RECT  36.673 123.456 38.117 125.112 ;
     RECT  38.117 123.456 38.257 124.632 ;
     RECT  37.217 21.264 38.297 21.288 ;
     RECT  37.793 120.24 38.365 121.416 ;
     RECT  37.793 22.752 38.54 119.16 ;
     RECT  38.257 123.12 38.545 124.632 ;
     RECT  38.545 122.976 38.581 124.632 ;
     RECT  38.54 22.176 38.627 119.16 ;
     RECT  38.627 23.04 38.821 119.16 ;
     RECT  38.365 120.24 38.905 121.464 ;
     RECT  38.581 122.496 38.905 124.632 ;
     RECT  38.821 23.04 39.589 119.208 ;
     RECT  38.905 120.24 39.589 124.632 ;
     RECT  39.589 23.04 39.733 124.632 ;
     RECT  35.104 13.344 40.208 13.368 ;
     RECT  39.733 23.04 40.208 125.112 ;
     RECT  40.208 2.148 40.312 127.452 ;
     RECT  40.312 2.418 40.504 127.182 ;
     RECT  40.504 23.04 41.141 125.112 ;
     RECT  41.141 23.04 41.357 121.704 ;
     RECT  41.141 122.832 41.509 125.112 ;
     RECT  41.509 122.832 41.596 125.64 ;
     RECT  41.357 23.088 42.109 121.704 ;
     RECT  41.596 122.832 42.109 124.776 ;
     RECT  42.109 23.088 42.293 124.776 ;
     RECT  42.293 121.968 42.833 124.776 ;
     RECT  42.833 122.784 42.937 124.776 ;
     RECT  42.293 23.088 43.297 120.792 ;
     RECT  42.937 122.784 43.549 125.352 ;
     RECT  43.549 122.784 43.861 125.4 ;
     RECT  43.297 23.088 43.981 121.32 ;
     RECT  43.861 122.784 43.981 126.024 ;
     RECT  43.981 23.088 45.385 126.024 ;
     RECT  40.504 13.344 45.608 13.368 ;
     RECT  45.385 23.088 45.608 126.168 ;
     RECT  45.608 2.148 45.712 127.452 ;
     RECT  45.712 2.418 45.904 127.182 ;
     RECT  45.904 23.088 46.355 126.168 ;
     RECT  46.355 121.056 46.739 126.168 ;
     RECT  46.739 122.592 47.333 125.976 ;
     RECT  47.333 122.64 47.869 125.976 ;
     RECT  46.739 121.056 47.909 121.368 ;
     RECT  47.869 122.64 47.909 126.6 ;
     RECT  47.909 122.64 47.945 125.352 ;
     RECT  47.945 122.64 48.413 125.112 ;
     RECT  48.413 122.64 48.589 124.632 ;
     RECT  46.355 23.088 48.805 120.072 ;
     RECT  48.049 121.488 49.021 121.512 ;
     RECT  48.589 122.496 49.021 124.632 ;
     RECT  47.909 126.576 49.205 126.6 ;
     RECT  48.805 23.088 49.237 120.36 ;
     RECT  49.021 121.488 49.237 124.632 ;
     RECT  49.237 23.088 50.003 124.632 ;
     RECT  50.003 122.784 50.641 124.632 ;
     RECT  50.641 122.784 50.713 124.968 ;
     RECT  49.237 125.952 50.713 126.552 ;
     RECT  45.904 13.344 51.008 13.368 ;
     RECT  50.003 23.088 51.008 121.512 ;
     RECT  50.713 122.784 51.008 126.552 ;
     RECT  51.008 2.148 51.112 127.452 ;
     RECT  51.112 2.418 51.304 127.182 ;
     RECT  51.304 23.088 52.259 126.024 ;
     RECT  52.259 23.088 52.589 121.992 ;
     RECT  52.259 123.36 53.269 126.024 ;
     RECT  53.269 122.88 53.453 126.024 ;
     RECT  53.453 122.88 53.459 125.592 ;
     RECT  53.459 123.264 53.813 125.592 ;
     RECT  52.589 23.088 54.061 121.368 ;
     RECT  54.061 23.088 54.389 121.608 ;
     RECT  53.813 123.264 54.611 124.968 ;
     RECT  54.611 123.264 54.637 124.632 ;
     RECT  54.637 122.448 54.929 124.632 ;
     RECT  54.929 122.448 55.037 122.472 ;
     RECT  54.389 23.088 55.573 120.792 ;
     RECT  54.929 123.456 55.969 124.632 ;
     RECT  51.304 13.344 56.408 13.368 ;
     RECT  55.573 23.088 56.408 120.888 ;
     RECT  56.113 121.92 56.408 121.944 ;
     RECT  55.969 123.456 56.408 124.92 ;
     RECT  56.408 2.148 56.512 127.452 ;
     RECT  56.512 2.418 56.704 127.182 ;
     RECT  56.704 23.088 56.819 125.064 ;
     RECT  56.819 122.208 56.873 125.064 ;
     RECT  56.873 122.4 57.053 125.064 ;
     RECT  57.053 122.4 57.161 124.632 ;
     RECT  56.819 23.088 57.557 121.176 ;
     RECT  57.161 122.784 57.587 124.632 ;
     RECT  57.587 122.784 58.169 122.952 ;
     RECT  58.169 122.784 58.501 122.808 ;
     RECT  57.587 124.224 58.669 124.632 ;
     RECT  57.557 23.088 58.849 120.936 ;
     RECT  58.669 124.224 59.137 125.112 ;
     RECT  58.849 23.088 59.141 121.464 ;
     RECT  59.141 121.44 59.177 121.464 ;
     RECT  58.501 122.544 59.276 122.808 ;
     RECT  59.137 124.224 59.276 125.448 ;
     RECT  59.276 122.544 59.317 125.448 ;
     RECT  59.317 122.496 59.429 125.448 ;
     RECT  59.429 122.496 59.893 122.664 ;
     RECT  59.141 23.088 60.221 120.36 ;
     RECT  59.893 121.728 60.476 122.664 ;
     RECT  60.476 121.632 61.009 122.664 ;
     RECT  59.429 123.696 61.009 125.448 ;
     RECT  61.009 121.632 61.189 125.448 ;
     RECT  60.221 23.088 61.225 120.12 ;
     RECT  61.225 23.088 61.441 120.456 ;
     RECT  61.189 121.584 61.441 125.448 ;
     RECT  56.704 13.344 61.808 13.368 ;
     RECT  61.441 23.088 61.808 125.448 ;
     RECT  61.808 2.148 61.912 127.452 ;
     RECT  61.912 2.418 62.104 127.182 ;
     RECT  62.104 23.088 62.165 120.552 ;
     RECT  62.104 121.632 62.381 124.632 ;
     RECT  62.165 23.088 63.133 120.072 ;
     RECT  62.381 123.84 63.389 124.632 ;
     RECT  62.381 121.632 63.529 122.52 ;
     RECT  63.389 124.416 63.749 124.632 ;
     RECT  63.133 23.088 63.961 120.312 ;
     RECT  63.529 121.392 63.961 122.52 ;
     RECT  63.749 124.608 64.429 124.632 ;
     RECT  63.961 23.088 64.937 123.336 ;
     RECT  64.937 23.088 65.045 120.216 ;
     RECT  65.045 23.088 65.153 120.024 ;
     RECT  64.937 121.584 65.185 123.336 ;
     RECT  64.429 124.608 65.477 124.872 ;
     RECT  65.153 23.088 65.585 119.976 ;
     RECT  65.185 121.584 65.585 123.624 ;
     RECT  65.585 123.024 66.445 123.624 ;
     RECT  65.477 124.608 66.445 124.632 ;
     RECT  65.585 23.088 67.021 119.16 ;
     RECT  62.104 13.344 67.208 13.368 ;
     RECT  67.021 23.088 67.208 119.688 ;
     RECT  65.585 121.584 67.208 121.992 ;
     RECT  66.445 123.024 67.208 124.632 ;
     RECT  67.208 2.148 67.312 127.452 ;
     RECT  67.312 2.418 67.504 127.182 ;
     RECT  67.504 23.088 67.601 124.632 ;
     RECT  67.601 23.088 67.781 122.184 ;
     RECT  67.781 121.584 68.573 122.184 ;
     RECT  68.573 121.584 68.645 121.608 ;
     RECT  67.781 23.088 68.749 120.6 ;
     RECT  67.601 123.216 69.721 124.632 ;
     RECT  68.749 23.088 69.733 120.792 ;
     RECT  69.733 23.088 70.409 121.416 ;
     RECT  69.721 122.544 70.657 124.632 ;
     RECT  70.657 122.352 72.205 124.632 ;
     RECT  70.409 23.088 72.277 121.128 ;
     RECT  67.504 13.344 72.608 13.368 ;
     RECT  72.277 23.088 72.608 121.176 ;
     RECT  72.205 122.208 72.608 124.632 ;
     RECT  72.608 2.148 72.712 127.452 ;
     RECT  72.712 2.418 72.904 127.182 ;
     RECT  72.904 23.088 73.289 122.424 ;
     RECT  73.289 120.24 74.149 122.424 ;
     RECT  73.289 23.088 74.581 119.16 ;
     RECT  74.149 120.24 74.581 122.472 ;
     RECT  74.581 23.088 75.161 122.472 ;
     RECT  75.161 122.4 75.341 122.472 ;
     RECT  75.161 23.088 75.827 121.368 ;
     RECT  75.341 122.4 75.827 122.424 ;
     RECT  75.827 120.336 76.669 121.368 ;
     RECT  76.669 120.336 77.033 121.416 ;
     RECT  72.904 13.344 78.008 13.368 ;
     RECT  75.827 23.088 78.008 119.16 ;
     RECT  77.033 120.48 78.008 121.416 ;
     RECT  72.904 124.608 78.008 124.632 ;
     RECT  78.008 2.148 78.112 127.452 ;
     RECT  78.112 2.418 78.304 127.182 ;
     RECT  78.304 23.088 78.365 121.416 ;
     RECT  78.365 116.16 78.419 121.416 ;
     RECT  78.419 116.16 79.621 118.392 ;
     RECT  78.419 119.424 79.621 121.416 ;
     RECT  79.621 116.16 79.625 121.416 ;
     RECT  79.625 116.208 80.629 121.416 ;
     RECT  78.365 23.088 80.869 115.176 ;
     RECT  80.629 116.208 80.869 121.464 ;
     RECT  80.869 23.088 81.173 121.464 ;
     RECT  81.173 23.088 81.353 121.368 ;
     RECT  81.353 23.088 82.789 119.256 ;
     RECT  81.353 120.288 82.789 121.368 ;
     RECT  78.304 13.344 83.408 13.368 ;
     RECT  82.789 23.088 83.408 121.368 ;
     RECT  78.304 124.608 83.408 124.632 ;
     RECT  83.408 2.148 83.512 127.452 ;
     RECT  83.512 2.418 83.704 127.182 ;
     RECT  83.704 23.088 84.377 120.744 ;
     RECT  84.377 23.088 84.449 115.464 ;
     RECT  84.449 23.088 84.557 103.656 ;
     RECT  84.377 116.496 84.805 120.744 ;
     RECT  84.805 116.496 85.133 120.792 ;
     RECT  84.557 23.088 85.705 103.512 ;
     RECT  84.449 104.832 85.705 115.464 ;
     RECT  85.705 23.088 85.885 115.464 ;
     RECT  85.133 116.496 85.885 120.552 ;
     RECT  85.885 23.088 86.033 120.552 ;
     RECT  86.033 104.544 86.465 120.552 ;
     RECT  86.465 120.288 86.609 120.552 ;
     RECT  86.465 104.544 87.077 119.016 ;
     RECT  86.609 120.288 87.221 120.312 ;
     RECT  87.077 104.544 87.433 112.44 ;
     RECT  86.033 23.088 87.469 103.512 ;
     RECT  87.433 104.496 87.469 112.44 ;
     RECT  87.077 113.808 87.545 119.016 ;
     RECT  87.469 23.088 88.081 112.44 ;
     RECT  87.545 113.808 88.081 118.488 ;
     RECT  88.081 23.088 88.693 118.488 ;
     RECT  83.704 13.344 88.808 13.368 ;
     RECT  88.693 23.088 88.808 119.16 ;
     RECT  88.513 120.768 88.808 120.792 ;
     RECT  83.704 124.608 88.808 124.632 ;
     RECT  88.808 2.148 88.912 127.452 ;
     RECT  88.912 2.418 89.104 127.182 ;
     RECT  89.104 117.504 89.561 119.016 ;
     RECT  89.104 23.088 89.705 116.52 ;
     RECT  89.104 13.344 89.741 13.368 ;
     RECT  89.705 113.232 89.849 116.52 ;
     RECT  89.849 113.472 90.425 116.52 ;
     RECT  89.705 23.088 90.533 112.152 ;
     RECT  90.425 113.472 90.785 113.736 ;
     RECT  90.425 114.864 90.785 116.52 ;
     RECT  90.533 109.68 91.069 112.152 ;
     RECT  90.785 113.472 91.069 113.496 ;
     RECT  90.785 115.152 91.073 116.52 ;
     RECT  91.073 115.152 91.217 115.752 ;
     RECT  89.561 117.504 91.613 118.728 ;
     RECT  90.533 23.088 91.861 108.648 ;
     RECT  91.069 109.68 91.861 113.496 ;
     RECT  91.217 115.152 92.077 115.416 ;
     RECT  92.185 116.448 92.477 116.472 ;
     RECT  91.613 117.504 92.629 118.008 ;
     RECT  92.077 115.104 92.675 115.416 ;
     RECT  92.629 116.976 92.675 118.008 ;
     RECT  92.675 116.976 92.716 117.528 ;
     RECT  91.861 23.088 92.761 113.496 ;
     RECT  92.761 23.088 92.917 113.88 ;
     RECT  92.675 115.104 92.917 115.176 ;
     RECT  92.716 117.408 93.781 117.528 ;
     RECT  92.917 23.088 94.208 115.176 ;
     RECT  93.781 116.544 94.208 117.528 ;
     RECT  89.104 120.768 94.208 120.792 ;
     RECT  89.104 124.608 94.208 124.632 ;
     RECT  94.208 2.148 94.312 127.452 ;
     RECT  94.312 2.418 94.504 127.182 ;
     RECT  94.504 23.088 95.605 103.512 ;
     RECT  94.504 104.544 95.605 111.048 ;
     RECT  94.504 112.752 95.605 115.8 ;
     RECT  95.605 112.08 95.645 115.8 ;
     RECT  95.645 112.08 95.753 115.704 ;
     RECT  95.753 114.096 96.041 115.704 ;
     RECT  96.041 114.24 96.083 115.704 ;
     RECT  95.753 112.08 96.437 112.776 ;
     RECT  95.605 23.088 96.661 111.048 ;
     RECT  96.437 112.08 96.661 112.344 ;
     RECT  96.661 23.088 96.707 112.344 ;
     RECT  96.707 104.592 96.761 112.344 ;
     RECT  96.761 104.592 96.869 111.576 ;
     RECT  96.083 115.152 97.049 115.704 ;
     RECT  96.869 104.64 97.801 111.576 ;
     RECT  96.707 23.088 97.873 103.512 ;
     RECT  97.801 104.64 97.873 111.624 ;
     RECT  97.873 23.088 98.381 111.624 ;
     RECT  98.381 23.088 98.633 109.704 ;
     RECT  98.633 23.088 99.608 108.36 ;
     RECT  98.633 109.392 99.608 109.704 ;
     RECT  98.381 110.832 99.608 111.624 ;
     RECT  97.049 115.152 99.608 115.176 ;
     RECT  94.504 117.504 99.608 117.528 ;
     RECT  94.504 124.608 99.608 124.632 ;
     RECT  99.608 2.148 99.712 127.452 ;
     RECT  99.712 2.418 99.904 127.182 ;
     RECT  99.904 104.832 100.145 107.64 ;
     RECT  100.145 107.616 100.325 107.64 ;
     RECT  99.904 111.6 100.361 111.624 ;
     RECT  100.145 104.832 101.225 106.632 ;
     RECT  101.225 104.832 101.333 105.528 ;
     RECT  101.005 108.72 101.441 108.744 ;
     RECT  99.904 110.304 101.585 110.376 ;
     RECT  99.904 23.088 101.852 103.512 ;
     RECT  101.225 106.512 101.893 106.632 ;
     RECT  101.852 23.088 101.939 104.424 ;
     RECT  101.893 106.512 102.017 107.112 ;
     RECT  102.017 106.512 102.053 106.584 ;
     RECT  101.585 110.304 102.053 110.328 ;
     RECT  101.977 108.288 102.197 108.312 ;
     RECT  101.333 105.504 102.233 105.528 ;
     RECT  102.053 106.56 102.557 106.584 ;
     RECT  101.939 23.088 105.008 103.512 ;
     RECT  99.904 115.152 105.008 115.176 ;
     RECT  99.904 117.504 105.008 117.528 ;
     RECT  99.904 124.608 105.008 124.632 ;
     RECT  105.008 2.148 105.112 127.452 ;
     RECT  105.112 2.418 105.304 127.182 ;
     RECT  105.304 23.088 110.408 103.512 ;
     RECT  105.304 115.152 110.408 115.176 ;
     RECT  105.304 117.504 110.408 117.528 ;
     RECT  110.408 2.148 110.512 127.452 ;
     RECT  110.512 2.418 110.704 127.182 ;
     RECT  110.704 23.088 111.845 103.512 ;
     RECT  111.845 23.904 113.209 103.512 ;
     RECT  113.209 23.424 113.221 103.512 ;
     RECT  113.221 23.28 113.537 103.512 ;
     RECT  113.537 23.424 115.733 103.512 ;
     RECT  115.733 23.424 115.808 99.48 ;
     RECT  115.733 100.608 115.808 103.512 ;
     RECT  110.704 115.152 115.808 115.176 ;
     RECT  110.704 117.504 115.808 117.528 ;
     RECT  115.808 2.148 115.912 99.48 ;
     RECT  115.808 100.608 115.912 127.452 ;
     RECT  115.912 2.418 116.104 99.48 ;
     RECT  115.912 100.608 116.104 127.182 ;
     RECT  116.104 100.608 117.241 103.512 ;
     RECT  116.104 23.424 121.208 99.48 ;
     RECT  117.241 100.56 121.208 103.512 ;
     RECT  116.104 115.152 121.208 115.176 ;
     RECT  116.104 117.504 121.208 117.528 ;
     RECT  121.208 2.148 121.312 99.48 ;
     RECT  121.208 100.56 121.312 127.452 ;
     RECT  121.312 2.418 121.504 99.48 ;
     RECT  121.312 100.56 121.504 127.182 ;
     RECT  121.504 23.424 126.608 99.48 ;
     RECT  121.504 100.56 126.608 103.512 ;
     RECT  121.504 115.152 126.608 115.176 ;
     RECT  121.504 117.504 126.608 117.528 ;
     RECT  126.608 2.148 126.712 99.48 ;
     RECT  126.608 100.56 126.712 127.452 ;
     RECT  126.712 2.418 126.904 99.48 ;
     RECT  126.712 100.56 126.904 127.182 ;
     RECT  126.904 23.424 127.397 99.48 ;
     RECT  127.397 23.424 132.008 99.432 ;
     RECT  126.904 100.56 132.008 103.512 ;
     RECT  126.904 115.152 132.008 115.176 ;
     RECT  126.904 117.504 132.008 117.528 ;
     RECT  132.008 2.148 132.112 99.432 ;
     RECT  132.008 100.56 132.112 127.452 ;
     RECT  132.112 2.418 132.304 99.432 ;
     RECT  132.112 100.56 132.304 127.182 ;
     RECT  132.304 23.424 137.408 99.432 ;
     RECT  132.304 100.56 137.408 103.512 ;
     RECT  132.304 115.152 137.408 115.176 ;
     RECT  132.304 117.504 137.408 117.528 ;
     RECT  137.408 2.148 137.512 99.432 ;
     RECT  137.408 100.56 137.512 127.452 ;
     RECT  137.512 2.418 137.704 99.432 ;
     RECT  137.512 100.56 137.704 127.182 ;
     RECT  137.704 23.424 142.808 99.432 ;
     RECT  137.704 100.56 142.808 103.512 ;
     RECT  137.704 115.152 142.808 115.176 ;
     RECT  137.704 117.504 142.808 117.528 ;
     RECT  142.808 2.148 142.912 99.432 ;
     RECT  142.808 100.56 142.912 127.452 ;
     RECT  142.912 2.418 143.104 99.432 ;
     RECT  142.912 100.56 143.104 127.182 ;
     RECT  143.104 23.424 148.208 99.432 ;
     RECT  143.104 100.56 148.208 103.512 ;
     RECT  143.104 115.152 148.208 115.176 ;
     RECT  143.104 117.504 148.208 117.528 ;
     RECT  148.208 2.148 148.312 99.432 ;
     RECT  148.208 100.56 148.312 127.452 ;
     RECT  148.312 2.418 148.504 99.432 ;
     RECT  148.312 100.56 148.504 127.182 ;
     RECT  148.504 23.52 153.608 99.432 ;
     RECT  148.504 100.56 153.608 103.512 ;
     RECT  148.504 115.152 153.608 115.176 ;
     RECT  148.504 117.504 153.608 117.528 ;
     RECT  153.608 2.148 153.712 99.432 ;
     RECT  153.608 100.56 153.712 127.452 ;
     RECT  153.712 2.418 153.904 99.432 ;
     RECT  153.712 100.56 153.904 127.182 ;
     RECT  153.904 117.504 153.929 117.528 ;
     RECT  153.904 23.568 157.637 99.432 ;
     RECT  157.637 23.568 159.008 98.55 ;
     RECT  153.904 100.56 159.008 103.512 ;
     RECT  153.904 115.152 159.008 115.176 ;
     RECT  159.008 2.148 159.112 98.55 ;
     RECT  159.008 100.56 159.112 127.452 ;
     RECT  159.112 2.418 159.304 98.55 ;
     RECT  159.112 100.56 159.304 127.182 ;
     RECT  141.865 129.552 160.405 129.576 ;
     RECT  160.405 129.456 160.451 129.576 ;
     RECT  160.451 129.456 160.547 129.48 ;
     RECT  159.304 23.568 164.408 98.55 ;
     RECT  159.304 100.56 164.408 103.512 ;
     RECT  159.304 115.152 164.408 115.176 ;
     RECT  164.408 2.148 164.512 98.55 ;
     RECT  164.408 100.56 164.512 127.452 ;
     RECT  164.512 2.418 164.704 98.55 ;
     RECT  164.512 100.56 164.704 127.182 ;
     RECT  164.704 23.568 169.808 98.55 ;
     RECT  164.704 100.56 169.808 103.512 ;
     RECT  164.704 115.152 169.808 115.176 ;
     RECT  169.808 2.148 169.912 98.55 ;
     RECT  169.808 100.56 169.912 127.452 ;
     RECT  169.912 2.418 170.104 98.55 ;
     RECT  169.912 100.56 170.104 127.182 ;
     RECT  170.104 23.568 175.208 98.55 ;
     RECT  170.104 100.56 175.208 103.512 ;
     RECT  170.104 115.152 175.208 115.176 ;
     RECT  175.208 2.148 175.312 98.55 ;
     RECT  175.208 100.56 175.312 127.452 ;
     RECT  175.312 2.418 175.504 98.55 ;
     RECT  175.312 100.56 175.504 127.182 ;
     RECT  175.504 23.568 180.608 98.55 ;
     RECT  175.504 100.56 180.608 103.512 ;
     RECT  175.504 115.152 180.608 115.176 ;
     RECT  180.608 2.148 180.712 98.55 ;
     RECT  180.608 100.56 180.712 127.452 ;
     RECT  180.712 2.418 180.904 98.55 ;
     RECT  180.712 100.56 180.904 127.182 ;
     RECT  180.904 23.568 186.008 98.55 ;
     RECT  180.904 100.56 186.008 103.512 ;
     RECT  180.904 115.152 186.008 115.176 ;
     RECT  186.008 2.148 186.112 98.55 ;
     RECT  186.008 100.56 186.112 127.452 ;
     RECT  186.112 2.418 186.304 98.55 ;
     RECT  186.112 100.56 186.304 127.182 ;
     RECT  186.304 23.568 191.408 98.55 ;
     RECT  186.304 100.56 191.408 103.512 ;
     RECT  186.304 115.152 191.408 115.176 ;
     RECT  191.408 2.148 191.512 98.55 ;
     RECT  191.408 100.56 191.512 127.452 ;
     RECT  191.512 2.418 191.704 98.55 ;
     RECT  191.512 100.56 191.704 127.182 ;
     RECT  191.704 23.568 196.808 98.55 ;
     RECT  191.704 100.56 196.808 103.512 ;
     RECT  191.704 115.152 196.808 115.176 ;
     RECT  196.808 2.148 196.912 98.55 ;
     RECT  196.808 100.56 196.912 127.452 ;
     RECT  196.912 2.418 197.104 98.55 ;
     RECT  196.912 100.56 197.104 127.182 ;
     RECT  197.104 23.568 197.568 98.55 ;
     RECT  197.568 23.568 197.741 68.52 ;
     RECT  197.104 100.56 197.747 103.512 ;
     RECT  197.741 23.568 197.777 66.696 ;
     RECT  197.741 67.728 197.777 68.52 ;
     RECT  197.747 100.56 197.795 103.224 ;
     RECT  197.777 67.92 197.813 68.52 ;
     RECT  197.795 100.608 198.131 103.224 ;
     RECT  197.777 23.568 198.179 41.448 ;
     RECT  198.131 101.04 198.227 103.224 ;
     RECT  198.227 101.04 198.275 101.064 ;
     RECT  198.227 102.24 198.821 103.224 ;
     RECT  197.777 46.608 198.965 54.792 ;
     RECT  197.777 63.312 198.965 64.488 ;
     RECT  197.813 68.4 198.965 68.52 ;
     RECT  198.965 63.408 199.001 64.008 ;
     RECT  198.179 24.96 199.289 41.448 ;
     RECT  198.965 49.584 199.361 53.448 ;
     RECT  198.821 103.2 199.361 103.224 ;
     RECT  197.777 42.768 199.505 45.48 ;
     RECT  198.965 46.608 199.505 48.552 ;
     RECT  199.361 49.584 199.505 53.352 ;
     RECT  197.777 55.968 199.505 61.032 ;
     RECT  199.001 63.408 199.505 63.432 ;
     RECT  199.505 51.408 199.541 53.352 ;
     RECT  199.289 24.96 199.763 29.832 ;
     RECT  199.763 26.544 199.859 29.832 ;
     RECT  199.859 28.656 199.901 29.832 ;
     RECT  199.505 42.768 199.901 43.176 ;
     RECT  197.777 66.672 199.901 66.696 ;
     RECT  198.965 54.432 199.937 54.792 ;
     RECT  199.505 44.592 199.973 45.48 ;
     RECT  199.937 54.432 199.973 54.6 ;
     RECT  197.777 62.064 199.973 62.088 ;
     RECT  199.859 26.544 200.009 27.096 ;
     RECT  199.505 46.608 200.009 47.88 ;
     RECT  199.901 42.768 200.045 42.888 ;
     RECT  200.009 46.608 200.045 46.632 ;
     RECT  200.009 47.664 200.045 47.88 ;
     RECT  199.505 55.968 200.045 57.048 ;
     RECT  199.901 28.992 200.081 29.832 ;
     RECT  198.965 68.4 200.153 68.424 ;
     RECT  200.045 55.968 200.333 55.992 ;
     RECT  199.289 30.816 200.341 41.448 ;
     RECT  200.045 42.768 200.341 42.792 ;
     RECT  200.041 72 200.341 72.024 ;
     RECT  199.763 24.96 200.387 24.984 ;
     RECT  200.341 71.52 200.387 72.024 ;
     RECT  199.505 49.584 200.405 49.608 ;
     RECT  200.341 75.36 200.428 75.384 ;
     RECT  199.861 69.504 200.533 69.528 ;
     RECT  200.387 71.52 200.579 71.544 ;
     RECT  199.973 45.456 200.693 45.48 ;
     RECT  199.541 52.368 200.732 53.352 ;
     RECT  199.973 54.432 200.732 54.456 ;
     RECT  200.045 57.024 200.753 57.048 ;
     RECT  200.732 52.368 200.819 54.456 ;
     RECT  200.341 30.816 200.906 42.792 ;
     RECT  200.725 64.944 200.915 64.968 ;
     RECT  200.906 30.816 201.133 42.744 ;
     RECT  201.133 30.816 201.155 42.36 ;
     RECT  200.473 50.736 201.229 50.76 ;
     RECT  199.505 58.944 201.229 58.968 ;
     RECT  200.533 69.504 201.253 70.296 ;
     RECT  201.229 49.92 201.26 50.76 ;
     RECT  201.349 45.696 201.365 45.912 ;
     RECT  201.26 49.92 201.373 51.096 ;
     RECT  200.045 47.76 201.397 47.88 ;
     RECT  201.365 45.696 201.404 46.152 ;
     RECT  201.397 47.76 201.404 48.072 ;
     RECT  201.155 30.816 201.445 41.16 ;
     RECT  201.373 49.536 201.445 51.096 ;
     RECT  200.819 54.432 201.553 54.456 ;
     RECT  201.409 63.216 201.596 63.24 ;
     RECT  199.505 60.624 201.637 60.648 ;
     RECT  201.221 66.672 201.733 66.696 ;
     RECT  201.445 49.536 201.74 51.336 ;
     RECT  200.753 57.024 201.769 57.624 ;
     RECT  201.229 58.704 201.769 58.968 ;
     RECT  200.819 52.368 201.781 53.352 ;
     RECT  201.553 54.432 201.781 54.744 ;
     RECT  201.769 57.024 201.836 58.968 ;
     RECT  201.733 66.192 201.841 66.696 ;
     RECT  201.596 62.4 201.877 63.24 ;
     RECT  201.337 64.368 201.877 64.392 ;
     RECT  201.637 60.624 201.913 60.984 ;
     RECT  201.404 45.696 201.932 48.072 ;
     RECT  201.932 44.784 201.949 48.072 ;
     RECT  201.841 66.192 201.949 66.744 ;
     RECT  201.913 60.144 201.973 60.984 ;
     RECT  201.877 62.4 201.973 64.392 ;
     RECT  201.253 68.352 201.973 68.376 ;
     RECT  201.973 60.144 202.021 64.392 ;
     RECT  201.949 66.192 202.021 66.792 ;
     RECT  200.081 28.992 202.069 29.688 ;
     RECT  201.445 30.72 202.069 41.16 ;
     RECT  201.836 56.736 202.069 58.968 ;
     RECT  202.021 60.144 202.069 66.792 ;
     RECT  201.155 42.24 202.165 42.36 ;
     RECT  198.179 23.568 202.208 23.592 ;
     RECT  200.009 26.544 202.208 26.616 ;
     RECT  202.069 28.992 202.208 41.16 ;
     RECT  202.165 42.24 202.208 42.792 ;
     RECT  201.949 44.448 202.208 48.072 ;
     RECT  201.74 49.2 202.208 51.336 ;
     RECT  201.781 52.368 202.208 54.744 ;
     RECT  202.069 56.736 202.208 66.792 ;
     RECT  201.973 68.256 202.208 68.376 ;
     RECT  201.253 69.456 202.208 70.296 ;
     RECT  201.445 79.248 202.208 79.272 ;
     RECT  197.104 115.152 202.208 115.176 ;
     RECT  202.208 2.148 202.312 127.452 ;
     RECT  202.312 2.418 202.504 127.182 ;
     RECT  202.504 34.752 202.565 43.272 ;
     RECT  202.504 56.784 202.565 57.432 ;
     RECT  202.504 31.392 202.601 32.568 ;
     RECT  202.504 60.768 202.637 62.568 ;
     RECT  202.565 35.232 202.691 43.272 ;
     RECT  202.691 35.232 202.717 42.264 ;
     RECT  202.637 60.768 202.745 62.184 ;
     RECT  202.601 31.776 202.781 32.568 ;
     RECT  202.691 43.248 202.787 43.272 ;
     RECT  202.745 60.768 202.787 61.848 ;
     RECT  202.504 69.504 202.817 70.536 ;
     RECT  202.504 46.176 202.825 54.744 ;
     RECT  202.781 31.872 202.883 32.568 ;
     RECT  202.504 68.4 202.931 68.424 ;
     RECT  202.565 57.024 203.033 57.432 ;
     RECT  202.504 63.744 203.033 65.4 ;
     RECT  202.717 35.328 203.069 42.264 ;
     RECT  202.825 46.32 203.075 54.744 ;
     RECT  202.504 26.544 203.213 26.616 ;
     RECT  203.069 35.328 203.213 41.784 ;
     RECT  203.075 46.512 203.219 54.744 ;
     RECT  203.219 47.28 203.257 54.744 ;
     RECT  203.257 51.6 203.329 54.744 ;
     RECT  203.257 47.28 203.349 49.8 ;
     RECT  202.504 59.088 203.393 59.112 ;
     RECT  202.787 60.768 203.465 60.984 ;
     RECT  203.329 54.432 203.509 54.744 ;
     RECT  202.504 66.528 203.509 67.32 ;
     RECT  203.329 51.6 203.537 53.352 ;
     RECT  203.509 54.432 203.537 55.224 ;
     RECT  203.537 52.704 203.555 53.352 ;
     RECT  203.509 66.528 203.569 68.136 ;
     RECT  203.569 66.384 203.596 68.136 ;
     RECT  203.033 65.376 203.605 65.4 ;
     RECT  203.596 66.384 203.605 67.56 ;
     RECT  203.537 54.576 203.609 55.224 ;
     RECT  203.033 63.744 203.641 64.392 ;
     RECT  203.609 54.576 203.753 54.6 ;
     RECT  203.537 51.6 203.795 51.624 ;
     RECT  203.213 35.568 203.825 41.784 ;
     RECT  202.817 69.504 203.861 69.528 ;
     RECT  203.821 61.536 203.905 61.56 ;
     RECT  203.033 57.024 203.989 57.144 ;
     RECT  203.641 63.264 203.996 64.392 ;
     RECT  203.825 36.864 204.005 41.784 ;
     RECT  203.349 47.712 204.005 49.8 ;
     RECT  203.996 63.168 204.005 64.392 ;
     RECT  203.605 65.376 204.037 67.56 ;
     RECT  203.989 56.16 204.076 57.144 ;
     RECT  204.037 64.416 204.083 67.56 ;
     RECT  204.076 57.024 204.113 57.144 ;
     RECT  204.083 64.416 204.149 65.304 ;
     RECT  204.005 63.168 204.179 63.192 ;
     RECT  202.883 32.544 204.253 32.568 ;
     RECT  204.005 47.712 204.329 48.888 ;
     RECT  204.253 32.448 204.337 32.568 ;
     RECT  204.005 37.584 204.361 41.784 ;
     RECT  204.133 62.016 204.401 62.04 ;
     RECT  204.083 66.384 204.401 67.56 ;
     RECT  204.329 47.712 204.419 48.504 ;
     RECT  204.361 37.584 204.445 42.744 ;
     RECT  204.149 65.28 204.509 65.304 ;
     RECT  204.419 47.856 204.653 48.504 ;
     RECT  204.401 67.536 204.685 67.56 ;
     RECT  204.337 32.544 204.721 32.568 ;
     RECT  204.685 67.536 204.725 67.704 ;
     RECT  204.445 37.584 204.905 41.928 ;
     RECT  204.905 38.496 204.941 41.928 ;
     RECT  204.725 67.68 205.196 67.704 ;
     RECT  204.401 66.384 205.283 66.408 ;
     RECT  205.196 67.68 205.283 67.8 ;
     RECT  205.196 68.88 205.283 68.904 ;
     RECT  204.941 38.496 205.481 41.064 ;
     RECT  205.532 37.44 205.619 37.464 ;
     RECT  205.441 42.192 205.763 42.216 ;
     RECT  203.555 53.328 206.057 53.352 ;
     RECT  204.113 57.12 206.305 57.144 ;
     RECT  205.045 29.472 206.341 29.496 ;
     RECT  202.817 70.512 206.341 70.536 ;
     RECT  206.305 57.024 206.345 57.144 ;
     RECT  206.341 29.472 206.381 29.592 ;
     RECT  206.341 70.512 206.381 70.632 ;
     RECT  204.721 32.544 206.387 33 ;
     RECT  206.341 53.184 206.425 53.208 ;
     RECT  205.481 38.64 206.737 41.064 ;
     RECT  206.737 38.64 207.308 41.4 ;
     RECT  203.213 26.544 207.608 26.568 ;
     RECT  206.381 29.568 207.608 29.592 ;
     RECT  206.387 32.544 207.608 32.568 ;
     RECT  203.825 35.568 207.608 35.592 ;
     RECT  207.308 38.64 207.608 41.88 ;
     RECT  204.653 47.856 207.608 47.88 ;
     RECT  206.345 57.024 207.608 57.048 ;
     RECT  205.283 67.68 207.608 67.704 ;
     RECT  206.732 68.928 207.608 68.952 ;
     RECT  206.381 70.608 207.608 70.632 ;
     RECT  206.341 72.384 207.608 72.408 ;
     RECT  207.169 77.28 207.608 77.304 ;
     RECT  206.773 100.08 207.608 100.104 ;
     RECT  202.504 115.152 207.608 115.176 ;
     RECT  207.608 2.148 207.712 127.452 ;
     RECT  207.712 2.418 207.904 127.182 ;
     RECT  207.904 40.464 208.081 40.584 ;
     RECT  207.904 70.608 208.787 70.632 ;
     RECT  207.904 77.232 208.787 77.304 ;
     RECT  207.904 57.024 208.883 57.048 ;
     RECT  207.904 72.864 208.883 72.888 ;
     RECT  207.904 39.312 209.939 39.336 ;
     RECT  209.893 36.672 209.98 37.608 ;
     RECT  207.904 32.544 210.229 32.568 ;
     RECT  207.904 34.368 210.229 34.392 ;
     RECT  207.904 35.568 210.229 35.592 ;
     RECT  208.081 40.56 210.275 40.584 ;
     RECT  210.229 32.544 210.812 32.76 ;
     RECT  210.841 23.952 210.853 23.976 ;
     RECT  210.812 25.056 210.899 25.08 ;
     RECT  210.812 32.544 210.899 32.952 ;
     RECT  210.229 34.368 210.899 35.592 ;
     RECT  210.853 23.184 210.925 23.976 ;
     RECT  207.904 29.568 210.989 29.592 ;
     RECT  207.904 83.76 211.273 83.784 ;
     RECT  210.899 35.568 211.345 35.592 ;
     RECT  209.98 36.672 211.345 36.696 ;
     RECT  211.388 21.792 211.475 21.816 ;
     RECT  210.925 23.184 211.493 23.4 ;
     RECT  211.345 35.568 211.493 36.696 ;
     RECT  211.493 23.376 211.516 23.4 ;
     RECT  210.899 34.368 211.631 34.392 ;
     RECT  207.904 100.08 211.637 100.104 ;
     RECT  211.493 36.48 211.669 36.696 ;
     RECT  211.273 83.76 211.705 83.88 ;
     RECT  211.597 38.112 211.715 38.136 ;
     RECT  207.904 89.952 211.717 89.976 ;
     RECT  211.489 9.072 211.763 9.096 ;
     RECT  211.676 85.152 211.763 85.176 ;
     RECT  211.417 30 211.765 30.264 ;
     RECT  210.899 32.544 211.811 32.76 ;
     RECT  211.717 89.808 211.813 89.976 ;
     RECT  207.904 26.544 211.817 26.568 ;
     RECT  211.813 89.808 211.853 90.6 ;
     RECT  211.717 10.848 211.859 10.872 ;
     RECT  211.631 33.744 211.859 34.392 ;
     RECT  211.741 74.976 211.859 75 ;
     RECT  211.772 78.624 211.859 78.648 ;
     RECT  211.705 83.712 211.859 83.88 ;
     RECT  211.853 89.952 211.897 90.6 ;
     RECT  211.775 21.12 211.921 21.144 ;
     RECT  211.921 20.736 211.955 21.144 ;
     RECT  211.417 24.672 211.957 24.84 ;
     RECT  210.229 28.416 211.957 28.44 ;
     RECT  211.805 94.656 211.957 94.68 ;
     RECT  211.633 92.784 211.967 92.808 ;
     RECT  211.859 34.08 211.993 34.392 ;
     RECT  211.957 27.936 211.997 28.44 ;
     RECT  211.997 27.936 212.005 27.96 ;
     RECT  212.005 27.84 212.041 27.96 ;
     RECT  211.669 36.48 212.053 36.792 ;
     RECT  212.06 80.16 212.101 80.184 ;
     RECT  211.955 20.736 212.108 20.76 ;
     RECT  212.137 65.52 212.281 65.544 ;
     RECT  212.101 104.544 212.281 104.568 ;
     RECT  211.993 105.6 212.281 105.912 ;
     RECT  211.811 32.544 212.3 32.568 ;
     RECT  211.765 30 212.341 30.552 ;
     RECT  212.281 104.544 212.341 105.912 ;
     RECT  211.957 94.656 212.381 95.496 ;
     RECT  211.859 83.808 212.389 83.88 ;
     RECT  212.341 104.112 212.389 105.912 ;
     RECT  211.967 92.64 212.396 92.808 ;
     RECT  212.381 94.032 212.396 95.496 ;
     RECT  212.348 98.928 212.424 98.952 ;
     RECT  211.813 15.888 212.444 15.912 ;
     RECT  212.485 19.392 212.492 19.416 ;
     RECT  212.108 20.448 212.492 20.76 ;
     RECT  212.341 30 212.497 30.744 ;
     RECT  212.636 88.32 212.641 88.344 ;
     RECT  212.348 74.064 212.677 74.088 ;
     RECT  212.396 92.64 212.677 95.496 ;
     RECT  211.993 34.08 212.732 35.112 ;
     RECT  212.053 36.48 212.732 37.08 ;
     RECT  212.444 15.312 212.749 15.912 ;
     RECT  212.389 83.808 212.78 84.168 ;
     RECT  212.641 87.792 212.821 88.344 ;
     RECT  212.3 31.872 212.828 32.568 ;
     RECT  212.053 10.224 212.869 10.248 ;
     RECT  212.581 23.568 212.869 23.592 ;
     RECT  211.957 24.672 212.869 25.32 ;
     RECT  212.041 27.84 212.869 27.912 ;
     RECT  212.869 9.36 213.008 10.248 ;
     RECT  211.885 11.376 213.008 11.4 ;
     RECT  212.485 14.208 213.008 14.232 ;
     RECT  212.749 15.312 213.008 16.248 ;
     RECT  212.869 18.144 213.008 18.168 ;
     RECT  212.492 19.392 213.008 20.76 ;
     RECT  212.869 23.568 213.008 25.32 ;
     RECT  212.869 27.312 213.008 27.912 ;
     RECT  212.497 29.424 213.008 30.744 ;
     RECT  212.828 31.872 213.008 32.952 ;
     RECT  212.732 34.08 213.008 37.08 ;
     RECT  212.533 39.264 213.008 39.288 ;
     RECT  212.533 40.464 213.008 40.488 ;
     RECT  212.849 44.448 213.008 44.472 ;
     RECT  207.904 47.856 213.008 47.88 ;
     RECT  212.281 64.992 213.008 65.544 ;
     RECT  212.677 73.872 213.008 74.088 ;
     RECT  213.001 75.12 213.008 75.144 ;
     RECT  208.787 77.28 213.008 77.304 ;
     RECT  212.101 78.912 213.008 80.184 ;
     RECT  212.78 83.808 213.008 84.36 ;
     RECT  212.821 87.792 213.008 88.968 ;
     RECT  211.897 89.952 213.008 89.976 ;
     RECT  212.677 92.64 213.008 96.84 ;
     RECT  212.424 98.64 213.008 98.952 ;
     RECT  212.005 100.656 213.008 100.68 ;
     RECT  212.389 103.728 213.008 105.912 ;
     RECT  212.485 108.864 213.008 108.888 ;
     RECT  212.137 110.016 213.008 110.04 ;
     RECT  207.904 115.152 213.008 115.176 ;
     RECT  212.341 117.984 213.008 118.008 ;
     RECT  209.761 121.68 213.008 121.704 ;
     RECT  212.677 123.216 213.008 123.24 ;
     RECT  213.008 2.148 213.112 127.452 ;
     RECT  213.112 2.418 213.304 127.182 ;
     RECT  213.304 98.976 213.365 99 ;
     RECT  213.304 18.144 213.443 19.032 ;
     RECT  213.304 26.736 213.443 27.192 ;
     RECT  213.304 83.856 213.443 84.072 ;
     RECT  213.443 83.856 213.491 83.976 ;
     RECT  213.304 47.856 213.581 47.88 ;
     RECT  213.491 83.952 213.617 83.976 ;
     RECT  213.304 95.76 213.635 97.848 ;
     RECT  213.304 100.32 213.635 102.84 ;
     RECT  213.304 107.76 213.697 109.272 ;
     RECT  213.304 37.632 213.733 37.656 ;
     RECT  213.304 28.368 213.761 29.064 ;
     RECT  213.304 73.68 213.772 75.816 ;
     RECT  213.304 121.68 213.779 121.704 ;
     RECT  213.304 23.568 213.797 24.696 ;
     RECT  213.304 88.944 213.797 94.44 ;
     RECT  213.304 123.216 213.82 123.432 ;
     RECT  213.635 102.576 213.833 102.84 ;
     RECT  213.304 8.832 213.875 9.432 ;
     RECT  213.304 13.008 213.875 13.8 ;
     RECT  213.443 26.736 213.875 26.76 ;
     RECT  213.761 28.368 213.875 28.392 ;
     RECT  213.635 100.32 213.877 101.448 ;
     RECT  213.304 76.944 213.905 80.664 ;
     RECT  213.772 73.824 213.941 75.816 ;
     RECT  213.797 90.768 213.977 94.44 ;
     RECT  213.697 108.048 213.977 109.272 ;
     RECT  213.797 88.944 214.013 89.448 ;
     RECT  213.875 13.776 214.019 13.8 ;
     RECT  213.304 72.24 214.019 72.264 ;
     RECT  213.977 91.008 214.019 94.44 ;
     RECT  213.941 73.824 214.049 74.376 ;
     RECT  213.797 23.712 214.057 24.648 ;
     RECT  213.905 76.944 214.067 79.464 ;
     RECT  214.019 93.12 214.067 94.44 ;
     RECT  213.304 21.024 214.085 22.2 ;
     RECT  213.977 108.048 214.093 108.312 ;
     RECT  213.304 114.576 214.093 115.176 ;
     RECT  213.304 82.272 214.115 82.872 ;
     RECT  213.304 85.488 214.115 87.384 ;
     RECT  214.093 108.048 214.115 108.12 ;
     RECT  213.304 7.776 214.121 7.8 ;
     RECT  214.067 76.944 214.149 76.968 ;
     RECT  214.115 87.36 214.163 87.384 ;
     RECT  213.635 95.76 214.163 97.608 ;
     RECT  213.877 100.656 214.163 101.448 ;
     RECT  214.067 78.816 214.193 79.464 ;
     RECT  214.115 108.048 214.301 108.072 ;
     RECT  214.115 85.488 214.307 85.992 ;
     RECT  214.019 91.008 214.307 92.04 ;
     RECT  214.067 93.12 214.307 93.144 ;
     RECT  214.049 73.824 214.337 73.848 ;
     RECT  214.013 89.424 214.373 89.448 ;
     RECT  214.307 92.016 214.373 92.04 ;
     RECT  214.163 97.44 214.373 97.608 ;
     RECT  214.193 79.44 214.409 79.464 ;
     RECT  214.163 95.76 214.445 96.408 ;
     RECT  214.163 101.28 214.481 101.448 ;
     RECT  213.833 102.576 214.553 102.6 ;
     RECT  214.307 85.584 214.589 85.992 ;
     RECT  213.905 80.64 214.595 80.664 ;
     RECT  214.115 82.848 214.595 82.872 ;
     RECT  214.085 21.36 214.597 22.2 ;
     RECT  214.597 21.36 214.633 22.728 ;
     RECT  213.304 105.456 214.697 105.48 ;
     RECT  214.633 22.704 214.733 22.728 ;
     RECT  213.875 9.408 214.739 9.432 ;
     RECT  214.652 12.528 214.739 12.552 ;
     RECT  214.559 17.568 214.739 17.592 ;
     RECT  214.093 115.152 214.769 115.176 ;
     RECT  214.892 31.872 214.909 31.896 ;
     RECT  214.633 21.36 214.913 21.384 ;
     RECT  214.909 31.344 214.979 31.896 ;
     RECT  214.693 42.768 214.979 42.792 ;
     RECT  214.94 27.888 215.027 27.912 ;
     RECT  214.979 31.344 215.027 31.368 ;
     RECT  214.94 105.888 215.027 105.912 ;
     RECT  213.82 123.216 215.027 123.24 ;
     RECT  214.057 23.808 215.068 24.648 ;
     RECT  214.481 101.28 215.123 101.304 ;
     RECT  214.067 94.416 215.129 94.44 ;
     RECT  215.132 86.016 215.315 86.04 ;
     RECT  214.307 91.008 215.315 91.032 ;
     RECT  215.269 111.168 215.353 111.192 ;
     RECT  215.077 107.088 215.373 107.112 ;
     RECT  215.125 41.616 215.459 41.64 ;
     RECT  215.269 94.56 215.497 94.584 ;
     RECT  214.445 96.288 215.561 96.408 ;
     RECT  213.304 124.848 215.561 124.872 ;
     RECT  215.516 6.24 215.603 6.264 ;
     RECT  215.068 24.624 215.633 24.648 ;
     RECT  214.373 97.44 215.653 97.464 ;
     RECT  213.941 75.792 215.669 75.816 ;
     RECT  215.612 101.616 215.699 101.64 ;
     RECT  215.629 106.608 215.713 106.824 ;
     RECT  215.653 68.832 215.74 68.856 ;
     RECT  215.653 97.2 215.741 97.464 ;
     RECT  215.375 36.768 215.747 36.792 ;
     RECT  215.713 106.8 215.747 106.824 ;
     RECT  215.629 111.744 215.747 111.768 ;
     RECT  215.741 97.2 216.029 97.224 ;
     RECT  215.269 11.376 216.035 11.4 ;
     RECT  215.948 16.416 216.035 16.44 ;
     RECT  215.948 24.864 216.035 24.888 ;
     RECT  215.948 26.448 216.035 26.472 ;
     RECT  215.663 32.976 216.035 33 ;
    LAYER M5 ;
     RECT  2.4 2.137 2.52 2.151 ;
     RECT  7.8 2.137 7.92 2.151 ;
     RECT  13.2 2.137 13.32 2.151 ;
     RECT  18.6 2.137 18.72 2.151 ;
     RECT  24 2.137 24.12 2.151 ;
     RECT  29.4 2.137 29.52 2.151 ;
     RECT  34.8 2.137 34.92 2.151 ;
     RECT  40.2 2.137 40.32 2.151 ;
     RECT  45.6 2.137 45.72 2.151 ;
     RECT  51 2.137 51.12 2.151 ;
     RECT  56.4 2.137 56.52 2.151 ;
     RECT  61.8 2.137 61.92 2.151 ;
     RECT  67.2 2.137 67.32 2.151 ;
     RECT  72.6 2.137 72.72 2.151 ;
     RECT  78 2.137 78.12 2.151 ;
     RECT  83.4 2.137 83.52 2.151 ;
     RECT  88.8 2.137 88.92 2.151 ;
     RECT  94.2 2.137 94.32 2.151 ;
     RECT  99.6 2.137 99.72 2.151 ;
     RECT  105 2.137 105.12 2.151 ;
     RECT  110.4 2.137 110.52 2.151 ;
     RECT  115.8 2.137 115.92 2.151 ;
     RECT  121.2 2.137 121.32 2.151 ;
     RECT  126.6 2.137 126.72 2.151 ;
     RECT  132 2.137 132.12 2.151 ;
     RECT  137.4 2.137 137.52 2.151 ;
     RECT  142.8 2.137 142.92 2.151 ;
     RECT  148.2 2.137 148.32 2.151 ;
     RECT  153.6 2.137 153.72 2.151 ;
     RECT  159 2.137 159.12 2.151 ;
     RECT  164.4 2.137 164.52 2.151 ;
     RECT  169.8 2.137 169.92 2.151 ;
     RECT  175.2 2.137 175.32 2.151 ;
     RECT  180.6 2.137 180.72 2.151 ;
     RECT  186 2.137 186.12 2.151 ;
     RECT  191.4 2.137 191.52 2.151 ;
     RECT  196.8 2.137 196.92 2.151 ;
     RECT  202.2 2.137 202.32 2.151 ;
     RECT  207.6 2.137 207.72 2.151 ;
     RECT  213 2.137 213.12 2.151 ;
     RECT  4.272 5.077 4.296 6.805 ;
     RECT  5.52 5.077 5.544 6.805 ;
     RECT  4.272 6.805 5.544 7.381 ;
     RECT  213 2.151 213.312 7.765 ;
     RECT  4.272 7.381 5.928 8.485 ;
     RECT  213 7.765 213.864 9.349 ;
     RECT  212.88 9.349 213.864 9.397 ;
     RECT  215.568 6.229 215.592 9.397 ;
     RECT  211.728 9.061 211.752 10.213 ;
     RECT  212.88 9.397 215.592 10.213 ;
     RECT  211.728 10.213 215.592 10.883 ;
     RECT  211.824 10.883 215.592 11.365 ;
     RECT  211.824 11.365 216.024 11.411 ;
     RECT  2.4 2.151 2.712 12.517 ;
     RECT  7.8 2.151 8.112 13.621 ;
     RECT  2.4 12.517 3.288 13.813 ;
     RECT  4.272 8.485 6.072 13.813 ;
     RECT  2.4 13.813 6.072 14.533 ;
     RECT  2.4 14.533 6.168 14.773 ;
     RECT  7.344 13.621 8.112 14.773 ;
     RECT  24 2.151 24.312 15.829 ;
     RECT  211.824 11.411 214.728 15.923 ;
     RECT  20.832 13.333 20.856 15.925 ;
     RECT  13.2 2.151 13.512 16.357 ;
     RECT  23.616 15.829 24.312 16.501 ;
     RECT  27.504 15.925 27.528 16.501 ;
     RECT  29.4 2.151 29.712 16.501 ;
     RECT  27.504 16.501 29.712 17.125 ;
     RECT  211.92 15.923 214.728 17.603 ;
     RECT  9.216 16.501 9.24 17.605 ;
     RECT  2.4 14.773 8.112 18.133 ;
     RECT  9.216 17.605 9.672 18.133 ;
     RECT  18.6 2.151 18.912 18.181 ;
     RECT  13.2 16.357 13.608 18.565 ;
     RECT  32.4 18.181 32.424 18.565 ;
     RECT  17.616 18.181 18.912 19.333 ;
     RECT  19.92 15.925 21.624 19.333 ;
     RECT  17.616 19.333 21.624 19.379 ;
     RECT  20.832 19.379 21.624 19.523 ;
     RECT  27.504 17.125 30.12 19.523 ;
     RECT  28.032 19.523 30.12 19.621 ;
     RECT  13.2 18.565 14.424 19.861 ;
     RECT  13.104 19.861 14.424 19.909 ;
     RECT  32.4 18.565 32.904 20.003 ;
     RECT  2.4 18.133 9.672 20.293 ;
     RECT  11.28 15.925 11.304 20.293 ;
     RECT  20.832 19.523 21.144 20.485 ;
     RECT  23.616 16.501 24.552 20.629 ;
     RECT  211.92 17.603 214.632 21.109 ;
     RECT  22.656 20.629 24.552 21.155 ;
     RECT  20.832 20.485 21.672 21.299 ;
     RECT  32.88 20.003 32.904 21.395 ;
     RECT  13.104 19.909 14.808 21.589 ;
     RECT  16.368 21.061 16.392 21.589 ;
     RECT  24 21.155 24.552 21.637 ;
     RECT  211.824 21.109 214.632 21.781 ;
     RECT  22.656 21.155 22.68 21.973 ;
     RECT  17.616 19.379 19.704 22.165 ;
     RECT  28.032 19.621 30.744 22.165 ;
     RECT  28.032 22.165 30.84 22.259 ;
     RECT  22.416 21.973 22.68 22.309 ;
     RECT  22.416 22.309 22.728 22.549 ;
     RECT  24 21.637 25.032 22.645 ;
     RECT  26.16 17.077 26.184 22.645 ;
     RECT  24 22.645 26.184 22.739 ;
     RECT  22.416 22.549 22.776 22.741 ;
     RECT  24 22.739 24.696 22.741 ;
     RECT  34.8 2.151 35.112 22.741 ;
     RECT  28.08 22.259 30.84 22.787 ;
     RECT  25.92 22.739 26.184 22.835 ;
     RECT  38.592 22.165 38.616 23.075 ;
     RECT  31.872 21.541 31.896 23.125 ;
     RECT  28.08 22.787 30.024 23.171 ;
     RECT  211.44 21.781 214.632 23.173 ;
     RECT  31.056 23.125 31.896 23.267 ;
     RECT  34.704 22.741 35.112 23.267 ;
     RECT  37.008 21.925 37.032 23.269 ;
     RECT  88.8 2.151 89.112 23.269 ;
     RECT  40.2 2.151 40.512 23.317 ;
     RECT  20.832 21.299 21.096 23.411 ;
     RECT  202.2 2.151 202.512 23.557 ;
     RECT  210.864 23.173 214.632 23.797 ;
     RECT  28.08 23.171 29.928 23.843 ;
     RECT  34.8 23.267 35.112 23.845 ;
     RECT  17.424 22.165 19.704 23.893 ;
     RECT  20.832 23.411 20.856 23.893 ;
     RECT  153.6 2.151 153.912 23.893 ;
     RECT  25.92 22.835 25.944 23.987 ;
     RECT  210.864 23.797 215.016 23.987 ;
     RECT  13.104 21.589 16.392 24.133 ;
     RECT  17.424 23.893 20.856 24.133 ;
     RECT  22.416 22.741 24.696 24.277 ;
     RECT  22.176 24.277 24.696 24.371 ;
     RECT  67.2 2.151 67.512 24.373 ;
     RECT  196.8 2.151 197.112 24.373 ;
     RECT  196.8 24.373 198.072 24.421 ;
     RECT  37.008 23.269 37.608 24.517 ;
     RECT  24 24.371 24.696 24.659 ;
     RECT  27.888 24.037 27.912 24.659 ;
     RECT  31.152 23.267 31.896 24.659 ;
     RECT  22.176 24.371 22.728 24.757 ;
     RECT  37.008 24.517 37.8 24.899 ;
     RECT  26.208 24.373 26.232 24.947 ;
     RECT  211.824 23.987 213.864 25.045 ;
     RECT  22.128 24.757 22.728 25.091 ;
     RECT  37.776 24.899 37.8 25.139 ;
     RECT  40.2 23.317 41.352 25.139 ;
     RECT  13.104 24.133 20.856 25.141 ;
     RECT  113.232 23.269 113.256 25.187 ;
     RECT  13.104 25.141 20.904 25.189 ;
     RECT  29.4 23.843 29.928 25.235 ;
     RECT  153.504 23.893 153.912 25.283 ;
     RECT  33.648 22.453 33.672 25.429 ;
     RECT  22.08 25.091 22.728 25.475 ;
     RECT  33.648 25.429 33.816 25.475 ;
     RECT  82.08 23.317 82.104 25.475 ;
     RECT  33.792 25.475 33.816 25.571 ;
     RECT  134.64 25.429 134.664 25.619 ;
     RECT  31.152 24.659 31.176 25.715 ;
     RECT  34.8 23.845 35.208 25.715 ;
     RECT  47.856 24.325 47.88 25.715 ;
     RECT  67.2 24.373 68.376 25.715 ;
     RECT  12.432 25.189 20.904 25.765 ;
     RECT  22.08 25.475 22.68 25.765 ;
     RECT  200.352 24.949 200.376 25.909 ;
     RECT  12.432 25.765 22.68 26.773 ;
     RECT  196.8 24.421 198.168 27.109 ;
     RECT  12.432 26.773 22.776 27.637 ;
     RECT  12.432 27.637 22.824 28.211 ;
     RECT  210.864 25.045 213.864 28.403 ;
     RECT  210.864 28.403 213.72 28.405 ;
     RECT  2.4 20.293 11.304 29.029 ;
     RECT  12.432 28.211 22.776 29.029 ;
     RECT  199.728 25.909 200.376 29.365 ;
     RECT  201.504 23.557 202.512 29.365 ;
     RECT  199.728 29.365 202.512 29.699 ;
     RECT  2.4 29.029 22.776 30.419 ;
     RECT  214.992 23.987 215.016 31.379 ;
     RECT  199.824 29.699 202.512 31.861 ;
     RECT  2.4 30.419 22.68 32.051 ;
     RECT  205.056 29.461 205.08 32.437 ;
     RECT  196.8 27.109 198.264 32.579 ;
     RECT  214.944 31.861 214.968 32.965 ;
     RECT  216 11.411 216.024 32.965 ;
     RECT  214.944 32.965 216.024 33.011 ;
     RECT  196.8 32.579 198.216 35.461 ;
     RECT  196.8 35.461 198.408 35.651 ;
     RECT  199.824 31.861 202.872 35.845 ;
     RECT  2.4 32.051 22.632 36.179 ;
     RECT  210.24 28.405 213.72 36.661 ;
     RECT  209.904 36.661 213.72 36.707 ;
     RECT  214.944 33.011 215.736 36.803 ;
     RECT  204.288 32.437 205.08 37.429 ;
     RECT  206.352 32.965 206.376 37.429 ;
     RECT  199.824 35.845 203.208 37.573 ;
     RECT  204.288 37.429 206.376 37.573 ;
     RECT  211.68 36.707 213.72 37.667 ;
     RECT  211.68 37.667 213.312 38.147 ;
     RECT  2.4 36.179 22.2 38.579 ;
     RECT  2.4 38.579 22.152 38.771 ;
     RECT  199.776 37.573 206.376 39.251 ;
     RECT  205.584 39.251 206.376 39.299 ;
     RECT  207.6 2.151 207.912 39.301 ;
     RECT  209.904 36.707 210.264 39.347 ;
     RECT  206.304 39.299 206.376 39.733 ;
     RECT  207.6 39.301 208.056 39.733 ;
     RECT  196.8 35.651 198.12 40.307 ;
     RECT  206.304 39.733 208.056 40.405 ;
     RECT  205.728 40.405 208.056 40.499 ;
     RECT  210.24 39.347 210.264 40.595 ;
     RECT  199.776 39.251 204.264 41.317 ;
     RECT  205.728 40.499 207.912 41.411 ;
     RECT  214.944 36.803 215.448 41.651 ;
     RECT  207.36 41.411 207.912 41.891 ;
     RECT  199.776 41.317 204.6 41.939 ;
     RECT  205.728 41.411 206.376 42.227 ;
     RECT  214.944 41.651 214.968 42.803 ;
     RECT  196.8 40.307 197.112 45.445 ;
     RECT  198.096 40.307 198.12 45.445 ;
     RECT  199.776 41.939 204.408 47.747 ;
     RECT  199.776 47.747 204.312 48.515 ;
     RECT  199.776 48.515 204.024 49.619 ;
     RECT  201.024 49.619 204.024 52.357 ;
     RECT  196.8 45.445 198.12 53.315 ;
     RECT  196.8 53.315 198.072 54.421 ;
     RECT  200.784 52.357 204.024 56.195 ;
     RECT  199.776 49.619 199.8 56.483 ;
     RECT  207.6 41.891 207.912 57.013 ;
     RECT  200.784 56.195 203.832 57.059 ;
     RECT  2.4 38.771 21.912 57.635 ;
     RECT  200.784 57.059 203.688 57.635 ;
     RECT  3.792 57.635 21.912 58.499 ;
     RECT  3.984 58.499 21.912 58.739 ;
     RECT  201.36 57.635 203.688 58.739 ;
     RECT  196.8 54.421 198.168 58.933 ;
     RECT  10.656 58.739 21.912 59.747 ;
     RECT  3.984 58.739 9.528 59.891 ;
     RECT  202.08 58.739 203.688 60.133 ;
     RECT  9.456 59.891 9.528 60.373 ;
     RECT  10.656 59.747 15.24 60.373 ;
     RECT  9.456 60.373 15.24 60.563 ;
     RECT  2.4 57.635 2.712 60.949 ;
     RECT  3.984 59.891 8.112 60.949 ;
     RECT  201.984 60.133 203.688 60.949 ;
     RECT  15.216 60.563 15.24 61.477 ;
     RECT  9.456 60.563 13.992 61.525 ;
     RECT  15.216 61.477 15.672 61.525 ;
     RECT  201.648 60.949 203.688 61.525 ;
     RECT  201.648 61.525 203.88 62.005 ;
     RECT  9.456 61.525 15.672 62.101 ;
     RECT  16.704 59.747 21.912 62.101 ;
     RECT  9.456 62.101 21.912 62.195 ;
     RECT  2.4 60.949 8.112 62.341 ;
     RECT  201.648 62.005 204.168 62.435 ;
     RECT  2.4 62.341 8.472 63.157 ;
     RECT  10.08 62.195 21.912 63.157 ;
     RECT  201.744 62.435 204.168 63.203 ;
     RECT  201.744 63.203 204.072 64.933 ;
     RECT  212.304 38.147 213.312 65.509 ;
     RECT  2.4 63.157 21.912 66.805 ;
     RECT  200.88 64.933 204.072 67.571 ;
     RECT  206.352 42.227 206.376 67.669 ;
     RECT  207.6 57.013 208.872 67.669 ;
     RECT  200.88 67.571 203.544 68.435 ;
     RECT  205.248 66.373 205.272 68.915 ;
     RECT  200.88 68.435 202.512 69.493 ;
     RECT  203.52 68.435 203.544 69.539 ;
     RECT  200.544 69.493 202.512 71.509 ;
     RECT  200.352 71.509 202.512 71.555 ;
     RECT  212.16 65.509 213.312 72.229 ;
     RECT  206.352 67.669 208.872 72.419 ;
     RECT  212.16 72.229 214.008 74.965 ;
     RECT  200.352 71.555 200.376 75.395 ;
     RECT  211.824 74.965 214.008 75.781 ;
     RECT  215.664 68.821 215.688 75.781 ;
     RECT  211.824 75.781 214.056 76.933 ;
     RECT  201.456 71.555 202.512 79.283 ;
     RECT  2.4 66.805 21.96 79.525 ;
     RECT  211.824 76.933 214.104 80.629 ;
     RECT  215.184 75.781 215.688 80.629 ;
     RECT  2.4 79.525 22.008 81.205 ;
     RECT  211.824 80.629 215.688 83.747 ;
     RECT  2.4 81.205 22.488 84.613 ;
     RECT  212.112 83.747 215.688 85.141 ;
     RECT  2.4 84.613 22.536 85.237 ;
     RECT  211.728 85.141 215.688 86.051 ;
     RECT  2.4 85.237 22.584 88.213 ;
     RECT  211.728 86.051 214.296 89.843 ;
     RECT  206.784 72.419 208.872 89.987 ;
     RECT  215.28 86.051 215.688 94.595 ;
     RECT  211.824 89.843 214.296 94.691 ;
     RECT  2.4 88.213 22.632 94.885 ;
     RECT  212.016 94.691 214.296 95.795 ;
     RECT  215.424 94.595 215.688 96.373 ;
     RECT  212.016 95.795 214.056 96.805 ;
     RECT  215.088 96.373 215.688 96.805 ;
     RECT  2.4 94.885 22.68 98.341 ;
     RECT  2.4 98.341 22.728 98.485 ;
     RECT  45.6 2.151 45.912 98.965 ;
     RECT  29.4 25.235 29.712 99.109 ;
     RECT  206.784 89.987 207.912 100.115 ;
     RECT  212.016 96.805 215.688 100.691 ;
     RECT  56.4 2.151 56.712 100.741 ;
     RECT  61.8 2.151 62.112 100.837 ;
     RECT  31.632 99.253 31.656 100.885 ;
     RECT  34.8 25.715 35.112 100.885 ;
     RECT  51 2.151 51.312 100.885 ;
     RECT  37.296 100.837 37.32 100.981 ;
     RECT  196.8 58.933 198.264 101.075 ;
     RECT  83.4 2.151 83.712 101.077 ;
     RECT  45.6 98.965 46.008 101.125 ;
     RECT  37.008 100.981 37.32 101.171 ;
     RECT  2.4 98.485 22.824 101.173 ;
     RECT  29.28 99.109 29.712 101.173 ;
     RECT  45.024 101.125 46.008 101.173 ;
     RECT  40.2 25.139 40.512 101.221 ;
     RECT  94.2 2.151 94.512 101.317 ;
     RECT  34.8 100.885 35.544 101.365 ;
     RECT  53.568 100.741 53.592 101.365 ;
     RECT  2.4 101.173 23.016 101.413 ;
     RECT  24 24.659 24.312 101.413 ;
     RECT  27.36 100.837 27.384 101.413 ;
     RECT  39.408 101.221 40.512 101.413 ;
     RECT  67.2 25.715 67.512 101.413 ;
     RECT  72.6 2.151 72.912 101.413 ;
     RECT  78 2.151 78.312 101.413 ;
     RECT  83.4 101.077 83.928 101.413 ;
     RECT  2.4 101.413 24.312 101.461 ;
     RECT  2.4 101.461 24.888 101.507 ;
     RECT  54.816 101.365 54.84 101.507 ;
     RECT  43.68 101.173 43.704 101.605 ;
     RECT  21.552 101.507 24.888 101.653 ;
     RECT  34.704 101.365 35.544 101.653 ;
     RECT  49.008 101.173 49.032 101.653 ;
     RECT  28.752 101.173 29.712 101.701 ;
     RECT  27.264 101.413 27.384 101.749 ;
     RECT  28.752 101.701 29.832 101.749 ;
     RECT  43.68 101.605 43.992 101.749 ;
     RECT  45.024 101.173 46.68 101.749 ;
     RECT  53.136 101.365 53.592 101.749 ;
     RECT  48.048 101.653 49.032 101.795 ;
     RECT  52.56 101.749 53.592 101.795 ;
     RECT  52.56 101.795 53.16 101.797 ;
     RECT  21.552 101.653 25.272 101.843 ;
     RECT  48.048 101.795 48.072 101.843 ;
     RECT  66.912 101.413 67.512 101.845 ;
     RECT  196.8 101.075 198.216 101.891 ;
     RECT  56.4 100.741 56.808 101.893 ;
     RECT  33.024 101.413 33.336 101.941 ;
     RECT  34.656 101.653 35.544 101.941 ;
     RECT  27.264 101.749 29.832 101.987 ;
     RECT  52.32 101.797 53.16 101.987 ;
     RECT  66.912 101.845 68.088 101.987 ;
     RECT  33.024 101.941 35.544 101.989 ;
     RECT  33.024 101.989 36.072 102.131 ;
     RECT  58.608 100.837 58.632 102.229 ;
     RECT  60 101.365 60.024 102.229 ;
     RECT  21.888 101.843 25.272 102.277 ;
     RECT  87.12 101.989 87.144 102.277 ;
     RECT  91.248 23.317 91.272 102.277 ;
     RECT  31.344 100.885 31.656 102.469 ;
     RECT  34.56 102.131 36.072 102.469 ;
     RECT  37.056 101.171 37.32 102.469 ;
     RECT  39.408 101.413 41.304 102.469 ;
     RECT  27.264 101.987 27.768 102.563 ;
     RECT  78 101.413 78.408 102.565 ;
     RECT  82.464 101.413 84.024 102.565 ;
     RECT  93.456 101.317 94.512 102.659 ;
     RECT  55.296 101.893 56.808 102.709 ;
     RECT  71.856 101.413 73.224 102.709 ;
     RECT  74.256 100.837 74.28 102.709 ;
     RECT  58.608 102.229 60.024 102.805 ;
     RECT  61.152 100.837 62.112 102.805 ;
     RECT  21.888 102.277 25.8 102.851 ;
     RECT  70.896 102.709 73.224 102.947 ;
     RECT  43.68 101.749 46.68 102.949 ;
     RECT  66.912 101.987 67.992 102.949 ;
     RECT  28.752 101.987 29.832 102.997 ;
     RECT  30.816 102.469 31.656 102.997 ;
     RECT  2.4 101.507 20.424 103.045 ;
     RECT  64.608 101.989 64.632 103.045 ;
     RECT  90.576 102.277 91.272 103.045 ;
     RECT  22.32 102.851 25.8 103.091 ;
     RECT  39.408 102.469 41.64 103.141 ;
     RECT  55.296 102.709 56.856 103.141 ;
     RECT  58.608 102.805 62.112 103.141 ;
     RECT  82.464 102.565 84.888 103.141 ;
     RECT  49.008 103.045 49.032 103.187 ;
     RECT  28.752 102.997 31.656 103.189 ;
     RECT  33.024 102.131 33.336 103.189 ;
     RECT  28.752 103.189 33.336 103.237 ;
     RECT  63.504 101.845 63.528 103.283 ;
     RECT  28.752 103.237 33.384 103.331 ;
     RECT  52.56 101.987 53.16 103.331 ;
     RECT  33.024 103.331 33.384 103.333 ;
     RECT  34.56 102.469 37.32 103.333 ;
     RECT  42.72 102.949 46.68 103.477 ;
     RECT  50.88 100.885 51.312 103.477 ;
     RECT  82.464 103.141 85.128 103.477 ;
     RECT  196.8 101.891 197.736 103.523 ;
     RECT  88.416 23.269 89.112 103.573 ;
     RECT  74.256 102.709 74.424 103.669 ;
     RECT  58.608 103.141 62.472 103.717 ;
     RECT  79.776 101.413 80.424 103.765 ;
     RECT  28.752 103.331 31.896 103.811 ;
     RECT  77.856 102.565 78.408 103.811 ;
     RECT  58.608 103.717 63.288 103.907 ;
     RECT  27.264 102.563 27.384 103.957 ;
     RECT  79.488 103.765 80.424 104.005 ;
     RECT  79.488 104.005 80.616 104.051 ;
     RECT  76.08 101.413 76.776 104.099 ;
     RECT  25.584 103.091 25.8 104.101 ;
     RECT  95.76 103.717 95.784 104.101 ;
     RECT  92.4 103.333 92.424 104.197 ;
     RECT  94.2 102.659 94.512 104.197 ;
     RECT  33.024 103.333 37.32 104.339 ;
     RECT  22.32 103.091 24.6 104.389 ;
     RECT  25.584 104.101 26.136 104.389 ;
     RECT  70.368 102.949 70.392 104.389 ;
     RECT  90.528 103.045 91.272 104.485 ;
     RECT  92.4 104.197 94.512 104.485 ;
     RECT  64.608 103.045 65.064 104.531 ;
     RECT  76.32 104.099 76.776 104.579 ;
     RECT  52.56 103.331 53.064 104.677 ;
     RECT  2.4 103.045 21.288 104.869 ;
     RECT  22.32 104.389 26.136 104.869 ;
     RECT  58.608 103.907 62.112 104.965 ;
     RECT  63.264 103.907 63.288 104.965 ;
     RECT  2.4 104.869 26.136 105.059 ;
     RECT  71.856 102.947 73.224 105.301 ;
     RECT  58.608 104.965 63.288 105.397 ;
     RECT  71.616 105.301 73.224 105.397 ;
     RECT  81.696 103.477 85.128 105.397 ;
     RECT  55.296 103.141 57.048 105.445 ;
     RECT  212.112 100.691 215.688 105.635 ;
     RECT  71.52 105.397 73.224 105.637 ;
     RECT  74.256 103.669 74.712 105.637 ;
     RECT  99.6 2.151 99.912 105.685 ;
     RECT  28.752 103.811 29.832 105.781 ;
     RECT  30.816 103.811 31.896 105.781 ;
     RECT  55.296 105.445 57.192 105.875 ;
     RECT  77.904 103.811 78.408 106.021 ;
     RECT  86.208 102.277 87.144 106.165 ;
     RECT  88.416 103.573 89.352 106.165 ;
     RECT  86.208 106.165 89.352 106.211 ;
     RECT  33.12 104.339 37.32 106.261 ;
     RECT  38.64 103.141 41.64 106.451 ;
     RECT  55.488 105.875 57.192 106.453 ;
     RECT  58.56 105.397 63.288 106.453 ;
     RECT  81.696 105.397 85.176 106.501 ;
     RECT  86.208 106.211 86.232 106.501 ;
     RECT  81.696 106.501 86.232 106.547 ;
     RECT  55.488 106.453 63.288 106.595 ;
     RECT  33.072 106.261 37.32 106.739 ;
     RECT  212.16 105.635 215.688 106.789 ;
     RECT  76.32 104.579 76.728 106.837 ;
     RECT  101.904 104.389 101.928 107.123 ;
     RECT  42.72 103.477 47.592 107.125 ;
     RECT  50.832 103.477 51.312 107.125 ;
     RECT  54.432 106.549 54.456 107.125 ;
     RECT  55.488 106.595 60.312 107.125 ;
     RECT  38.64 106.451 38.664 107.219 ;
     RECT  90.528 104.485 94.512 107.219 ;
     RECT  2.4 105.059 21.192 107.221 ;
     RECT  22.32 105.059 26.136 107.221 ;
     RECT  80.592 104.051 80.616 107.221 ;
     RECT  81.696 106.547 86.136 107.221 ;
     RECT  2.4 107.221 26.136 107.267 ;
     RECT  64.656 104.531 65.064 107.267 ;
     RECT  80.592 107.221 86.136 107.267 ;
     RECT  50.688 107.125 51.312 107.509 ;
     RECT  52.56 104.677 53.304 107.509 ;
     RECT  91.632 107.219 94.512 107.605 ;
     RECT  50.688 107.509 53.304 107.651 ;
     RECT  69.648 104.389 70.392 107.651 ;
     RECT  52.56 107.651 53.304 107.653 ;
     RECT  54.432 107.125 60.312 107.653 ;
     RECT  33.072 106.739 36.12 107.699 ;
     RECT  97.968 105.157 97.992 107.747 ;
     RECT  95.76 104.101 96.696 107.749 ;
     RECT  2.4 107.267 20.424 107.795 ;
     RECT  71.52 105.637 74.712 107.795 ;
     RECT  95.616 107.749 96.696 107.795 ;
     RECT  39.648 106.451 41.64 107.797 ;
     RECT  42.72 107.125 48.36 107.797 ;
     RECT  64.752 107.267 65.064 107.797 ;
     RECT  39.648 107.797 48.36 107.843 ;
     RECT  27.264 103.957 27.72 107.941 ;
     RECT  39.648 107.843 42.264 107.989 ;
     RECT  52.56 107.653 60.312 108.085 ;
     RECT  61.536 106.595 63.288 108.085 ;
     RECT  99.024 105.685 99.912 108.085 ;
     RECT  11.184 107.795 20.424 108.179 ;
     RECT  50.688 107.651 51.312 108.229 ;
     RECT  52.56 108.085 63.288 108.275 ;
     RECT  69.648 107.651 70.296 108.277 ;
     RECT  71.712 107.795 74.712 108.277 ;
     RECT  34.704 107.699 36.12 108.325 ;
     RECT  37.2 106.739 37.32 108.325 ;
     RECT  80.832 107.267 86.136 108.325 ;
     RECT  90.528 107.219 90.552 108.325 ;
     RECT  91.632 107.605 94.632 108.325 ;
     RECT  95.616 107.795 95.64 108.325 ;
     RECT  21.504 107.267 26.136 108.371 ;
     RECT  79.488 104.051 79.512 108.371 ;
     RECT  90.528 108.325 95.64 108.371 ;
     RECT  49.968 108.229 51.312 108.563 ;
     RECT  43.68 107.843 48.36 108.565 ;
     RECT  71.712 108.277 74.856 108.661 ;
     RECT  34.704 108.325 37.32 108.707 ;
     RECT  50.16 108.563 51.312 108.709 ;
     RECT  87.744 106.211 89.352 108.709 ;
     RECT  90.528 108.371 91.224 108.709 ;
     RECT  39.6 107.989 42.264 108.805 ;
     RECT  54.432 108.275 63.288 108.805 ;
     RECT  80.832 108.325 86.616 108.805 ;
     RECT  87.744 108.709 91.224 108.805 ;
     RECT  92.352 108.371 95.64 108.805 ;
     RECT  96.672 107.795 96.696 108.805 ;
     RECT  22.896 108.371 26.136 108.851 ;
     RECT  54.432 108.805 63.576 108.851 ;
     RECT  92.352 108.805 96.696 108.851 ;
     RECT  33.072 107.699 33.24 108.853 ;
     RECT  43.68 108.565 49.176 108.853 ;
     RECT  80.832 108.805 91.224 108.899 ;
     RECT  43.296 108.853 49.176 108.995 ;
     RECT  64.752 107.797 65.256 108.995 ;
     RECT  69.456 108.277 70.296 109.093 ;
     RECT  71.712 108.661 75.192 109.093 ;
     RECT  66.384 102.949 67.992 109.141 ;
     RECT  92.352 108.851 94.728 109.187 ;
     RECT  34.704 108.707 36.12 109.285 ;
     RECT  79.824 108.805 79.848 109.285 ;
     RECT  80.832 108.899 89.112 109.285 ;
     RECT  43.584 108.995 49.176 109.331 ;
     RECT  79.824 109.285 89.112 109.331 ;
     RECT  38.64 108.805 42.264 109.333 ;
     RECT  27.12 107.941 27.72 109.379 ;
     RECT  80.112 109.331 89.112 109.427 ;
     RECT  95.712 108.851 96.696 109.427 ;
     RECT  37.2 108.707 37.32 109.525 ;
     RECT  38.64 109.333 42.312 109.525 ;
     RECT  43.584 109.331 49.128 109.571 ;
     RECT  44.88 109.571 49.128 109.859 ;
     RECT  69.456 109.093 75.192 109.909 ;
     RECT  22.896 108.851 25.752 109.955 ;
     RECT  11.184 108.179 20.328 109.957 ;
     RECT  21.504 108.371 21.528 109.957 ;
     RECT  63.552 108.851 63.576 109.957 ;
     RECT  86.592 109.427 89.112 109.957 ;
     RECT  90.288 108.899 91.224 109.957 ;
     RECT  11.184 109.957 21.528 110.003 ;
     RECT  54.432 108.851 62.52 110.003 ;
     RECT  27.12 109.379 27.576 110.005 ;
     RECT  212.16 106.789 215.736 110.051 ;
     RECT  37.2 109.525 42.312 110.147 ;
     RECT  50.16 108.709 51.528 110.147 ;
     RECT  80.112 109.427 85.512 110.147 ;
     RECT  33.072 108.853 33.336 110.389 ;
     RECT  34.32 109.285 36.12 110.389 ;
     RECT  86.592 109.957 91.224 110.389 ;
     RECT  50.448 110.147 51.528 110.437 ;
     RECT  52.56 108.275 53.448 110.437 ;
     RECT  63.552 109.957 63.816 110.437 ;
     RECT  65.232 108.995 65.256 110.437 ;
     RECT  69.408 109.909 75.192 110.483 ;
     RECT  28.752 105.781 31.896 110.485 ;
     RECT  77.904 106.021 78.504 110.485 ;
     RECT  80.112 110.147 80.904 110.485 ;
     RECT  96.672 109.427 96.696 110.533 ;
     RECT  54.432 110.003 58.92 110.579 ;
     RECT  97.728 109.765 97.752 110.579 ;
     RECT  82.032 110.147 85.512 110.627 ;
     RECT  63.552 110.437 65.256 110.675 ;
     RECT  64.656 110.675 65.256 110.771 ;
     RECT  33.072 110.389 36.12 110.867 ;
     RECT  71.712 110.483 75.192 110.915 ;
     RECT  77.904 110.485 80.904 110.915 ;
     RECT  50.448 110.437 53.448 111.061 ;
     RECT  54.432 110.579 57.912 111.061 ;
     RECT  37.2 110.147 42.12 111.107 ;
     RECT  23.712 109.955 25.752 111.109 ;
     RECT  26.832 110.005 27.576 111.109 ;
     RECT  60 110.003 62.52 111.109 ;
     RECT  63.552 110.675 63.576 111.109 ;
     RECT  11.184 110.003 21.144 111.203 ;
     RECT  82.032 110.627 84.984 111.203 ;
     RECT  82.032 111.203 84.024 111.299 ;
     RECT  50.448 111.061 57.912 111.347 ;
     RECT  60 111.109 63.576 111.347 ;
     RECT  37.2 111.107 37.272 111.491 ;
     RECT  92.64 109.187 94.728 111.491 ;
     RECT  33.12 110.867 36.12 111.539 ;
     RECT  98.832 108.085 99.912 111.587 ;
     RECT  22.464 111.205 22.488 111.589 ;
     RECT  23.712 111.109 27.576 111.589 ;
     RECT  28.656 110.485 31.896 111.589 ;
     RECT  69.408 110.483 70.728 111.589 ;
     RECT  71.712 110.915 73.368 111.589 ;
     RECT  86.592 110.389 91.272 111.635 ;
     RECT  76.32 106.837 76.92 111.731 ;
     RECT  82.032 111.299 83.928 111.779 ;
     RECT  212.352 110.051 215.736 111.779 ;
     RECT  33.312 111.539 36.12 111.923 ;
     RECT  50.448 111.347 54.456 111.923 ;
     RECT  86.592 111.635 86.616 111.925 ;
     RECT  69.408 111.589 73.368 111.971 ;
     RECT  86.4 111.925 86.616 111.971 ;
     RECT  87.744 111.635 91.272 112.021 ;
     RECT  87.744 112.021 91.464 112.067 ;
     RECT  2.4 107.795 10.2 112.069 ;
     RECT  11.184 111.203 19.32 112.069 ;
     RECT  94.032 111.491 94.728 112.069 ;
     RECT  95.712 110.533 96.696 112.069 ;
     RECT  50.448 111.923 51.432 112.115 ;
     RECT  44.88 109.859 48.408 112.117 ;
     RECT  92.64 111.491 92.952 112.117 ;
     RECT  55.488 111.347 57.912 112.261 ;
     RECT  58.896 110.579 58.92 112.261 ;
     RECT  66.384 109.141 68.424 112.309 ;
     RECT  69.408 111.971 70.296 112.309 ;
     RECT  94.032 112.069 96.696 112.355 ;
     RECT  71.28 111.971 73.368 112.405 ;
     RECT  74.448 110.915 75.192 112.405 ;
     RECT  20.304 111.203 21.144 112.499 ;
     RECT  22.464 111.589 31.896 112.499 ;
     RECT  44.88 112.117 48.984 112.597 ;
     RECT  44.88 112.597 49.032 112.643 ;
     RECT  66.384 112.309 70.296 112.787 ;
     RECT  45.216 112.643 49.032 112.931 ;
     RECT  52.416 111.923 54.456 112.931 ;
     RECT  94.032 112.355 96.072 112.931 ;
     RECT  71.28 112.405 75.192 112.933 ;
     RECT  76.32 111.731 76.632 112.933 ;
     RECT  64.656 110.771 65.112 113.077 ;
     RECT  94.2 112.931 96.072 113.171 ;
     RECT  48.336 112.931 49.032 113.219 ;
     RECT  37.248 111.491 37.272 113.221 ;
     RECT  36.912 113.221 37.272 113.267 ;
     RECT  71.28 112.933 76.632 113.315 ;
     RECT  92.592 112.117 92.952 113.459 ;
     RECT  36.912 113.267 37.128 113.555 ;
     RECT  77.904 110.915 78.696 113.555 ;
     RECT  20.304 112.499 20.76 113.605 ;
     RECT  38.304 111.107 42.12 113.653 ;
     RECT  33.312 111.923 35.928 113.701 ;
     RECT  36.912 113.555 36.936 113.701 ;
     RECT  86.4 111.971 86.568 113.795 ;
     RECT  20.304 113.605 20.904 113.845 ;
     RECT  23.568 112.499 31.896 113.845 ;
     RECT  33.312 113.701 36.936 113.845 ;
     RECT  82.032 111.779 82.056 113.845 ;
     RECT  83.232 111.779 83.928 113.845 ;
     RECT  54.432 112.931 54.456 113.893 ;
     RECT  55.488 112.261 58.92 113.893 ;
     RECT  52.416 112.931 53.448 114.035 ;
     RECT  79.728 110.915 80.904 114.035 ;
     RECT  66.384 112.787 69.24 114.227 ;
     RECT  38.304 113.653 42.504 114.275 ;
     RECT  60 111.347 62.52 114.373 ;
     RECT  63.552 111.347 63.576 114.373 ;
     RECT  23.568 113.845 36.936 114.419 ;
     RECT  60 114.373 63.576 114.419 ;
     RECT  43.584 109.571 43.608 114.517 ;
     RECT  45.216 112.931 47.256 114.517 ;
     RECT  48.336 113.219 48.36 114.517 ;
     RECT  49.44 113.605 49.464 114.517 ;
     RECT  92.64 113.459 92.952 114.517 ;
     RECT  94.2 113.171 94.728 114.517 ;
     RECT  2.4 112.069 19.32 114.611 ;
     RECT  20.304 113.845 21.144 114.611 ;
     RECT  54.432 113.893 58.92 114.611 ;
     RECT  71.28 113.315 76.536 114.611 ;
     RECT  212.352 111.779 215.016 114.611 ;
     RECT  2.4 114.611 11.688 114.659 ;
     RECT  23.568 114.419 29.976 114.661 ;
     RECT  38.304 114.275 42.12 114.707 ;
     RECT  38.4 114.707 42.12 114.899 ;
     RECT  20.88 114.611 21.144 114.901 ;
     RECT  43.584 114.517 47.256 114.901 ;
     RECT  71.28 114.611 73.56 114.995 ;
     RECT  20.88 114.901 21.288 115.043 ;
     RECT  20.88 115.043 21.144 115.139 ;
     RECT  11.28 114.659 11.688 115.187 ;
     RECT  31.2 114.419 36.936 115.187 ;
     RECT  48.336 114.517 49.464 115.187 ;
     RECT  52.464 114.035 53.448 115.187 ;
     RECT  38.4 114.899 41.784 115.235 ;
     RECT  31.2 115.187 32.04 115.379 ;
     RECT  92.64 114.517 94.728 115.379 ;
     RECT  33.216 115.187 36.936 115.427 ;
     RECT  82.032 113.845 83.928 115.429 ;
     RECT  85.248 112.069 85.272 115.429 ;
     RECT  52.896 115.187 53.448 115.475 ;
     RECT  82.032 115.429 85.272 115.475 ;
     RECT  23.472 114.661 29.976 115.619 ;
     RECT  43.392 114.901 47.256 115.669 ;
     RECT  48.336 115.187 48.36 115.669 ;
     RECT  54.432 114.611 58.536 115.669 ;
     RECT  96.048 113.171 96.072 115.715 ;
     RECT  22.464 112.499 22.488 115.717 ;
     RECT  23.472 115.619 25.752 115.717 ;
     RECT  12.72 114.611 19.32 115.763 ;
     RECT  54.432 115.669 58.776 115.763 ;
     RECT  80.112 114.035 80.904 115.763 ;
     RECT  87.744 112.067 90.312 115.811 ;
     RECT  71.328 114.995 73.56 115.859 ;
     RECT  60 114.419 63.48 115.907 ;
     RECT  77.904 113.555 78.6 116.005 ;
     RECT  22.464 115.717 25.752 116.051 ;
     RECT  50.544 112.115 51.432 116.101 ;
     RECT  61.536 115.907 63.48 116.147 ;
     RECT  2.4 114.659 10.2 116.195 ;
     RECT  32.016 115.379 32.04 116.293 ;
     RECT  33.216 115.427 35.208 116.293 ;
     RECT  14.976 115.763 19.32 116.339 ;
     RECT  32.016 116.293 35.208 116.339 ;
     RECT  43.392 115.669 48.36 116.339 ;
     RECT  82.032 115.475 84.648 116.339 ;
     RECT  86.4 113.795 86.424 116.339 ;
     RECT  66.384 114.227 68.184 116.341 ;
     RECT  69.216 114.227 69.24 116.341 ;
     RECT  66.384 116.341 69.24 116.387 ;
     RECT  63.456 116.147 63.48 116.389 ;
     RECT  64.656 113.077 65.256 116.389 ;
     RECT  23.472 116.051 25.752 116.435 ;
     RECT  34.272 116.339 35.208 116.483 ;
     RECT  44.256 116.339 48.36 116.483 ;
     RECT  77.808 116.005 78.6 116.483 ;
     RECT  32.016 116.339 33.24 116.627 ;
     RECT  54.432 115.763 56.712 116.627 ;
     RECT  22.464 116.051 22.488 116.819 ;
     RECT  26.736 115.619 29.976 116.821 ;
     RECT  25.776 116.821 29.976 116.867 ;
     RECT  15.264 116.339 19.32 116.915 ;
     RECT  34.272 116.483 35.112 116.915 ;
     RECT  36.432 115.427 36.936 116.915 ;
     RECT  45.168 116.483 48.36 116.915 ;
     RECT  60 115.907 60.216 116.915 ;
     RECT  54.432 116.627 54.456 117.347 ;
     RECT  74.976 114.611 75.624 117.347 ;
     RECT  55.488 116.627 56.712 117.349 ;
     RECT  57.84 115.763 58.776 117.349 ;
     RECT  39.888 115.235 41.784 117.397 ;
     RECT  71.328 115.859 71.352 117.397 ;
     RECT  11.28 115.187 11.64 117.443 ;
     RECT  15.264 116.915 16.44 117.443 ;
     RECT  38.4 115.235 38.904 117.443 ;
     RECT  45.168 116.915 46.632 117.443 ;
     RECT  39.888 117.397 42.6 117.493 ;
     RECT  39.888 117.493 42.792 117.539 ;
     RECT  71.28 117.397 71.352 117.539 ;
     RECT  28.752 116.867 29.976 117.589 ;
     RECT  38.832 117.443 38.904 117.589 ;
     RECT  39.888 117.539 41.784 117.589 ;
     RECT  47.952 116.915 48.36 117.589 ;
     RECT  38.832 117.589 41.784 117.731 ;
     RECT  17.664 116.915 19.32 117.779 ;
     RECT  45.168 117.443 46.152 117.827 ;
     RECT  42.768 117.539 42.792 117.875 ;
     RECT  66.384 116.387 68.904 117.925 ;
     RECT  2.4 116.195 9.576 118.019 ;
     RECT  16.416 117.443 16.44 118.019 ;
     RECT  25.776 116.867 27.192 118.019 ;
     RECT  40.2 117.731 41.784 118.019 ;
     RECT  47.952 117.589 48.456 118.019 ;
     RECT  60.192 116.915 60.216 118.019 ;
     RECT  63.456 116.389 65.256 118.019 ;
     RECT  66.336 117.925 68.904 118.019 ;
     RECT  80.112 115.763 80.664 118.019 ;
     RECT  92.64 115.379 94.512 118.019 ;
     RECT  212.352 114.611 213.312 118.019 ;
     RECT  70.272 112.787 70.296 118.021 ;
     RECT  71.28 117.539 71.304 118.021 ;
     RECT  74.976 117.347 75.096 118.067 ;
     RECT  87.744 115.811 89.4 118.067 ;
     RECT  50.544 116.101 51.912 118.163 ;
     RECT  36.912 116.915 36.936 118.165 ;
     RECT  70.272 118.021 71.304 118.307 ;
     RECT  87.744 118.067 89.112 118.309 ;
     RECT  87.552 118.309 89.112 118.451 ;
     RECT  34.704 116.915 35.112 118.453 ;
     RECT  2.4 118.019 4.824 118.595 ;
     RECT  5.904 118.019 8.424 118.595 ;
     RECT  9.552 118.019 9.576 118.595 ;
     RECT  11.424 117.443 11.64 118.595 ;
     RECT  12.72 115.763 13.944 118.595 ;
     RECT  17.76 117.779 19.32 118.595 ;
     RECT  20.88 115.139 20.904 118.595 ;
     RECT  28.752 117.589 30.12 118.595 ;
     RECT  32.688 116.627 33.24 118.595 ;
     RECT  61.536 116.147 62.232 118.595 ;
     RECT  66.336 118.019 67.512 118.595 ;
     RECT  70.272 118.307 70.296 118.595 ;
     RECT  72.48 115.859 73.56 118.595 ;
     RECT  75.072 118.067 75.096 118.595 ;
     RECT  91.44 112.067 91.464 118.595 ;
     RECT  36.912 118.165 37.608 118.643 ;
     RECT  82.032 116.339 82.2 118.643 ;
     RECT  48.432 118.019 48.456 118.691 ;
     RECT  82.176 118.643 82.2 118.739 ;
     RECT  23.472 116.435 24.792 118.787 ;
     RECT  51 118.163 51.912 118.835 ;
     RECT  34.704 118.453 35.256 118.931 ;
     RECT  45.168 117.827 46.008 118.931 ;
     RECT  55.488 117.349 58.776 118.979 ;
     RECT  77.808 116.483 78.408 118.979 ;
     RECT  28.752 118.595 29.832 119.029 ;
     RECT  61.68 118.595 62.112 119.123 ;
     RECT  2.4 118.595 3.624 119.171 ;
     RECT  4.752 118.595 4.824 119.171 ;
     RECT  5.904 118.595 5.928 119.171 ;
     RECT  7.152 118.595 8.424 119.171 ;
     RECT  11.424 118.595 11.448 119.171 ;
     RECT  22.416 117.397 22.44 119.171 ;
     RECT  83.4 116.339 84.648 119.171 ;
     RECT  88.704 118.451 89.112 119.171 ;
     RECT  23.904 118.787 24.792 119.219 ;
     RECT  28.272 119.029 29.832 119.219 ;
     RECT  34.704 118.931 35.112 119.219 ;
     RECT  37.584 118.643 37.608 119.219 ;
     RECT  38.832 117.731 38.904 119.219 ;
     RECT  41.76 118.019 41.784 119.219 ;
     RECT  65.232 118.019 65.256 119.219 ;
     RECT  71.28 118.307 71.304 119.219 ;
     RECT  58.512 118.979 58.776 119.363 ;
     RECT  7.8 119.171 8.424 119.509 ;
     RECT  23.904 119.219 24.312 119.555 ;
     RECT  26.736 118.019 27.192 119.651 ;
     RECT  4.8 119.171 4.824 119.747 ;
     RECT  64.032 119.749 64.056 119.987 ;
     RECT  33.216 118.595 33.24 120.083 ;
     RECT  28.272 119.219 28.296 120.085 ;
     RECT  34.8 119.219 35.112 120.085 ;
     RECT  45.6 118.931 46.008 120.229 ;
     RECT  26.736 119.651 26.76 120.323 ;
     RECT  20.832 119.509 20.856 120.613 ;
     RECT  49.44 115.187 49.464 120.613 ;
     RECT  34.8 120.085 35.64 120.757 ;
     RECT  93.456 118.019 94.512 120.803 ;
     RECT  83.4 119.171 83.712 120.805 ;
     RECT  24 119.555 24.312 120.853 ;
     RECT  7.8 119.509 9.096 120.899 ;
     RECT  7.8 120.899 8.424 120.947 ;
     RECT  34.176 120.757 35.64 121.093 ;
     RECT  77.808 118.979 78.312 121.139 ;
     RECT  72.48 118.595 72.912 121.141 ;
     RECT  45.6 120.229 46.344 121.285 ;
     RECT  27.888 120.085 28.296 121.379 ;
     RECT  82.656 120.805 83.712 121.379 ;
     RECT  2.4 119.171 2.712 121.381 ;
     RECT  10.272 121.285 10.296 121.381 ;
     RECT  38.88 119.219 38.904 121.381 ;
     RECT  40.2 118.019 40.512 121.381 ;
     RECT  20.832 120.613 21.096 121.427 ;
     RECT  80.64 118.019 80.664 121.475 ;
     RECT  28.272 121.379 28.296 121.571 ;
     RECT  33.504 121.093 35.64 121.619 ;
     RECT  213 118.019 213.312 121.669 ;
     RECT  24 120.853 24.408 121.717 ;
     RECT  20.832 121.427 20.856 121.907 ;
     RECT  6.048 121.333 6.072 121.957 ;
     RECT  7.8 120.947 8.112 121.957 ;
     RECT  29.4 119.219 29.832 121.957 ;
     RECT  51 118.835 51.312 121.957 ;
     RECT  16.512 120.613 16.536 122.003 ;
     RECT  33.504 121.619 33.528 122.003 ;
     RECT  10.224 121.381 10.296 122.101 ;
     RECT  23.328 121.717 24.408 122.101 ;
     RECT  45.6 121.285 46.632 122.101 ;
     RECT  34.8 121.619 35.64 122.291 ;
     RECT  63.888 121.381 63.912 122.339 ;
     RECT  15.312 120.229 15.336 122.387 ;
     RECT  13.2 118.595 13.512 122.389 ;
     RECT  60.528 120.085 60.552 122.389 ;
     RECT  61.8 119.123 62.112 122.389 ;
     RECT  75.792 120.085 75.816 122.435 ;
     RECT  2.4 121.381 3.144 122.485 ;
     RECT  4.56 121.909 4.584 122.485 ;
     RECT  17.904 118.595 18.912 122.485 ;
     RECT  32.112 121.909 32.136 122.485 ;
     RECT  38.88 121.381 40.512 122.485 ;
     RECT  58.512 119.363 58.536 122.485 ;
     RECT  72.288 121.141 72.912 122.533 ;
     RECT  11.616 121.957 11.64 122.579 ;
     RECT  13.2 122.389 14.424 122.579 ;
     RECT  29.088 121.957 29.832 122.579 ;
     RECT  58.512 122.485 59.352 122.579 ;
     RECT  69.744 120.229 69.768 122.579 ;
     RECT  2.4 122.485 4.584 122.627 ;
     RECT  10.224 122.101 10.584 122.627 ;
     RECT  49.44 120.613 49.992 122.629 ;
     RECT  10.224 122.627 10.248 122.675 ;
     RECT  32.016 122.485 32.136 122.723 ;
     RECT  17.136 122.485 18.912 122.771 ;
     RECT  51 121.957 52.248 122.771 ;
     RECT  55.488 118.979 56.808 122.773 ;
     RECT  26.496 121.957 26.52 122.915 ;
     RECT  49.056 122.629 49.992 123.061 ;
     RECT  51 122.771 51.432 123.061 ;
     RECT  4.56 122.627 4.584 123.107 ;
     RECT  38.736 122.485 40.512 123.155 ;
     RECT  23.328 122.101 24.504 123.251 ;
     RECT  42.768 122.485 42.792 123.251 ;
     RECT  71.856 122.533 72.912 123.251 ;
     RECT  214.992 114.611 215.016 123.251 ;
     RECT  53.424 115.475 53.448 123.253 ;
     RECT  53.424 123.253 54.168 123.299 ;
     RECT  67.2 118.595 67.512 123.301 ;
     RECT  17.136 122.771 17.16 123.491 ;
     RECT  54.144 123.299 54.168 123.685 ;
     RECT  55.488 122.773 57.576 123.685 ;
     RECT  6.048 121.957 8.112 123.731 ;
     RECT  39.312 123.155 40.512 123.731 ;
     RECT  54.144 123.685 57.576 123.731 ;
     RECT  24 123.251 24.504 123.779 ;
     RECT  29.088 122.579 29.712 123.779 ;
     RECT  49.056 123.061 51.432 123.779 ;
     RECT  43.872 123.397 43.896 123.781 ;
     RECT  49.536 123.779 51.432 123.827 ;
     RECT  50.688 123.827 51.432 124.019 ;
     RECT  72.288 123.251 72.912 124.067 ;
     RECT  34.8 122.291 35.352 124.307 ;
     RECT  51 124.019 51.432 124.307 ;
     RECT  43.536 123.781 43.896 124.403 ;
     RECT  67.2 123.301 68.424 124.403 ;
     RECT  60.528 122.389 62.112 124.547 ;
     RECT  61.056 124.547 62.112 124.883 ;
     RECT  213 121.669 213.768 124.883 ;
     RECT  54.576 123.731 57 124.979 ;
     RECT  55.488 124.979 57 125.075 ;
     RECT  51 124.307 51.312 125.077 ;
     RECT  32.016 122.723 32.04 125.123 ;
     RECT  59.328 122.579 59.352 125.123 ;
     RECT  61.488 124.883 62.112 125.459 ;
     RECT  50.832 125.077 51.312 125.555 ;
     RECT  6.864 123.731 8.112 125.603 ;
     RECT  41.52 123.205 41.544 125.651 ;
     RECT  43.872 124.403 43.896 126.035 ;
     RECT  49.536 123.827 49.56 126.035 ;
     RECT  45.6 122.101 46.728 126.179 ;
     RECT  2.4 122.627 2.712 127.449 ;
     RECT  7.8 125.603 8.112 127.449 ;
     RECT  13.2 122.579 13.512 127.449 ;
     RECT  18.6 122.771 18.912 127.449 ;
     RECT  24 123.779 24.312 127.449 ;
     RECT  29.4 123.779 29.712 127.449 ;
     RECT  34.8 124.307 35.112 127.449 ;
     RECT  40.2 123.731 40.512 127.449 ;
     RECT  45.6 126.179 45.912 127.449 ;
     RECT  51 125.555 51.312 127.449 ;
     RECT  55.488 125.075 56.712 127.449 ;
     RECT  61.8 125.459 62.112 127.449 ;
     RECT  67.2 124.403 67.512 127.449 ;
     RECT  72.6 124.067 72.912 127.449 ;
     RECT  78 121.139 78.312 127.449 ;
     RECT  83.4 121.379 83.712 127.449 ;
     RECT  88.8 119.171 89.112 127.449 ;
     RECT  94.2 120.803 94.512 127.449 ;
     RECT  99.6 111.587 99.912 127.449 ;
     RECT  105 2.151 105.312 127.449 ;
     RECT  110.4 2.151 110.712 127.449 ;
     RECT  115.8 2.151 116.112 127.449 ;
     RECT  121.2 2.151 121.512 127.449 ;
     RECT  126.6 2.151 126.912 127.449 ;
     RECT  132 2.151 132.312 127.449 ;
     RECT  137.4 2.151 137.712 127.449 ;
     RECT  142.8 2.151 143.112 127.449 ;
     RECT  148.2 2.151 148.512 127.449 ;
     RECT  153.6 25.283 153.912 127.449 ;
     RECT  159 2.151 159.312 127.449 ;
     RECT  164.4 2.151 164.712 127.449 ;
     RECT  169.8 2.151 170.112 127.449 ;
     RECT  175.2 2.151 175.512 127.449 ;
     RECT  180.6 2.151 180.912 127.449 ;
     RECT  186 2.151 186.312 127.449 ;
     RECT  191.4 2.151 191.712 127.449 ;
     RECT  196.8 103.523 197.112 127.449 ;
     RECT  202.2 79.283 202.512 127.449 ;
     RECT  207.6 100.115 207.912 127.449 ;
     RECT  213 124.883 213.312 127.449 ;
     RECT  2.4 127.449 2.52 127.463 ;
     RECT  7.8 127.449 7.92 127.463 ;
     RECT  13.2 127.449 13.32 127.463 ;
     RECT  18.6 127.449 18.72 127.463 ;
     RECT  24 127.449 24.12 127.463 ;
     RECT  29.4 127.449 29.52 127.463 ;
     RECT  34.8 127.449 34.92 127.463 ;
     RECT  40.2 127.449 40.32 127.463 ;
     RECT  45.6 127.449 45.72 127.463 ;
     RECT  51 127.449 51.12 127.463 ;
     RECT  55.488 127.449 56.52 127.463 ;
     RECT  61.8 127.449 61.92 127.463 ;
     RECT  67.2 127.449 67.32 127.463 ;
     RECT  72.6 127.449 72.72 127.463 ;
     RECT  78 127.449 78.12 127.463 ;
     RECT  83.4 127.449 83.52 127.463 ;
     RECT  88.8 127.449 88.92 127.463 ;
     RECT  94.2 127.449 94.32 127.463 ;
     RECT  99.6 127.449 99.72 127.463 ;
     RECT  105 127.449 105.12 127.463 ;
     RECT  110.4 127.449 110.52 127.463 ;
     RECT  115.8 127.449 115.92 127.463 ;
     RECT  121.2 127.449 121.32 127.463 ;
     RECT  126.6 127.449 126.72 127.463 ;
     RECT  132 127.449 132.12 127.463 ;
     RECT  137.4 127.449 137.52 127.463 ;
     RECT  142.8 127.449 142.92 127.463 ;
     RECT  148.2 127.449 148.32 127.463 ;
     RECT  153.6 127.449 153.72 127.463 ;
     RECT  159 127.449 159.12 127.463 ;
     RECT  164.4 127.449 164.52 127.463 ;
     RECT  169.8 127.449 169.92 127.463 ;
     RECT  175.2 127.449 175.32 127.463 ;
     RECT  180.6 127.449 180.72 127.463 ;
     RECT  186 127.449 186.12 127.463 ;
     RECT  191.4 127.449 191.52 127.463 ;
     RECT  196.8 127.449 196.92 127.463 ;
     RECT  202.2 127.449 202.32 127.463 ;
     RECT  207.6 127.449 207.72 127.463 ;
     RECT  213 127.449 213.12 127.463 ;
     RECT  160.416 129.552 160.44 129.587 ;
     RECT  4.296 5.077 5.52 6.805 ;
     RECT  211.752 9.061 213 9.349 ;
     RECT  211.752 9.349 212.88 10.213 ;
     RECT  214.728 11.411 216 17.603 ;
     RECT  3.288 12.517 4.272 13.813 ;
     RECT  6.072 13.621 7.344 14.533 ;
     RECT  6.168 14.533 7.344 14.773 ;
     RECT  18.912 15.925 19.92 19.333 ;
     RECT  8.112 16.501 9.216 18.133 ;
     RECT  26.184 17.077 27.504 19.523 ;
     RECT  214.632 17.603 216 23.797 ;
     RECT  19.704 19.379 20.832 23.893 ;
     RECT  21.144 19.523 21.624 20.485 ;
     RECT  21.672 20.629 22.656 21.299 ;
     RECT  16.392 21.061 17.616 22.165 ;
     RECT  22.68 21.155 24 22.309 ;
     RECT  21.096 21.299 22.656 21.973 ;
     RECT  30.744 21.541 31.872 22.165 ;
     RECT  25.032 21.637 26.16 22.645 ;
     RECT  21.096 21.973 22.416 23.411 ;
     RECT  16.392 22.165 17.424 24.133 ;
     RECT  30.84 22.165 31.872 22.787 ;
     RECT  22.728 22.309 24 22.549 ;
     RECT  33.672 22.453 34.8 22.741 ;
     RECT  22.776 22.549 24 22.741 ;
     RECT  24.696 22.739 25.92 23.987 ;
     RECT  33.672 22.741 34.704 23.267 ;
     RECT  30.024 22.787 31.872 23.125 ;
     RECT  30.024 23.125 31.056 23.171 ;
     RECT  29.928 23.171 31.056 23.267 ;
     RECT  29.928 23.267 31.152 25.235 ;
     RECT  33.672 23.267 34.8 25.429 ;
     RECT  82.104 23.317 83.4 25.475 ;
     RECT  20.856 23.411 22.416 24.277 ;
     RECT  215.016 23.797 216 31.379 ;
     RECT  28.08 23.843 29.4 24.037 ;
     RECT  24.696 23.987 25.944 24.373 ;
     RECT  210.864 23.987 211.824 25.045 ;
     RECT  213.864 23.987 214.992 28.403 ;
     RECT  27.912 24.037 29.4 24.659 ;
     RECT  20.856 24.277 22.176 24.757 ;
     RECT  22.728 24.371 24 25.475 ;
     RECT  24.696 24.373 26.208 24.659 ;
     RECT  20.856 24.757 22.128 25.091 ;
     RECT  200.376 24.949 201.504 29.365 ;
     RECT  20.856 25.091 22.08 25.141 ;
     RECT  20.904 25.141 22.08 25.765 ;
     RECT  11.304 25.189 12.432 29.029 ;
     RECT  29.712 25.235 31.152 25.715 ;
     RECT  33.816 25.429 34.8 25.571 ;
     RECT  22.68 25.475 24 26.773 ;
     RECT  22.776 26.773 24 27.637 ;
     RECT  198.264 27.109 199.728 29.699 ;
     RECT  22.824 27.637 24 28.211 ;
     RECT  22.776 28.211 24 30.419 ;
     RECT  213.72 28.403 214.992 31.379 ;
     RECT  22.68 30.419 24 32.051 ;
     RECT  213.72 31.379 216 31.861 ;
     RECT  213.72 31.861 214.944 37.667 ;
     RECT  214.968 31.861 216 32.965 ;
     RECT  22.632 32.051 24 36.179 ;
     RECT  202.872 32.437 204.288 35.845 ;
     RECT  205.08 32.965 206.352 37.429 ;
     RECT  206.376 32.965 207.6 39.733 ;
     RECT  198.408 35.461 199.824 35.651 ;
     RECT  203.208 35.845 204.288 37.573 ;
     RECT  210.264 36.707 211.68 38.147 ;
     RECT  204.264 39.251 205.584 39.299 ;
     RECT  204.264 39.299 206.304 40.405 ;
     RECT  197.112 40.307 198.096 45.445 ;
     RECT  204.264 40.405 205.728 41.317 ;
     RECT  204.6 41.317 205.728 41.939 ;
     RECT  206.376 41.411 207.36 41.891 ;
     RECT  206.376 41.891 207.6 67.669 ;
     RECT  204.408 41.939 205.728 42.227 ;
     RECT  199.8 49.619 201.024 52.357 ;
     RECT  199.8 52.357 200.784 56.483 ;
     RECT  198.072 53.315 198.12 54.421 ;
     RECT  2.712 57.635 3.792 58.499 ;
     RECT  2.712 58.499 3.984 60.949 ;
     RECT  9.528 58.739 10.656 60.373 ;
     RECT  201.984 58.739 202.08 60.133 ;
     RECT  15.24 59.747 16.704 61.477 ;
     RECT  8.112 59.891 9.456 62.195 ;
     RECT  13.992 60.563 15.216 61.525 ;
     RECT  15.672 61.477 16.704 62.101 ;
     RECT  8.112 62.195 10.08 62.341 ;
     RECT  8.472 62.341 10.08 63.157 ;
     RECT  204.072 66.373 205.248 67.571 ;
     RECT  205.272 66.373 206.352 68.915 ;
     RECT  202.512 68.435 203.52 69.539 ;
     RECT  200.376 71.555 201.456 75.395 ;
     RECT  214.056 75.781 215.184 76.933 ;
     RECT  214.104 76.933 215.184 80.629 ;
     RECT  22.488 81.205 24 84.613 ;
     RECT  211.824 83.747 212.112 85.141 ;
     RECT  22.536 84.613 24 85.237 ;
     RECT  22.584 85.237 24 88.213 ;
     RECT  214.296 86.051 215.28 94.595 ;
     RECT  22.632 88.213 24 94.885 ;
     RECT  214.296 94.595 215.424 95.795 ;
     RECT  22.68 94.885 24 98.341 ;
     RECT  214.056 95.795 215.424 96.373 ;
     RECT  214.056 96.373 215.088 96.805 ;
     RECT  22.728 98.341 24 98.485 ;
     RECT  22.824 98.485 24 101.173 ;
     RECT  72.912 100.837 74.256 101.413 ;
     RECT  35.544 100.981 37.008 101.171 ;
     RECT  35.544 101.171 37.056 101.989 ;
     RECT  23.016 101.173 24 101.413 ;
     RECT  27.384 101.173 28.752 101.749 ;
     RECT  43.704 101.173 45.024 101.605 ;
     RECT  53.592 101.365 54.816 101.507 ;
     RECT  58.632 101.365 60 102.229 ;
     RECT  60.024 101.365 61.152 102.805 ;
     RECT  31.656 101.413 33.024 103.189 ;
     RECT  33.336 101.413 34.704 101.653 ;
     RECT  73.224 101.413 74.256 105.637 ;
     RECT  76.776 101.413 78 102.565 ;
     RECT  78.408 101.413 79.776 103.765 ;
     RECT  20.424 101.507 21.552 101.843 ;
     RECT  43.992 101.605 45.024 101.749 ;
     RECT  33.336 101.653 34.656 101.941 ;
     RECT  46.68 101.653 48.048 101.843 ;
     RECT  29.832 101.701 31.344 102.469 ;
     RECT  51.312 101.749 52.56 101.797 ;
     RECT  48.072 101.795 49.032 101.843 ;
     RECT  51.312 101.797 52.32 101.987 ;
     RECT  20.424 101.843 21.888 102.851 ;
     RECT  49.008 101.843 49.032 103.045 ;
     RECT  62.112 101.845 63.504 103.141 ;
     RECT  27.768 101.987 28.752 102.563 ;
     RECT  51.312 101.987 52.56 107.509 ;
     RECT  36.072 101.989 37.056 102.469 ;
     RECT  63.528 101.989 64.608 103.283 ;
     RECT  87.144 101.989 88.416 106.165 ;
     RECT  33.336 102.131 34.56 103.237 ;
     RECT  25.8 102.277 27.264 104.101 ;
     RECT  89.112 102.277 90.576 103.045 ;
     RECT  29.832 102.469 30.816 102.997 ;
     RECT  27.384 102.563 28.752 103.957 ;
     RECT  76.776 102.565 77.856 103.811 ;
     RECT  84.888 102.565 86.208 103.141 ;
     RECT  20.424 102.851 22.32 103.045 ;
     RECT  70.896 102.947 71.856 102.949 ;
     RECT  41.64 102.949 42.72 107.797 ;
     RECT  70.392 102.949 71.856 105.301 ;
     RECT  21.288 103.045 22.32 104.869 ;
     RECT  65.064 103.045 66.384 107.797 ;
     RECT  89.112 103.045 90.528 103.573 ;
     RECT  24.6 103.091 25.584 104.389 ;
     RECT  37.32 103.141 38.64 107.219 ;
     RECT  62.472 103.141 63.504 103.283 ;
     RECT  85.128 103.141 86.208 105.397 ;
     RECT  33.384 103.237 34.56 103.333 ;
     RECT  62.472 103.283 64.608 103.717 ;
     RECT  31.896 103.331 33.024 104.339 ;
     RECT  53.064 103.331 53.16 104.677 ;
     RECT  91.272 103.333 92.4 104.485 ;
     RECT  80.424 103.477 81.696 104.005 ;
     RECT  89.352 103.573 90.528 108.709 ;
     RECT  74.712 103.669 76.08 104.099 ;
     RECT  63.288 103.717 64.608 104.531 ;
     RECT  94.512 103.717 95.76 107.605 ;
     RECT  78.408 103.765 79.488 106.021 ;
     RECT  29.832 103.811 30.816 105.781 ;
     RECT  76.776 103.811 77.904 104.579 ;
     RECT  62.112 103.907 63.264 104.965 ;
     RECT  27.72 103.957 28.752 109.379 ;
     RECT  80.616 104.005 81.696 107.221 ;
     RECT  79.512 104.051 80.592 107.267 ;
     RECT  26.136 104.101 27.264 107.941 ;
     RECT  31.896 104.339 33.12 106.261 ;
     RECT  63.288 104.531 64.656 107.267 ;
     RECT  76.728 104.579 77.904 106.837 ;
     RECT  21.192 105.059 22.32 107.221 ;
     RECT  96.696 105.157 97.968 107.747 ;
     RECT  70.392 105.301 71.616 105.397 ;
     RECT  57.048 105.397 58.56 105.445 ;
     RECT  70.392 105.397 71.52 107.651 ;
     RECT  85.176 105.397 86.208 106.501 ;
     RECT  57.192 105.445 58.56 106.453 ;
     RECT  97.992 105.685 99.024 107.747 ;
     RECT  55.296 105.875 55.488 106.549 ;
     RECT  78.504 106.021 79.488 108.371 ;
     RECT  86.232 106.211 87.744 106.547 ;
     RECT  31.896 106.261 33.072 110.867 ;
     RECT  38.664 106.451 39.648 107.219 ;
     RECT  53.304 106.549 54.432 107.653 ;
     RECT  54.456 106.549 55.488 107.125 ;
     RECT  60.312 106.595 61.536 108.085 ;
     RECT  36.12 106.739 37.2 108.325 ;
     RECT  76.92 106.837 77.904 111.731 ;
     RECT  39.6 107.219 39.648 107.989 ;
     RECT  90.552 107.219 91.632 108.325 ;
     RECT  20.424 107.267 21.504 108.179 ;
     RECT  63.288 107.267 64.752 108.805 ;
     RECT  79.512 107.267 80.832 108.371 ;
     RECT  94.632 107.605 95.76 107.749 ;
     RECT  51.312 107.651 52.56 108.709 ;
     RECT  70.296 107.651 71.52 107.795 ;
     RECT  33.24 107.699 34.704 108.853 ;
     RECT  98.832 107.747 99.024 108.085 ;
     RECT  94.632 107.749 95.616 108.325 ;
     RECT  10.2 107.795 11.184 112.069 ;
     RECT  70.296 107.795 71.712 109.093 ;
     RECT  95.64 107.795 96.672 108.805 ;
     RECT  65.256 107.797 66.384 110.771 ;
     RECT  42.264 107.843 43.68 108.853 ;
     RECT  26.136 107.941 27.12 108.851 ;
     RECT  20.328 108.179 21.504 109.957 ;
     RECT  53.448 108.275 54.432 111.061 ;
     RECT  67.992 108.277 69.456 109.141 ;
     RECT  74.856 108.277 76.32 108.661 ;
     RECT  86.616 108.325 87.744 108.805 ;
     RECT  21.528 108.371 22.896 109.955 ;
     RECT  78.504 108.371 80.832 108.805 ;
     RECT  91.224 108.371 92.352 109.187 ;
     RECT  49.968 108.563 50.16 108.565 ;
     RECT  49.176 108.565 50.16 109.331 ;
     RECT  75.192 108.661 76.32 112.933 ;
     RECT  36.12 108.707 37.2 111.491 ;
     RECT  51.528 108.709 52.56 110.437 ;
     RECT  37.32 108.805 38.64 109.525 ;
     RECT  63.576 108.805 64.752 108.995 ;
     RECT  78.504 108.805 79.824 109.331 ;
     RECT  79.848 108.805 80.832 109.285 ;
     RECT  25.752 108.851 27.12 110.005 ;
     RECT  62.52 108.851 63.552 111.109 ;
     RECT  94.728 108.851 95.712 109.427 ;
     RECT  33.336 108.853 34.704 109.285 ;
     RECT  42.264 108.853 43.296 108.995 ;
     RECT  89.112 108.899 90.288 109.957 ;
     RECT  42.264 108.995 43.584 109.333 ;
     RECT  63.576 108.995 65.232 109.957 ;
     RECT  68.424 109.141 69.456 109.909 ;
     RECT  91.224 109.187 92.64 110.389 ;
     RECT  33.336 109.285 34.32 110.389 ;
     RECT  49.128 109.331 50.16 109.859 ;
     RECT  78.504 109.331 80.112 110.485 ;
     RECT  42.312 109.333 43.584 110.147 ;
     RECT  27.576 109.379 28.752 110.485 ;
     RECT  85.512 109.427 86.592 110.627 ;
     RECT  94.728 109.427 96.672 110.533 ;
     RECT  43.608 109.571 44.88 112.643 ;
     RECT  96.696 109.765 97.728 110.579 ;
     RECT  97.752 109.765 98.832 110.579 ;
     RECT  68.424 109.909 69.408 112.309 ;
     RECT  21.528 109.955 23.712 110.003 ;
     RECT  63.816 109.957 65.232 110.437 ;
     RECT  21.144 110.003 23.712 111.205 ;
     RECT  58.92 110.003 60 114.611 ;
     RECT  25.752 110.005 26.832 111.109 ;
     RECT  42.12 110.147 43.584 113.653 ;
     RECT  80.904 110.147 82.032 115.763 ;
     RECT  91.272 110.389 92.64 112.021 ;
     RECT  70.728 110.483 71.712 111.589 ;
     RECT  27.576 110.485 28.656 111.589 ;
     RECT  94.728 110.533 95.712 112.069 ;
     RECT  57.912 110.579 58.896 112.261 ;
     RECT  84.984 110.627 86.592 111.203 ;
     RECT  63.576 110.675 64.656 114.419 ;
     RECT  65.112 110.771 66.384 113.077 ;
     RECT  31.896 110.867 33.12 111.539 ;
     RECT  73.368 110.915 74.448 112.405 ;
     RECT  78.696 110.915 79.728 113.555 ;
     RECT  37.272 111.107 38.304 113.267 ;
     RECT  19.32 111.203 20.304 114.611 ;
     RECT  84.024 111.203 86.592 111.299 ;
     RECT  21.144 111.205 22.464 112.499 ;
     RECT  22.488 111.205 23.712 111.589 ;
     RECT  83.928 111.299 86.592 111.925 ;
     RECT  54.456 111.347 55.488 113.893 ;
     RECT  62.52 111.347 63.552 114.373 ;
     RECT  36.12 111.491 37.248 111.923 ;
     RECT  92.952 111.491 94.032 112.931 ;
     RECT  31.896 111.539 33.312 113.845 ;
     RECT  86.616 111.635 87.744 111.971 ;
     RECT  76.632 111.731 77.904 113.315 ;
     RECT  82.056 111.779 83.232 113.845 ;
     RECT  35.928 111.923 37.248 113.221 ;
     RECT  51.432 111.923 52.416 114.035 ;
     RECT  83.928 111.925 86.4 112.069 ;
     RECT  70.296 111.971 71.28 114.995 ;
     RECT  86.568 111.971 87.744 113.795 ;
     RECT  91.464 112.021 92.64 112.117 ;
     RECT  90.312 112.067 91.44 115.811 ;
     RECT  83.928 112.069 85.248 115.429 ;
     RECT  85.272 112.069 86.4 115.475 ;
     RECT  50.448 112.115 50.544 112.117 ;
     RECT  48.984 112.117 50.544 112.597 ;
     RECT  91.464 112.117 92.592 113.459 ;
     RECT  20.76 112.499 22.464 113.605 ;
     RECT  22.488 112.499 23.568 114.661 ;
     RECT  49.032 112.597 50.544 113.219 ;
     RECT  69.24 112.787 70.272 116.387 ;
     RECT  47.256 112.931 48.336 115.669 ;
     RECT  53.448 112.931 54.432 117.347 ;
     RECT  92.952 112.931 94.2 114.517 ;
     RECT  65.256 113.077 66.384 117.925 ;
     RECT  94.728 113.171 96.048 115.379 ;
     RECT  48.36 113.219 50.544 113.605 ;
     RECT  35.928 113.221 36.912 113.701 ;
     RECT  37.128 113.267 38.304 113.555 ;
     RECT  76.536 113.315 77.904 114.611 ;
     RECT  91.464 113.459 92.64 118.019 ;
     RECT  36.936 113.555 38.304 114.707 ;
     RECT  78.6 113.555 79.728 114.035 ;
     RECT  20.904 113.605 22.464 113.845 ;
     RECT  48.36 113.605 49.44 114.517 ;
     RECT  49.464 113.605 50.544 118.163 ;
     RECT  42.504 113.653 43.584 114.275 ;
     RECT  86.424 113.795 87.744 116.339 ;
     RECT  21.144 113.845 22.464 114.901 ;
     RECT  51.432 114.035 52.464 115.187 ;
     RECT  78.6 114.035 80.112 116.483 ;
     RECT  68.184 114.227 69.216 116.341 ;
     RECT  42.12 114.275 43.584 114.899 ;
     RECT  29.976 114.419 31.2 115.379 ;
     RECT  63.48 114.419 64.656 116.389 ;
     RECT  11.688 114.611 12.72 115.187 ;
     RECT  58.536 114.611 60 115.669 ;
     RECT  73.56 114.611 74.976 118.067 ;
     RECT  77.808 114.611 77.904 116.005 ;
     RECT  10.2 114.659 11.28 116.195 ;
     RECT  22.488 114.661 23.472 115.717 ;
     RECT  36.936 114.707 38.4 117.443 ;
     RECT  43.392 114.899 43.584 114.901 ;
     RECT  21.288 114.901 22.464 115.043 ;
     RECT  70.296 114.995 71.328 117.397 ;
     RECT  21.144 115.043 22.464 115.139 ;
     RECT  11.64 115.187 12.72 118.595 ;
     RECT  32.04 115.187 33.216 116.293 ;
     RECT  48.36 115.187 49.44 117.589 ;
     RECT  51.432 115.187 52.896 115.475 ;
     RECT  38.904 115.235 39.888 117.589 ;
     RECT  35.208 115.427 36.432 116.483 ;
     RECT  51.432 115.475 53.424 116.101 ;
     RECT  25.752 115.619 26.736 116.435 ;
     RECT  58.776 115.669 60 116.915 ;
     RECT  13.944 115.763 14.976 116.339 ;
     RECT  56.712 115.763 57.84 117.349 ;
     RECT  80.664 115.763 82.032 118.643 ;
     RECT  71.352 115.859 72.48 117.539 ;
     RECT  60.216 115.907 61.536 118.019 ;
     RECT  22.488 116.051 23.472 116.819 ;
     RECT  51.912 116.101 53.424 118.835 ;
     RECT  62.232 116.147 63.456 118.019 ;
     RECT  13.944 116.339 15.264 117.443 ;
     RECT  33.24 116.339 34.272 116.915 ;
     RECT  82.2 116.339 83.4 118.739 ;
     RECT  68.904 116.387 70.272 118.019 ;
     RECT  24.792 116.435 26.736 116.821 ;
     RECT  35.112 116.483 36.432 116.915 ;
     RECT  54.456 116.627 55.488 117.347 ;
     RECT  22.464 116.819 23.472 117.397 ;
     RECT  24.792 116.821 25.776 118.019 ;
     RECT  16.44 116.915 17.664 117.779 ;
     RECT  33.24 116.915 34.704 119.219 ;
     RECT  46.632 116.915 47.952 117.443 ;
     RECT  58.776 116.915 60.192 118.019 ;
     RECT  20.904 117.397 22.416 118.595 ;
     RECT  22.44 117.397 23.472 118.787 ;
     RECT  70.296 117.397 71.28 118.021 ;
     RECT  36.936 117.443 38.832 118.165 ;
     RECT  41.784 117.539 42.768 117.875 ;
     RECT  71.304 117.539 72.48 119.219 ;
     RECT  48.456 117.589 49.44 118.691 ;
     RECT  38.904 117.731 40.2 121.381 ;
     RECT  16.44 117.779 17.76 118.019 ;
     RECT  65.256 117.925 66.336 118.595 ;
     RECT  4.824 118.019 5.904 119.171 ;
     RECT  8.424 118.019 9.552 118.595 ;
     RECT  40.512 118.019 41.76 119.219 ;
     RECT  73.56 118.067 75.072 118.595 ;
     RECT  37.608 118.165 38.832 119.219 ;
     RECT  70.296 118.307 71.28 118.595 ;
     RECT  3.624 118.595 4.752 119.171 ;
     RECT  5.928 118.595 7.152 119.171 ;
     RECT  8.424 118.595 9.096 119.509 ;
     RECT  61.536 118.595 61.68 119.123 ;
     RECT  80.664 118.643 82.176 118.739 ;
     RECT  22.44 118.787 23.904 119.171 ;
     RECT  35.112 118.931 35.256 120.085 ;
     RECT  27.192 119.029 28.272 119.651 ;
     RECT  61.536 119.123 61.8 120.085 ;
     RECT  28.296 119.219 29.4 121.571 ;
     RECT  26.76 119.651 28.272 120.085 ;
     RECT  26.76 120.085 27.888 120.323 ;
     RECT  60.552 120.085 61.8 122.389 ;
     RECT  15.336 120.613 16.512 122.003 ;
     RECT  16.536 120.613 17.904 122.003 ;
     RECT  49.992 120.613 51 123.061 ;
     RECT  29.088 121.571 29.4 121.957 ;
     RECT  33.528 121.619 34.8 122.003 ;
     RECT  213.768 121.669 214.992 123.251 ;
     RECT  3.144 121.909 4.56 122.485 ;
     RECT  4.584 121.909 6.048 123.107 ;
     RECT  32.136 121.909 33.504 122.003 ;
     RECT  10.296 121.957 11.616 122.101 ;
     RECT  52.248 121.957 53.424 122.771 ;
     RECT  17.136 122.003 17.904 122.485 ;
     RECT  10.584 122.101 11.616 122.579 ;
     RECT  59.352 122.485 60.528 124.547 ;
     RECT  17.16 122.771 18.6 123.491 ;
     RECT  40.512 123.205 41.52 125.651 ;
     RECT  41.544 123.205 42.768 123.251 ;
     RECT  54.168 123.253 55.488 123.685 ;
     RECT  49.56 123.827 50.688 124.019 ;
     RECT  49.56 124.019 51 125.077 ;
     RECT  49.56 125.077 50.832 125.555 ;
     RECT  49.56 125.555 51 126.035 ;
  END
END ot_hgi_qdq_nw_program_leaf
END LIBRARY
